VERSION 5.8 ;
BUSBITCHARS "[]" ;
DIVIDERCHAR "/" ;
UNITS
    DATABASE MICRONS 1000 ;
END UNITS

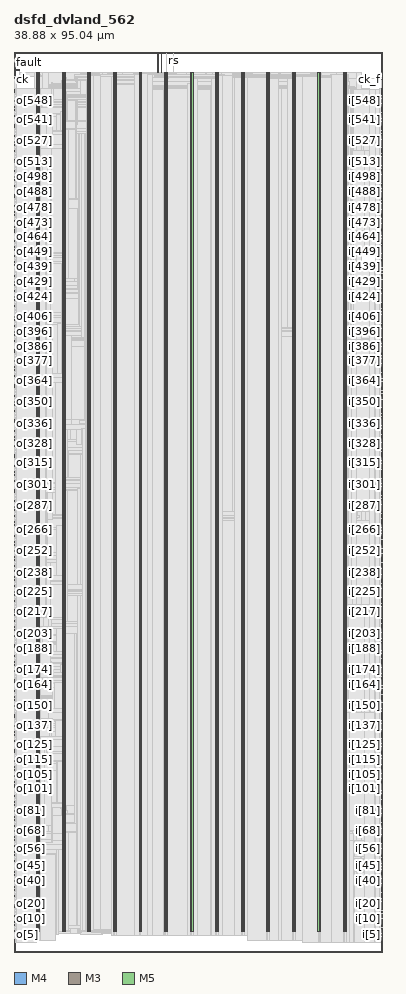
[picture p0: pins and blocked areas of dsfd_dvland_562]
MACRO dsfd_dvland_562
  FOREIGN dsfd_dvland_562 0 0 ;
  CLASS BLOCK ;
  SIZE 38.88 BY 95.04 ;
  PIN ck
    DIRECTION INPUT ;
    USE SIGNAL ;
    PORT
      LAYER M4 ;
        RECT  0 92.112 0.084 92.136 ;
    END
  END ck
  PIN ck_f
    DIRECTION INPUT ;
    USE SIGNAL ;
    PORT
      LAYER M4 ;
        RECT  38.796 92.112 38.88 92.136 ;
    END
  END ck_f
  PIN fault
    DIRECTION OUTPUT ;
    USE SIGNAL ;
    PORT
      LAYER M4 ;
        RECT  0 93.12 0.084 93.144 ;
    END
    PORT
      LAYER M4 ;
        RECT  0.06 93.12 0.569 93.144 ;
    END
  END fault
  PIN i[0]
    DIRECTION INPUT ;
    USE SIGNAL ;
    PORT
      LAYER M4 ;
        RECT  38.796 1.056 38.88 1.08 ;
    END
  END i[0]
  PIN i[100]
    DIRECTION INPUT ;
    USE SIGNAL ;
    PORT
      LAYER M4 ;
        RECT  38.796 17.136 38.88 17.16 ;
    END
  END i[100]
  PIN i[101]
    DIRECTION INPUT ;
    USE SIGNAL ;
    PORT
      LAYER M4 ;
        RECT  38.796 17.28 38.88 17.304 ;
    END
  END i[101]
  PIN i[102]
    DIRECTION INPUT ;
    USE SIGNAL ;
    PORT
      LAYER M4 ;
        RECT  38.796 17.424 38.88 17.448 ;
    END
  END i[102]
  PIN i[103]
    DIRECTION INPUT ;
    USE SIGNAL ;
    PORT
      LAYER M4 ;
        RECT  38.796 17.616 38.88 17.64 ;
    END
  END i[103]
  PIN i[104]
    DIRECTION INPUT ;
    USE SIGNAL ;
    PORT
      LAYER M4 ;
        RECT  38.796 17.76 38.88 17.784 ;
    END
  END i[104]
  PIN i[105]
    DIRECTION INPUT ;
    USE SIGNAL ;
    PORT
      LAYER M4 ;
        RECT  38.796 17.952 38.88 17.976 ;
    END
  END i[105]
  PIN i[106]
    DIRECTION INPUT ;
    USE SIGNAL ;
    PORT
      LAYER M4 ;
        RECT  38.796 18.096 38.88 18.12 ;
    END
  END i[106]
  PIN i[107]
    DIRECTION INPUT ;
    USE SIGNAL ;
    PORT
      LAYER M4 ;
        RECT  38.796 18.24 38.88 18.264 ;
    END
  END i[107]
  PIN i[108]
    DIRECTION INPUT ;
    USE SIGNAL ;
    PORT
      LAYER M4 ;
        RECT  38.796 18.432 38.88 18.456 ;
    END
  END i[108]
  PIN i[109]
    DIRECTION INPUT ;
    USE SIGNAL ;
    PORT
      LAYER M4 ;
        RECT  38.796 18.576 38.88 18.6 ;
    END
  END i[109]
  PIN i[10]
    DIRECTION INPUT ;
    USE SIGNAL ;
    PORT
      LAYER M4 ;
        RECT  38.796 2.688 38.88 2.712 ;
    END
  END i[10]
  PIN i[110]
    DIRECTION INPUT ;
    USE SIGNAL ;
    PORT
      LAYER M4 ;
        RECT  38.796 18.72 38.88 18.744 ;
    END
  END i[110]
  PIN i[111]
    DIRECTION INPUT ;
    USE SIGNAL ;
    PORT
      LAYER M4 ;
        RECT  38.796 18.912 38.88 18.936 ;
    END
  END i[111]
  PIN i[112]
    DIRECTION INPUT ;
    USE SIGNAL ;
    PORT
      LAYER M4 ;
        RECT  38.796 19.056 38.88 19.08 ;
    END
  END i[112]
  PIN i[113]
    DIRECTION INPUT ;
    USE SIGNAL ;
    PORT
      LAYER M4 ;
        RECT  38.796 19.2 38.88 19.224 ;
    END
  END i[113]
  PIN i[114]
    DIRECTION INPUT ;
    USE SIGNAL ;
    PORT
      LAYER M4 ;
        RECT  38.796 19.392 38.88 19.416 ;
    END
  END i[114]
  PIN i[115]
    DIRECTION INPUT ;
    USE SIGNAL ;
    PORT
      LAYER M4 ;
        RECT  38.796 19.536 38.88 19.56 ;
    END
  END i[115]
  PIN i[116]
    DIRECTION INPUT ;
    USE SIGNAL ;
    PORT
      LAYER M4 ;
        RECT  38.796 19.68 38.88 19.704 ;
    END
  END i[116]
  PIN i[117]
    DIRECTION INPUT ;
    USE SIGNAL ;
    PORT
      LAYER M4 ;
        RECT  38.796 19.872 38.88 19.896 ;
    END
  END i[117]
  PIN i[118]
    DIRECTION INPUT ;
    USE SIGNAL ;
    PORT
      LAYER M4 ;
        RECT  38.796 20.016 38.88 20.04 ;
    END
  END i[118]
  PIN i[119]
    DIRECTION INPUT ;
    USE SIGNAL ;
    PORT
      LAYER M4 ;
        RECT  38.796 20.16 38.88 20.184 ;
    END
  END i[119]
  PIN i[11]
    DIRECTION INPUT ;
    USE SIGNAL ;
    PORT
      LAYER M4 ;
        RECT  38.796 2.832 38.88 2.856 ;
    END
  END i[11]
  PIN i[120]
    DIRECTION INPUT ;
    USE SIGNAL ;
    PORT
      LAYER M4 ;
        RECT  38.796 20.352 38.88 20.376 ;
    END
  END i[120]
  PIN i[121]
    DIRECTION INPUT ;
    USE SIGNAL ;
    PORT
      LAYER M4 ;
        RECT  38.796 20.496 38.88 20.52 ;
    END
  END i[121]
  PIN i[122]
    DIRECTION INPUT ;
    USE SIGNAL ;
    PORT
      LAYER M4 ;
        RECT  38.796 20.64 38.88 20.664 ;
    END
  END i[122]
  PIN i[123]
    DIRECTION INPUT ;
    USE SIGNAL ;
    PORT
      LAYER M4 ;
        RECT  38.796 20.832 38.88 20.856 ;
    END
  END i[123]
  PIN i[124]
    DIRECTION INPUT ;
    USE SIGNAL ;
    PORT
      LAYER M4 ;
        RECT  38.796 20.976 38.88 21 ;
    END
  END i[124]
  PIN i[125]
    DIRECTION INPUT ;
    USE SIGNAL ;
    PORT
      LAYER M4 ;
        RECT  38.796 21.12 38.88 21.144 ;
    END
  END i[125]
  PIN i[126]
    DIRECTION INPUT ;
    USE SIGNAL ;
    PORT
      LAYER M4 ;
        RECT  38.796 21.312 38.88 21.336 ;
    END
  END i[126]
  PIN i[127]
    DIRECTION INPUT ;
    USE SIGNAL ;
    PORT
      LAYER M4 ;
        RECT  38.796 21.456 38.88 21.48 ;
    END
  END i[127]
  PIN i[128]
    DIRECTION INPUT ;
    USE SIGNAL ;
    PORT
      LAYER M4 ;
        RECT  38.796 21.6 38.88 21.624 ;
    END
  END i[128]
  PIN i[129]
    DIRECTION INPUT ;
    USE SIGNAL ;
    PORT
      LAYER M4 ;
        RECT  38.796 21.792 38.88 21.816 ;
    END
  END i[129]
  PIN i[12]
    DIRECTION INPUT ;
    USE SIGNAL ;
    PORT
      LAYER M4 ;
        RECT  38.796 2.976 38.88 3 ;
    END
  END i[12]
  PIN i[130]
    DIRECTION INPUT ;
    USE SIGNAL ;
    PORT
      LAYER M4 ;
        RECT  38.796 21.936 38.88 21.96 ;
    END
  END i[130]
  PIN i[131]
    DIRECTION INPUT ;
    USE SIGNAL ;
    PORT
      LAYER M4 ;
        RECT  38.796 22.08 38.88 22.104 ;
    END
  END i[131]
  PIN i[132]
    DIRECTION INPUT ;
    USE SIGNAL ;
    PORT
      LAYER M4 ;
        RECT  38.796 22.272 38.88 22.296 ;
    END
  END i[132]
  PIN i[133]
    DIRECTION INPUT ;
    USE SIGNAL ;
    PORT
      LAYER M4 ;
        RECT  38.796 22.416 38.88 22.44 ;
    END
  END i[133]
  PIN i[134]
    DIRECTION INPUT ;
    USE SIGNAL ;
    PORT
      LAYER M4 ;
        RECT  38.796 22.608 38.88 22.632 ;
    END
  END i[134]
  PIN i[135]
    DIRECTION INPUT ;
    USE SIGNAL ;
    PORT
      LAYER M4 ;
        RECT  38.796 22.752 38.88 22.776 ;
    END
  END i[135]
  PIN i[136]
    DIRECTION INPUT ;
    USE SIGNAL ;
    PORT
      LAYER M4 ;
        RECT  38.796 22.896 38.88 22.92 ;
    END
  END i[136]
  PIN i[137]
    DIRECTION INPUT ;
    USE SIGNAL ;
    PORT
      LAYER M4 ;
        RECT  38.796 23.088 38.88 23.112 ;
    END
  END i[137]
  PIN i[138]
    DIRECTION INPUT ;
    USE SIGNAL ;
    PORT
      LAYER M4 ;
        RECT  38.796 23.232 38.88 23.256 ;
    END
  END i[138]
  PIN i[139]
    DIRECTION INPUT ;
    USE SIGNAL ;
    PORT
      LAYER M4 ;
        RECT  38.796 23.376 38.88 23.4 ;
    END
  END i[139]
  PIN i[13]
    DIRECTION INPUT ;
    USE SIGNAL ;
    PORT
      LAYER M4 ;
        RECT  38.796 3.168 38.88 3.192 ;
    END
  END i[13]
  PIN i[140]
    DIRECTION INPUT ;
    USE SIGNAL ;
    PORT
      LAYER M4 ;
        RECT  38.796 23.568 38.88 23.592 ;
    END
  END i[140]
  PIN i[141]
    DIRECTION INPUT ;
    USE SIGNAL ;
    PORT
      LAYER M4 ;
        RECT  38.796 23.712 38.88 23.736 ;
    END
  END i[141]
  PIN i[142]
    DIRECTION INPUT ;
    USE SIGNAL ;
    PORT
      LAYER M4 ;
        RECT  38.796 23.856 38.88 23.88 ;
    END
  END i[142]
  PIN i[143]
    DIRECTION INPUT ;
    USE SIGNAL ;
    PORT
      LAYER M4 ;
        RECT  38.796 24.048 38.88 24.072 ;
    END
  END i[143]
  PIN i[144]
    DIRECTION INPUT ;
    USE SIGNAL ;
    PORT
      LAYER M4 ;
        RECT  38.796 24.192 38.88 24.216 ;
    END
  END i[144]
  PIN i[145]
    DIRECTION INPUT ;
    USE SIGNAL ;
    PORT
      LAYER M4 ;
        RECT  38.796 24.336 38.88 24.36 ;
    END
  END i[145]
  PIN i[146]
    DIRECTION INPUT ;
    USE SIGNAL ;
    PORT
      LAYER M4 ;
        RECT  38.796 24.528 38.88 24.552 ;
    END
  END i[146]
  PIN i[147]
    DIRECTION INPUT ;
    USE SIGNAL ;
    PORT
      LAYER M4 ;
        RECT  38.796 24.672 38.88 24.696 ;
    END
  END i[147]
  PIN i[148]
    DIRECTION INPUT ;
    USE SIGNAL ;
    PORT
      LAYER M4 ;
        RECT  38.796 24.816 38.88 24.84 ;
    END
  END i[148]
  PIN i[149]
    DIRECTION INPUT ;
    USE SIGNAL ;
    PORT
      LAYER M4 ;
        RECT  38.796 25.008 38.88 25.032 ;
    END
  END i[149]
  PIN i[14]
    DIRECTION INPUT ;
    USE SIGNAL ;
    PORT
      LAYER M4 ;
        RECT  38.796 3.312 38.88 3.336 ;
    END
  END i[14]
  PIN i[150]
    DIRECTION INPUT ;
    USE SIGNAL ;
    PORT
      LAYER M4 ;
        RECT  38.796 25.152 38.88 25.176 ;
    END
  END i[150]
  PIN i[151]
    DIRECTION INPUT ;
    USE SIGNAL ;
    PORT
      LAYER M4 ;
        RECT  38.796 25.296 38.88 25.32 ;
    END
  END i[151]
  PIN i[152]
    DIRECTION INPUT ;
    USE SIGNAL ;
    PORT
      LAYER M4 ;
        RECT  38.796 25.488 38.88 25.512 ;
    END
  END i[152]
  PIN i[153]
    DIRECTION INPUT ;
    USE SIGNAL ;
    PORT
      LAYER M4 ;
        RECT  38.796 25.632 38.88 25.656 ;
    END
  END i[153]
  PIN i[154]
    DIRECTION INPUT ;
    USE SIGNAL ;
    PORT
      LAYER M4 ;
        RECT  38.796 25.776 38.88 25.8 ;
    END
  END i[154]
  PIN i[155]
    DIRECTION INPUT ;
    USE SIGNAL ;
    PORT
      LAYER M4 ;
        RECT  38.796 25.968 38.88 25.992 ;
    END
  END i[155]
  PIN i[156]
    DIRECTION INPUT ;
    USE SIGNAL ;
    PORT
      LAYER M4 ;
        RECT  38.796 26.112 38.88 26.136 ;
    END
  END i[156]
  PIN i[157]
    DIRECTION INPUT ;
    USE SIGNAL ;
    PORT
      LAYER M4 ;
        RECT  38.796 26.256 38.88 26.28 ;
    END
  END i[157]
  PIN i[158]
    DIRECTION INPUT ;
    USE SIGNAL ;
    PORT
      LAYER M4 ;
        RECT  38.796 26.448 38.88 26.472 ;
    END
  END i[158]
  PIN i[159]
    DIRECTION INPUT ;
    USE SIGNAL ;
    PORT
      LAYER M4 ;
        RECT  38.796 26.592 38.88 26.616 ;
    END
  END i[159]
  PIN i[15]
    DIRECTION INPUT ;
    USE SIGNAL ;
    PORT
      LAYER M4 ;
        RECT  38.796 3.456 38.88 3.48 ;
    END
  END i[15]
  PIN i[160]
    DIRECTION INPUT ;
    USE SIGNAL ;
    PORT
      LAYER M4 ;
        RECT  38.796 26.736 38.88 26.76 ;
    END
  END i[160]
  PIN i[161]
    DIRECTION INPUT ;
    USE SIGNAL ;
    PORT
      LAYER M4 ;
        RECT  38.796 26.928 38.88 26.952 ;
    END
  END i[161]
  PIN i[162]
    DIRECTION INPUT ;
    USE SIGNAL ;
    PORT
      LAYER M4 ;
        RECT  38.796 27.072 38.88 27.096 ;
    END
  END i[162]
  PIN i[163]
    DIRECTION INPUT ;
    USE SIGNAL ;
    PORT
      LAYER M4 ;
        RECT  38.796 27.264 38.88 27.288 ;
    END
  END i[163]
  PIN i[164]
    DIRECTION INPUT ;
    USE SIGNAL ;
    PORT
      LAYER M4 ;
        RECT  38.796 27.408 38.88 27.432 ;
    END
  END i[164]
  PIN i[165]
    DIRECTION INPUT ;
    USE SIGNAL ;
    PORT
      LAYER M4 ;
        RECT  38.796 27.552 38.88 27.576 ;
    END
  END i[165]
  PIN i[166]
    DIRECTION INPUT ;
    USE SIGNAL ;
    PORT
      LAYER M4 ;
        RECT  38.796 27.744 38.88 27.768 ;
    END
  END i[166]
  PIN i[167]
    DIRECTION INPUT ;
    USE SIGNAL ;
    PORT
      LAYER M4 ;
        RECT  38.796 27.888 38.88 27.912 ;
    END
  END i[167]
  PIN i[168]
    DIRECTION INPUT ;
    USE SIGNAL ;
    PORT
      LAYER M4 ;
        RECT  38.796 28.032 38.88 28.056 ;
    END
  END i[168]
  PIN i[169]
    DIRECTION INPUT ;
    USE SIGNAL ;
    PORT
      LAYER M4 ;
        RECT  38.796 28.224 38.88 28.248 ;
    END
  END i[169]
  PIN i[16]
    DIRECTION INPUT ;
    USE SIGNAL ;
    PORT
      LAYER M4 ;
        RECT  38.796 3.648 38.88 3.672 ;
    END
  END i[16]
  PIN i[170]
    DIRECTION INPUT ;
    USE SIGNAL ;
    PORT
      LAYER M4 ;
        RECT  38.796 28.368 38.88 28.392 ;
    END
  END i[170]
  PIN i[171]
    DIRECTION INPUT ;
    USE SIGNAL ;
    PORT
      LAYER M4 ;
        RECT  38.796 28.512 38.88 28.536 ;
    END
  END i[171]
  PIN i[172]
    DIRECTION INPUT ;
    USE SIGNAL ;
    PORT
      LAYER M4 ;
        RECT  38.796 28.704 38.88 28.728 ;
    END
  END i[172]
  PIN i[173]
    DIRECTION INPUT ;
    USE SIGNAL ;
    PORT
      LAYER M4 ;
        RECT  38.796 28.848 38.88 28.872 ;
    END
  END i[173]
  PIN i[174]
    DIRECTION INPUT ;
    USE SIGNAL ;
    PORT
      LAYER M4 ;
        RECT  38.796 28.992 38.88 29.016 ;
    END
  END i[174]
  PIN i[175]
    DIRECTION INPUT ;
    USE SIGNAL ;
    PORT
      LAYER M4 ;
        RECT  38.796 29.184 38.88 29.208 ;
    END
  END i[175]
  PIN i[176]
    DIRECTION INPUT ;
    USE SIGNAL ;
    PORT
      LAYER M4 ;
        RECT  38.796 29.328 38.88 29.352 ;
    END
  END i[176]
  PIN i[177]
    DIRECTION INPUT ;
    USE SIGNAL ;
    PORT
      LAYER M4 ;
        RECT  38.796 29.472 38.88 29.496 ;
    END
  END i[177]
  PIN i[178]
    DIRECTION INPUT ;
    USE SIGNAL ;
    PORT
      LAYER M4 ;
        RECT  38.796 29.664 38.88 29.688 ;
    END
  END i[178]
  PIN i[179]
    DIRECTION INPUT ;
    USE SIGNAL ;
    PORT
      LAYER M4 ;
        RECT  38.796 29.808 38.88 29.832 ;
    END
  END i[179]
  PIN i[17]
    DIRECTION INPUT ;
    USE SIGNAL ;
    PORT
      LAYER M4 ;
        RECT  38.796 3.792 38.88 3.816 ;
    END
  END i[17]
  PIN i[180]
    DIRECTION INPUT ;
    USE SIGNAL ;
    PORT
      LAYER M4 ;
        RECT  38.796 29.952 38.88 29.976 ;
    END
  END i[180]
  PIN i[181]
    DIRECTION INPUT ;
    USE SIGNAL ;
    PORT
      LAYER M4 ;
        RECT  38.796 30.144 38.88 30.168 ;
    END
  END i[181]
  PIN i[182]
    DIRECTION INPUT ;
    USE SIGNAL ;
    PORT
      LAYER M4 ;
        RECT  38.796 30.288 38.88 30.312 ;
    END
  END i[182]
  PIN i[183]
    DIRECTION INPUT ;
    USE SIGNAL ;
    PORT
      LAYER M4 ;
        RECT  38.796 30.432 38.88 30.456 ;
    END
  END i[183]
  PIN i[184]
    DIRECTION INPUT ;
    USE SIGNAL ;
    PORT
      LAYER M4 ;
        RECT  38.796 30.624 38.88 30.648 ;
    END
  END i[184]
  PIN i[185]
    DIRECTION INPUT ;
    USE SIGNAL ;
    PORT
      LAYER M4 ;
        RECT  38.796 30.768 38.88 30.792 ;
    END
  END i[185]
  PIN i[186]
    DIRECTION INPUT ;
    USE SIGNAL ;
    PORT
      LAYER M4 ;
        RECT  38.796 30.912 38.88 30.936 ;
    END
  END i[186]
  PIN i[187]
    DIRECTION INPUT ;
    USE SIGNAL ;
    PORT
      LAYER M4 ;
        RECT  38.796 31.104 38.88 31.128 ;
    END
  END i[187]
  PIN i[188]
    DIRECTION INPUT ;
    USE SIGNAL ;
    PORT
      LAYER M4 ;
        RECT  38.796 31.248 38.88 31.272 ;
    END
  END i[188]
  PIN i[189]
    DIRECTION INPUT ;
    USE SIGNAL ;
    PORT
      LAYER M4 ;
        RECT  38.796 31.44 38.88 31.464 ;
    END
  END i[189]
  PIN i[18]
    DIRECTION INPUT ;
    USE SIGNAL ;
    PORT
      LAYER M4 ;
        RECT  38.796 3.936 38.88 3.96 ;
    END
  END i[18]
  PIN i[190]
    DIRECTION INPUT ;
    USE SIGNAL ;
    PORT
      LAYER M4 ;
        RECT  38.796 31.584 38.88 31.608 ;
    END
  END i[190]
  PIN i[191]
    DIRECTION INPUT ;
    USE SIGNAL ;
    PORT
      LAYER M4 ;
        RECT  38.796 31.728 38.88 31.752 ;
    END
  END i[191]
  PIN i[192]
    DIRECTION INPUT ;
    USE SIGNAL ;
    PORT
      LAYER M4 ;
        RECT  38.796 31.92 38.88 31.944 ;
    END
  END i[192]
  PIN i[193]
    DIRECTION INPUT ;
    USE SIGNAL ;
    PORT
      LAYER M4 ;
        RECT  38.796 32.064 38.88 32.088 ;
    END
  END i[193]
  PIN i[194]
    DIRECTION INPUT ;
    USE SIGNAL ;
    PORT
      LAYER M4 ;
        RECT  38.796 32.208 38.88 32.232 ;
    END
  END i[194]
  PIN i[195]
    DIRECTION INPUT ;
    USE SIGNAL ;
    PORT
      LAYER M4 ;
        RECT  38.796 32.4 38.88 32.424 ;
    END
  END i[195]
  PIN i[196]
    DIRECTION INPUT ;
    USE SIGNAL ;
    PORT
      LAYER M4 ;
        RECT  38.796 32.544 38.88 32.568 ;
    END
  END i[196]
  PIN i[197]
    DIRECTION INPUT ;
    USE SIGNAL ;
    PORT
      LAYER M4 ;
        RECT  38.796 32.688 38.88 32.712 ;
    END
  END i[197]
  PIN i[198]
    DIRECTION INPUT ;
    USE SIGNAL ;
    PORT
      LAYER M4 ;
        RECT  38.796 32.88 38.88 32.904 ;
    END
  END i[198]
  PIN i[199]
    DIRECTION INPUT ;
    USE SIGNAL ;
    PORT
      LAYER M4 ;
        RECT  38.796 33.024 38.88 33.048 ;
    END
  END i[199]
  PIN i[19]
    DIRECTION INPUT ;
    USE SIGNAL ;
    PORT
      LAYER M4 ;
        RECT  38.796 4.128 38.88 4.152 ;
    END
  END i[19]
  PIN i[1]
    DIRECTION INPUT ;
    USE SIGNAL ;
    PORT
      LAYER M4 ;
        RECT  38.796 1.248 38.88 1.272 ;
    END
  END i[1]
  PIN i[200]
    DIRECTION INPUT ;
    USE SIGNAL ;
    PORT
      LAYER M4 ;
        RECT  38.796 33.168 38.88 33.192 ;
    END
  END i[200]
  PIN i[201]
    DIRECTION INPUT ;
    USE SIGNAL ;
    PORT
      LAYER M4 ;
        RECT  38.796 33.36 38.88 33.384 ;
    END
  END i[201]
  PIN i[202]
    DIRECTION INPUT ;
    USE SIGNAL ;
    PORT
      LAYER M4 ;
        RECT  38.796 33.504 38.88 33.528 ;
    END
  END i[202]
  PIN i[203]
    DIRECTION INPUT ;
    USE SIGNAL ;
    PORT
      LAYER M4 ;
        RECT  38.796 33.648 38.88 33.672 ;
    END
  END i[203]
  PIN i[204]
    DIRECTION INPUT ;
    USE SIGNAL ;
    PORT
      LAYER M4 ;
        RECT  38.796 33.84 38.88 33.864 ;
    END
  END i[204]
  PIN i[205]
    DIRECTION INPUT ;
    USE SIGNAL ;
    PORT
      LAYER M4 ;
        RECT  38.796 33.984 38.88 34.008 ;
    END
  END i[205]
  PIN i[206]
    DIRECTION INPUT ;
    USE SIGNAL ;
    PORT
      LAYER M4 ;
        RECT  38.796 34.128 38.88 34.152 ;
    END
  END i[206]
  PIN i[207]
    DIRECTION INPUT ;
    USE SIGNAL ;
    PORT
      LAYER M4 ;
        RECT  38.796 34.32 38.88 34.344 ;
    END
  END i[207]
  PIN i[208]
    DIRECTION INPUT ;
    USE SIGNAL ;
    PORT
      LAYER M4 ;
        RECT  38.796 34.464 38.88 34.488 ;
    END
  END i[208]
  PIN i[209]
    DIRECTION INPUT ;
    USE SIGNAL ;
    PORT
      LAYER M4 ;
        RECT  38.796 34.608 38.88 34.632 ;
    END
  END i[209]
  PIN i[20]
    DIRECTION INPUT ;
    USE SIGNAL ;
    PORT
      LAYER M4 ;
        RECT  38.796 4.272 38.88 4.296 ;
    END
  END i[20]
  PIN i[210]
    DIRECTION INPUT ;
    USE SIGNAL ;
    PORT
      LAYER M4 ;
        RECT  38.796 34.8 38.88 34.824 ;
    END
  END i[210]
  PIN i[211]
    DIRECTION INPUT ;
    USE SIGNAL ;
    PORT
      LAYER M4 ;
        RECT  38.796 34.944 38.88 34.968 ;
    END
  END i[211]
  PIN i[212]
    DIRECTION INPUT ;
    USE SIGNAL ;
    PORT
      LAYER M4 ;
        RECT  38.796 35.088 38.88 35.112 ;
    END
  END i[212]
  PIN i[213]
    DIRECTION INPUT ;
    USE SIGNAL ;
    PORT
      LAYER M4 ;
        RECT  38.796 35.28 38.88 35.304 ;
    END
  END i[213]
  PIN i[214]
    DIRECTION INPUT ;
    USE SIGNAL ;
    PORT
      LAYER M4 ;
        RECT  38.796 35.424 38.88 35.448 ;
    END
  END i[214]
  PIN i[215]
    DIRECTION INPUT ;
    USE SIGNAL ;
    PORT
      LAYER M4 ;
        RECT  38.796 35.568 38.88 35.592 ;
    END
  END i[215]
  PIN i[216]
    DIRECTION INPUT ;
    USE SIGNAL ;
    PORT
      LAYER M4 ;
        RECT  38.796 35.76 38.88 35.784 ;
    END
  END i[216]
  PIN i[217]
    DIRECTION INPUT ;
    USE SIGNAL ;
    PORT
      LAYER M4 ;
        RECT  38.796 35.904 38.88 35.928 ;
    END
  END i[217]
  PIN i[218]
    DIRECTION INPUT ;
    USE SIGNAL ;
    PORT
      LAYER M4 ;
        RECT  38.796 36.096 38.88 36.12 ;
    END
  END i[218]
  PIN i[219]
    DIRECTION INPUT ;
    USE SIGNAL ;
    PORT
      LAYER M4 ;
        RECT  38.796 36.24 38.88 36.264 ;
    END
  END i[219]
  PIN i[21]
    DIRECTION INPUT ;
    USE SIGNAL ;
    PORT
      LAYER M4 ;
        RECT  38.796 4.464 38.88 4.488 ;
    END
  END i[21]
  PIN i[220]
    DIRECTION INPUT ;
    USE SIGNAL ;
    PORT
      LAYER M4 ;
        RECT  38.796 36.384 38.88 36.408 ;
    END
  END i[220]
  PIN i[221]
    DIRECTION INPUT ;
    USE SIGNAL ;
    PORT
      LAYER M4 ;
        RECT  38.796 36.576 38.88 36.6 ;
    END
  END i[221]
  PIN i[222]
    DIRECTION INPUT ;
    USE SIGNAL ;
    PORT
      LAYER M4 ;
        RECT  38.796 36.72 38.88 36.744 ;
    END
  END i[222]
  PIN i[223]
    DIRECTION INPUT ;
    USE SIGNAL ;
    PORT
      LAYER M4 ;
        RECT  38.796 36.864 38.88 36.888 ;
    END
  END i[223]
  PIN i[224]
    DIRECTION INPUT ;
    USE SIGNAL ;
    PORT
      LAYER M4 ;
        RECT  38.796 37.056 38.88 37.08 ;
    END
  END i[224]
  PIN i[225]
    DIRECTION INPUT ;
    USE SIGNAL ;
    PORT
      LAYER M4 ;
        RECT  38.796 37.2 38.88 37.224 ;
    END
  END i[225]
  PIN i[226]
    DIRECTION INPUT ;
    USE SIGNAL ;
    PORT
      LAYER M4 ;
        RECT  38.796 37.344 38.88 37.368 ;
    END
  END i[226]
  PIN i[227]
    DIRECTION INPUT ;
    USE SIGNAL ;
    PORT
      LAYER M4 ;
        RECT  38.796 37.536 38.88 37.56 ;
    END
  END i[227]
  PIN i[228]
    DIRECTION INPUT ;
    USE SIGNAL ;
    PORT
      LAYER M4 ;
        RECT  38.796 37.68 38.88 37.704 ;
    END
  END i[228]
  PIN i[229]
    DIRECTION INPUT ;
    USE SIGNAL ;
    PORT
      LAYER M4 ;
        RECT  38.796 37.824 38.88 37.848 ;
    END
  END i[229]
  PIN i[22]
    DIRECTION INPUT ;
    USE SIGNAL ;
    PORT
      LAYER M4 ;
        RECT  38.796 4.608 38.88 4.632 ;
    END
  END i[22]
  PIN i[230]
    DIRECTION INPUT ;
    USE SIGNAL ;
    PORT
      LAYER M4 ;
        RECT  38.796 38.016 38.88 38.04 ;
    END
  END i[230]
  PIN i[231]
    DIRECTION INPUT ;
    USE SIGNAL ;
    PORT
      LAYER M4 ;
        RECT  38.796 38.16 38.88 38.184 ;
    END
  END i[231]
  PIN i[232]
    DIRECTION INPUT ;
    USE SIGNAL ;
    PORT
      LAYER M4 ;
        RECT  38.796 38.304 38.88 38.328 ;
    END
  END i[232]
  PIN i[233]
    DIRECTION INPUT ;
    USE SIGNAL ;
    PORT
      LAYER M4 ;
        RECT  38.796 38.496 38.88 38.52 ;
    END
  END i[233]
  PIN i[234]
    DIRECTION INPUT ;
    USE SIGNAL ;
    PORT
      LAYER M4 ;
        RECT  38.796 38.64 38.88 38.664 ;
    END
  END i[234]
  PIN i[235]
    DIRECTION INPUT ;
    USE SIGNAL ;
    PORT
      LAYER M4 ;
        RECT  38.796 38.784 38.88 38.808 ;
    END
  END i[235]
  PIN i[236]
    DIRECTION INPUT ;
    USE SIGNAL ;
    PORT
      LAYER M4 ;
        RECT  38.796 38.976 38.88 39 ;
    END
  END i[236]
  PIN i[237]
    DIRECTION INPUT ;
    USE SIGNAL ;
    PORT
      LAYER M4 ;
        RECT  38.796 39.12 38.88 39.144 ;
    END
  END i[237]
  PIN i[238]
    DIRECTION INPUT ;
    USE SIGNAL ;
    PORT
      LAYER M4 ;
        RECT  38.796 39.264 38.88 39.288 ;
    END
  END i[238]
  PIN i[239]
    DIRECTION INPUT ;
    USE SIGNAL ;
    PORT
      LAYER M4 ;
        RECT  38.796 39.456 38.88 39.48 ;
    END
  END i[239]
  PIN i[23]
    DIRECTION INPUT ;
    USE SIGNAL ;
    PORT
      LAYER M4 ;
        RECT  38.796 4.752 38.88 4.776 ;
    END
  END i[23]
  PIN i[240]
    DIRECTION INPUT ;
    USE SIGNAL ;
    PORT
      LAYER M4 ;
        RECT  38.796 39.6 38.88 39.624 ;
    END
  END i[240]
  PIN i[241]
    DIRECTION INPUT ;
    USE SIGNAL ;
    PORT
      LAYER M4 ;
        RECT  38.796 39.744 38.88 39.768 ;
    END
  END i[241]
  PIN i[242]
    DIRECTION INPUT ;
    USE SIGNAL ;
    PORT
      LAYER M4 ;
        RECT  38.796 39.936 38.88 39.96 ;
    END
  END i[242]
  PIN i[243]
    DIRECTION INPUT ;
    USE SIGNAL ;
    PORT
      LAYER M4 ;
        RECT  38.796 40.08 38.88 40.104 ;
    END
  END i[243]
  PIN i[244]
    DIRECTION INPUT ;
    USE SIGNAL ;
    PORT
      LAYER M4 ;
        RECT  38.796 40.224 38.88 40.248 ;
    END
  END i[244]
  PIN i[245]
    DIRECTION INPUT ;
    USE SIGNAL ;
    PORT
      LAYER M4 ;
        RECT  38.796 40.416 38.88 40.44 ;
    END
  END i[245]
  PIN i[246]
    DIRECTION INPUT ;
    USE SIGNAL ;
    PORT
      LAYER M4 ;
        RECT  38.796 40.56 38.88 40.584 ;
    END
  END i[246]
  PIN i[247]
    DIRECTION INPUT ;
    USE SIGNAL ;
    PORT
      LAYER M4 ;
        RECT  38.796 40.752 38.88 40.776 ;
    END
  END i[247]
  PIN i[248]
    DIRECTION INPUT ;
    USE SIGNAL ;
    PORT
      LAYER M4 ;
        RECT  38.796 40.896 38.88 40.92 ;
    END
  END i[248]
  PIN i[249]
    DIRECTION INPUT ;
    USE SIGNAL ;
    PORT
      LAYER M4 ;
        RECT  38.796 41.04 38.88 41.064 ;
    END
  END i[249]
  PIN i[24]
    DIRECTION INPUT ;
    USE SIGNAL ;
    PORT
      LAYER M4 ;
        RECT  38.796 4.944 38.88 4.968 ;
    END
  END i[24]
  PIN i[250]
    DIRECTION INPUT ;
    USE SIGNAL ;
    PORT
      LAYER M4 ;
        RECT  38.796 41.232 38.88 41.256 ;
    END
  END i[250]
  PIN i[251]
    DIRECTION INPUT ;
    USE SIGNAL ;
    PORT
      LAYER M4 ;
        RECT  38.796 41.376 38.88 41.4 ;
    END
  END i[251]
  PIN i[252]
    DIRECTION INPUT ;
    USE SIGNAL ;
    PORT
      LAYER M4 ;
        RECT  38.796 41.52 38.88 41.544 ;
    END
  END i[252]
  PIN i[253]
    DIRECTION INPUT ;
    USE SIGNAL ;
    PORT
      LAYER M4 ;
        RECT  38.796 41.712 38.88 41.736 ;
    END
  END i[253]
  PIN i[254]
    DIRECTION INPUT ;
    USE SIGNAL ;
    PORT
      LAYER M4 ;
        RECT  38.796 41.856 38.88 41.88 ;
    END
  END i[254]
  PIN i[255]
    DIRECTION INPUT ;
    USE SIGNAL ;
    PORT
      LAYER M4 ;
        RECT  38.796 42 38.88 42.024 ;
    END
  END i[255]
  PIN i[256]
    DIRECTION INPUT ;
    USE SIGNAL ;
    PORT
      LAYER M4 ;
        RECT  38.796 42.192 38.88 42.216 ;
    END
  END i[256]
  PIN i[257]
    DIRECTION INPUT ;
    USE SIGNAL ;
    PORT
      LAYER M4 ;
        RECT  38.796 42.336 38.88 42.36 ;
    END
  END i[257]
  PIN i[258]
    DIRECTION INPUT ;
    USE SIGNAL ;
    PORT
      LAYER M4 ;
        RECT  38.796 42.48 38.88 42.504 ;
    END
  END i[258]
  PIN i[259]
    DIRECTION INPUT ;
    USE SIGNAL ;
    PORT
      LAYER M4 ;
        RECT  38.796 42.672 38.88 42.696 ;
    END
  END i[259]
  PIN i[25]
    DIRECTION INPUT ;
    USE SIGNAL ;
    PORT
      LAYER M4 ;
        RECT  38.796 5.088 38.88 5.112 ;
    END
  END i[25]
  PIN i[260]
    DIRECTION INPUT ;
    USE SIGNAL ;
    PORT
      LAYER M4 ;
        RECT  38.796 42.816 38.88 42.84 ;
    END
  END i[260]
  PIN i[261]
    DIRECTION INPUT ;
    USE SIGNAL ;
    PORT
      LAYER M4 ;
        RECT  38.796 42.96 38.88 42.984 ;
    END
  END i[261]
  PIN i[262]
    DIRECTION INPUT ;
    USE SIGNAL ;
    PORT
      LAYER M4 ;
        RECT  38.796 43.152 38.88 43.176 ;
    END
  END i[262]
  PIN i[263]
    DIRECTION INPUT ;
    USE SIGNAL ;
    PORT
      LAYER M4 ;
        RECT  38.796 43.296 38.88 43.32 ;
    END
  END i[263]
  PIN i[264]
    DIRECTION INPUT ;
    USE SIGNAL ;
    PORT
      LAYER M4 ;
        RECT  38.796 43.44 38.88 43.464 ;
    END
  END i[264]
  PIN i[265]
    DIRECTION INPUT ;
    USE SIGNAL ;
    PORT
      LAYER M4 ;
        RECT  38.796 43.632 38.88 43.656 ;
    END
  END i[265]
  PIN i[266]
    DIRECTION INPUT ;
    USE SIGNAL ;
    PORT
      LAYER M4 ;
        RECT  38.796 43.776 38.88 43.8 ;
    END
  END i[266]
  PIN i[267]
    DIRECTION INPUT ;
    USE SIGNAL ;
    PORT
      LAYER M4 ;
        RECT  38.796 43.92 38.88 43.944 ;
    END
  END i[267]
  PIN i[268]
    DIRECTION INPUT ;
    USE SIGNAL ;
    PORT
      LAYER M4 ;
        RECT  38.796 44.112 38.88 44.136 ;
    END
  END i[268]
  PIN i[269]
    DIRECTION INPUT ;
    USE SIGNAL ;
    PORT
      LAYER M4 ;
        RECT  38.796 44.256 38.88 44.28 ;
    END
  END i[269]
  PIN i[26]
    DIRECTION INPUT ;
    USE SIGNAL ;
    PORT
      LAYER M4 ;
        RECT  38.796 5.232 38.88 5.256 ;
    END
  END i[26]
  PIN i[270]
    DIRECTION INPUT ;
    USE SIGNAL ;
    PORT
      LAYER M4 ;
        RECT  38.796 44.4 38.88 44.424 ;
    END
  END i[270]
  PIN i[271]
    DIRECTION INPUT ;
    USE SIGNAL ;
    PORT
      LAYER M4 ;
        RECT  38.796 44.592 38.88 44.616 ;
    END
  END i[271]
  PIN i[272]
    DIRECTION INPUT ;
    USE SIGNAL ;
    PORT
      LAYER M4 ;
        RECT  38.796 44.736 38.88 44.76 ;
    END
  END i[272]
  PIN i[273]
    DIRECTION INPUT ;
    USE SIGNAL ;
    PORT
      LAYER M4 ;
        RECT  38.796 44.928 38.88 44.952 ;
    END
  END i[273]
  PIN i[274]
    DIRECTION INPUT ;
    USE SIGNAL ;
    PORT
      LAYER M4 ;
        RECT  38.796 45.072 38.88 45.096 ;
    END
  END i[274]
  PIN i[275]
    DIRECTION INPUT ;
    USE SIGNAL ;
    PORT
      LAYER M4 ;
        RECT  38.796 45.216 38.88 45.24 ;
    END
  END i[275]
  PIN i[276]
    DIRECTION INPUT ;
    USE SIGNAL ;
    PORT
      LAYER M4 ;
        RECT  38.796 45.408 38.88 45.432 ;
    END
  END i[276]
  PIN i[277]
    DIRECTION INPUT ;
    USE SIGNAL ;
    PORT
      LAYER M4 ;
        RECT  38.796 45.552 38.88 45.576 ;
    END
  END i[277]
  PIN i[278]
    DIRECTION INPUT ;
    USE SIGNAL ;
    PORT
      LAYER M4 ;
        RECT  38.796 45.696 38.88 45.72 ;
    END
  END i[278]
  PIN i[279]
    DIRECTION INPUT ;
    USE SIGNAL ;
    PORT
      LAYER M4 ;
        RECT  38.796 45.888 38.88 45.912 ;
    END
  END i[279]
  PIN i[27]
    DIRECTION INPUT ;
    USE SIGNAL ;
    PORT
      LAYER M4 ;
        RECT  38.796 5.424 38.88 5.448 ;
    END
  END i[27]
  PIN i[280]
    DIRECTION INPUT ;
    USE SIGNAL ;
    PORT
      LAYER M4 ;
        RECT  38.796 46.032 38.88 46.056 ;
    END
  END i[280]
  PIN i[281]
    DIRECTION INPUT ;
    USE SIGNAL ;
    PORT
      LAYER M4 ;
        RECT  38.796 46.176 38.88 46.2 ;
    END
  END i[281]
  PIN i[282]
    DIRECTION INPUT ;
    USE SIGNAL ;
    PORT
      LAYER M4 ;
        RECT  38.796 46.368 38.88 46.392 ;
    END
  END i[282]
  PIN i[283]
    DIRECTION INPUT ;
    USE SIGNAL ;
    PORT
      LAYER M4 ;
        RECT  38.796 46.512 38.88 46.536 ;
    END
  END i[283]
  PIN i[284]
    DIRECTION INPUT ;
    USE SIGNAL ;
    PORT
      LAYER M4 ;
        RECT  38.796 46.656 38.88 46.68 ;
    END
  END i[284]
  PIN i[285]
    DIRECTION INPUT ;
    USE SIGNAL ;
    PORT
      LAYER M4 ;
        RECT  38.796 46.848 38.88 46.872 ;
    END
  END i[285]
  PIN i[286]
    DIRECTION INPUT ;
    USE SIGNAL ;
    PORT
      LAYER M4 ;
        RECT  38.796 46.992 38.88 47.016 ;
    END
  END i[286]
  PIN i[287]
    DIRECTION INPUT ;
    USE SIGNAL ;
    PORT
      LAYER M4 ;
        RECT  38.796 47.136 38.88 47.16 ;
    END
  END i[287]
  PIN i[288]
    DIRECTION INPUT ;
    USE SIGNAL ;
    PORT
      LAYER M4 ;
        RECT  38.796 47.328 38.88 47.352 ;
    END
  END i[288]
  PIN i[289]
    DIRECTION INPUT ;
    USE SIGNAL ;
    PORT
      LAYER M4 ;
        RECT  38.796 47.472 38.88 47.496 ;
    END
  END i[289]
  PIN i[28]
    DIRECTION INPUT ;
    USE SIGNAL ;
    PORT
      LAYER M4 ;
        RECT  38.796 5.568 38.88 5.592 ;
    END
  END i[28]
  PIN i[290]
    DIRECTION INPUT ;
    USE SIGNAL ;
    PORT
      LAYER M4 ;
        RECT  38.796 47.616 38.88 47.64 ;
    END
  END i[290]
  PIN i[291]
    DIRECTION INPUT ;
    USE SIGNAL ;
    PORT
      LAYER M4 ;
        RECT  38.796 47.808 38.88 47.832 ;
    END
  END i[291]
  PIN i[292]
    DIRECTION INPUT ;
    USE SIGNAL ;
    PORT
      LAYER M4 ;
        RECT  38.796 47.952 38.88 47.976 ;
    END
  END i[292]
  PIN i[293]
    DIRECTION INPUT ;
    USE SIGNAL ;
    PORT
      LAYER M4 ;
        RECT  38.796 48.096 38.88 48.12 ;
    END
  END i[293]
  PIN i[294]
    DIRECTION INPUT ;
    USE SIGNAL ;
    PORT
      LAYER M4 ;
        RECT  38.796 48.288 38.88 48.312 ;
    END
  END i[294]
  PIN i[295]
    DIRECTION INPUT ;
    USE SIGNAL ;
    PORT
      LAYER M4 ;
        RECT  38.796 48.432 38.88 48.456 ;
    END
  END i[295]
  PIN i[296]
    DIRECTION INPUT ;
    USE SIGNAL ;
    PORT
      LAYER M4 ;
        RECT  38.796 48.576 38.88 48.6 ;
    END
  END i[296]
  PIN i[297]
    DIRECTION INPUT ;
    USE SIGNAL ;
    PORT
      LAYER M4 ;
        RECT  38.796 48.768 38.88 48.792 ;
    END
  END i[297]
  PIN i[298]
    DIRECTION INPUT ;
    USE SIGNAL ;
    PORT
      LAYER M4 ;
        RECT  38.796 48.912 38.88 48.936 ;
    END
  END i[298]
  PIN i[299]
    DIRECTION INPUT ;
    USE SIGNAL ;
    PORT
      LAYER M4 ;
        RECT  38.796 49.056 38.88 49.08 ;
    END
  END i[299]
  PIN i[29]
    DIRECTION INPUT ;
    USE SIGNAL ;
    PORT
      LAYER M4 ;
        RECT  38.796 5.712 38.88 5.736 ;
    END
  END i[29]
  PIN i[2]
    DIRECTION INPUT ;
    USE SIGNAL ;
    PORT
      LAYER M4 ;
        RECT  38.796 1.392 38.88 1.416 ;
    END
  END i[2]
  PIN i[300]
    DIRECTION INPUT ;
    USE SIGNAL ;
    PORT
      LAYER M4 ;
        RECT  38.796 49.248 38.88 49.272 ;
    END
  END i[300]
  PIN i[301]
    DIRECTION INPUT ;
    USE SIGNAL ;
    PORT
      LAYER M4 ;
        RECT  38.796 49.392 38.88 49.416 ;
    END
  END i[301]
  PIN i[302]
    DIRECTION INPUT ;
    USE SIGNAL ;
    PORT
      LAYER M4 ;
        RECT  38.796 49.584 38.88 49.608 ;
    END
  END i[302]
  PIN i[303]
    DIRECTION INPUT ;
    USE SIGNAL ;
    PORT
      LAYER M4 ;
        RECT  38.796 49.728 38.88 49.752 ;
    END
  END i[303]
  PIN i[304]
    DIRECTION INPUT ;
    USE SIGNAL ;
    PORT
      LAYER M4 ;
        RECT  38.796 49.872 38.88 49.896 ;
    END
  END i[304]
  PIN i[305]
    DIRECTION INPUT ;
    USE SIGNAL ;
    PORT
      LAYER M4 ;
        RECT  38.796 50.064 38.88 50.088 ;
    END
  END i[305]
  PIN i[306]
    DIRECTION INPUT ;
    USE SIGNAL ;
    PORT
      LAYER M4 ;
        RECT  38.796 50.208 38.88 50.232 ;
    END
  END i[306]
  PIN i[307]
    DIRECTION INPUT ;
    USE SIGNAL ;
    PORT
      LAYER M4 ;
        RECT  38.796 50.352 38.88 50.376 ;
    END
  END i[307]
  PIN i[308]
    DIRECTION INPUT ;
    USE SIGNAL ;
    PORT
      LAYER M4 ;
        RECT  38.796 50.544 38.88 50.568 ;
    END
  END i[308]
  PIN i[309]
    DIRECTION INPUT ;
    USE SIGNAL ;
    PORT
      LAYER M4 ;
        RECT  38.796 50.688 38.88 50.712 ;
    END
  END i[309]
  PIN i[30]
    DIRECTION INPUT ;
    USE SIGNAL ;
    PORT
      LAYER M4 ;
        RECT  38.796 5.904 38.88 5.928 ;
    END
  END i[30]
  PIN i[310]
    DIRECTION INPUT ;
    USE SIGNAL ;
    PORT
      LAYER M4 ;
        RECT  38.796 50.832 38.88 50.856 ;
    END
  END i[310]
  PIN i[311]
    DIRECTION INPUT ;
    USE SIGNAL ;
    PORT
      LAYER M4 ;
        RECT  38.796 51.024 38.88 51.048 ;
    END
  END i[311]
  PIN i[312]
    DIRECTION INPUT ;
    USE SIGNAL ;
    PORT
      LAYER M4 ;
        RECT  38.796 51.168 38.88 51.192 ;
    END
  END i[312]
  PIN i[313]
    DIRECTION INPUT ;
    USE SIGNAL ;
    PORT
      LAYER M4 ;
        RECT  38.796 51.312 38.88 51.336 ;
    END
  END i[313]
  PIN i[314]
    DIRECTION INPUT ;
    USE SIGNAL ;
    PORT
      LAYER M4 ;
        RECT  38.796 51.504 38.88 51.528 ;
    END
  END i[314]
  PIN i[315]
    DIRECTION INPUT ;
    USE SIGNAL ;
    PORT
      LAYER M4 ;
        RECT  38.796 51.648 38.88 51.672 ;
    END
  END i[315]
  PIN i[316]
    DIRECTION INPUT ;
    USE SIGNAL ;
    PORT
      LAYER M4 ;
        RECT  38.796 51.792 38.88 51.816 ;
    END
  END i[316]
  PIN i[317]
    DIRECTION INPUT ;
    USE SIGNAL ;
    PORT
      LAYER M4 ;
        RECT  38.796 51.984 38.88 52.008 ;
    END
  END i[317]
  PIN i[318]
    DIRECTION INPUT ;
    USE SIGNAL ;
    PORT
      LAYER M4 ;
        RECT  38.796 52.128 38.88 52.152 ;
    END
  END i[318]
  PIN i[319]
    DIRECTION INPUT ;
    USE SIGNAL ;
    PORT
      LAYER M4 ;
        RECT  38.796 52.272 38.88 52.296 ;
    END
  END i[319]
  PIN i[31]
    DIRECTION INPUT ;
    USE SIGNAL ;
    PORT
      LAYER M4 ;
        RECT  38.796 6.048 38.88 6.072 ;
    END
  END i[31]
  PIN i[320]
    DIRECTION INPUT ;
    USE SIGNAL ;
    PORT
      LAYER M4 ;
        RECT  38.796 52.464 38.88 52.488 ;
    END
  END i[320]
  PIN i[321]
    DIRECTION INPUT ;
    USE SIGNAL ;
    PORT
      LAYER M4 ;
        RECT  38.796 52.608 38.88 52.632 ;
    END
  END i[321]
  PIN i[322]
    DIRECTION INPUT ;
    USE SIGNAL ;
    PORT
      LAYER M4 ;
        RECT  38.796 52.752 38.88 52.776 ;
    END
  END i[322]
  PIN i[323]
    DIRECTION INPUT ;
    USE SIGNAL ;
    PORT
      LAYER M4 ;
        RECT  38.796 52.944 38.88 52.968 ;
    END
  END i[323]
  PIN i[324]
    DIRECTION INPUT ;
    USE SIGNAL ;
    PORT
      LAYER M4 ;
        RECT  38.796 53.088 38.88 53.112 ;
    END
  END i[324]
  PIN i[325]
    DIRECTION INPUT ;
    USE SIGNAL ;
    PORT
      LAYER M4 ;
        RECT  38.796 53.232 38.88 53.256 ;
    END
  END i[325]
  PIN i[326]
    DIRECTION INPUT ;
    USE SIGNAL ;
    PORT
      LAYER M4 ;
        RECT  38.796 53.424 38.88 53.448 ;
    END
  END i[326]
  PIN i[327]
    DIRECTION INPUT ;
    USE SIGNAL ;
    PORT
      LAYER M4 ;
        RECT  38.796 53.568 38.88 53.592 ;
    END
  END i[327]
  PIN i[328]
    DIRECTION INPUT ;
    USE SIGNAL ;
    PORT
      LAYER M4 ;
        RECT  38.796 53.712 38.88 53.736 ;
    END
  END i[328]
  PIN i[329]
    DIRECTION INPUT ;
    USE SIGNAL ;
    PORT
      LAYER M4 ;
        RECT  38.796 53.904 38.88 53.928 ;
    END
  END i[329]
  PIN i[32]
    DIRECTION INPUT ;
    USE SIGNAL ;
    PORT
      LAYER M4 ;
        RECT  38.796 6.192 38.88 6.216 ;
    END
  END i[32]
  PIN i[330]
    DIRECTION INPUT ;
    USE SIGNAL ;
    PORT
      LAYER M4 ;
        RECT  38.796 54.048 38.88 54.072 ;
    END
  END i[330]
  PIN i[331]
    DIRECTION INPUT ;
    USE SIGNAL ;
    PORT
      LAYER M4 ;
        RECT  38.796 54.24 38.88 54.264 ;
    END
  END i[331]
  PIN i[332]
    DIRECTION INPUT ;
    USE SIGNAL ;
    PORT
      LAYER M4 ;
        RECT  38.796 54.384 38.88 54.408 ;
    END
  END i[332]
  PIN i[333]
    DIRECTION INPUT ;
    USE SIGNAL ;
    PORT
      LAYER M4 ;
        RECT  38.796 54.528 38.88 54.552 ;
    END
  END i[333]
  PIN i[334]
    DIRECTION INPUT ;
    USE SIGNAL ;
    PORT
      LAYER M4 ;
        RECT  38.796 54.72 38.88 54.744 ;
    END
  END i[334]
  PIN i[335]
    DIRECTION INPUT ;
    USE SIGNAL ;
    PORT
      LAYER M4 ;
        RECT  38.796 54.864 38.88 54.888 ;
    END
  END i[335]
  PIN i[336]
    DIRECTION INPUT ;
    USE SIGNAL ;
    PORT
      LAYER M4 ;
        RECT  38.796 55.008 38.88 55.032 ;
    END
  END i[336]
  PIN i[337]
    DIRECTION INPUT ;
    USE SIGNAL ;
    PORT
      LAYER M4 ;
        RECT  38.796 55.2 38.88 55.224 ;
    END
  END i[337]
  PIN i[338]
    DIRECTION INPUT ;
    USE SIGNAL ;
    PORT
      LAYER M4 ;
        RECT  38.796 55.344 38.88 55.368 ;
    END
  END i[338]
  PIN i[339]
    DIRECTION INPUT ;
    USE SIGNAL ;
    PORT
      LAYER M4 ;
        RECT  38.796 55.488 38.88 55.512 ;
    END
  END i[339]
  PIN i[33]
    DIRECTION INPUT ;
    USE SIGNAL ;
    PORT
      LAYER M4 ;
        RECT  38.796 6.384 38.88 6.408 ;
    END
  END i[33]
  PIN i[340]
    DIRECTION INPUT ;
    USE SIGNAL ;
    PORT
      LAYER M4 ;
        RECT  38.796 55.68 38.88 55.704 ;
    END
  END i[340]
  PIN i[341]
    DIRECTION INPUT ;
    USE SIGNAL ;
    PORT
      LAYER M4 ;
        RECT  38.796 55.824 38.88 55.848 ;
    END
  END i[341]
  PIN i[342]
    DIRECTION INPUT ;
    USE SIGNAL ;
    PORT
      LAYER M4 ;
        RECT  38.796 55.968 38.88 55.992 ;
    END
  END i[342]
  PIN i[343]
    DIRECTION INPUT ;
    USE SIGNAL ;
    PORT
      LAYER M4 ;
        RECT  38.796 56.16 38.88 56.184 ;
    END
  END i[343]
  PIN i[344]
    DIRECTION INPUT ;
    USE SIGNAL ;
    PORT
      LAYER M4 ;
        RECT  38.796 56.304 38.88 56.328 ;
    END
  END i[344]
  PIN i[345]
    DIRECTION INPUT ;
    USE SIGNAL ;
    PORT
      LAYER M4 ;
        RECT  38.796 56.448 38.88 56.472 ;
    END
  END i[345]
  PIN i[346]
    DIRECTION INPUT ;
    USE SIGNAL ;
    PORT
      LAYER M4 ;
        RECT  38.796 56.64 38.88 56.664 ;
    END
  END i[346]
  PIN i[347]
    DIRECTION INPUT ;
    USE SIGNAL ;
    PORT
      LAYER M4 ;
        RECT  38.796 56.784 38.88 56.808 ;
    END
  END i[347]
  PIN i[348]
    DIRECTION INPUT ;
    USE SIGNAL ;
    PORT
      LAYER M4 ;
        RECT  38.796 56.928 38.88 56.952 ;
    END
  END i[348]
  PIN i[349]
    DIRECTION INPUT ;
    USE SIGNAL ;
    PORT
      LAYER M4 ;
        RECT  38.796 57.12 38.88 57.144 ;
    END
  END i[349]
  PIN i[34]
    DIRECTION INPUT ;
    USE SIGNAL ;
    PORT
      LAYER M4 ;
        RECT  38.796 6.528 38.88 6.552 ;
    END
  END i[34]
  PIN i[350]
    DIRECTION INPUT ;
    USE SIGNAL ;
    PORT
      LAYER M4 ;
        RECT  38.796 57.264 38.88 57.288 ;
    END
  END i[350]
  PIN i[351]
    DIRECTION INPUT ;
    USE SIGNAL ;
    PORT
      LAYER M4 ;
        RECT  38.796 57.408 38.88 57.432 ;
    END
  END i[351]
  PIN i[352]
    DIRECTION INPUT ;
    USE SIGNAL ;
    PORT
      LAYER M4 ;
        RECT  38.796 57.6 38.88 57.624 ;
    END
  END i[352]
  PIN i[353]
    DIRECTION INPUT ;
    USE SIGNAL ;
    PORT
      LAYER M4 ;
        RECT  38.796 57.744 38.88 57.768 ;
    END
  END i[353]
  PIN i[354]
    DIRECTION INPUT ;
    USE SIGNAL ;
    PORT
      LAYER M4 ;
        RECT  38.796 57.888 38.88 57.912 ;
    END
  END i[354]
  PIN i[355]
    DIRECTION INPUT ;
    USE SIGNAL ;
    PORT
      LAYER M4 ;
        RECT  38.796 58.08 38.88 58.104 ;
    END
  END i[355]
  PIN i[356]
    DIRECTION INPUT ;
    USE SIGNAL ;
    PORT
      LAYER M4 ;
        RECT  38.796 58.224 38.88 58.248 ;
    END
  END i[356]
  PIN i[357]
    DIRECTION INPUT ;
    USE SIGNAL ;
    PORT
      LAYER M4 ;
        RECT  38.796 58.416 38.88 58.44 ;
    END
  END i[357]
  PIN i[358]
    DIRECTION INPUT ;
    USE SIGNAL ;
    PORT
      LAYER M4 ;
        RECT  38.796 58.56 38.88 58.584 ;
    END
  END i[358]
  PIN i[359]
    DIRECTION INPUT ;
    USE SIGNAL ;
    PORT
      LAYER M4 ;
        RECT  38.796 58.704 38.88 58.728 ;
    END
  END i[359]
  PIN i[35]
    DIRECTION INPUT ;
    USE SIGNAL ;
    PORT
      LAYER M4 ;
        RECT  38.796 6.672 38.88 6.696 ;
    END
  END i[35]
  PIN i[360]
    DIRECTION INPUT ;
    USE SIGNAL ;
    PORT
      LAYER M4 ;
        RECT  38.796 58.896 38.88 58.92 ;
    END
  END i[360]
  PIN i[361]
    DIRECTION INPUT ;
    USE SIGNAL ;
    PORT
      LAYER M4 ;
        RECT  38.796 59.04 38.88 59.064 ;
    END
  END i[361]
  PIN i[362]
    DIRECTION INPUT ;
    USE SIGNAL ;
    PORT
      LAYER M4 ;
        RECT  38.796 59.184 38.88 59.208 ;
    END
  END i[362]
  PIN i[363]
    DIRECTION INPUT ;
    USE SIGNAL ;
    PORT
      LAYER M4 ;
        RECT  38.796 59.376 38.88 59.4 ;
    END
  END i[363]
  PIN i[364]
    DIRECTION INPUT ;
    USE SIGNAL ;
    PORT
      LAYER M4 ;
        RECT  38.796 59.52 38.88 59.544 ;
    END
  END i[364]
  PIN i[365]
    DIRECTION INPUT ;
    USE SIGNAL ;
    PORT
      LAYER M4 ;
        RECT  38.796 59.664 38.88 59.688 ;
    END
  END i[365]
  PIN i[366]
    DIRECTION INPUT ;
    USE SIGNAL ;
    PORT
      LAYER M4 ;
        RECT  38.796 59.856 38.88 59.88 ;
    END
  END i[366]
  PIN i[367]
    DIRECTION INPUT ;
    USE SIGNAL ;
    PORT
      LAYER M4 ;
        RECT  38.796 60 38.88 60.024 ;
    END
  END i[367]
  PIN i[368]
    DIRECTION INPUT ;
    USE SIGNAL ;
    PORT
      LAYER M4 ;
        RECT  38.796 60.144 38.88 60.168 ;
    END
  END i[368]
  PIN i[369]
    DIRECTION INPUT ;
    USE SIGNAL ;
    PORT
      LAYER M4 ;
        RECT  38.796 60.336 38.88 60.36 ;
    END
  END i[369]
  PIN i[36]
    DIRECTION INPUT ;
    USE SIGNAL ;
    PORT
      LAYER M4 ;
        RECT  38.796 6.864 38.88 6.888 ;
    END
  END i[36]
  PIN i[370]
    DIRECTION INPUT ;
    USE SIGNAL ;
    PORT
      LAYER M4 ;
        RECT  38.796 60.48 38.88 60.504 ;
    END
  END i[370]
  PIN i[371]
    DIRECTION INPUT ;
    USE SIGNAL ;
    PORT
      LAYER M4 ;
        RECT  38.796 60.624 38.88 60.648 ;
    END
  END i[371]
  PIN i[372]
    DIRECTION INPUT ;
    USE SIGNAL ;
    PORT
      LAYER M4 ;
        RECT  38.796 60.816 38.88 60.84 ;
    END
  END i[372]
  PIN i[373]
    DIRECTION INPUT ;
    USE SIGNAL ;
    PORT
      LAYER M4 ;
        RECT  38.796 60.96 38.88 60.984 ;
    END
  END i[373]
  PIN i[374]
    DIRECTION INPUT ;
    USE SIGNAL ;
    PORT
      LAYER M4 ;
        RECT  38.796 61.104 38.88 61.128 ;
    END
  END i[374]
  PIN i[375]
    DIRECTION INPUT ;
    USE SIGNAL ;
    PORT
      LAYER M4 ;
        RECT  38.796 61.296 38.88 61.32 ;
    END
  END i[375]
  PIN i[376]
    DIRECTION INPUT ;
    USE SIGNAL ;
    PORT
      LAYER M4 ;
        RECT  38.796 61.44 38.88 61.464 ;
    END
  END i[376]
  PIN i[377]
    DIRECTION INPUT ;
    USE SIGNAL ;
    PORT
      LAYER M4 ;
        RECT  38.796 61.584 38.88 61.608 ;
    END
  END i[377]
  PIN i[378]
    DIRECTION INPUT ;
    USE SIGNAL ;
    PORT
      LAYER M4 ;
        RECT  38.796 61.776 38.88 61.8 ;
    END
  END i[378]
  PIN i[379]
    DIRECTION INPUT ;
    USE SIGNAL ;
    PORT
      LAYER M4 ;
        RECT  38.796 61.92 38.88 61.944 ;
    END
  END i[379]
  PIN i[37]
    DIRECTION INPUT ;
    USE SIGNAL ;
    PORT
      LAYER M4 ;
        RECT  38.796 7.008 38.88 7.032 ;
    END
  END i[37]
  PIN i[380]
    DIRECTION INPUT ;
    USE SIGNAL ;
    PORT
      LAYER M4 ;
        RECT  38.796 62.064 38.88 62.088 ;
    END
  END i[380]
  PIN i[381]
    DIRECTION INPUT ;
    USE SIGNAL ;
    PORT
      LAYER M4 ;
        RECT  38.796 62.256 38.88 62.28 ;
    END
  END i[381]
  PIN i[382]
    DIRECTION INPUT ;
    USE SIGNAL ;
    PORT
      LAYER M4 ;
        RECT  38.796 62.4 38.88 62.424 ;
    END
  END i[382]
  PIN i[383]
    DIRECTION INPUT ;
    USE SIGNAL ;
    PORT
      LAYER M4 ;
        RECT  38.796 62.544 38.88 62.568 ;
    END
  END i[383]
  PIN i[384]
    DIRECTION INPUT ;
    USE SIGNAL ;
    PORT
      LAYER M4 ;
        RECT  38.796 62.736 38.88 62.76 ;
    END
  END i[384]
  PIN i[385]
    DIRECTION INPUT ;
    USE SIGNAL ;
    PORT
      LAYER M4 ;
        RECT  38.796 62.88 38.88 62.904 ;
    END
  END i[385]
  PIN i[386]
    DIRECTION INPUT ;
    USE SIGNAL ;
    PORT
      LAYER M4 ;
        RECT  38.796 63.072 38.88 63.096 ;
    END
  END i[386]
  PIN i[387]
    DIRECTION INPUT ;
    USE SIGNAL ;
    PORT
      LAYER M4 ;
        RECT  38.796 63.216 38.88 63.24 ;
    END
  END i[387]
  PIN i[388]
    DIRECTION INPUT ;
    USE SIGNAL ;
    PORT
      LAYER M4 ;
        RECT  38.796 63.36 38.88 63.384 ;
    END
  END i[388]
  PIN i[389]
    DIRECTION INPUT ;
    USE SIGNAL ;
    PORT
      LAYER M4 ;
        RECT  38.796 63.552 38.88 63.576 ;
    END
  END i[389]
  PIN i[38]
    DIRECTION INPUT ;
    USE SIGNAL ;
    PORT
      LAYER M4 ;
        RECT  38.796 7.152 38.88 7.176 ;
    END
  END i[38]
  PIN i[390]
    DIRECTION INPUT ;
    USE SIGNAL ;
    PORT
      LAYER M4 ;
        RECT  38.796 63.696 38.88 63.72 ;
    END
  END i[390]
  PIN i[391]
    DIRECTION INPUT ;
    USE SIGNAL ;
    PORT
      LAYER M4 ;
        RECT  38.796 63.84 38.88 63.864 ;
    END
  END i[391]
  PIN i[392]
    DIRECTION INPUT ;
    USE SIGNAL ;
    PORT
      LAYER M4 ;
        RECT  38.796 64.032 38.88 64.056 ;
    END
  END i[392]
  PIN i[393]
    DIRECTION INPUT ;
    USE SIGNAL ;
    PORT
      LAYER M4 ;
        RECT  38.796 64.176 38.88 64.2 ;
    END
  END i[393]
  PIN i[394]
    DIRECTION INPUT ;
    USE SIGNAL ;
    PORT
      LAYER M4 ;
        RECT  38.796 64.32 38.88 64.344 ;
    END
  END i[394]
  PIN i[395]
    DIRECTION INPUT ;
    USE SIGNAL ;
    PORT
      LAYER M4 ;
        RECT  38.796 64.512 38.88 64.536 ;
    END
  END i[395]
  PIN i[396]
    DIRECTION INPUT ;
    USE SIGNAL ;
    PORT
      LAYER M4 ;
        RECT  38.796 64.656 38.88 64.68 ;
    END
  END i[396]
  PIN i[397]
    DIRECTION INPUT ;
    USE SIGNAL ;
    PORT
      LAYER M4 ;
        RECT  38.796 64.8 38.88 64.824 ;
    END
  END i[397]
  PIN i[398]
    DIRECTION INPUT ;
    USE SIGNAL ;
    PORT
      LAYER M4 ;
        RECT  38.796 64.992 38.88 65.016 ;
    END
  END i[398]
  PIN i[399]
    DIRECTION INPUT ;
    USE SIGNAL ;
    PORT
      LAYER M4 ;
        RECT  38.796 65.136 38.88 65.16 ;
    END
  END i[399]
  PIN i[39]
    DIRECTION INPUT ;
    USE SIGNAL ;
    PORT
      LAYER M4 ;
        RECT  38.796 7.344 38.88 7.368 ;
    END
  END i[39]
  PIN i[3]
    DIRECTION INPUT ;
    USE SIGNAL ;
    PORT
      LAYER M4 ;
        RECT  38.796 1.536 38.88 1.56 ;
    END
  END i[3]
  PIN i[400]
    DIRECTION INPUT ;
    USE SIGNAL ;
    PORT
      LAYER M4 ;
        RECT  38.796 65.28 38.88 65.304 ;
    END
  END i[400]
  PIN i[401]
    DIRECTION INPUT ;
    USE SIGNAL ;
    PORT
      LAYER M4 ;
        RECT  38.796 65.472 38.88 65.496 ;
    END
  END i[401]
  PIN i[402]
    DIRECTION INPUT ;
    USE SIGNAL ;
    PORT
      LAYER M4 ;
        RECT  38.796 65.616 38.88 65.64 ;
    END
  END i[402]
  PIN i[403]
    DIRECTION INPUT ;
    USE SIGNAL ;
    PORT
      LAYER M4 ;
        RECT  38.796 65.76 38.88 65.784 ;
    END
  END i[403]
  PIN i[404]
    DIRECTION INPUT ;
    USE SIGNAL ;
    PORT
      LAYER M4 ;
        RECT  38.796 65.952 38.88 65.976 ;
    END
  END i[404]
  PIN i[405]
    DIRECTION INPUT ;
    USE SIGNAL ;
    PORT
      LAYER M4 ;
        RECT  38.796 66.096 38.88 66.12 ;
    END
  END i[405]
  PIN i[406]
    DIRECTION INPUT ;
    USE SIGNAL ;
    PORT
      LAYER M4 ;
        RECT  38.796 66.24 38.88 66.264 ;
    END
  END i[406]
  PIN i[407]
    DIRECTION INPUT ;
    USE SIGNAL ;
    PORT
      LAYER M4 ;
        RECT  38.796 66.432 38.88 66.456 ;
    END
  END i[407]
  PIN i[408]
    DIRECTION INPUT ;
    USE SIGNAL ;
    PORT
      LAYER M4 ;
        RECT  38.796 66.576 38.88 66.6 ;
    END
  END i[408]
  PIN i[409]
    DIRECTION INPUT ;
    USE SIGNAL ;
    PORT
      LAYER M4 ;
        RECT  38.796 66.72 38.88 66.744 ;
    END
  END i[409]
  PIN i[40]
    DIRECTION INPUT ;
    USE SIGNAL ;
    PORT
      LAYER M4 ;
        RECT  38.796 7.488 38.88 7.512 ;
    END
  END i[40]
  PIN i[410]
    DIRECTION INPUT ;
    USE SIGNAL ;
    PORT
      LAYER M4 ;
        RECT  38.796 66.912 38.88 66.936 ;
    END
  END i[410]
  PIN i[411]
    DIRECTION INPUT ;
    USE SIGNAL ;
    PORT
      LAYER M4 ;
        RECT  38.796 67.056 38.88 67.08 ;
    END
  END i[411]
  PIN i[412]
    DIRECTION INPUT ;
    USE SIGNAL ;
    PORT
      LAYER M4 ;
        RECT  38.796 67.2 38.88 67.224 ;
    END
  END i[412]
  PIN i[413]
    DIRECTION INPUT ;
    USE SIGNAL ;
    PORT
      LAYER M4 ;
        RECT  38.796 67.392 38.88 67.416 ;
    END
  END i[413]
  PIN i[414]
    DIRECTION INPUT ;
    USE SIGNAL ;
    PORT
      LAYER M4 ;
        RECT  38.796 67.536 38.88 67.56 ;
    END
  END i[414]
  PIN i[415]
    DIRECTION INPUT ;
    USE SIGNAL ;
    PORT
      LAYER M4 ;
        RECT  38.796 67.728 38.88 67.752 ;
    END
  END i[415]
  PIN i[416]
    DIRECTION INPUT ;
    USE SIGNAL ;
    PORT
      LAYER M4 ;
        RECT  38.796 67.872 38.88 67.896 ;
    END
  END i[416]
  PIN i[417]
    DIRECTION INPUT ;
    USE SIGNAL ;
    PORT
      LAYER M4 ;
        RECT  38.796 68.016 38.88 68.04 ;
    END
  END i[417]
  PIN i[418]
    DIRECTION INPUT ;
    USE SIGNAL ;
    PORT
      LAYER M4 ;
        RECT  38.796 68.208 38.88 68.232 ;
    END
  END i[418]
  PIN i[419]
    DIRECTION INPUT ;
    USE SIGNAL ;
    PORT
      LAYER M4 ;
        RECT  38.796 68.352 38.88 68.376 ;
    END
  END i[419]
  PIN i[41]
    DIRECTION INPUT ;
    USE SIGNAL ;
    PORT
      LAYER M4 ;
        RECT  38.796 7.632 38.88 7.656 ;
    END
  END i[41]
  PIN i[420]
    DIRECTION INPUT ;
    USE SIGNAL ;
    PORT
      LAYER M4 ;
        RECT  38.796 68.496 38.88 68.52 ;
    END
  END i[420]
  PIN i[421]
    DIRECTION INPUT ;
    USE SIGNAL ;
    PORT
      LAYER M4 ;
        RECT  38.796 68.688 38.88 68.712 ;
    END
  END i[421]
  PIN i[422]
    DIRECTION INPUT ;
    USE SIGNAL ;
    PORT
      LAYER M4 ;
        RECT  38.796 68.832 38.88 68.856 ;
    END
  END i[422]
  PIN i[423]
    DIRECTION INPUT ;
    USE SIGNAL ;
    PORT
      LAYER M4 ;
        RECT  38.796 68.976 38.88 69 ;
    END
  END i[423]
  PIN i[424]
    DIRECTION INPUT ;
    USE SIGNAL ;
    PORT
      LAYER M4 ;
        RECT  38.796 69.168 38.88 69.192 ;
    END
  END i[424]
  PIN i[425]
    DIRECTION INPUT ;
    USE SIGNAL ;
    PORT
      LAYER M4 ;
        RECT  38.796 69.312 38.88 69.336 ;
    END
  END i[425]
  PIN i[426]
    DIRECTION INPUT ;
    USE SIGNAL ;
    PORT
      LAYER M4 ;
        RECT  38.796 69.456 38.88 69.48 ;
    END
  END i[426]
  PIN i[427]
    DIRECTION INPUT ;
    USE SIGNAL ;
    PORT
      LAYER M4 ;
        RECT  38.796 69.648 38.88 69.672 ;
    END
  END i[427]
  PIN i[428]
    DIRECTION INPUT ;
    USE SIGNAL ;
    PORT
      LAYER M4 ;
        RECT  38.796 69.792 38.88 69.816 ;
    END
  END i[428]
  PIN i[429]
    DIRECTION INPUT ;
    USE SIGNAL ;
    PORT
      LAYER M4 ;
        RECT  38.796 69.936 38.88 69.96 ;
    END
  END i[429]
  PIN i[42]
    DIRECTION INPUT ;
    USE SIGNAL ;
    PORT
      LAYER M4 ;
        RECT  38.796 7.824 38.88 7.848 ;
    END
  END i[42]
  PIN i[430]
    DIRECTION INPUT ;
    USE SIGNAL ;
    PORT
      LAYER M4 ;
        RECT  38.796 70.128 38.88 70.152 ;
    END
  END i[430]
  PIN i[431]
    DIRECTION INPUT ;
    USE SIGNAL ;
    PORT
      LAYER M4 ;
        RECT  38.796 70.272 38.88 70.296 ;
    END
  END i[431]
  PIN i[432]
    DIRECTION INPUT ;
    USE SIGNAL ;
    PORT
      LAYER M4 ;
        RECT  38.796 70.416 38.88 70.44 ;
    END
  END i[432]
  PIN i[433]
    DIRECTION INPUT ;
    USE SIGNAL ;
    PORT
      LAYER M4 ;
        RECT  38.796 70.608 38.88 70.632 ;
    END
  END i[433]
  PIN i[434]
    DIRECTION INPUT ;
    USE SIGNAL ;
    PORT
      LAYER M4 ;
        RECT  38.796 70.752 38.88 70.776 ;
    END
  END i[434]
  PIN i[435]
    DIRECTION INPUT ;
    USE SIGNAL ;
    PORT
      LAYER M4 ;
        RECT  38.796 70.896 38.88 70.92 ;
    END
  END i[435]
  PIN i[436]
    DIRECTION INPUT ;
    USE SIGNAL ;
    PORT
      LAYER M4 ;
        RECT  38.796 71.088 38.88 71.112 ;
    END
  END i[436]
  PIN i[437]
    DIRECTION INPUT ;
    USE SIGNAL ;
    PORT
      LAYER M4 ;
        RECT  38.796 71.232 38.88 71.256 ;
    END
  END i[437]
  PIN i[438]
    DIRECTION INPUT ;
    USE SIGNAL ;
    PORT
      LAYER M4 ;
        RECT  38.796 71.376 38.88 71.4 ;
    END
  END i[438]
  PIN i[439]
    DIRECTION INPUT ;
    USE SIGNAL ;
    PORT
      LAYER M4 ;
        RECT  38.796 71.568 38.88 71.592 ;
    END
  END i[439]
  PIN i[43]
    DIRECTION INPUT ;
    USE SIGNAL ;
    PORT
      LAYER M4 ;
        RECT  38.796 7.968 38.88 7.992 ;
    END
  END i[43]
  PIN i[440]
    DIRECTION INPUT ;
    USE SIGNAL ;
    PORT
      LAYER M4 ;
        RECT  38.796 71.712 38.88 71.736 ;
    END
  END i[440]
  PIN i[441]
    DIRECTION INPUT ;
    USE SIGNAL ;
    PORT
      LAYER M4 ;
        RECT  38.796 71.856 38.88 71.88 ;
    END
  END i[441]
  PIN i[442]
    DIRECTION INPUT ;
    USE SIGNAL ;
    PORT
      LAYER M4 ;
        RECT  38.796 72.048 38.88 72.072 ;
    END
  END i[442]
  PIN i[443]
    DIRECTION INPUT ;
    USE SIGNAL ;
    PORT
      LAYER M4 ;
        RECT  38.796 72.192 38.88 72.216 ;
    END
  END i[443]
  PIN i[444]
    DIRECTION INPUT ;
    USE SIGNAL ;
    PORT
      LAYER M4 ;
        RECT  38.796 72.384 38.88 72.408 ;
    END
  END i[444]
  PIN i[445]
    DIRECTION INPUT ;
    USE SIGNAL ;
    PORT
      LAYER M4 ;
        RECT  38.796 72.528 38.88 72.552 ;
    END
  END i[445]
  PIN i[446]
    DIRECTION INPUT ;
    USE SIGNAL ;
    PORT
      LAYER M4 ;
        RECT  38.796 72.672 38.88 72.696 ;
    END
  END i[446]
  PIN i[447]
    DIRECTION INPUT ;
    USE SIGNAL ;
    PORT
      LAYER M4 ;
        RECT  38.796 72.864 38.88 72.888 ;
    END
  END i[447]
  PIN i[448]
    DIRECTION INPUT ;
    USE SIGNAL ;
    PORT
      LAYER M4 ;
        RECT  38.796 73.008 38.88 73.032 ;
    END
  END i[448]
  PIN i[449]
    DIRECTION INPUT ;
    USE SIGNAL ;
    PORT
      LAYER M4 ;
        RECT  38.796 73.152 38.88 73.176 ;
    END
  END i[449]
  PIN i[44]
    DIRECTION INPUT ;
    USE SIGNAL ;
    PORT
      LAYER M4 ;
        RECT  38.796 8.112 38.88 8.136 ;
    END
  END i[44]
  PIN i[450]
    DIRECTION INPUT ;
    USE SIGNAL ;
    PORT
      LAYER M4 ;
        RECT  38.796 73.344 38.88 73.368 ;
    END
  END i[450]
  PIN i[451]
    DIRECTION INPUT ;
    USE SIGNAL ;
    PORT
      LAYER M4 ;
        RECT  38.796 73.488 38.88 73.512 ;
    END
  END i[451]
  PIN i[452]
    DIRECTION INPUT ;
    USE SIGNAL ;
    PORT
      LAYER M4 ;
        RECT  38.796 73.632 38.88 73.656 ;
    END
  END i[452]
  PIN i[453]
    DIRECTION INPUT ;
    USE SIGNAL ;
    PORT
      LAYER M4 ;
        RECT  38.796 73.824 38.88 73.848 ;
    END
  END i[453]
  PIN i[454]
    DIRECTION INPUT ;
    USE SIGNAL ;
    PORT
      LAYER M4 ;
        RECT  38.796 73.968 38.88 73.992 ;
    END
  END i[454]
  PIN i[455]
    DIRECTION INPUT ;
    USE SIGNAL ;
    PORT
      LAYER M4 ;
        RECT  38.796 74.112 38.88 74.136 ;
    END
  END i[455]
  PIN i[456]
    DIRECTION INPUT ;
    USE SIGNAL ;
    PORT
      LAYER M4 ;
        RECT  38.796 74.304 38.88 74.328 ;
    END
  END i[456]
  PIN i[457]
    DIRECTION INPUT ;
    USE SIGNAL ;
    PORT
      LAYER M4 ;
        RECT  38.796 74.448 38.88 74.472 ;
    END
  END i[457]
  PIN i[458]
    DIRECTION INPUT ;
    USE SIGNAL ;
    PORT
      LAYER M4 ;
        RECT  38.796 74.592 38.88 74.616 ;
    END
  END i[458]
  PIN i[459]
    DIRECTION INPUT ;
    USE SIGNAL ;
    PORT
      LAYER M4 ;
        RECT  38.796 74.784 38.88 74.808 ;
    END
  END i[459]
  PIN i[45]
    DIRECTION INPUT ;
    USE SIGNAL ;
    PORT
      LAYER M4 ;
        RECT  38.796 8.304 38.88 8.328 ;
    END
  END i[45]
  PIN i[460]
    DIRECTION INPUT ;
    USE SIGNAL ;
    PORT
      LAYER M4 ;
        RECT  38.796 74.928 38.88 74.952 ;
    END
  END i[460]
  PIN i[461]
    DIRECTION INPUT ;
    USE SIGNAL ;
    PORT
      LAYER M4 ;
        RECT  38.796 75.072 38.88 75.096 ;
    END
  END i[461]
  PIN i[462]
    DIRECTION INPUT ;
    USE SIGNAL ;
    PORT
      LAYER M4 ;
        RECT  38.796 75.264 38.88 75.288 ;
    END
  END i[462]
  PIN i[463]
    DIRECTION INPUT ;
    USE SIGNAL ;
    PORT
      LAYER M4 ;
        RECT  38.796 75.408 38.88 75.432 ;
    END
  END i[463]
  PIN i[464]
    DIRECTION INPUT ;
    USE SIGNAL ;
    PORT
      LAYER M4 ;
        RECT  38.796 75.552 38.88 75.576 ;
    END
  END i[464]
  PIN i[465]
    DIRECTION INPUT ;
    USE SIGNAL ;
    PORT
      LAYER M4 ;
        RECT  38.796 75.744 38.88 75.768 ;
    END
  END i[465]
  PIN i[466]
    DIRECTION INPUT ;
    USE SIGNAL ;
    PORT
      LAYER M4 ;
        RECT  38.796 75.888 38.88 75.912 ;
    END
  END i[466]
  PIN i[467]
    DIRECTION INPUT ;
    USE SIGNAL ;
    PORT
      LAYER M4 ;
        RECT  38.796 76.032 38.88 76.056 ;
    END
  END i[467]
  PIN i[468]
    DIRECTION INPUT ;
    USE SIGNAL ;
    PORT
      LAYER M4 ;
        RECT  38.796 76.224 38.88 76.248 ;
    END
  END i[468]
  PIN i[469]
    DIRECTION INPUT ;
    USE SIGNAL ;
    PORT
      LAYER M4 ;
        RECT  38.796 76.368 38.88 76.392 ;
    END
  END i[469]
  PIN i[46]
    DIRECTION INPUT ;
    USE SIGNAL ;
    PORT
      LAYER M4 ;
        RECT  38.796 8.448 38.88 8.472 ;
    END
  END i[46]
  PIN i[470]
    DIRECTION INPUT ;
    USE SIGNAL ;
    PORT
      LAYER M4 ;
        RECT  38.796 76.56 38.88 76.584 ;
    END
  END i[470]
  PIN i[471]
    DIRECTION INPUT ;
    USE SIGNAL ;
    PORT
      LAYER M4 ;
        RECT  38.796 76.704 38.88 76.728 ;
    END
  END i[471]
  PIN i[472]
    DIRECTION INPUT ;
    USE SIGNAL ;
    PORT
      LAYER M4 ;
        RECT  38.796 76.848 38.88 76.872 ;
    END
  END i[472]
  PIN i[473]
    DIRECTION INPUT ;
    USE SIGNAL ;
    PORT
      LAYER M4 ;
        RECT  38.796 77.04 38.88 77.064 ;
    END
  END i[473]
  PIN i[474]
    DIRECTION INPUT ;
    USE SIGNAL ;
    PORT
      LAYER M4 ;
        RECT  38.796 77.184 38.88 77.208 ;
    END
  END i[474]
  PIN i[475]
    DIRECTION INPUT ;
    USE SIGNAL ;
    PORT
      LAYER M4 ;
        RECT  38.796 77.328 38.88 77.352 ;
    END
  END i[475]
  PIN i[476]
    DIRECTION INPUT ;
    USE SIGNAL ;
    PORT
      LAYER M4 ;
        RECT  38.796 77.52 38.88 77.544 ;
    END
  END i[476]
  PIN i[477]
    DIRECTION INPUT ;
    USE SIGNAL ;
    PORT
      LAYER M4 ;
        RECT  38.796 77.664 38.88 77.688 ;
    END
  END i[477]
  PIN i[478]
    DIRECTION INPUT ;
    USE SIGNAL ;
    PORT
      LAYER M4 ;
        RECT  38.796 77.808 38.88 77.832 ;
    END
  END i[478]
  PIN i[479]
    DIRECTION INPUT ;
    USE SIGNAL ;
    PORT
      LAYER M4 ;
        RECT  38.796 78 38.88 78.024 ;
    END
  END i[479]
  PIN i[47]
    DIRECTION INPUT ;
    USE SIGNAL ;
    PORT
      LAYER M4 ;
        RECT  38.796 8.592 38.88 8.616 ;
    END
  END i[47]
  PIN i[480]
    DIRECTION INPUT ;
    USE SIGNAL ;
    PORT
      LAYER M4 ;
        RECT  38.796 78.144 38.88 78.168 ;
    END
  END i[480]
  PIN i[481]
    DIRECTION INPUT ;
    USE SIGNAL ;
    PORT
      LAYER M4 ;
        RECT  38.796 78.288 38.88 78.312 ;
    END
  END i[481]
  PIN i[482]
    DIRECTION INPUT ;
    USE SIGNAL ;
    PORT
      LAYER M4 ;
        RECT  38.796 78.48 38.88 78.504 ;
    END
  END i[482]
  PIN i[483]
    DIRECTION INPUT ;
    USE SIGNAL ;
    PORT
      LAYER M4 ;
        RECT  38.796 78.624 38.88 78.648 ;
    END
  END i[483]
  PIN i[484]
    DIRECTION INPUT ;
    USE SIGNAL ;
    PORT
      LAYER M4 ;
        RECT  38.796 78.768 38.88 78.792 ;
    END
  END i[484]
  PIN i[485]
    DIRECTION INPUT ;
    USE SIGNAL ;
    PORT
      LAYER M4 ;
        RECT  38.796 78.96 38.88 78.984 ;
    END
  END i[485]
  PIN i[486]
    DIRECTION INPUT ;
    USE SIGNAL ;
    PORT
      LAYER M4 ;
        RECT  38.796 79.104 38.88 79.128 ;
    END
  END i[486]
  PIN i[487]
    DIRECTION INPUT ;
    USE SIGNAL ;
    PORT
      LAYER M4 ;
        RECT  38.796 79.248 38.88 79.272 ;
    END
  END i[487]
  PIN i[488]
    DIRECTION INPUT ;
    USE SIGNAL ;
    PORT
      LAYER M4 ;
        RECT  38.796 79.44 38.88 79.464 ;
    END
  END i[488]
  PIN i[489]
    DIRECTION INPUT ;
    USE SIGNAL ;
    PORT
      LAYER M4 ;
        RECT  38.796 79.584 38.88 79.608 ;
    END
  END i[489]
  PIN i[48]
    DIRECTION INPUT ;
    USE SIGNAL ;
    PORT
      LAYER M4 ;
        RECT  38.796 8.784 38.88 8.808 ;
    END
  END i[48]
  PIN i[490]
    DIRECTION INPUT ;
    USE SIGNAL ;
    PORT
      LAYER M4 ;
        RECT  38.796 79.728 38.88 79.752 ;
    END
  END i[490]
  PIN i[491]
    DIRECTION INPUT ;
    USE SIGNAL ;
    PORT
      LAYER M4 ;
        RECT  38.796 79.92 38.88 79.944 ;
    END
  END i[491]
  PIN i[492]
    DIRECTION INPUT ;
    USE SIGNAL ;
    PORT
      LAYER M4 ;
        RECT  38.796 80.064 38.88 80.088 ;
    END
  END i[492]
  PIN i[493]
    DIRECTION INPUT ;
    USE SIGNAL ;
    PORT
      LAYER M4 ;
        RECT  38.796 80.208 38.88 80.232 ;
    END
  END i[493]
  PIN i[494]
    DIRECTION INPUT ;
    USE SIGNAL ;
    PORT
      LAYER M4 ;
        RECT  38.796 80.4 38.88 80.424 ;
    END
  END i[494]
  PIN i[495]
    DIRECTION INPUT ;
    USE SIGNAL ;
    PORT
      LAYER M4 ;
        RECT  38.796 80.544 38.88 80.568 ;
    END
  END i[495]
  PIN i[496]
    DIRECTION INPUT ;
    USE SIGNAL ;
    PORT
      LAYER M4 ;
        RECT  38.796 80.688 38.88 80.712 ;
    END
  END i[496]
  PIN i[497]
    DIRECTION INPUT ;
    USE SIGNAL ;
    PORT
      LAYER M4 ;
        RECT  38.796 80.88 38.88 80.904 ;
    END
  END i[497]
  PIN i[498]
    DIRECTION INPUT ;
    USE SIGNAL ;
    PORT
      LAYER M4 ;
        RECT  38.796 81.024 38.88 81.048 ;
    END
  END i[498]
  PIN i[499]
    DIRECTION INPUT ;
    USE SIGNAL ;
    PORT
      LAYER M4 ;
        RECT  38.796 81.216 38.88 81.24 ;
    END
  END i[499]
  PIN i[49]
    DIRECTION INPUT ;
    USE SIGNAL ;
    PORT
      LAYER M4 ;
        RECT  38.796 8.928 38.88 8.952 ;
    END
  END i[49]
  PIN i[4]
    DIRECTION INPUT ;
    USE SIGNAL ;
    PORT
      LAYER M4 ;
        RECT  38.796 1.728 38.88 1.752 ;
    END
  END i[4]
  PIN i[500]
    DIRECTION INPUT ;
    USE SIGNAL ;
    PORT
      LAYER M4 ;
        RECT  38.796 81.36 38.88 81.384 ;
    END
  END i[500]
  PIN i[501]
    DIRECTION INPUT ;
    USE SIGNAL ;
    PORT
      LAYER M4 ;
        RECT  38.796 81.504 38.88 81.528 ;
    END
  END i[501]
  PIN i[502]
    DIRECTION INPUT ;
    USE SIGNAL ;
    PORT
      LAYER M4 ;
        RECT  38.796 81.696 38.88 81.72 ;
    END
  END i[502]
  PIN i[503]
    DIRECTION INPUT ;
    USE SIGNAL ;
    PORT
      LAYER M4 ;
        RECT  38.796 81.84 38.88 81.864 ;
    END
  END i[503]
  PIN i[504]
    DIRECTION INPUT ;
    USE SIGNAL ;
    PORT
      LAYER M4 ;
        RECT  38.796 81.984 38.88 82.008 ;
    END
  END i[504]
  PIN i[505]
    DIRECTION INPUT ;
    USE SIGNAL ;
    PORT
      LAYER M4 ;
        RECT  38.796 82.176 38.88 82.2 ;
    END
  END i[505]
  PIN i[506]
    DIRECTION INPUT ;
    USE SIGNAL ;
    PORT
      LAYER M4 ;
        RECT  38.796 82.32 38.88 82.344 ;
    END
  END i[506]
  PIN i[507]
    DIRECTION INPUT ;
    USE SIGNAL ;
    PORT
      LAYER M4 ;
        RECT  38.796 82.464 38.88 82.488 ;
    END
  END i[507]
  PIN i[508]
    DIRECTION INPUT ;
    USE SIGNAL ;
    PORT
      LAYER M4 ;
        RECT  38.796 82.656 38.88 82.68 ;
    END
  END i[508]
  PIN i[509]
    DIRECTION INPUT ;
    USE SIGNAL ;
    PORT
      LAYER M4 ;
        RECT  38.796 82.8 38.88 82.824 ;
    END
  END i[509]
  PIN i[50]
    DIRECTION INPUT ;
    USE SIGNAL ;
    PORT
      LAYER M4 ;
        RECT  38.796 9.12 38.88 9.144 ;
    END
  END i[50]
  PIN i[510]
    DIRECTION INPUT ;
    USE SIGNAL ;
    PORT
      LAYER M4 ;
        RECT  38.796 82.944 38.88 82.968 ;
    END
  END i[510]
  PIN i[511]
    DIRECTION INPUT ;
    USE SIGNAL ;
    PORT
      LAYER M4 ;
        RECT  38.796 83.136 38.88 83.16 ;
    END
  END i[511]
  PIN i[512]
    DIRECTION INPUT ;
    USE SIGNAL ;
    PORT
      LAYER M4 ;
        RECT  38.796 83.28 38.88 83.304 ;
    END
  END i[512]
  PIN i[513]
    DIRECTION INPUT ;
    USE SIGNAL ;
    PORT
      LAYER M4 ;
        RECT  38.796 83.424 38.88 83.448 ;
    END
  END i[513]
  PIN i[514]
    DIRECTION INPUT ;
    USE SIGNAL ;
    PORT
      LAYER M4 ;
        RECT  38.796 83.616 38.88 83.64 ;
    END
  END i[514]
  PIN i[515]
    DIRECTION INPUT ;
    USE SIGNAL ;
    PORT
      LAYER M4 ;
        RECT  38.796 83.76 38.88 83.784 ;
    END
  END i[515]
  PIN i[516]
    DIRECTION INPUT ;
    USE SIGNAL ;
    PORT
      LAYER M4 ;
        RECT  38.796 83.904 38.88 83.928 ;
    END
  END i[516]
  PIN i[517]
    DIRECTION INPUT ;
    USE SIGNAL ;
    PORT
      LAYER M4 ;
        RECT  38.796 84.096 38.88 84.12 ;
    END
  END i[517]
  PIN i[518]
    DIRECTION INPUT ;
    USE SIGNAL ;
    PORT
      LAYER M4 ;
        RECT  38.796 84.24 38.88 84.264 ;
    END
  END i[518]
  PIN i[519]
    DIRECTION INPUT ;
    USE SIGNAL ;
    PORT
      LAYER M4 ;
        RECT  38.796 84.384 38.88 84.408 ;
    END
  END i[519]
  PIN i[51]
    DIRECTION INPUT ;
    USE SIGNAL ;
    PORT
      LAYER M4 ;
        RECT  38.796 9.264 38.88 9.288 ;
    END
  END i[51]
  PIN i[520]
    DIRECTION INPUT ;
    USE SIGNAL ;
    PORT
      LAYER M4 ;
        RECT  38.796 84.576 38.88 84.6 ;
    END
  END i[520]
  PIN i[521]
    DIRECTION INPUT ;
    USE SIGNAL ;
    PORT
      LAYER M4 ;
        RECT  38.796 84.72 38.88 84.744 ;
    END
  END i[521]
  PIN i[522]
    DIRECTION INPUT ;
    USE SIGNAL ;
    PORT
      LAYER M4 ;
        RECT  38.796 84.864 38.88 84.888 ;
    END
  END i[522]
  PIN i[523]
    DIRECTION INPUT ;
    USE SIGNAL ;
    PORT
      LAYER M4 ;
        RECT  38.796 85.056 38.88 85.08 ;
    END
  END i[523]
  PIN i[524]
    DIRECTION INPUT ;
    USE SIGNAL ;
    PORT
      LAYER M4 ;
        RECT  38.796 85.2 38.88 85.224 ;
    END
  END i[524]
  PIN i[525]
    DIRECTION INPUT ;
    USE SIGNAL ;
    PORT
      LAYER M4 ;
        RECT  38.796 85.344 38.88 85.368 ;
    END
  END i[525]
  PIN i[526]
    DIRECTION INPUT ;
    USE SIGNAL ;
    PORT
      LAYER M4 ;
        RECT  38.796 85.536 38.88 85.56 ;
    END
  END i[526]
  PIN i[527]
    DIRECTION INPUT ;
    USE SIGNAL ;
    PORT
      LAYER M4 ;
        RECT  38.796 85.68 38.88 85.704 ;
    END
  END i[527]
  PIN i[528]
    DIRECTION INPUT ;
    USE SIGNAL ;
    PORT
      LAYER M4 ;
        RECT  38.796 85.872 38.88 85.896 ;
    END
  END i[528]
  PIN i[529]
    DIRECTION INPUT ;
    USE SIGNAL ;
    PORT
      LAYER M4 ;
        RECT  38.796 86.016 38.88 86.04 ;
    END
  END i[529]
  PIN i[52]
    DIRECTION INPUT ;
    USE SIGNAL ;
    PORT
      LAYER M4 ;
        RECT  38.796 9.408 38.88 9.432 ;
    END
  END i[52]
  PIN i[530]
    DIRECTION INPUT ;
    USE SIGNAL ;
    PORT
      LAYER M4 ;
        RECT  38.796 86.16 38.88 86.184 ;
    END
  END i[530]
  PIN i[531]
    DIRECTION INPUT ;
    USE SIGNAL ;
    PORT
      LAYER M4 ;
        RECT  38.796 86.352 38.88 86.376 ;
    END
  END i[531]
  PIN i[532]
    DIRECTION INPUT ;
    USE SIGNAL ;
    PORT
      LAYER M4 ;
        RECT  38.796 86.496 38.88 86.52 ;
    END
  END i[532]
  PIN i[533]
    DIRECTION INPUT ;
    USE SIGNAL ;
    PORT
      LAYER M4 ;
        RECT  38.796 86.64 38.88 86.664 ;
    END
  END i[533]
  PIN i[534]
    DIRECTION INPUT ;
    USE SIGNAL ;
    PORT
      LAYER M4 ;
        RECT  38.796 86.832 38.88 86.856 ;
    END
  END i[534]
  PIN i[535]
    DIRECTION INPUT ;
    USE SIGNAL ;
    PORT
      LAYER M4 ;
        RECT  38.796 86.976 38.88 87 ;
    END
  END i[535]
  PIN i[536]
    DIRECTION INPUT ;
    USE SIGNAL ;
    PORT
      LAYER M4 ;
        RECT  38.796 87.12 38.88 87.144 ;
    END
  END i[536]
  PIN i[537]
    DIRECTION INPUT ;
    USE SIGNAL ;
    PORT
      LAYER M4 ;
        RECT  38.796 87.312 38.88 87.336 ;
    END
  END i[537]
  PIN i[538]
    DIRECTION INPUT ;
    USE SIGNAL ;
    PORT
      LAYER M4 ;
        RECT  38.796 87.456 38.88 87.48 ;
    END
  END i[538]
  PIN i[539]
    DIRECTION INPUT ;
    USE SIGNAL ;
    PORT
      LAYER M4 ;
        RECT  38.796 87.6 38.88 87.624 ;
    END
  END i[539]
  PIN i[53]
    DIRECTION INPUT ;
    USE SIGNAL ;
    PORT
      LAYER M4 ;
        RECT  38.796 9.6 38.88 9.624 ;
    END
  END i[53]
  PIN i[540]
    DIRECTION INPUT ;
    USE SIGNAL ;
    PORT
      LAYER M4 ;
        RECT  38.796 87.792 38.88 87.816 ;
    END
  END i[540]
  PIN i[541]
    DIRECTION INPUT ;
    USE SIGNAL ;
    PORT
      LAYER M4 ;
        RECT  38.796 87.936 38.88 87.96 ;
    END
  END i[541]
  PIN i[542]
    DIRECTION INPUT ;
    USE SIGNAL ;
    PORT
      LAYER M4 ;
        RECT  38.796 88.08 38.88 88.104 ;
    END
  END i[542]
  PIN i[543]
    DIRECTION INPUT ;
    USE SIGNAL ;
    PORT
      LAYER M4 ;
        RECT  38.796 88.272 38.88 88.296 ;
    END
  END i[543]
  PIN i[544]
    DIRECTION INPUT ;
    USE SIGNAL ;
    PORT
      LAYER M4 ;
        RECT  38.796 88.416 38.88 88.44 ;
    END
  END i[544]
  PIN i[545]
    DIRECTION INPUT ;
    USE SIGNAL ;
    PORT
      LAYER M4 ;
        RECT  38.796 88.56 38.88 88.584 ;
    END
  END i[545]
  PIN i[546]
    DIRECTION INPUT ;
    USE SIGNAL ;
    PORT
      LAYER M4 ;
        RECT  38.796 88.752 38.88 88.776 ;
    END
  END i[546]
  PIN i[547]
    DIRECTION INPUT ;
    USE SIGNAL ;
    PORT
      LAYER M4 ;
        RECT  38.796 88.896 38.88 88.92 ;
    END
  END i[547]
  PIN i[548]
    DIRECTION INPUT ;
    USE SIGNAL ;
    PORT
      LAYER M4 ;
        RECT  38.796 89.04 38.88 89.064 ;
    END
  END i[548]
  PIN i[549]
    DIRECTION INPUT ;
    USE SIGNAL ;
    PORT
      LAYER M4 ;
        RECT  38.796 89.232 38.88 89.256 ;
    END
  END i[549]
  PIN i[54]
    DIRECTION INPUT ;
    USE SIGNAL ;
    PORT
      LAYER M4 ;
        RECT  38.796 9.744 38.88 9.768 ;
    END
  END i[54]
  PIN i[550]
    DIRECTION INPUT ;
    USE SIGNAL ;
    PORT
      LAYER M4 ;
        RECT  38.796 89.376 38.88 89.4 ;
    END
  END i[550]
  PIN i[551]
    DIRECTION INPUT ;
    USE SIGNAL ;
    PORT
      LAYER M4 ;
        RECT  38.796 89.52 38.88 89.544 ;
    END
  END i[551]
  PIN i[552]
    DIRECTION INPUT ;
    USE SIGNAL ;
    PORT
      LAYER M4 ;
        RECT  38.796 89.712 38.88 89.736 ;
    END
  END i[552]
  PIN i[553]
    DIRECTION INPUT ;
    USE SIGNAL ;
    PORT
      LAYER M4 ;
        RECT  38.796 89.856 38.88 89.88 ;
    END
  END i[553]
  PIN i[554]
    DIRECTION INPUT ;
    USE SIGNAL ;
    PORT
      LAYER M4 ;
        RECT  38.796 90.048 38.88 90.072 ;
    END
  END i[554]
  PIN i[555]
    DIRECTION INPUT ;
    USE SIGNAL ;
    PORT
      LAYER M4 ;
        RECT  38.796 90.192 38.88 90.216 ;
    END
  END i[555]
  PIN i[556]
    DIRECTION INPUT ;
    USE SIGNAL ;
    PORT
      LAYER M4 ;
        RECT  38.796 90.336 38.88 90.36 ;
    END
  END i[556]
  PIN i[557]
    DIRECTION INPUT ;
    USE SIGNAL ;
    PORT
      LAYER M4 ;
        RECT  38.796 90.528 38.88 90.552 ;
    END
  END i[557]
  PIN i[558]
    DIRECTION INPUT ;
    USE SIGNAL ;
    PORT
      LAYER M4 ;
        RECT  38.796 90.672 38.88 90.696 ;
    END
  END i[558]
  PIN i[559]
    DIRECTION INPUT ;
    USE SIGNAL ;
    PORT
      LAYER M4 ;
        RECT  38.796 90.816 38.88 90.84 ;
    END
  END i[559]
  PIN i[55]
    DIRECTION INPUT ;
    USE SIGNAL ;
    PORT
      LAYER M4 ;
        RECT  38.796 9.888 38.88 9.912 ;
    END
  END i[55]
  PIN i[560]
    DIRECTION INPUT ;
    USE SIGNAL ;
    PORT
      LAYER M4 ;
        RECT  38.796 91.008 38.88 91.032 ;
    END
  END i[560]
  PIN i[561]
    DIRECTION INPUT ;
    USE SIGNAL ;
    PORT
      LAYER M4 ;
        RECT  38.796 91.152 38.88 91.176 ;
    END
  END i[561]
  PIN i[56]
    DIRECTION INPUT ;
    USE SIGNAL ;
    PORT
      LAYER M4 ;
        RECT  38.796 10.08 38.88 10.104 ;
    END
  END i[56]
  PIN i[57]
    DIRECTION INPUT ;
    USE SIGNAL ;
    PORT
      LAYER M4 ;
        RECT  38.796 10.224 38.88 10.248 ;
    END
  END i[57]
  PIN i[58]
    DIRECTION INPUT ;
    USE SIGNAL ;
    PORT
      LAYER M4 ;
        RECT  38.796 10.368 38.88 10.392 ;
    END
  END i[58]
  PIN i[59]
    DIRECTION INPUT ;
    USE SIGNAL ;
    PORT
      LAYER M4 ;
        RECT  38.796 10.56 38.88 10.584 ;
    END
  END i[59]
  PIN i[5]
    DIRECTION INPUT ;
    USE SIGNAL ;
    PORT
      LAYER M4 ;
        RECT  38.796 1.872 38.88 1.896 ;
    END
  END i[5]
  PIN i[60]
    DIRECTION INPUT ;
    USE SIGNAL ;
    PORT
      LAYER M4 ;
        RECT  38.796 10.704 38.88 10.728 ;
    END
  END i[60]
  PIN i[61]
    DIRECTION INPUT ;
    USE SIGNAL ;
    PORT
      LAYER M4 ;
        RECT  38.796 10.848 38.88 10.872 ;
    END
  END i[61]
  PIN i[62]
    DIRECTION INPUT ;
    USE SIGNAL ;
    PORT
      LAYER M4 ;
        RECT  38.796 11.04 38.88 11.064 ;
    END
  END i[62]
  PIN i[63]
    DIRECTION INPUT ;
    USE SIGNAL ;
    PORT
      LAYER M4 ;
        RECT  38.796 11.184 38.88 11.208 ;
    END
  END i[63]
  PIN i[64]
    DIRECTION INPUT ;
    USE SIGNAL ;
    PORT
      LAYER M4 ;
        RECT  38.796 11.328 38.88 11.352 ;
    END
  END i[64]
  PIN i[65]
    DIRECTION INPUT ;
    USE SIGNAL ;
    PORT
      LAYER M4 ;
        RECT  38.796 11.52 38.88 11.544 ;
    END
  END i[65]
  PIN i[66]
    DIRECTION INPUT ;
    USE SIGNAL ;
    PORT
      LAYER M4 ;
        RECT  38.796 11.664 38.88 11.688 ;
    END
  END i[66]
  PIN i[67]
    DIRECTION INPUT ;
    USE SIGNAL ;
    PORT
      LAYER M4 ;
        RECT  38.796 11.808 38.88 11.832 ;
    END
  END i[67]
  PIN i[68]
    DIRECTION INPUT ;
    USE SIGNAL ;
    PORT
      LAYER M4 ;
        RECT  38.796 12 38.88 12.024 ;
    END
  END i[68]
  PIN i[69]
    DIRECTION INPUT ;
    USE SIGNAL ;
    PORT
      LAYER M4 ;
        RECT  38.796 12.144 38.88 12.168 ;
    END
  END i[69]
  PIN i[6]
    DIRECTION INPUT ;
    USE SIGNAL ;
    PORT
      LAYER M4 ;
        RECT  38.796 2.016 38.88 2.04 ;
    END
  END i[6]
  PIN i[70]
    DIRECTION INPUT ;
    USE SIGNAL ;
    PORT
      LAYER M4 ;
        RECT  38.796 12.288 38.88 12.312 ;
    END
  END i[70]
  PIN i[71]
    DIRECTION INPUT ;
    USE SIGNAL ;
    PORT
      LAYER M4 ;
        RECT  38.796 12.48 38.88 12.504 ;
    END
  END i[71]
  PIN i[72]
    DIRECTION INPUT ;
    USE SIGNAL ;
    PORT
      LAYER M4 ;
        RECT  38.796 12.624 38.88 12.648 ;
    END
  END i[72]
  PIN i[73]
    DIRECTION INPUT ;
    USE SIGNAL ;
    PORT
      LAYER M4 ;
        RECT  38.796 12.768 38.88 12.792 ;
    END
  END i[73]
  PIN i[74]
    DIRECTION INPUT ;
    USE SIGNAL ;
    PORT
      LAYER M4 ;
        RECT  38.796 12.96 38.88 12.984 ;
    END
  END i[74]
  PIN i[75]
    DIRECTION INPUT ;
    USE SIGNAL ;
    PORT
      LAYER M4 ;
        RECT  38.796 13.104 38.88 13.128 ;
    END
  END i[75]
  PIN i[76]
    DIRECTION INPUT ;
    USE SIGNAL ;
    PORT
      LAYER M4 ;
        RECT  38.796 13.296 38.88 13.32 ;
    END
  END i[76]
  PIN i[77]
    DIRECTION INPUT ;
    USE SIGNAL ;
    PORT
      LAYER M4 ;
        RECT  38.796 13.44 38.88 13.464 ;
    END
  END i[77]
  PIN i[78]
    DIRECTION INPUT ;
    USE SIGNAL ;
    PORT
      LAYER M4 ;
        RECT  38.796 13.584 38.88 13.608 ;
    END
  END i[78]
  PIN i[79]
    DIRECTION INPUT ;
    USE SIGNAL ;
    PORT
      LAYER M4 ;
        RECT  38.796 13.776 38.88 13.8 ;
    END
  END i[79]
  PIN i[7]
    DIRECTION INPUT ;
    USE SIGNAL ;
    PORT
      LAYER M4 ;
        RECT  38.796 2.208 38.88 2.232 ;
    END
  END i[7]
  PIN i[80]
    DIRECTION INPUT ;
    USE SIGNAL ;
    PORT
      LAYER M4 ;
        RECT  38.796 13.92 38.88 13.944 ;
    END
  END i[80]
  PIN i[81]
    DIRECTION INPUT ;
    USE SIGNAL ;
    PORT
      LAYER M4 ;
        RECT  38.796 14.064 38.88 14.088 ;
    END
  END i[81]
  PIN i[82]
    DIRECTION INPUT ;
    USE SIGNAL ;
    PORT
      LAYER M4 ;
        RECT  38.796 14.256 38.88 14.28 ;
    END
  END i[82]
  PIN i[83]
    DIRECTION INPUT ;
    USE SIGNAL ;
    PORT
      LAYER M4 ;
        RECT  38.796 14.4 38.88 14.424 ;
    END
  END i[83]
  PIN i[84]
    DIRECTION INPUT ;
    USE SIGNAL ;
    PORT
      LAYER M4 ;
        RECT  38.796 14.544 38.88 14.568 ;
    END
  END i[84]
  PIN i[85]
    DIRECTION INPUT ;
    USE SIGNAL ;
    PORT
      LAYER M4 ;
        RECT  38.796 14.736 38.88 14.76 ;
    END
  END i[85]
  PIN i[86]
    DIRECTION INPUT ;
    USE SIGNAL ;
    PORT
      LAYER M4 ;
        RECT  38.796 14.88 38.88 14.904 ;
    END
  END i[86]
  PIN i[87]
    DIRECTION INPUT ;
    USE SIGNAL ;
    PORT
      LAYER M4 ;
        RECT  38.796 15.024 38.88 15.048 ;
    END
  END i[87]
  PIN i[88]
    DIRECTION INPUT ;
    USE SIGNAL ;
    PORT
      LAYER M4 ;
        RECT  38.796 15.216 38.88 15.24 ;
    END
  END i[88]
  PIN i[89]
    DIRECTION INPUT ;
    USE SIGNAL ;
    PORT
      LAYER M4 ;
        RECT  38.796 15.36 38.88 15.384 ;
    END
  END i[89]
  PIN i[8]
    DIRECTION INPUT ;
    USE SIGNAL ;
    PORT
      LAYER M4 ;
        RECT  38.796 2.352 38.88 2.376 ;
    END
  END i[8]
  PIN i[90]
    DIRECTION INPUT ;
    USE SIGNAL ;
    PORT
      LAYER M4 ;
        RECT  38.796 15.504 38.88 15.528 ;
    END
  END i[90]
  PIN i[91]
    DIRECTION INPUT ;
    USE SIGNAL ;
    PORT
      LAYER M4 ;
        RECT  38.796 15.696 38.88 15.72 ;
    END
  END i[91]
  PIN i[92]
    DIRECTION INPUT ;
    USE SIGNAL ;
    PORT
      LAYER M4 ;
        RECT  38.796 15.84 38.88 15.864 ;
    END
  END i[92]
  PIN i[93]
    DIRECTION INPUT ;
    USE SIGNAL ;
    PORT
      LAYER M4 ;
        RECT  38.796 15.984 38.88 16.008 ;
    END
  END i[93]
  PIN i[94]
    DIRECTION INPUT ;
    USE SIGNAL ;
    PORT
      LAYER M4 ;
        RECT  38.796 16.176 38.88 16.2 ;
    END
  END i[94]
  PIN i[95]
    DIRECTION INPUT ;
    USE SIGNAL ;
    PORT
      LAYER M4 ;
        RECT  38.796 16.32 38.88 16.344 ;
    END
  END i[95]
  PIN i[96]
    DIRECTION INPUT ;
    USE SIGNAL ;
    PORT
      LAYER M4 ;
        RECT  38.796 16.464 38.88 16.488 ;
    END
  END i[96]
  PIN i[97]
    DIRECTION INPUT ;
    USE SIGNAL ;
    PORT
      LAYER M4 ;
        RECT  38.796 16.656 38.88 16.68 ;
    END
  END i[97]
  PIN i[98]
    DIRECTION INPUT ;
    USE SIGNAL ;
    PORT
      LAYER M4 ;
        RECT  38.796 16.8 38.88 16.824 ;
    END
  END i[98]
  PIN i[99]
    DIRECTION INPUT ;
    USE SIGNAL ;
    PORT
      LAYER M4 ;
        RECT  38.796 16.944 38.88 16.968 ;
    END
  END i[99]
  PIN i[9]
    DIRECTION INPUT ;
    USE SIGNAL ;
    PORT
      LAYER M4 ;
        RECT  38.796 2.496 38.88 2.52 ;
    END
  END i[9]
  PIN k[0]
    DIRECTION INPUT ;
    USE SIGNAL ;
    PORT
      LAYER M3 ;
        RECT  15.192 95.002 15.21 95.04 ;
    END
    PORT
      LAYER M3 ;
        RECT  15.192 92.897 15.21 95.021 ;
    END
  END k[0]
  PIN k[1]
    DIRECTION INPUT ;
    USE SIGNAL ;
    PORT
      LAYER M5 ;
        RECT  15.6 94.956 15.624 95.04 ;
    END
    PORT
      LAYER M5 ;
        RECT  15.6 92.903 15.624 94.992 ;
    END
  END k[1]
  PIN k[2]
    DIRECTION INPUT ;
    USE SIGNAL ;
    PORT
      LAYER M3 ;
        RECT  15.984 95.002 16.002 95.04 ;
    END
    PORT
      LAYER M3 ;
        RECT  15.984 94.981 16.074 95.009 ;
    END
    PORT
      LAYER M3 ;
        RECT  15.984 95.009 16.002 95.021 ;
    END
  END k[2]
  PIN o[0]
    DIRECTION OUTPUT ;
    USE SIGNAL ;
    PORT
      LAYER M4 ;
        RECT  0 1.056 0.084 1.08 ;
    END
  END o[0]
  PIN o[100]
    DIRECTION OUTPUT ;
    USE SIGNAL ;
    PORT
      LAYER M4 ;
        RECT  0 17.136 0.084 17.16 ;
    END
  END o[100]
  PIN o[101]
    DIRECTION OUTPUT ;
    USE SIGNAL ;
    PORT
      LAYER M4 ;
        RECT  0 17.28 0.084 17.304 ;
    END
  END o[101]
  PIN o[102]
    DIRECTION OUTPUT ;
    USE SIGNAL ;
    PORT
      LAYER M4 ;
        RECT  0 17.424 0.084 17.448 ;
    END
  END o[102]
  PIN o[103]
    DIRECTION OUTPUT ;
    USE SIGNAL ;
    PORT
      LAYER M4 ;
        RECT  0 17.616 0.084 17.64 ;
    END
  END o[103]
  PIN o[104]
    DIRECTION OUTPUT ;
    USE SIGNAL ;
    PORT
      LAYER M4 ;
        RECT  0 17.76 0.084 17.784 ;
    END
  END o[104]
  PIN o[105]
    DIRECTION OUTPUT ;
    USE SIGNAL ;
    PORT
      LAYER M4 ;
        RECT  0 17.952 0.084 17.976 ;
    END
  END o[105]
  PIN o[106]
    DIRECTION OUTPUT ;
    USE SIGNAL ;
    PORT
      LAYER M4 ;
        RECT  0 18.096 0.084 18.12 ;
    END
  END o[106]
  PIN o[107]
    DIRECTION OUTPUT ;
    USE SIGNAL ;
    PORT
      LAYER M4 ;
        RECT  0 18.24 0.084 18.264 ;
    END
  END o[107]
  PIN o[108]
    DIRECTION OUTPUT ;
    USE SIGNAL ;
    PORT
      LAYER M4 ;
        RECT  0 18.432 0.084 18.456 ;
    END
  END o[108]
  PIN o[109]
    DIRECTION OUTPUT ;
    USE SIGNAL ;
    PORT
      LAYER M4 ;
        RECT  0 18.576 0.084 18.6 ;
    END
  END o[109]
  PIN o[10]
    DIRECTION OUTPUT ;
    USE SIGNAL ;
    PORT
      LAYER M4 ;
        RECT  0 2.688 0.084 2.712 ;
    END
  END o[10]
  PIN o[110]
    DIRECTION OUTPUT ;
    USE SIGNAL ;
    PORT
      LAYER M4 ;
        RECT  0 18.72 0.084 18.744 ;
    END
  END o[110]
  PIN o[111]
    DIRECTION OUTPUT ;
    USE SIGNAL ;
    PORT
      LAYER M4 ;
        RECT  0 18.912 0.084 18.936 ;
    END
  END o[111]
  PIN o[112]
    DIRECTION OUTPUT ;
    USE SIGNAL ;
    PORT
      LAYER M4 ;
        RECT  0 19.056 0.084 19.08 ;
    END
  END o[112]
  PIN o[113]
    DIRECTION OUTPUT ;
    USE SIGNAL ;
    PORT
      LAYER M4 ;
        RECT  0 19.2 0.084 19.224 ;
    END
  END o[113]
  PIN o[114]
    DIRECTION OUTPUT ;
    USE SIGNAL ;
    PORT
      LAYER M4 ;
        RECT  0 19.392 0.084 19.416 ;
    END
  END o[114]
  PIN o[115]
    DIRECTION OUTPUT ;
    USE SIGNAL ;
    PORT
      LAYER M4 ;
        RECT  0 19.536 0.084 19.56 ;
    END
  END o[115]
  PIN o[116]
    DIRECTION OUTPUT ;
    USE SIGNAL ;
    PORT
      LAYER M4 ;
        RECT  0 19.68 0.084 19.704 ;
    END
  END o[116]
  PIN o[117]
    DIRECTION OUTPUT ;
    USE SIGNAL ;
    PORT
      LAYER M4 ;
        RECT  0 19.872 0.084 19.896 ;
    END
  END o[117]
  PIN o[118]
    DIRECTION OUTPUT ;
    USE SIGNAL ;
    PORT
      LAYER M4 ;
        RECT  0 20.016 0.084 20.04 ;
    END
  END o[118]
  PIN o[119]
    DIRECTION OUTPUT ;
    USE SIGNAL ;
    PORT
      LAYER M4 ;
        RECT  0 20.16 0.084 20.184 ;
    END
  END o[119]
  PIN o[11]
    DIRECTION OUTPUT ;
    USE SIGNAL ;
    PORT
      LAYER M4 ;
        RECT  0 2.832 0.084 2.856 ;
    END
  END o[11]
  PIN o[120]
    DIRECTION OUTPUT ;
    USE SIGNAL ;
    PORT
      LAYER M4 ;
        RECT  0 20.352 0.084 20.376 ;
    END
  END o[120]
  PIN o[121]
    DIRECTION OUTPUT ;
    USE SIGNAL ;
    PORT
      LAYER M4 ;
        RECT  0 20.496 0.084 20.52 ;
    END
  END o[121]
  PIN o[122]
    DIRECTION OUTPUT ;
    USE SIGNAL ;
    PORT
      LAYER M4 ;
        RECT  0 20.64 0.084 20.664 ;
    END
  END o[122]
  PIN o[123]
    DIRECTION OUTPUT ;
    USE SIGNAL ;
    PORT
      LAYER M4 ;
        RECT  0 20.832 0.084 20.856 ;
    END
  END o[123]
  PIN o[124]
    DIRECTION OUTPUT ;
    USE SIGNAL ;
    PORT
      LAYER M4 ;
        RECT  0 20.976 0.084 21 ;
    END
  END o[124]
  PIN o[125]
    DIRECTION OUTPUT ;
    USE SIGNAL ;
    PORT
      LAYER M4 ;
        RECT  0 21.12 0.084 21.144 ;
    END
  END o[125]
  PIN o[126]
    DIRECTION OUTPUT ;
    USE SIGNAL ;
    PORT
      LAYER M4 ;
        RECT  0 21.312 0.084 21.336 ;
    END
  END o[126]
  PIN o[127]
    DIRECTION OUTPUT ;
    USE SIGNAL ;
    PORT
      LAYER M4 ;
        RECT  0 21.456 0.084 21.48 ;
    END
  END o[127]
  PIN o[128]
    DIRECTION OUTPUT ;
    USE SIGNAL ;
    PORT
      LAYER M4 ;
        RECT  0 21.6 0.084 21.624 ;
    END
  END o[128]
  PIN o[129]
    DIRECTION OUTPUT ;
    USE SIGNAL ;
    PORT
      LAYER M4 ;
        RECT  0 21.792 0.084 21.816 ;
    END
  END o[129]
  PIN o[12]
    DIRECTION OUTPUT ;
    USE SIGNAL ;
    PORT
      LAYER M4 ;
        RECT  0 2.976 0.084 3 ;
    END
  END o[12]
  PIN o[130]
    DIRECTION OUTPUT ;
    USE SIGNAL ;
    PORT
      LAYER M4 ;
        RECT  0 21.936 0.084 21.96 ;
    END
  END o[130]
  PIN o[131]
    DIRECTION OUTPUT ;
    USE SIGNAL ;
    PORT
      LAYER M4 ;
        RECT  0 22.08 0.084 22.104 ;
    END
  END o[131]
  PIN o[132]
    DIRECTION OUTPUT ;
    USE SIGNAL ;
    PORT
      LAYER M4 ;
        RECT  0 22.272 0.084 22.296 ;
    END
  END o[132]
  PIN o[133]
    DIRECTION OUTPUT ;
    USE SIGNAL ;
    PORT
      LAYER M4 ;
        RECT  0 22.416 0.084 22.44 ;
    END
  END o[133]
  PIN o[134]
    DIRECTION OUTPUT ;
    USE SIGNAL ;
    PORT
      LAYER M4 ;
        RECT  0 22.608 0.084 22.632 ;
    END
  END o[134]
  PIN o[135]
    DIRECTION OUTPUT ;
    USE SIGNAL ;
    PORT
      LAYER M4 ;
        RECT  0 22.752 0.084 22.776 ;
    END
  END o[135]
  PIN o[136]
    DIRECTION OUTPUT ;
    USE SIGNAL ;
    PORT
      LAYER M4 ;
        RECT  0 22.896 0.084 22.92 ;
    END
  END o[136]
  PIN o[137]
    DIRECTION OUTPUT ;
    USE SIGNAL ;
    PORT
      LAYER M4 ;
        RECT  0 23.088 0.084 23.112 ;
    END
  END o[137]
  PIN o[138]
    DIRECTION OUTPUT ;
    USE SIGNAL ;
    PORT
      LAYER M4 ;
        RECT  0 23.232 0.084 23.256 ;
    END
  END o[138]
  PIN o[139]
    DIRECTION OUTPUT ;
    USE SIGNAL ;
    PORT
      LAYER M4 ;
        RECT  0 23.376 0.084 23.4 ;
    END
  END o[139]
  PIN o[13]
    DIRECTION OUTPUT ;
    USE SIGNAL ;
    PORT
      LAYER M4 ;
        RECT  0 3.168 0.084 3.192 ;
    END
  END o[13]
  PIN o[140]
    DIRECTION OUTPUT ;
    USE SIGNAL ;
    PORT
      LAYER M4 ;
        RECT  0 23.568 0.084 23.592 ;
    END
  END o[140]
  PIN o[141]
    DIRECTION OUTPUT ;
    USE SIGNAL ;
    PORT
      LAYER M4 ;
        RECT  0 23.712 0.084 23.736 ;
    END
  END o[141]
  PIN o[142]
    DIRECTION OUTPUT ;
    USE SIGNAL ;
    PORT
      LAYER M4 ;
        RECT  0 23.856 0.084 23.88 ;
    END
  END o[142]
  PIN o[143]
    DIRECTION OUTPUT ;
    USE SIGNAL ;
    PORT
      LAYER M4 ;
        RECT  0 24.048 0.084 24.072 ;
    END
  END o[143]
  PIN o[144]
    DIRECTION OUTPUT ;
    USE SIGNAL ;
    PORT
      LAYER M4 ;
        RECT  0 24.192 0.084 24.216 ;
    END
  END o[144]
  PIN o[145]
    DIRECTION OUTPUT ;
    USE SIGNAL ;
    PORT
      LAYER M4 ;
        RECT  0 24.336 0.084 24.36 ;
    END
  END o[145]
  PIN o[146]
    DIRECTION OUTPUT ;
    USE SIGNAL ;
    PORT
      LAYER M4 ;
        RECT  0 24.528 0.084 24.552 ;
    END
  END o[146]
  PIN o[147]
    DIRECTION OUTPUT ;
    USE SIGNAL ;
    PORT
      LAYER M4 ;
        RECT  0 24.672 0.084 24.696 ;
    END
  END o[147]
  PIN o[148]
    DIRECTION OUTPUT ;
    USE SIGNAL ;
    PORT
      LAYER M4 ;
        RECT  0 24.816 0.084 24.84 ;
    END
  END o[148]
  PIN o[149]
    DIRECTION OUTPUT ;
    USE SIGNAL ;
    PORT
      LAYER M4 ;
        RECT  0 25.008 0.084 25.032 ;
    END
  END o[149]
  PIN o[14]
    DIRECTION OUTPUT ;
    USE SIGNAL ;
    PORT
      LAYER M4 ;
        RECT  0 3.312 0.084 3.336 ;
    END
  END o[14]
  PIN o[150]
    DIRECTION OUTPUT ;
    USE SIGNAL ;
    PORT
      LAYER M4 ;
        RECT  0 25.152 0.084 25.176 ;
    END
  END o[150]
  PIN o[151]
    DIRECTION OUTPUT ;
    USE SIGNAL ;
    PORT
      LAYER M4 ;
        RECT  0 25.296 0.084 25.32 ;
    END
  END o[151]
  PIN o[152]
    DIRECTION OUTPUT ;
    USE SIGNAL ;
    PORT
      LAYER M4 ;
        RECT  0 25.488 0.084 25.512 ;
    END
  END o[152]
  PIN o[153]
    DIRECTION OUTPUT ;
    USE SIGNAL ;
    PORT
      LAYER M4 ;
        RECT  0 25.632 0.084 25.656 ;
    END
  END o[153]
  PIN o[154]
    DIRECTION OUTPUT ;
    USE SIGNAL ;
    PORT
      LAYER M4 ;
        RECT  0 25.776 0.084 25.8 ;
    END
  END o[154]
  PIN o[155]
    DIRECTION OUTPUT ;
    USE SIGNAL ;
    PORT
      LAYER M4 ;
        RECT  0 25.968 0.084 25.992 ;
    END
  END o[155]
  PIN o[156]
    DIRECTION OUTPUT ;
    USE SIGNAL ;
    PORT
      LAYER M4 ;
        RECT  0 26.112 0.084 26.136 ;
    END
  END o[156]
  PIN o[157]
    DIRECTION OUTPUT ;
    USE SIGNAL ;
    PORT
      LAYER M4 ;
        RECT  0 26.256 0.084 26.28 ;
    END
  END o[157]
  PIN o[158]
    DIRECTION OUTPUT ;
    USE SIGNAL ;
    PORT
      LAYER M4 ;
        RECT  0 26.448 0.084 26.472 ;
    END
  END o[158]
  PIN o[159]
    DIRECTION OUTPUT ;
    USE SIGNAL ;
    PORT
      LAYER M4 ;
        RECT  0 26.592 0.084 26.616 ;
    END
  END o[159]
  PIN o[15]
    DIRECTION OUTPUT ;
    USE SIGNAL ;
    PORT
      LAYER M4 ;
        RECT  0 3.456 0.084 3.48 ;
    END
  END o[15]
  PIN o[160]
    DIRECTION OUTPUT ;
    USE SIGNAL ;
    PORT
      LAYER M4 ;
        RECT  0 26.736 0.084 26.76 ;
    END
  END o[160]
  PIN o[161]
    DIRECTION OUTPUT ;
    USE SIGNAL ;
    PORT
      LAYER M4 ;
        RECT  0 26.928 0.084 26.952 ;
    END
  END o[161]
  PIN o[162]
    DIRECTION OUTPUT ;
    USE SIGNAL ;
    PORT
      LAYER M4 ;
        RECT  0 27.072 0.084 27.096 ;
    END
  END o[162]
  PIN o[163]
    DIRECTION OUTPUT ;
    USE SIGNAL ;
    PORT
      LAYER M4 ;
        RECT  0 27.264 0.084 27.288 ;
    END
  END o[163]
  PIN o[164]
    DIRECTION OUTPUT ;
    USE SIGNAL ;
    PORT
      LAYER M4 ;
        RECT  0 27.408 0.084 27.432 ;
    END
  END o[164]
  PIN o[165]
    DIRECTION OUTPUT ;
    USE SIGNAL ;
    PORT
      LAYER M4 ;
        RECT  0 27.552 0.084 27.576 ;
    END
  END o[165]
  PIN o[166]
    DIRECTION OUTPUT ;
    USE SIGNAL ;
    PORT
      LAYER M4 ;
        RECT  0 27.744 0.084 27.768 ;
    END
  END o[166]
  PIN o[167]
    DIRECTION OUTPUT ;
    USE SIGNAL ;
    PORT
      LAYER M4 ;
        RECT  0 27.888 0.084 27.912 ;
    END
  END o[167]
  PIN o[168]
    DIRECTION OUTPUT ;
    USE SIGNAL ;
    PORT
      LAYER M4 ;
        RECT  0 28.032 0.084 28.056 ;
    END
  END o[168]
  PIN o[169]
    DIRECTION OUTPUT ;
    USE SIGNAL ;
    PORT
      LAYER M4 ;
        RECT  0 28.224 0.084 28.248 ;
    END
  END o[169]
  PIN o[16]
    DIRECTION OUTPUT ;
    USE SIGNAL ;
    PORT
      LAYER M4 ;
        RECT  0 3.648 0.084 3.672 ;
    END
  END o[16]
  PIN o[170]
    DIRECTION OUTPUT ;
    USE SIGNAL ;
    PORT
      LAYER M4 ;
        RECT  0 28.368 0.084 28.392 ;
    END
  END o[170]
  PIN o[171]
    DIRECTION OUTPUT ;
    USE SIGNAL ;
    PORT
      LAYER M4 ;
        RECT  0 28.512 0.084 28.536 ;
    END
  END o[171]
  PIN o[172]
    DIRECTION OUTPUT ;
    USE SIGNAL ;
    PORT
      LAYER M4 ;
        RECT  0 28.704 0.084 28.728 ;
    END
  END o[172]
  PIN o[173]
    DIRECTION OUTPUT ;
    USE SIGNAL ;
    PORT
      LAYER M4 ;
        RECT  0 28.848 0.084 28.872 ;
    END
  END o[173]
  PIN o[174]
    DIRECTION OUTPUT ;
    USE SIGNAL ;
    PORT
      LAYER M4 ;
        RECT  0 28.992 0.084 29.016 ;
    END
  END o[174]
  PIN o[175]
    DIRECTION OUTPUT ;
    USE SIGNAL ;
    PORT
      LAYER M4 ;
        RECT  0 29.184 0.084 29.208 ;
    END
  END o[175]
  PIN o[176]
    DIRECTION OUTPUT ;
    USE SIGNAL ;
    PORT
      LAYER M4 ;
        RECT  0 29.328 0.084 29.352 ;
    END
  END o[176]
  PIN o[177]
    DIRECTION OUTPUT ;
    USE SIGNAL ;
    PORT
      LAYER M4 ;
        RECT  0 29.472 0.084 29.496 ;
    END
  END o[177]
  PIN o[178]
    DIRECTION OUTPUT ;
    USE SIGNAL ;
    PORT
      LAYER M4 ;
        RECT  0 29.664 0.084 29.688 ;
    END
  END o[178]
  PIN o[179]
    DIRECTION OUTPUT ;
    USE SIGNAL ;
    PORT
      LAYER M4 ;
        RECT  0 29.808 0.084 29.832 ;
    END
  END o[179]
  PIN o[17]
    DIRECTION OUTPUT ;
    USE SIGNAL ;
    PORT
      LAYER M4 ;
        RECT  0 3.792 0.084 3.816 ;
    END
  END o[17]
  PIN o[180]
    DIRECTION OUTPUT ;
    USE SIGNAL ;
    PORT
      LAYER M4 ;
        RECT  0 29.952 0.084 29.976 ;
    END
  END o[180]
  PIN o[181]
    DIRECTION OUTPUT ;
    USE SIGNAL ;
    PORT
      LAYER M4 ;
        RECT  0 30.144 0.084 30.168 ;
    END
  END o[181]
  PIN o[182]
    DIRECTION OUTPUT ;
    USE SIGNAL ;
    PORT
      LAYER M4 ;
        RECT  0 30.288 0.084 30.312 ;
    END
  END o[182]
  PIN o[183]
    DIRECTION OUTPUT ;
    USE SIGNAL ;
    PORT
      LAYER M4 ;
        RECT  0 30.432 0.084 30.456 ;
    END
  END o[183]
  PIN o[184]
    DIRECTION OUTPUT ;
    USE SIGNAL ;
    PORT
      LAYER M4 ;
        RECT  0 30.624 0.084 30.648 ;
    END
  END o[184]
  PIN o[185]
    DIRECTION OUTPUT ;
    USE SIGNAL ;
    PORT
      LAYER M4 ;
        RECT  0 30.768 0.084 30.792 ;
    END
  END o[185]
  PIN o[186]
    DIRECTION OUTPUT ;
    USE SIGNAL ;
    PORT
      LAYER M4 ;
        RECT  0 30.912 0.084 30.936 ;
    END
  END o[186]
  PIN o[187]
    DIRECTION OUTPUT ;
    USE SIGNAL ;
    PORT
      LAYER M4 ;
        RECT  0 31.104 0.084 31.128 ;
    END
  END o[187]
  PIN o[188]
    DIRECTION OUTPUT ;
    USE SIGNAL ;
    PORT
      LAYER M4 ;
        RECT  0 31.248 0.084 31.272 ;
    END
  END o[188]
  PIN o[189]
    DIRECTION OUTPUT ;
    USE SIGNAL ;
    PORT
      LAYER M4 ;
        RECT  0 31.44 0.084 31.464 ;
    END
  END o[189]
  PIN o[18]
    DIRECTION OUTPUT ;
    USE SIGNAL ;
    PORT
      LAYER M4 ;
        RECT  0 3.936 0.084 3.96 ;
    END
  END o[18]
  PIN o[190]
    DIRECTION OUTPUT ;
    USE SIGNAL ;
    PORT
      LAYER M4 ;
        RECT  0 31.584 0.084 31.608 ;
    END
  END o[190]
  PIN o[191]
    DIRECTION OUTPUT ;
    USE SIGNAL ;
    PORT
      LAYER M4 ;
        RECT  0 31.728 0.084 31.752 ;
    END
  END o[191]
  PIN o[192]
    DIRECTION OUTPUT ;
    USE SIGNAL ;
    PORT
      LAYER M4 ;
        RECT  0 31.92 0.084 31.944 ;
    END
  END o[192]
  PIN o[193]
    DIRECTION OUTPUT ;
    USE SIGNAL ;
    PORT
      LAYER M4 ;
        RECT  0 32.064 0.084 32.088 ;
    END
  END o[193]
  PIN o[194]
    DIRECTION OUTPUT ;
    USE SIGNAL ;
    PORT
      LAYER M4 ;
        RECT  0 32.208 0.084 32.232 ;
    END
  END o[194]
  PIN o[195]
    DIRECTION OUTPUT ;
    USE SIGNAL ;
    PORT
      LAYER M4 ;
        RECT  0 32.4 0.084 32.424 ;
    END
  END o[195]
  PIN o[196]
    DIRECTION OUTPUT ;
    USE SIGNAL ;
    PORT
      LAYER M4 ;
        RECT  0 32.544 0.084 32.568 ;
    END
  END o[196]
  PIN o[197]
    DIRECTION OUTPUT ;
    USE SIGNAL ;
    PORT
      LAYER M4 ;
        RECT  0 32.688 0.084 32.712 ;
    END
  END o[197]
  PIN o[198]
    DIRECTION OUTPUT ;
    USE SIGNAL ;
    PORT
      LAYER M4 ;
        RECT  0 32.88 0.084 32.904 ;
    END
  END o[198]
  PIN o[199]
    DIRECTION OUTPUT ;
    USE SIGNAL ;
    PORT
      LAYER M4 ;
        RECT  0 33.024 0.084 33.048 ;
    END
  END o[199]
  PIN o[19]
    DIRECTION OUTPUT ;
    USE SIGNAL ;
    PORT
      LAYER M4 ;
        RECT  0 4.128 0.084 4.152 ;
    END
  END o[19]
  PIN o[1]
    DIRECTION OUTPUT ;
    USE SIGNAL ;
    PORT
      LAYER M4 ;
        RECT  0 1.248 0.084 1.272 ;
    END
  END o[1]
  PIN o[200]
    DIRECTION OUTPUT ;
    USE SIGNAL ;
    PORT
      LAYER M4 ;
        RECT  0 33.168 0.084 33.192 ;
    END
  END o[200]
  PIN o[201]
    DIRECTION OUTPUT ;
    USE SIGNAL ;
    PORT
      LAYER M4 ;
        RECT  0 33.36 0.084 33.384 ;
    END
  END o[201]
  PIN o[202]
    DIRECTION OUTPUT ;
    USE SIGNAL ;
    PORT
      LAYER M4 ;
        RECT  0 33.504 0.084 33.528 ;
    END
  END o[202]
  PIN o[203]
    DIRECTION OUTPUT ;
    USE SIGNAL ;
    PORT
      LAYER M4 ;
        RECT  0 33.648 0.084 33.672 ;
    END
  END o[203]
  PIN o[204]
    DIRECTION OUTPUT ;
    USE SIGNAL ;
    PORT
      LAYER M4 ;
        RECT  0 33.84 0.084 33.864 ;
    END
  END o[204]
  PIN o[205]
    DIRECTION OUTPUT ;
    USE SIGNAL ;
    PORT
      LAYER M4 ;
        RECT  0 33.984 0.084 34.008 ;
    END
  END o[205]
  PIN o[206]
    DIRECTION OUTPUT ;
    USE SIGNAL ;
    PORT
      LAYER M4 ;
        RECT  0 34.128 0.084 34.152 ;
    END
  END o[206]
  PIN o[207]
    DIRECTION OUTPUT ;
    USE SIGNAL ;
    PORT
      LAYER M4 ;
        RECT  0 34.32 0.084 34.344 ;
    END
  END o[207]
  PIN o[208]
    DIRECTION OUTPUT ;
    USE SIGNAL ;
    PORT
      LAYER M4 ;
        RECT  0 34.464 0.084 34.488 ;
    END
  END o[208]
  PIN o[209]
    DIRECTION OUTPUT ;
    USE SIGNAL ;
    PORT
      LAYER M4 ;
        RECT  0 34.608 0.084 34.632 ;
    END
  END o[209]
  PIN o[20]
    DIRECTION OUTPUT ;
    USE SIGNAL ;
    PORT
      LAYER M4 ;
        RECT  0 4.272 0.084 4.296 ;
    END
  END o[20]
  PIN o[210]
    DIRECTION OUTPUT ;
    USE SIGNAL ;
    PORT
      LAYER M4 ;
        RECT  0 34.8 0.084 34.824 ;
    END
  END o[210]
  PIN o[211]
    DIRECTION OUTPUT ;
    USE SIGNAL ;
    PORT
      LAYER M4 ;
        RECT  0 34.944 0.084 34.968 ;
    END
  END o[211]
  PIN o[212]
    DIRECTION OUTPUT ;
    USE SIGNAL ;
    PORT
      LAYER M4 ;
        RECT  0 35.088 0.084 35.112 ;
    END
  END o[212]
  PIN o[213]
    DIRECTION OUTPUT ;
    USE SIGNAL ;
    PORT
      LAYER M4 ;
        RECT  0 35.28 0.084 35.304 ;
    END
  END o[213]
  PIN o[214]
    DIRECTION OUTPUT ;
    USE SIGNAL ;
    PORT
      LAYER M4 ;
        RECT  0 35.424 0.084 35.448 ;
    END
  END o[214]
  PIN o[215]
    DIRECTION OUTPUT ;
    USE SIGNAL ;
    PORT
      LAYER M4 ;
        RECT  0 35.568 0.084 35.592 ;
    END
  END o[215]
  PIN o[216]
    DIRECTION OUTPUT ;
    USE SIGNAL ;
    PORT
      LAYER M4 ;
        RECT  0 35.76 0.084 35.784 ;
    END
  END o[216]
  PIN o[217]
    DIRECTION OUTPUT ;
    USE SIGNAL ;
    PORT
      LAYER M4 ;
        RECT  0 35.904 0.084 35.928 ;
    END
  END o[217]
  PIN o[218]
    DIRECTION OUTPUT ;
    USE SIGNAL ;
    PORT
      LAYER M4 ;
        RECT  0 36.096 0.084 36.12 ;
    END
  END o[218]
  PIN o[219]
    DIRECTION OUTPUT ;
    USE SIGNAL ;
    PORT
      LAYER M4 ;
        RECT  0 36.24 0.084 36.264 ;
    END
  END o[219]
  PIN o[21]
    DIRECTION OUTPUT ;
    USE SIGNAL ;
    PORT
      LAYER M4 ;
        RECT  0 4.464 0.084 4.488 ;
    END
  END o[21]
  PIN o[220]
    DIRECTION OUTPUT ;
    USE SIGNAL ;
    PORT
      LAYER M4 ;
        RECT  0 36.384 0.084 36.408 ;
    END
  END o[220]
  PIN o[221]
    DIRECTION OUTPUT ;
    USE SIGNAL ;
    PORT
      LAYER M4 ;
        RECT  0 36.576 0.084 36.6 ;
    END
  END o[221]
  PIN o[222]
    DIRECTION OUTPUT ;
    USE SIGNAL ;
    PORT
      LAYER M4 ;
        RECT  0 36.72 0.084 36.744 ;
    END
  END o[222]
  PIN o[223]
    DIRECTION OUTPUT ;
    USE SIGNAL ;
    PORT
      LAYER M4 ;
        RECT  0 36.864 0.084 36.888 ;
    END
  END o[223]
  PIN o[224]
    DIRECTION OUTPUT ;
    USE SIGNAL ;
    PORT
      LAYER M4 ;
        RECT  0 37.056 0.084 37.08 ;
    END
  END o[224]
  PIN o[225]
    DIRECTION OUTPUT ;
    USE SIGNAL ;
    PORT
      LAYER M4 ;
        RECT  0 37.2 0.084 37.224 ;
    END
  END o[225]
  PIN o[226]
    DIRECTION OUTPUT ;
    USE SIGNAL ;
    PORT
      LAYER M4 ;
        RECT  0 37.344 0.084 37.368 ;
    END
  END o[226]
  PIN o[227]
    DIRECTION OUTPUT ;
    USE SIGNAL ;
    PORT
      LAYER M4 ;
        RECT  0 37.536 0.084 37.56 ;
    END
  END o[227]
  PIN o[228]
    DIRECTION OUTPUT ;
    USE SIGNAL ;
    PORT
      LAYER M4 ;
        RECT  0 37.68 0.084 37.704 ;
    END
  END o[228]
  PIN o[229]
    DIRECTION OUTPUT ;
    USE SIGNAL ;
    PORT
      LAYER M4 ;
        RECT  0 37.824 0.084 37.848 ;
    END
  END o[229]
  PIN o[22]
    DIRECTION OUTPUT ;
    USE SIGNAL ;
    PORT
      LAYER M4 ;
        RECT  0 4.608 0.084 4.632 ;
    END
  END o[22]
  PIN o[230]
    DIRECTION OUTPUT ;
    USE SIGNAL ;
    PORT
      LAYER M4 ;
        RECT  0 38.016 0.084 38.04 ;
    END
  END o[230]
  PIN o[231]
    DIRECTION OUTPUT ;
    USE SIGNAL ;
    PORT
      LAYER M4 ;
        RECT  0 38.16 0.084 38.184 ;
    END
  END o[231]
  PIN o[232]
    DIRECTION OUTPUT ;
    USE SIGNAL ;
    PORT
      LAYER M4 ;
        RECT  0 38.304 0.084 38.328 ;
    END
  END o[232]
  PIN o[233]
    DIRECTION OUTPUT ;
    USE SIGNAL ;
    PORT
      LAYER M4 ;
        RECT  0 38.496 0.084 38.52 ;
    END
  END o[233]
  PIN o[234]
    DIRECTION OUTPUT ;
    USE SIGNAL ;
    PORT
      LAYER M4 ;
        RECT  0 38.64 0.084 38.664 ;
    END
  END o[234]
  PIN o[235]
    DIRECTION OUTPUT ;
    USE SIGNAL ;
    PORT
      LAYER M4 ;
        RECT  0 38.784 0.084 38.808 ;
    END
  END o[235]
  PIN o[236]
    DIRECTION OUTPUT ;
    USE SIGNAL ;
    PORT
      LAYER M4 ;
        RECT  0 38.976 0.084 39 ;
    END
  END o[236]
  PIN o[237]
    DIRECTION OUTPUT ;
    USE SIGNAL ;
    PORT
      LAYER M4 ;
        RECT  0 39.12 0.084 39.144 ;
    END
  END o[237]
  PIN o[238]
    DIRECTION OUTPUT ;
    USE SIGNAL ;
    PORT
      LAYER M4 ;
        RECT  0 39.264 0.084 39.288 ;
    END
  END o[238]
  PIN o[239]
    DIRECTION OUTPUT ;
    USE SIGNAL ;
    PORT
      LAYER M4 ;
        RECT  0 39.456 0.084 39.48 ;
    END
  END o[239]
  PIN o[23]
    DIRECTION OUTPUT ;
    USE SIGNAL ;
    PORT
      LAYER M4 ;
        RECT  0 4.752 0.084 4.776 ;
    END
  END o[23]
  PIN o[240]
    DIRECTION OUTPUT ;
    USE SIGNAL ;
    PORT
      LAYER M4 ;
        RECT  0 39.6 0.084 39.624 ;
    END
  END o[240]
  PIN o[241]
    DIRECTION OUTPUT ;
    USE SIGNAL ;
    PORT
      LAYER M4 ;
        RECT  0 39.744 0.084 39.768 ;
    END
  END o[241]
  PIN o[242]
    DIRECTION OUTPUT ;
    USE SIGNAL ;
    PORT
      LAYER M4 ;
        RECT  0 39.936 0.084 39.96 ;
    END
  END o[242]
  PIN o[243]
    DIRECTION OUTPUT ;
    USE SIGNAL ;
    PORT
      LAYER M4 ;
        RECT  0 40.08 0.084 40.104 ;
    END
  END o[243]
  PIN o[244]
    DIRECTION OUTPUT ;
    USE SIGNAL ;
    PORT
      LAYER M4 ;
        RECT  0 40.224 0.084 40.248 ;
    END
  END o[244]
  PIN o[245]
    DIRECTION OUTPUT ;
    USE SIGNAL ;
    PORT
      LAYER M4 ;
        RECT  0 40.416 0.084 40.44 ;
    END
  END o[245]
  PIN o[246]
    DIRECTION OUTPUT ;
    USE SIGNAL ;
    PORT
      LAYER M4 ;
        RECT  0 40.56 0.084 40.584 ;
    END
  END o[246]
  PIN o[247]
    DIRECTION OUTPUT ;
    USE SIGNAL ;
    PORT
      LAYER M4 ;
        RECT  0 40.752 0.084 40.776 ;
    END
  END o[247]
  PIN o[248]
    DIRECTION OUTPUT ;
    USE SIGNAL ;
    PORT
      LAYER M4 ;
        RECT  0 40.896 0.084 40.92 ;
    END
  END o[248]
  PIN o[249]
    DIRECTION OUTPUT ;
    USE SIGNAL ;
    PORT
      LAYER M4 ;
        RECT  0 41.04 0.084 41.064 ;
    END
  END o[249]
  PIN o[24]
    DIRECTION OUTPUT ;
    USE SIGNAL ;
    PORT
      LAYER M4 ;
        RECT  0 4.944 0.084 4.968 ;
    END
  END o[24]
  PIN o[250]
    DIRECTION OUTPUT ;
    USE SIGNAL ;
    PORT
      LAYER M4 ;
        RECT  0 41.232 0.084 41.256 ;
    END
  END o[250]
  PIN o[251]
    DIRECTION OUTPUT ;
    USE SIGNAL ;
    PORT
      LAYER M4 ;
        RECT  0 41.376 0.084 41.4 ;
    END
  END o[251]
  PIN o[252]
    DIRECTION OUTPUT ;
    USE SIGNAL ;
    PORT
      LAYER M4 ;
        RECT  0 41.52 0.084 41.544 ;
    END
  END o[252]
  PIN o[253]
    DIRECTION OUTPUT ;
    USE SIGNAL ;
    PORT
      LAYER M4 ;
        RECT  0 41.712 0.084 41.736 ;
    END
  END o[253]
  PIN o[254]
    DIRECTION OUTPUT ;
    USE SIGNAL ;
    PORT
      LAYER M4 ;
        RECT  0 41.856 0.084 41.88 ;
    END
  END o[254]
  PIN o[255]
    DIRECTION OUTPUT ;
    USE SIGNAL ;
    PORT
      LAYER M4 ;
        RECT  0 42 0.084 42.024 ;
    END
  END o[255]
  PIN o[256]
    DIRECTION OUTPUT ;
    USE SIGNAL ;
    PORT
      LAYER M4 ;
        RECT  0 42.192 0.084 42.216 ;
    END
  END o[256]
  PIN o[257]
    DIRECTION OUTPUT ;
    USE SIGNAL ;
    PORT
      LAYER M4 ;
        RECT  0 42.336 0.084 42.36 ;
    END
  END o[257]
  PIN o[258]
    DIRECTION OUTPUT ;
    USE SIGNAL ;
    PORT
      LAYER M4 ;
        RECT  0 42.48 0.084 42.504 ;
    END
  END o[258]
  PIN o[259]
    DIRECTION OUTPUT ;
    USE SIGNAL ;
    PORT
      LAYER M4 ;
        RECT  0 42.672 0.084 42.696 ;
    END
  END o[259]
  PIN o[25]
    DIRECTION OUTPUT ;
    USE SIGNAL ;
    PORT
      LAYER M4 ;
        RECT  0 5.088 0.084 5.112 ;
    END
  END o[25]
  PIN o[260]
    DIRECTION OUTPUT ;
    USE SIGNAL ;
    PORT
      LAYER M4 ;
        RECT  0 42.816 0.084 42.84 ;
    END
  END o[260]
  PIN o[261]
    DIRECTION OUTPUT ;
    USE SIGNAL ;
    PORT
      LAYER M4 ;
        RECT  0 42.96 0.084 42.984 ;
    END
  END o[261]
  PIN o[262]
    DIRECTION OUTPUT ;
    USE SIGNAL ;
    PORT
      LAYER M4 ;
        RECT  0 43.152 0.084 43.176 ;
    END
  END o[262]
  PIN o[263]
    DIRECTION OUTPUT ;
    USE SIGNAL ;
    PORT
      LAYER M4 ;
        RECT  0 43.296 0.084 43.32 ;
    END
  END o[263]
  PIN o[264]
    DIRECTION OUTPUT ;
    USE SIGNAL ;
    PORT
      LAYER M4 ;
        RECT  0 43.44 0.084 43.464 ;
    END
  END o[264]
  PIN o[265]
    DIRECTION OUTPUT ;
    USE SIGNAL ;
    PORT
      LAYER M4 ;
        RECT  0 43.632 0.084 43.656 ;
    END
  END o[265]
  PIN o[266]
    DIRECTION OUTPUT ;
    USE SIGNAL ;
    PORT
      LAYER M4 ;
        RECT  0 43.776 0.084 43.8 ;
    END
  END o[266]
  PIN o[267]
    DIRECTION OUTPUT ;
    USE SIGNAL ;
    PORT
      LAYER M4 ;
        RECT  0 43.92 0.084 43.944 ;
    END
  END o[267]
  PIN o[268]
    DIRECTION OUTPUT ;
    USE SIGNAL ;
    PORT
      LAYER M4 ;
        RECT  0 44.112 0.084 44.136 ;
    END
  END o[268]
  PIN o[269]
    DIRECTION OUTPUT ;
    USE SIGNAL ;
    PORT
      LAYER M4 ;
        RECT  0 44.256 0.084 44.28 ;
    END
  END o[269]
  PIN o[26]
    DIRECTION OUTPUT ;
    USE SIGNAL ;
    PORT
      LAYER M4 ;
        RECT  0 5.232 0.084 5.256 ;
    END
  END o[26]
  PIN o[270]
    DIRECTION OUTPUT ;
    USE SIGNAL ;
    PORT
      LAYER M4 ;
        RECT  0 44.4 0.084 44.424 ;
    END
  END o[270]
  PIN o[271]
    DIRECTION OUTPUT ;
    USE SIGNAL ;
    PORT
      LAYER M4 ;
        RECT  0 44.592 0.084 44.616 ;
    END
  END o[271]
  PIN o[272]
    DIRECTION OUTPUT ;
    USE SIGNAL ;
    PORT
      LAYER M4 ;
        RECT  0 44.736 0.084 44.76 ;
    END
  END o[272]
  PIN o[273]
    DIRECTION OUTPUT ;
    USE SIGNAL ;
    PORT
      LAYER M4 ;
        RECT  0 44.928 0.084 44.952 ;
    END
  END o[273]
  PIN o[274]
    DIRECTION OUTPUT ;
    USE SIGNAL ;
    PORT
      LAYER M4 ;
        RECT  0 45.072 0.084 45.096 ;
    END
  END o[274]
  PIN o[275]
    DIRECTION OUTPUT ;
    USE SIGNAL ;
    PORT
      LAYER M4 ;
        RECT  0 45.216 0.084 45.24 ;
    END
  END o[275]
  PIN o[276]
    DIRECTION OUTPUT ;
    USE SIGNAL ;
    PORT
      LAYER M4 ;
        RECT  0 45.408 0.084 45.432 ;
    END
  END o[276]
  PIN o[277]
    DIRECTION OUTPUT ;
    USE SIGNAL ;
    PORT
      LAYER M4 ;
        RECT  0 45.552 0.084 45.576 ;
    END
  END o[277]
  PIN o[278]
    DIRECTION OUTPUT ;
    USE SIGNAL ;
    PORT
      LAYER M4 ;
        RECT  0 45.696 0.084 45.72 ;
    END
  END o[278]
  PIN o[279]
    DIRECTION OUTPUT ;
    USE SIGNAL ;
    PORT
      LAYER M4 ;
        RECT  0 45.888 0.084 45.912 ;
    END
  END o[279]
  PIN o[27]
    DIRECTION OUTPUT ;
    USE SIGNAL ;
    PORT
      LAYER M4 ;
        RECT  0 5.424 0.084 5.448 ;
    END
  END o[27]
  PIN o[280]
    DIRECTION OUTPUT ;
    USE SIGNAL ;
    PORT
      LAYER M4 ;
        RECT  0 46.032 0.084 46.056 ;
    END
  END o[280]
  PIN o[281]
    DIRECTION OUTPUT ;
    USE SIGNAL ;
    PORT
      LAYER M4 ;
        RECT  0 46.176 0.084 46.2 ;
    END
  END o[281]
  PIN o[282]
    DIRECTION OUTPUT ;
    USE SIGNAL ;
    PORT
      LAYER M4 ;
        RECT  0 46.368 0.084 46.392 ;
    END
  END o[282]
  PIN o[283]
    DIRECTION OUTPUT ;
    USE SIGNAL ;
    PORT
      LAYER M4 ;
        RECT  0 46.512 0.084 46.536 ;
    END
  END o[283]
  PIN o[284]
    DIRECTION OUTPUT ;
    USE SIGNAL ;
    PORT
      LAYER M4 ;
        RECT  0 46.656 0.084 46.68 ;
    END
  END o[284]
  PIN o[285]
    DIRECTION OUTPUT ;
    USE SIGNAL ;
    PORT
      LAYER M4 ;
        RECT  0 46.848 0.084 46.872 ;
    END
  END o[285]
  PIN o[286]
    DIRECTION OUTPUT ;
    USE SIGNAL ;
    PORT
      LAYER M4 ;
        RECT  0 46.992 0.084 47.016 ;
    END
  END o[286]
  PIN o[287]
    DIRECTION OUTPUT ;
    USE SIGNAL ;
    PORT
      LAYER M4 ;
        RECT  0 47.136 0.084 47.16 ;
    END
  END o[287]
  PIN o[288]
    DIRECTION OUTPUT ;
    USE SIGNAL ;
    PORT
      LAYER M4 ;
        RECT  0 47.328 0.084 47.352 ;
    END
  END o[288]
  PIN o[289]
    DIRECTION OUTPUT ;
    USE SIGNAL ;
    PORT
      LAYER M4 ;
        RECT  0 47.472 0.084 47.496 ;
    END
  END o[289]
  PIN o[28]
    DIRECTION OUTPUT ;
    USE SIGNAL ;
    PORT
      LAYER M4 ;
        RECT  0 5.568 0.084 5.592 ;
    END
  END o[28]
  PIN o[290]
    DIRECTION OUTPUT ;
    USE SIGNAL ;
    PORT
      LAYER M4 ;
        RECT  0 47.616 0.084 47.64 ;
    END
  END o[290]
  PIN o[291]
    DIRECTION OUTPUT ;
    USE SIGNAL ;
    PORT
      LAYER M4 ;
        RECT  0 47.808 0.084 47.832 ;
    END
  END o[291]
  PIN o[292]
    DIRECTION OUTPUT ;
    USE SIGNAL ;
    PORT
      LAYER M4 ;
        RECT  0 47.952 0.084 47.976 ;
    END
  END o[292]
  PIN o[293]
    DIRECTION OUTPUT ;
    USE SIGNAL ;
    PORT
      LAYER M4 ;
        RECT  0 48.096 0.084 48.12 ;
    END
  END o[293]
  PIN o[294]
    DIRECTION OUTPUT ;
    USE SIGNAL ;
    PORT
      LAYER M4 ;
        RECT  0 48.288 0.084 48.312 ;
    END
  END o[294]
  PIN o[295]
    DIRECTION OUTPUT ;
    USE SIGNAL ;
    PORT
      LAYER M4 ;
        RECT  0 48.432 0.084 48.456 ;
    END
  END o[295]
  PIN o[296]
    DIRECTION OUTPUT ;
    USE SIGNAL ;
    PORT
      LAYER M4 ;
        RECT  0 48.576 0.084 48.6 ;
    END
  END o[296]
  PIN o[297]
    DIRECTION OUTPUT ;
    USE SIGNAL ;
    PORT
      LAYER M4 ;
        RECT  0 48.768 0.084 48.792 ;
    END
  END o[297]
  PIN o[298]
    DIRECTION OUTPUT ;
    USE SIGNAL ;
    PORT
      LAYER M4 ;
        RECT  0 48.912 0.084 48.936 ;
    END
  END o[298]
  PIN o[299]
    DIRECTION OUTPUT ;
    USE SIGNAL ;
    PORT
      LAYER M4 ;
        RECT  0 49.056 0.084 49.08 ;
    END
  END o[299]
  PIN o[29]
    DIRECTION OUTPUT ;
    USE SIGNAL ;
    PORT
      LAYER M4 ;
        RECT  0 5.712 0.084 5.736 ;
    END
  END o[29]
  PIN o[2]
    DIRECTION OUTPUT ;
    USE SIGNAL ;
    PORT
      LAYER M4 ;
        RECT  0 1.392 0.084 1.416 ;
    END
  END o[2]
  PIN o[300]
    DIRECTION OUTPUT ;
    USE SIGNAL ;
    PORT
      LAYER M4 ;
        RECT  0 49.248 0.084 49.272 ;
    END
  END o[300]
  PIN o[301]
    DIRECTION OUTPUT ;
    USE SIGNAL ;
    PORT
      LAYER M4 ;
        RECT  0 49.392 0.084 49.416 ;
    END
  END o[301]
  PIN o[302]
    DIRECTION OUTPUT ;
    USE SIGNAL ;
    PORT
      LAYER M4 ;
        RECT  0 49.584 0.084 49.608 ;
    END
  END o[302]
  PIN o[303]
    DIRECTION OUTPUT ;
    USE SIGNAL ;
    PORT
      LAYER M4 ;
        RECT  0 49.728 0.084 49.752 ;
    END
  END o[303]
  PIN o[304]
    DIRECTION OUTPUT ;
    USE SIGNAL ;
    PORT
      LAYER M4 ;
        RECT  0 49.872 0.084 49.896 ;
    END
  END o[304]
  PIN o[305]
    DIRECTION OUTPUT ;
    USE SIGNAL ;
    PORT
      LAYER M4 ;
        RECT  0 50.064 0.084 50.088 ;
    END
  END o[305]
  PIN o[306]
    DIRECTION OUTPUT ;
    USE SIGNAL ;
    PORT
      LAYER M4 ;
        RECT  0 50.208 0.084 50.232 ;
    END
  END o[306]
  PIN o[307]
    DIRECTION OUTPUT ;
    USE SIGNAL ;
    PORT
      LAYER M4 ;
        RECT  0 50.352 0.084 50.376 ;
    END
  END o[307]
  PIN o[308]
    DIRECTION OUTPUT ;
    USE SIGNAL ;
    PORT
      LAYER M4 ;
        RECT  0 50.544 0.084 50.568 ;
    END
  END o[308]
  PIN o[309]
    DIRECTION OUTPUT ;
    USE SIGNAL ;
    PORT
      LAYER M4 ;
        RECT  0 50.688 0.084 50.712 ;
    END
  END o[309]
  PIN o[30]
    DIRECTION OUTPUT ;
    USE SIGNAL ;
    PORT
      LAYER M4 ;
        RECT  0 5.904 0.084 5.928 ;
    END
  END o[30]
  PIN o[310]
    DIRECTION OUTPUT ;
    USE SIGNAL ;
    PORT
      LAYER M4 ;
        RECT  0 50.832 0.084 50.856 ;
    END
  END o[310]
  PIN o[311]
    DIRECTION OUTPUT ;
    USE SIGNAL ;
    PORT
      LAYER M4 ;
        RECT  0 51.024 0.084 51.048 ;
    END
  END o[311]
  PIN o[312]
    DIRECTION OUTPUT ;
    USE SIGNAL ;
    PORT
      LAYER M4 ;
        RECT  0 51.168 0.084 51.192 ;
    END
  END o[312]
  PIN o[313]
    DIRECTION OUTPUT ;
    USE SIGNAL ;
    PORT
      LAYER M4 ;
        RECT  0 51.312 0.084 51.336 ;
    END
  END o[313]
  PIN o[314]
    DIRECTION OUTPUT ;
    USE SIGNAL ;
    PORT
      LAYER M4 ;
        RECT  0 51.504 0.084 51.528 ;
    END
  END o[314]
  PIN o[315]
    DIRECTION OUTPUT ;
    USE SIGNAL ;
    PORT
      LAYER M4 ;
        RECT  0 51.648 0.084 51.672 ;
    END
  END o[315]
  PIN o[316]
    DIRECTION OUTPUT ;
    USE SIGNAL ;
    PORT
      LAYER M4 ;
        RECT  0 51.792 0.084 51.816 ;
    END
  END o[316]
  PIN o[317]
    DIRECTION OUTPUT ;
    USE SIGNAL ;
    PORT
      LAYER M4 ;
        RECT  0 51.984 0.084 52.008 ;
    END
  END o[317]
  PIN o[318]
    DIRECTION OUTPUT ;
    USE SIGNAL ;
    PORT
      LAYER M4 ;
        RECT  0 52.128 0.084 52.152 ;
    END
  END o[318]
  PIN o[319]
    DIRECTION OUTPUT ;
    USE SIGNAL ;
    PORT
      LAYER M4 ;
        RECT  0 52.272 0.084 52.296 ;
    END
  END o[319]
  PIN o[31]
    DIRECTION OUTPUT ;
    USE SIGNAL ;
    PORT
      LAYER M4 ;
        RECT  0 6.048 0.084 6.072 ;
    END
  END o[31]
  PIN o[320]
    DIRECTION OUTPUT ;
    USE SIGNAL ;
    PORT
      LAYER M4 ;
        RECT  0 52.464 0.084 52.488 ;
    END
  END o[320]
  PIN o[321]
    DIRECTION OUTPUT ;
    USE SIGNAL ;
    PORT
      LAYER M4 ;
        RECT  0 52.608 0.084 52.632 ;
    END
  END o[321]
  PIN o[322]
    DIRECTION OUTPUT ;
    USE SIGNAL ;
    PORT
      LAYER M4 ;
        RECT  0 52.752 0.084 52.776 ;
    END
  END o[322]
  PIN o[323]
    DIRECTION OUTPUT ;
    USE SIGNAL ;
    PORT
      LAYER M4 ;
        RECT  0 52.944 0.084 52.968 ;
    END
  END o[323]
  PIN o[324]
    DIRECTION OUTPUT ;
    USE SIGNAL ;
    PORT
      LAYER M4 ;
        RECT  0 53.088 0.084 53.112 ;
    END
  END o[324]
  PIN o[325]
    DIRECTION OUTPUT ;
    USE SIGNAL ;
    PORT
      LAYER M4 ;
        RECT  0 53.232 0.084 53.256 ;
    END
  END o[325]
  PIN o[326]
    DIRECTION OUTPUT ;
    USE SIGNAL ;
    PORT
      LAYER M4 ;
        RECT  0 53.424 0.084 53.448 ;
    END
  END o[326]
  PIN o[327]
    DIRECTION OUTPUT ;
    USE SIGNAL ;
    PORT
      LAYER M4 ;
        RECT  0 53.568 0.084 53.592 ;
    END
  END o[327]
  PIN o[328]
    DIRECTION OUTPUT ;
    USE SIGNAL ;
    PORT
      LAYER M4 ;
        RECT  0 53.712 0.084 53.736 ;
    END
  END o[328]
  PIN o[329]
    DIRECTION OUTPUT ;
    USE SIGNAL ;
    PORT
      LAYER M4 ;
        RECT  0 53.904 0.084 53.928 ;
    END
  END o[329]
  PIN o[32]
    DIRECTION OUTPUT ;
    USE SIGNAL ;
    PORT
      LAYER M4 ;
        RECT  0 6.192 0.084 6.216 ;
    END
  END o[32]
  PIN o[330]
    DIRECTION OUTPUT ;
    USE SIGNAL ;
    PORT
      LAYER M4 ;
        RECT  0 54.048 0.084 54.072 ;
    END
  END o[330]
  PIN o[331]
    DIRECTION OUTPUT ;
    USE SIGNAL ;
    PORT
      LAYER M4 ;
        RECT  0 54.24 0.084 54.264 ;
    END
  END o[331]
  PIN o[332]
    DIRECTION OUTPUT ;
    USE SIGNAL ;
    PORT
      LAYER M4 ;
        RECT  0 54.384 0.084 54.408 ;
    END
  END o[332]
  PIN o[333]
    DIRECTION OUTPUT ;
    USE SIGNAL ;
    PORT
      LAYER M4 ;
        RECT  0 54.528 0.084 54.552 ;
    END
  END o[333]
  PIN o[334]
    DIRECTION OUTPUT ;
    USE SIGNAL ;
    PORT
      LAYER M4 ;
        RECT  0 54.72 0.084 54.744 ;
    END
  END o[334]
  PIN o[335]
    DIRECTION OUTPUT ;
    USE SIGNAL ;
    PORT
      LAYER M4 ;
        RECT  0 54.864 0.084 54.888 ;
    END
  END o[335]
  PIN o[336]
    DIRECTION OUTPUT ;
    USE SIGNAL ;
    PORT
      LAYER M4 ;
        RECT  0 55.008 0.084 55.032 ;
    END
  END o[336]
  PIN o[337]
    DIRECTION OUTPUT ;
    USE SIGNAL ;
    PORT
      LAYER M4 ;
        RECT  0 55.2 0.084 55.224 ;
    END
  END o[337]
  PIN o[338]
    DIRECTION OUTPUT ;
    USE SIGNAL ;
    PORT
      LAYER M4 ;
        RECT  0 55.344 0.084 55.368 ;
    END
  END o[338]
  PIN o[339]
    DIRECTION OUTPUT ;
    USE SIGNAL ;
    PORT
      LAYER M4 ;
        RECT  0 55.488 0.084 55.512 ;
    END
  END o[339]
  PIN o[33]
    DIRECTION OUTPUT ;
    USE SIGNAL ;
    PORT
      LAYER M4 ;
        RECT  0 6.384 0.084 6.408 ;
    END
  END o[33]
  PIN o[340]
    DIRECTION OUTPUT ;
    USE SIGNAL ;
    PORT
      LAYER M4 ;
        RECT  0 55.68 0.084 55.704 ;
    END
  END o[340]
  PIN o[341]
    DIRECTION OUTPUT ;
    USE SIGNAL ;
    PORT
      LAYER M4 ;
        RECT  0 55.824 0.084 55.848 ;
    END
  END o[341]
  PIN o[342]
    DIRECTION OUTPUT ;
    USE SIGNAL ;
    PORT
      LAYER M4 ;
        RECT  0 55.968 0.084 55.992 ;
    END
  END o[342]
  PIN o[343]
    DIRECTION OUTPUT ;
    USE SIGNAL ;
    PORT
      LAYER M4 ;
        RECT  0 56.16 0.084 56.184 ;
    END
  END o[343]
  PIN o[344]
    DIRECTION OUTPUT ;
    USE SIGNAL ;
    PORT
      LAYER M4 ;
        RECT  0 56.304 0.084 56.328 ;
    END
  END o[344]
  PIN o[345]
    DIRECTION OUTPUT ;
    USE SIGNAL ;
    PORT
      LAYER M4 ;
        RECT  0 56.448 0.084 56.472 ;
    END
  END o[345]
  PIN o[346]
    DIRECTION OUTPUT ;
    USE SIGNAL ;
    PORT
      LAYER M4 ;
        RECT  0 56.64 0.084 56.664 ;
    END
  END o[346]
  PIN o[347]
    DIRECTION OUTPUT ;
    USE SIGNAL ;
    PORT
      LAYER M4 ;
        RECT  0 56.784 0.084 56.808 ;
    END
  END o[347]
  PIN o[348]
    DIRECTION OUTPUT ;
    USE SIGNAL ;
    PORT
      LAYER M4 ;
        RECT  0 56.928 0.084 56.952 ;
    END
  END o[348]
  PIN o[349]
    DIRECTION OUTPUT ;
    USE SIGNAL ;
    PORT
      LAYER M4 ;
        RECT  0 57.12 0.084 57.144 ;
    END
  END o[349]
  PIN o[34]
    DIRECTION OUTPUT ;
    USE SIGNAL ;
    PORT
      LAYER M4 ;
        RECT  0 6.528 0.084 6.552 ;
    END
  END o[34]
  PIN o[350]
    DIRECTION OUTPUT ;
    USE SIGNAL ;
    PORT
      LAYER M4 ;
        RECT  0 57.264 0.084 57.288 ;
    END
  END o[350]
  PIN o[351]
    DIRECTION OUTPUT ;
    USE SIGNAL ;
    PORT
      LAYER M4 ;
        RECT  0 57.408 0.084 57.432 ;
    END
  END o[351]
  PIN o[352]
    DIRECTION OUTPUT ;
    USE SIGNAL ;
    PORT
      LAYER M4 ;
        RECT  0 57.6 0.084 57.624 ;
    END
  END o[352]
  PIN o[353]
    DIRECTION OUTPUT ;
    USE SIGNAL ;
    PORT
      LAYER M4 ;
        RECT  0 57.744 0.084 57.768 ;
    END
  END o[353]
  PIN o[354]
    DIRECTION OUTPUT ;
    USE SIGNAL ;
    PORT
      LAYER M4 ;
        RECT  0 57.888 0.084 57.912 ;
    END
  END o[354]
  PIN o[355]
    DIRECTION OUTPUT ;
    USE SIGNAL ;
    PORT
      LAYER M4 ;
        RECT  0 58.08 0.084 58.104 ;
    END
  END o[355]
  PIN o[356]
    DIRECTION OUTPUT ;
    USE SIGNAL ;
    PORT
      LAYER M4 ;
        RECT  0 58.224 0.084 58.248 ;
    END
  END o[356]
  PIN o[357]
    DIRECTION OUTPUT ;
    USE SIGNAL ;
    PORT
      LAYER M4 ;
        RECT  0 58.416 0.084 58.44 ;
    END
  END o[357]
  PIN o[358]
    DIRECTION OUTPUT ;
    USE SIGNAL ;
    PORT
      LAYER M4 ;
        RECT  0 58.56 0.084 58.584 ;
    END
  END o[358]
  PIN o[359]
    DIRECTION OUTPUT ;
    USE SIGNAL ;
    PORT
      LAYER M4 ;
        RECT  0 58.704 0.084 58.728 ;
    END
  END o[359]
  PIN o[35]
    DIRECTION OUTPUT ;
    USE SIGNAL ;
    PORT
      LAYER M4 ;
        RECT  0 6.672 0.084 6.696 ;
    END
  END o[35]
  PIN o[360]
    DIRECTION OUTPUT ;
    USE SIGNAL ;
    PORT
      LAYER M4 ;
        RECT  0 58.896 0.084 58.92 ;
    END
  END o[360]
  PIN o[361]
    DIRECTION OUTPUT ;
    USE SIGNAL ;
    PORT
      LAYER M4 ;
        RECT  0 59.04 0.084 59.064 ;
    END
  END o[361]
  PIN o[362]
    DIRECTION OUTPUT ;
    USE SIGNAL ;
    PORT
      LAYER M4 ;
        RECT  0 59.184 0.084 59.208 ;
    END
  END o[362]
  PIN o[363]
    DIRECTION OUTPUT ;
    USE SIGNAL ;
    PORT
      LAYER M4 ;
        RECT  0 59.376 0.084 59.4 ;
    END
  END o[363]
  PIN o[364]
    DIRECTION OUTPUT ;
    USE SIGNAL ;
    PORT
      LAYER M4 ;
        RECT  0 59.52 0.084 59.544 ;
    END
  END o[364]
  PIN o[365]
    DIRECTION OUTPUT ;
    USE SIGNAL ;
    PORT
      LAYER M4 ;
        RECT  0 59.664 0.084 59.688 ;
    END
  END o[365]
  PIN o[366]
    DIRECTION OUTPUT ;
    USE SIGNAL ;
    PORT
      LAYER M4 ;
        RECT  0 59.856 0.084 59.88 ;
    END
  END o[366]
  PIN o[367]
    DIRECTION OUTPUT ;
    USE SIGNAL ;
    PORT
      LAYER M4 ;
        RECT  0 60 0.084 60.024 ;
    END
  END o[367]
  PIN o[368]
    DIRECTION OUTPUT ;
    USE SIGNAL ;
    PORT
      LAYER M4 ;
        RECT  0 60.144 0.084 60.168 ;
    END
  END o[368]
  PIN o[369]
    DIRECTION OUTPUT ;
    USE SIGNAL ;
    PORT
      LAYER M4 ;
        RECT  0 60.336 0.084 60.36 ;
    END
  END o[369]
  PIN o[36]
    DIRECTION OUTPUT ;
    USE SIGNAL ;
    PORT
      LAYER M4 ;
        RECT  0 6.864 0.084 6.888 ;
    END
  END o[36]
  PIN o[370]
    DIRECTION OUTPUT ;
    USE SIGNAL ;
    PORT
      LAYER M4 ;
        RECT  0 60.48 0.084 60.504 ;
    END
  END o[370]
  PIN o[371]
    DIRECTION OUTPUT ;
    USE SIGNAL ;
    PORT
      LAYER M4 ;
        RECT  0 60.624 0.084 60.648 ;
    END
  END o[371]
  PIN o[372]
    DIRECTION OUTPUT ;
    USE SIGNAL ;
    PORT
      LAYER M4 ;
        RECT  0 60.816 0.084 60.84 ;
    END
  END o[372]
  PIN o[373]
    DIRECTION OUTPUT ;
    USE SIGNAL ;
    PORT
      LAYER M4 ;
        RECT  0 60.96 0.084 60.984 ;
    END
  END o[373]
  PIN o[374]
    DIRECTION OUTPUT ;
    USE SIGNAL ;
    PORT
      LAYER M4 ;
        RECT  0 61.104 0.084 61.128 ;
    END
  END o[374]
  PIN o[375]
    DIRECTION OUTPUT ;
    USE SIGNAL ;
    PORT
      LAYER M4 ;
        RECT  0 61.296 0.084 61.32 ;
    END
  END o[375]
  PIN o[376]
    DIRECTION OUTPUT ;
    USE SIGNAL ;
    PORT
      LAYER M4 ;
        RECT  0 61.44 0.084 61.464 ;
    END
  END o[376]
  PIN o[377]
    DIRECTION OUTPUT ;
    USE SIGNAL ;
    PORT
      LAYER M4 ;
        RECT  0 61.584 0.084 61.608 ;
    END
  END o[377]
  PIN o[378]
    DIRECTION OUTPUT ;
    USE SIGNAL ;
    PORT
      LAYER M4 ;
        RECT  0 61.776 0.084 61.8 ;
    END
  END o[378]
  PIN o[379]
    DIRECTION OUTPUT ;
    USE SIGNAL ;
    PORT
      LAYER M4 ;
        RECT  0 61.92 0.084 61.944 ;
    END
  END o[379]
  PIN o[37]
    DIRECTION OUTPUT ;
    USE SIGNAL ;
    PORT
      LAYER M4 ;
        RECT  0 7.008 0.084 7.032 ;
    END
  END o[37]
  PIN o[380]
    DIRECTION OUTPUT ;
    USE SIGNAL ;
    PORT
      LAYER M4 ;
        RECT  0 62.064 0.084 62.088 ;
    END
  END o[380]
  PIN o[381]
    DIRECTION OUTPUT ;
    USE SIGNAL ;
    PORT
      LAYER M4 ;
        RECT  0 62.256 0.084 62.28 ;
    END
  END o[381]
  PIN o[382]
    DIRECTION OUTPUT ;
    USE SIGNAL ;
    PORT
      LAYER M4 ;
        RECT  0 62.4 0.084 62.424 ;
    END
  END o[382]
  PIN o[383]
    DIRECTION OUTPUT ;
    USE SIGNAL ;
    PORT
      LAYER M4 ;
        RECT  0 62.544 0.084 62.568 ;
    END
  END o[383]
  PIN o[384]
    DIRECTION OUTPUT ;
    USE SIGNAL ;
    PORT
      LAYER M4 ;
        RECT  0 62.736 0.084 62.76 ;
    END
  END o[384]
  PIN o[385]
    DIRECTION OUTPUT ;
    USE SIGNAL ;
    PORT
      LAYER M4 ;
        RECT  0 62.88 0.084 62.904 ;
    END
  END o[385]
  PIN o[386]
    DIRECTION OUTPUT ;
    USE SIGNAL ;
    PORT
      LAYER M4 ;
        RECT  0 63.072 0.084 63.096 ;
    END
  END o[386]
  PIN o[387]
    DIRECTION OUTPUT ;
    USE SIGNAL ;
    PORT
      LAYER M4 ;
        RECT  0 63.216 0.084 63.24 ;
    END
  END o[387]
  PIN o[388]
    DIRECTION OUTPUT ;
    USE SIGNAL ;
    PORT
      LAYER M4 ;
        RECT  0 63.36 0.084 63.384 ;
    END
  END o[388]
  PIN o[389]
    DIRECTION OUTPUT ;
    USE SIGNAL ;
    PORT
      LAYER M4 ;
        RECT  0 63.552 0.084 63.576 ;
    END
  END o[389]
  PIN o[38]
    DIRECTION OUTPUT ;
    USE SIGNAL ;
    PORT
      LAYER M4 ;
        RECT  0 7.152 0.084 7.176 ;
    END
  END o[38]
  PIN o[390]
    DIRECTION OUTPUT ;
    USE SIGNAL ;
    PORT
      LAYER M4 ;
        RECT  0 63.696 0.084 63.72 ;
    END
  END o[390]
  PIN o[391]
    DIRECTION OUTPUT ;
    USE SIGNAL ;
    PORT
      LAYER M4 ;
        RECT  0 63.84 0.084 63.864 ;
    END
  END o[391]
  PIN o[392]
    DIRECTION OUTPUT ;
    USE SIGNAL ;
    PORT
      LAYER M4 ;
        RECT  0 64.032 0.084 64.056 ;
    END
  END o[392]
  PIN o[393]
    DIRECTION OUTPUT ;
    USE SIGNAL ;
    PORT
      LAYER M4 ;
        RECT  0 64.176 0.084 64.2 ;
    END
  END o[393]
  PIN o[394]
    DIRECTION OUTPUT ;
    USE SIGNAL ;
    PORT
      LAYER M4 ;
        RECT  0 64.32 0.084 64.344 ;
    END
  END o[394]
  PIN o[395]
    DIRECTION OUTPUT ;
    USE SIGNAL ;
    PORT
      LAYER M4 ;
        RECT  0 64.512 0.084 64.536 ;
    END
  END o[395]
  PIN o[396]
    DIRECTION OUTPUT ;
    USE SIGNAL ;
    PORT
      LAYER M4 ;
        RECT  0 64.656 0.084 64.68 ;
    END
  END o[396]
  PIN o[397]
    DIRECTION OUTPUT ;
    USE SIGNAL ;
    PORT
      LAYER M4 ;
        RECT  0 64.8 0.084 64.824 ;
    END
  END o[397]
  PIN o[398]
    DIRECTION OUTPUT ;
    USE SIGNAL ;
    PORT
      LAYER M4 ;
        RECT  0 64.992 0.084 65.016 ;
    END
  END o[398]
  PIN o[399]
    DIRECTION OUTPUT ;
    USE SIGNAL ;
    PORT
      LAYER M4 ;
        RECT  0 65.136 0.084 65.16 ;
    END
  END o[399]
  PIN o[39]
    DIRECTION OUTPUT ;
    USE SIGNAL ;
    PORT
      LAYER M4 ;
        RECT  0 7.344 0.084 7.368 ;
    END
  END o[39]
  PIN o[3]
    DIRECTION OUTPUT ;
    USE SIGNAL ;
    PORT
      LAYER M4 ;
        RECT  0 1.536 0.084 1.56 ;
    END
  END o[3]
  PIN o[400]
    DIRECTION OUTPUT ;
    USE SIGNAL ;
    PORT
      LAYER M4 ;
        RECT  0 65.28 0.084 65.304 ;
    END
  END o[400]
  PIN o[401]
    DIRECTION OUTPUT ;
    USE SIGNAL ;
    PORT
      LAYER M4 ;
        RECT  0 65.472 0.084 65.496 ;
    END
  END o[401]
  PIN o[402]
    DIRECTION OUTPUT ;
    USE SIGNAL ;
    PORT
      LAYER M4 ;
        RECT  0 65.616 0.084 65.64 ;
    END
  END o[402]
  PIN o[403]
    DIRECTION OUTPUT ;
    USE SIGNAL ;
    PORT
      LAYER M4 ;
        RECT  0 65.76 0.084 65.784 ;
    END
  END o[403]
  PIN o[404]
    DIRECTION OUTPUT ;
    USE SIGNAL ;
    PORT
      LAYER M4 ;
        RECT  0 65.952 0.084 65.976 ;
    END
  END o[404]
  PIN o[405]
    DIRECTION OUTPUT ;
    USE SIGNAL ;
    PORT
      LAYER M4 ;
        RECT  0 66.096 0.084 66.12 ;
    END
  END o[405]
  PIN o[406]
    DIRECTION OUTPUT ;
    USE SIGNAL ;
    PORT
      LAYER M4 ;
        RECT  0 66.24 0.084 66.264 ;
    END
  END o[406]
  PIN o[407]
    DIRECTION OUTPUT ;
    USE SIGNAL ;
    PORT
      LAYER M4 ;
        RECT  0 66.432 0.084 66.456 ;
    END
  END o[407]
  PIN o[408]
    DIRECTION OUTPUT ;
    USE SIGNAL ;
    PORT
      LAYER M4 ;
        RECT  0 66.576 0.084 66.6 ;
    END
  END o[408]
  PIN o[409]
    DIRECTION OUTPUT ;
    USE SIGNAL ;
    PORT
      LAYER M4 ;
        RECT  0 66.72 0.084 66.744 ;
    END
  END o[409]
  PIN o[40]
    DIRECTION OUTPUT ;
    USE SIGNAL ;
    PORT
      LAYER M4 ;
        RECT  0 7.488 0.084 7.512 ;
    END
  END o[40]
  PIN o[410]
    DIRECTION OUTPUT ;
    USE SIGNAL ;
    PORT
      LAYER M4 ;
        RECT  0 66.912 0.084 66.936 ;
    END
  END o[410]
  PIN o[411]
    DIRECTION OUTPUT ;
    USE SIGNAL ;
    PORT
      LAYER M4 ;
        RECT  0 67.056 0.084 67.08 ;
    END
  END o[411]
  PIN o[412]
    DIRECTION OUTPUT ;
    USE SIGNAL ;
    PORT
      LAYER M4 ;
        RECT  0 67.2 0.084 67.224 ;
    END
  END o[412]
  PIN o[413]
    DIRECTION OUTPUT ;
    USE SIGNAL ;
    PORT
      LAYER M4 ;
        RECT  0 67.392 0.084 67.416 ;
    END
  END o[413]
  PIN o[414]
    DIRECTION OUTPUT ;
    USE SIGNAL ;
    PORT
      LAYER M4 ;
        RECT  0 67.536 0.084 67.56 ;
    END
  END o[414]
  PIN o[415]
    DIRECTION OUTPUT ;
    USE SIGNAL ;
    PORT
      LAYER M4 ;
        RECT  0 67.728 0.084 67.752 ;
    END
  END o[415]
  PIN o[416]
    DIRECTION OUTPUT ;
    USE SIGNAL ;
    PORT
      LAYER M4 ;
        RECT  0 67.872 0.084 67.896 ;
    END
  END o[416]
  PIN o[417]
    DIRECTION OUTPUT ;
    USE SIGNAL ;
    PORT
      LAYER M4 ;
        RECT  0 68.016 0.084 68.04 ;
    END
  END o[417]
  PIN o[418]
    DIRECTION OUTPUT ;
    USE SIGNAL ;
    PORT
      LAYER M4 ;
        RECT  0 68.208 0.084 68.232 ;
    END
  END o[418]
  PIN o[419]
    DIRECTION OUTPUT ;
    USE SIGNAL ;
    PORT
      LAYER M4 ;
        RECT  0 68.352 0.084 68.376 ;
    END
  END o[419]
  PIN o[41]
    DIRECTION OUTPUT ;
    USE SIGNAL ;
    PORT
      LAYER M4 ;
        RECT  0 7.632 0.084 7.656 ;
    END
  END o[41]
  PIN o[420]
    DIRECTION OUTPUT ;
    USE SIGNAL ;
    PORT
      LAYER M4 ;
        RECT  0 68.496 0.084 68.52 ;
    END
  END o[420]
  PIN o[421]
    DIRECTION OUTPUT ;
    USE SIGNAL ;
    PORT
      LAYER M4 ;
        RECT  0 68.688 0.084 68.712 ;
    END
  END o[421]
  PIN o[422]
    DIRECTION OUTPUT ;
    USE SIGNAL ;
    PORT
      LAYER M4 ;
        RECT  0 68.832 0.084 68.856 ;
    END
  END o[422]
  PIN o[423]
    DIRECTION OUTPUT ;
    USE SIGNAL ;
    PORT
      LAYER M4 ;
        RECT  0 68.976 0.084 69 ;
    END
  END o[423]
  PIN o[424]
    DIRECTION OUTPUT ;
    USE SIGNAL ;
    PORT
      LAYER M4 ;
        RECT  0 69.168 0.084 69.192 ;
    END
  END o[424]
  PIN o[425]
    DIRECTION OUTPUT ;
    USE SIGNAL ;
    PORT
      LAYER M4 ;
        RECT  0 69.312 0.084 69.336 ;
    END
  END o[425]
  PIN o[426]
    DIRECTION OUTPUT ;
    USE SIGNAL ;
    PORT
      LAYER M4 ;
        RECT  0 69.456 0.084 69.48 ;
    END
  END o[426]
  PIN o[427]
    DIRECTION OUTPUT ;
    USE SIGNAL ;
    PORT
      LAYER M4 ;
        RECT  0 69.648 0.084 69.672 ;
    END
  END o[427]
  PIN o[428]
    DIRECTION OUTPUT ;
    USE SIGNAL ;
    PORT
      LAYER M4 ;
        RECT  0 69.792 0.084 69.816 ;
    END
  END o[428]
  PIN o[429]
    DIRECTION OUTPUT ;
    USE SIGNAL ;
    PORT
      LAYER M4 ;
        RECT  0 69.936 0.084 69.96 ;
    END
  END o[429]
  PIN o[42]
    DIRECTION OUTPUT ;
    USE SIGNAL ;
    PORT
      LAYER M4 ;
        RECT  0 7.824 0.084 7.848 ;
    END
  END o[42]
  PIN o[430]
    DIRECTION OUTPUT ;
    USE SIGNAL ;
    PORT
      LAYER M4 ;
        RECT  0 70.128 0.084 70.152 ;
    END
  END o[430]
  PIN o[431]
    DIRECTION OUTPUT ;
    USE SIGNAL ;
    PORT
      LAYER M4 ;
        RECT  0 70.272 0.084 70.296 ;
    END
  END o[431]
  PIN o[432]
    DIRECTION OUTPUT ;
    USE SIGNAL ;
    PORT
      LAYER M4 ;
        RECT  0 70.416 0.084 70.44 ;
    END
  END o[432]
  PIN o[433]
    DIRECTION OUTPUT ;
    USE SIGNAL ;
    PORT
      LAYER M4 ;
        RECT  0 70.608 0.084 70.632 ;
    END
  END o[433]
  PIN o[434]
    DIRECTION OUTPUT ;
    USE SIGNAL ;
    PORT
      LAYER M4 ;
        RECT  0 70.752 0.084 70.776 ;
    END
  END o[434]
  PIN o[435]
    DIRECTION OUTPUT ;
    USE SIGNAL ;
    PORT
      LAYER M4 ;
        RECT  0 70.896 0.084 70.92 ;
    END
  END o[435]
  PIN o[436]
    DIRECTION OUTPUT ;
    USE SIGNAL ;
    PORT
      LAYER M4 ;
        RECT  0 71.088 0.084 71.112 ;
    END
  END o[436]
  PIN o[437]
    DIRECTION OUTPUT ;
    USE SIGNAL ;
    PORT
      LAYER M4 ;
        RECT  0 71.232 0.084 71.256 ;
    END
  END o[437]
  PIN o[438]
    DIRECTION OUTPUT ;
    USE SIGNAL ;
    PORT
      LAYER M4 ;
        RECT  0 71.376 0.084 71.4 ;
    END
  END o[438]
  PIN o[439]
    DIRECTION OUTPUT ;
    USE SIGNAL ;
    PORT
      LAYER M4 ;
        RECT  0 71.568 0.084 71.592 ;
    END
  END o[439]
  PIN o[43]
    DIRECTION OUTPUT ;
    USE SIGNAL ;
    PORT
      LAYER M4 ;
        RECT  0 7.968 0.084 7.992 ;
    END
  END o[43]
  PIN o[440]
    DIRECTION OUTPUT ;
    USE SIGNAL ;
    PORT
      LAYER M4 ;
        RECT  0 71.712 0.084 71.736 ;
    END
  END o[440]
  PIN o[441]
    DIRECTION OUTPUT ;
    USE SIGNAL ;
    PORT
      LAYER M4 ;
        RECT  0 71.856 0.084 71.88 ;
    END
  END o[441]
  PIN o[442]
    DIRECTION OUTPUT ;
    USE SIGNAL ;
    PORT
      LAYER M4 ;
        RECT  0 72.048 0.084 72.072 ;
    END
  END o[442]
  PIN o[443]
    DIRECTION OUTPUT ;
    USE SIGNAL ;
    PORT
      LAYER M4 ;
        RECT  0 72.192 0.084 72.216 ;
    END
  END o[443]
  PIN o[444]
    DIRECTION OUTPUT ;
    USE SIGNAL ;
    PORT
      LAYER M4 ;
        RECT  0 72.384 0.084 72.408 ;
    END
  END o[444]
  PIN o[445]
    DIRECTION OUTPUT ;
    USE SIGNAL ;
    PORT
      LAYER M4 ;
        RECT  0 72.528 0.084 72.552 ;
    END
  END o[445]
  PIN o[446]
    DIRECTION OUTPUT ;
    USE SIGNAL ;
    PORT
      LAYER M4 ;
        RECT  0 72.672 0.084 72.696 ;
    END
  END o[446]
  PIN o[447]
    DIRECTION OUTPUT ;
    USE SIGNAL ;
    PORT
      LAYER M4 ;
        RECT  0 72.864 0.084 72.888 ;
    END
  END o[447]
  PIN o[448]
    DIRECTION OUTPUT ;
    USE SIGNAL ;
    PORT
      LAYER M4 ;
        RECT  0 73.008 0.084 73.032 ;
    END
  END o[448]
  PIN o[449]
    DIRECTION OUTPUT ;
    USE SIGNAL ;
    PORT
      LAYER M4 ;
        RECT  0 73.152 0.084 73.176 ;
    END
  END o[449]
  PIN o[44]
    DIRECTION OUTPUT ;
    USE SIGNAL ;
    PORT
      LAYER M4 ;
        RECT  0 8.112 0.084 8.136 ;
    END
  END o[44]
  PIN o[450]
    DIRECTION OUTPUT ;
    USE SIGNAL ;
    PORT
      LAYER M4 ;
        RECT  0 73.344 0.084 73.368 ;
    END
  END o[450]
  PIN o[451]
    DIRECTION OUTPUT ;
    USE SIGNAL ;
    PORT
      LAYER M4 ;
        RECT  0 73.488 0.084 73.512 ;
    END
  END o[451]
  PIN o[452]
    DIRECTION OUTPUT ;
    USE SIGNAL ;
    PORT
      LAYER M4 ;
        RECT  0 73.632 0.084 73.656 ;
    END
  END o[452]
  PIN o[453]
    DIRECTION OUTPUT ;
    USE SIGNAL ;
    PORT
      LAYER M4 ;
        RECT  0 73.824 0.084 73.848 ;
    END
  END o[453]
  PIN o[454]
    DIRECTION OUTPUT ;
    USE SIGNAL ;
    PORT
      LAYER M4 ;
        RECT  0 73.968 0.084 73.992 ;
    END
  END o[454]
  PIN o[455]
    DIRECTION OUTPUT ;
    USE SIGNAL ;
    PORT
      LAYER M4 ;
        RECT  0 74.112 0.084 74.136 ;
    END
  END o[455]
  PIN o[456]
    DIRECTION OUTPUT ;
    USE SIGNAL ;
    PORT
      LAYER M4 ;
        RECT  0 74.304 0.084 74.328 ;
    END
  END o[456]
  PIN o[457]
    DIRECTION OUTPUT ;
    USE SIGNAL ;
    PORT
      LAYER M4 ;
        RECT  0 74.448 0.084 74.472 ;
    END
  END o[457]
  PIN o[458]
    DIRECTION OUTPUT ;
    USE SIGNAL ;
    PORT
      LAYER M4 ;
        RECT  0 74.592 0.084 74.616 ;
    END
  END o[458]
  PIN o[459]
    DIRECTION OUTPUT ;
    USE SIGNAL ;
    PORT
      LAYER M4 ;
        RECT  0 74.784 0.084 74.808 ;
    END
  END o[459]
  PIN o[45]
    DIRECTION OUTPUT ;
    USE SIGNAL ;
    PORT
      LAYER M4 ;
        RECT  0 8.304 0.084 8.328 ;
    END
  END o[45]
  PIN o[460]
    DIRECTION OUTPUT ;
    USE SIGNAL ;
    PORT
      LAYER M4 ;
        RECT  0 74.928 0.084 74.952 ;
    END
  END o[460]
  PIN o[461]
    DIRECTION OUTPUT ;
    USE SIGNAL ;
    PORT
      LAYER M4 ;
        RECT  0 75.072 0.084 75.096 ;
    END
  END o[461]
  PIN o[462]
    DIRECTION OUTPUT ;
    USE SIGNAL ;
    PORT
      LAYER M4 ;
        RECT  0 75.264 0.084 75.288 ;
    END
  END o[462]
  PIN o[463]
    DIRECTION OUTPUT ;
    USE SIGNAL ;
    PORT
      LAYER M4 ;
        RECT  0 75.408 0.084 75.432 ;
    END
  END o[463]
  PIN o[464]
    DIRECTION OUTPUT ;
    USE SIGNAL ;
    PORT
      LAYER M4 ;
        RECT  0 75.552 0.084 75.576 ;
    END
  END o[464]
  PIN o[465]
    DIRECTION OUTPUT ;
    USE SIGNAL ;
    PORT
      LAYER M4 ;
        RECT  0 75.744 0.084 75.768 ;
    END
  END o[465]
  PIN o[466]
    DIRECTION OUTPUT ;
    USE SIGNAL ;
    PORT
      LAYER M4 ;
        RECT  0 75.888 0.084 75.912 ;
    END
  END o[466]
  PIN o[467]
    DIRECTION OUTPUT ;
    USE SIGNAL ;
    PORT
      LAYER M4 ;
        RECT  0 76.032 0.084 76.056 ;
    END
  END o[467]
  PIN o[468]
    DIRECTION OUTPUT ;
    USE SIGNAL ;
    PORT
      LAYER M4 ;
        RECT  0 76.224 0.084 76.248 ;
    END
  END o[468]
  PIN o[469]
    DIRECTION OUTPUT ;
    USE SIGNAL ;
    PORT
      LAYER M4 ;
        RECT  0 76.368 0.084 76.392 ;
    END
  END o[469]
  PIN o[46]
    DIRECTION OUTPUT ;
    USE SIGNAL ;
    PORT
      LAYER M4 ;
        RECT  0 8.448 0.084 8.472 ;
    END
  END o[46]
  PIN o[470]
    DIRECTION OUTPUT ;
    USE SIGNAL ;
    PORT
      LAYER M4 ;
        RECT  0 76.56 0.084 76.584 ;
    END
  END o[470]
  PIN o[471]
    DIRECTION OUTPUT ;
    USE SIGNAL ;
    PORT
      LAYER M4 ;
        RECT  0 76.704 0.084 76.728 ;
    END
  END o[471]
  PIN o[472]
    DIRECTION OUTPUT ;
    USE SIGNAL ;
    PORT
      LAYER M4 ;
        RECT  0 76.848 0.084 76.872 ;
    END
  END o[472]
  PIN o[473]
    DIRECTION OUTPUT ;
    USE SIGNAL ;
    PORT
      LAYER M4 ;
        RECT  0 77.04 0.084 77.064 ;
    END
  END o[473]
  PIN o[474]
    DIRECTION OUTPUT ;
    USE SIGNAL ;
    PORT
      LAYER M4 ;
        RECT  0 77.184 0.084 77.208 ;
    END
  END o[474]
  PIN o[475]
    DIRECTION OUTPUT ;
    USE SIGNAL ;
    PORT
      LAYER M4 ;
        RECT  0 77.328 0.084 77.352 ;
    END
  END o[475]
  PIN o[476]
    DIRECTION OUTPUT ;
    USE SIGNAL ;
    PORT
      LAYER M4 ;
        RECT  0 77.52 0.084 77.544 ;
    END
  END o[476]
  PIN o[477]
    DIRECTION OUTPUT ;
    USE SIGNAL ;
    PORT
      LAYER M4 ;
        RECT  0 77.664 0.084 77.688 ;
    END
  END o[477]
  PIN o[478]
    DIRECTION OUTPUT ;
    USE SIGNAL ;
    PORT
      LAYER M4 ;
        RECT  0 77.808 0.084 77.832 ;
    END
  END o[478]
  PIN o[479]
    DIRECTION OUTPUT ;
    USE SIGNAL ;
    PORT
      LAYER M4 ;
        RECT  0 78 0.084 78.024 ;
    END
  END o[479]
  PIN o[47]
    DIRECTION OUTPUT ;
    USE SIGNAL ;
    PORT
      LAYER M4 ;
        RECT  0 8.592 0.084 8.616 ;
    END
  END o[47]
  PIN o[480]
    DIRECTION OUTPUT ;
    USE SIGNAL ;
    PORT
      LAYER M4 ;
        RECT  0 78.144 0.084 78.168 ;
    END
  END o[480]
  PIN o[481]
    DIRECTION OUTPUT ;
    USE SIGNAL ;
    PORT
      LAYER M4 ;
        RECT  0 78.288 0.084 78.312 ;
    END
  END o[481]
  PIN o[482]
    DIRECTION OUTPUT ;
    USE SIGNAL ;
    PORT
      LAYER M4 ;
        RECT  0 78.48 0.084 78.504 ;
    END
  END o[482]
  PIN o[483]
    DIRECTION OUTPUT ;
    USE SIGNAL ;
    PORT
      LAYER M4 ;
        RECT  0 78.624 0.084 78.648 ;
    END
  END o[483]
  PIN o[484]
    DIRECTION OUTPUT ;
    USE SIGNAL ;
    PORT
      LAYER M4 ;
        RECT  0 78.768 0.084 78.792 ;
    END
  END o[484]
  PIN o[485]
    DIRECTION OUTPUT ;
    USE SIGNAL ;
    PORT
      LAYER M4 ;
        RECT  0 78.96 0.084 78.984 ;
    END
  END o[485]
  PIN o[486]
    DIRECTION OUTPUT ;
    USE SIGNAL ;
    PORT
      LAYER M4 ;
        RECT  0 79.104 0.084 79.128 ;
    END
  END o[486]
  PIN o[487]
    DIRECTION OUTPUT ;
    USE SIGNAL ;
    PORT
      LAYER M4 ;
        RECT  0 79.248 0.084 79.272 ;
    END
  END o[487]
  PIN o[488]
    DIRECTION OUTPUT ;
    USE SIGNAL ;
    PORT
      LAYER M4 ;
        RECT  0 79.44 0.084 79.464 ;
    END
  END o[488]
  PIN o[489]
    DIRECTION OUTPUT ;
    USE SIGNAL ;
    PORT
      LAYER M4 ;
        RECT  0 79.584 0.084 79.608 ;
    END
  END o[489]
  PIN o[48]
    DIRECTION OUTPUT ;
    USE SIGNAL ;
    PORT
      LAYER M4 ;
        RECT  0 8.784 0.084 8.808 ;
    END
  END o[48]
  PIN o[490]
    DIRECTION OUTPUT ;
    USE SIGNAL ;
    PORT
      LAYER M4 ;
        RECT  0 79.728 0.084 79.752 ;
    END
  END o[490]
  PIN o[491]
    DIRECTION OUTPUT ;
    USE SIGNAL ;
    PORT
      LAYER M4 ;
        RECT  0 79.92 0.084 79.944 ;
    END
  END o[491]
  PIN o[492]
    DIRECTION OUTPUT ;
    USE SIGNAL ;
    PORT
      LAYER M4 ;
        RECT  0 80.064 0.084 80.088 ;
    END
  END o[492]
  PIN o[493]
    DIRECTION OUTPUT ;
    USE SIGNAL ;
    PORT
      LAYER M4 ;
        RECT  0 80.208 0.084 80.232 ;
    END
  END o[493]
  PIN o[494]
    DIRECTION OUTPUT ;
    USE SIGNAL ;
    PORT
      LAYER M4 ;
        RECT  0 80.4 0.084 80.424 ;
    END
  END o[494]
  PIN o[495]
    DIRECTION OUTPUT ;
    USE SIGNAL ;
    PORT
      LAYER M4 ;
        RECT  0 80.544 0.084 80.568 ;
    END
  END o[495]
  PIN o[496]
    DIRECTION OUTPUT ;
    USE SIGNAL ;
    PORT
      LAYER M4 ;
        RECT  0 80.688 0.084 80.712 ;
    END
  END o[496]
  PIN o[497]
    DIRECTION OUTPUT ;
    USE SIGNAL ;
    PORT
      LAYER M4 ;
        RECT  0 80.88 0.084 80.904 ;
    END
  END o[497]
  PIN o[498]
    DIRECTION OUTPUT ;
    USE SIGNAL ;
    PORT
      LAYER M4 ;
        RECT  0 81.024 0.084 81.048 ;
    END
  END o[498]
  PIN o[499]
    DIRECTION OUTPUT ;
    USE SIGNAL ;
    PORT
      LAYER M4 ;
        RECT  0 81.216 0.084 81.24 ;
    END
  END o[499]
  PIN o[49]
    DIRECTION OUTPUT ;
    USE SIGNAL ;
    PORT
      LAYER M4 ;
        RECT  0 8.928 0.084 8.952 ;
    END
  END o[49]
  PIN o[4]
    DIRECTION OUTPUT ;
    USE SIGNAL ;
    PORT
      LAYER M4 ;
        RECT  0 1.728 0.084 1.752 ;
    END
  END o[4]
  PIN o[500]
    DIRECTION OUTPUT ;
    USE SIGNAL ;
    PORT
      LAYER M4 ;
        RECT  0 81.36 0.084 81.384 ;
    END
  END o[500]
  PIN o[501]
    DIRECTION OUTPUT ;
    USE SIGNAL ;
    PORT
      LAYER M4 ;
        RECT  0 81.504 0.084 81.528 ;
    END
  END o[501]
  PIN o[502]
    DIRECTION OUTPUT ;
    USE SIGNAL ;
    PORT
      LAYER M4 ;
        RECT  0 81.696 0.084 81.72 ;
    END
  END o[502]
  PIN o[503]
    DIRECTION OUTPUT ;
    USE SIGNAL ;
    PORT
      LAYER M4 ;
        RECT  0 81.84 0.084 81.864 ;
    END
  END o[503]
  PIN o[504]
    DIRECTION OUTPUT ;
    USE SIGNAL ;
    PORT
      LAYER M4 ;
        RECT  0 81.984 0.084 82.008 ;
    END
  END o[504]
  PIN o[505]
    DIRECTION OUTPUT ;
    USE SIGNAL ;
    PORT
      LAYER M4 ;
        RECT  0 82.176 0.084 82.2 ;
    END
  END o[505]
  PIN o[506]
    DIRECTION OUTPUT ;
    USE SIGNAL ;
    PORT
      LAYER M4 ;
        RECT  0 82.32 0.084 82.344 ;
    END
  END o[506]
  PIN o[507]
    DIRECTION OUTPUT ;
    USE SIGNAL ;
    PORT
      LAYER M4 ;
        RECT  0 82.464 0.084 82.488 ;
    END
  END o[507]
  PIN o[508]
    DIRECTION OUTPUT ;
    USE SIGNAL ;
    PORT
      LAYER M4 ;
        RECT  0 82.656 0.084 82.68 ;
    END
  END o[508]
  PIN o[509]
    DIRECTION OUTPUT ;
    USE SIGNAL ;
    PORT
      LAYER M4 ;
        RECT  0 82.8 0.084 82.824 ;
    END
  END o[509]
  PIN o[50]
    DIRECTION OUTPUT ;
    USE SIGNAL ;
    PORT
      LAYER M4 ;
        RECT  0 9.12 0.084 9.144 ;
    END
  END o[50]
  PIN o[510]
    DIRECTION OUTPUT ;
    USE SIGNAL ;
    PORT
      LAYER M4 ;
        RECT  0 82.944 0.084 82.968 ;
    END
  END o[510]
  PIN o[511]
    DIRECTION OUTPUT ;
    USE SIGNAL ;
    PORT
      LAYER M4 ;
        RECT  0 83.136 0.084 83.16 ;
    END
  END o[511]
  PIN o[512]
    DIRECTION OUTPUT ;
    USE SIGNAL ;
    PORT
      LAYER M4 ;
        RECT  0 83.28 0.084 83.304 ;
    END
  END o[512]
  PIN o[513]
    DIRECTION OUTPUT ;
    USE SIGNAL ;
    PORT
      LAYER M4 ;
        RECT  0 83.424 0.084 83.448 ;
    END
  END o[513]
  PIN o[514]
    DIRECTION OUTPUT ;
    USE SIGNAL ;
    PORT
      LAYER M4 ;
        RECT  0 83.616 0.084 83.64 ;
    END
  END o[514]
  PIN o[515]
    DIRECTION OUTPUT ;
    USE SIGNAL ;
    PORT
      LAYER M4 ;
        RECT  0 83.76 0.084 83.784 ;
    END
  END o[515]
  PIN o[516]
    DIRECTION OUTPUT ;
    USE SIGNAL ;
    PORT
      LAYER M4 ;
        RECT  0 83.904 0.084 83.928 ;
    END
  END o[516]
  PIN o[517]
    DIRECTION OUTPUT ;
    USE SIGNAL ;
    PORT
      LAYER M4 ;
        RECT  0 84.096 0.084 84.12 ;
    END
  END o[517]
  PIN o[518]
    DIRECTION OUTPUT ;
    USE SIGNAL ;
    PORT
      LAYER M4 ;
        RECT  0 84.24 0.084 84.264 ;
    END
  END o[518]
  PIN o[519]
    DIRECTION OUTPUT ;
    USE SIGNAL ;
    PORT
      LAYER M4 ;
        RECT  0 84.384 0.084 84.408 ;
    END
  END o[519]
  PIN o[51]
    DIRECTION OUTPUT ;
    USE SIGNAL ;
    PORT
      LAYER M4 ;
        RECT  0 9.264 0.084 9.288 ;
    END
  END o[51]
  PIN o[520]
    DIRECTION OUTPUT ;
    USE SIGNAL ;
    PORT
      LAYER M4 ;
        RECT  0 84.576 0.084 84.6 ;
    END
  END o[520]
  PIN o[521]
    DIRECTION OUTPUT ;
    USE SIGNAL ;
    PORT
      LAYER M4 ;
        RECT  0 84.72 0.084 84.744 ;
    END
  END o[521]
  PIN o[522]
    DIRECTION OUTPUT ;
    USE SIGNAL ;
    PORT
      LAYER M4 ;
        RECT  0 84.864 0.084 84.888 ;
    END
  END o[522]
  PIN o[523]
    DIRECTION OUTPUT ;
    USE SIGNAL ;
    PORT
      LAYER M4 ;
        RECT  0 85.056 0.084 85.08 ;
    END
  END o[523]
  PIN o[524]
    DIRECTION OUTPUT ;
    USE SIGNAL ;
    PORT
      LAYER M4 ;
        RECT  0 85.2 0.084 85.224 ;
    END
  END o[524]
  PIN o[525]
    DIRECTION OUTPUT ;
    USE SIGNAL ;
    PORT
      LAYER M4 ;
        RECT  0 85.344 0.084 85.368 ;
    END
  END o[525]
  PIN o[526]
    DIRECTION OUTPUT ;
    USE SIGNAL ;
    PORT
      LAYER M4 ;
        RECT  0 85.536 0.084 85.56 ;
    END
  END o[526]
  PIN o[527]
    DIRECTION OUTPUT ;
    USE SIGNAL ;
    PORT
      LAYER M4 ;
        RECT  0 85.68 0.084 85.704 ;
    END
  END o[527]
  PIN o[528]
    DIRECTION OUTPUT ;
    USE SIGNAL ;
    PORT
      LAYER M4 ;
        RECT  0 85.872 0.084 85.896 ;
    END
  END o[528]
  PIN o[529]
    DIRECTION OUTPUT ;
    USE SIGNAL ;
    PORT
      LAYER M4 ;
        RECT  0 86.016 0.084 86.04 ;
    END
  END o[529]
  PIN o[52]
    DIRECTION OUTPUT ;
    USE SIGNAL ;
    PORT
      LAYER M4 ;
        RECT  0 9.408 0.084 9.432 ;
    END
  END o[52]
  PIN o[530]
    DIRECTION OUTPUT ;
    USE SIGNAL ;
    PORT
      LAYER M4 ;
        RECT  0 86.16 0.084 86.184 ;
    END
  END o[530]
  PIN o[531]
    DIRECTION OUTPUT ;
    USE SIGNAL ;
    PORT
      LAYER M4 ;
        RECT  0 86.352 0.084 86.376 ;
    END
  END o[531]
  PIN o[532]
    DIRECTION OUTPUT ;
    USE SIGNAL ;
    PORT
      LAYER M4 ;
        RECT  0 86.496 0.084 86.52 ;
    END
  END o[532]
  PIN o[533]
    DIRECTION OUTPUT ;
    USE SIGNAL ;
    PORT
      LAYER M4 ;
        RECT  0 86.64 0.084 86.664 ;
    END
  END o[533]
  PIN o[534]
    DIRECTION OUTPUT ;
    USE SIGNAL ;
    PORT
      LAYER M4 ;
        RECT  0 86.832 0.084 86.856 ;
    END
  END o[534]
  PIN o[535]
    DIRECTION OUTPUT ;
    USE SIGNAL ;
    PORT
      LAYER M4 ;
        RECT  0 86.976 0.084 87 ;
    END
  END o[535]
  PIN o[536]
    DIRECTION OUTPUT ;
    USE SIGNAL ;
    PORT
      LAYER M4 ;
        RECT  0 87.12 0.084 87.144 ;
    END
  END o[536]
  PIN o[537]
    DIRECTION OUTPUT ;
    USE SIGNAL ;
    PORT
      LAYER M4 ;
        RECT  0 87.312 0.084 87.336 ;
    END
  END o[537]
  PIN o[538]
    DIRECTION OUTPUT ;
    USE SIGNAL ;
    PORT
      LAYER M4 ;
        RECT  0 87.456 0.084 87.48 ;
    END
  END o[538]
  PIN o[539]
    DIRECTION OUTPUT ;
    USE SIGNAL ;
    PORT
      LAYER M4 ;
        RECT  0 87.6 0.084 87.624 ;
    END
  END o[539]
  PIN o[53]
    DIRECTION OUTPUT ;
    USE SIGNAL ;
    PORT
      LAYER M4 ;
        RECT  0 9.6 0.084 9.624 ;
    END
  END o[53]
  PIN o[540]
    DIRECTION OUTPUT ;
    USE SIGNAL ;
    PORT
      LAYER M4 ;
        RECT  0 87.792 0.084 87.816 ;
    END
  END o[540]
  PIN o[541]
    DIRECTION OUTPUT ;
    USE SIGNAL ;
    PORT
      LAYER M4 ;
        RECT  0 87.936 0.084 87.96 ;
    END
  END o[541]
  PIN o[542]
    DIRECTION OUTPUT ;
    USE SIGNAL ;
    PORT
      LAYER M4 ;
        RECT  0 88.08 0.084 88.104 ;
    END
  END o[542]
  PIN o[543]
    DIRECTION OUTPUT ;
    USE SIGNAL ;
    PORT
      LAYER M4 ;
        RECT  0 88.272 0.084 88.296 ;
    END
  END o[543]
  PIN o[544]
    DIRECTION OUTPUT ;
    USE SIGNAL ;
    PORT
      LAYER M4 ;
        RECT  0 88.416 0.084 88.44 ;
    END
  END o[544]
  PIN o[545]
    DIRECTION OUTPUT ;
    USE SIGNAL ;
    PORT
      LAYER M4 ;
        RECT  0 88.56 0.084 88.584 ;
    END
  END o[545]
  PIN o[546]
    DIRECTION OUTPUT ;
    USE SIGNAL ;
    PORT
      LAYER M4 ;
        RECT  0 88.752 0.084 88.776 ;
    END
  END o[546]
  PIN o[547]
    DIRECTION OUTPUT ;
    USE SIGNAL ;
    PORT
      LAYER M4 ;
        RECT  0 88.896 0.084 88.92 ;
    END
  END o[547]
  PIN o[548]
    DIRECTION OUTPUT ;
    USE SIGNAL ;
    PORT
      LAYER M4 ;
        RECT  0 89.04 0.084 89.064 ;
    END
  END o[548]
  PIN o[549]
    DIRECTION OUTPUT ;
    USE SIGNAL ;
    PORT
      LAYER M4 ;
        RECT  0 89.232 0.084 89.256 ;
    END
  END o[549]
  PIN o[54]
    DIRECTION OUTPUT ;
    USE SIGNAL ;
    PORT
      LAYER M4 ;
        RECT  0 9.744 0.084 9.768 ;
    END
  END o[54]
  PIN o[550]
    DIRECTION OUTPUT ;
    USE SIGNAL ;
    PORT
      LAYER M4 ;
        RECT  0 89.376 0.084 89.4 ;
    END
  END o[550]
  PIN o[551]
    DIRECTION OUTPUT ;
    USE SIGNAL ;
    PORT
      LAYER M4 ;
        RECT  0 89.52 0.084 89.544 ;
    END
  END o[551]
  PIN o[552]
    DIRECTION OUTPUT ;
    USE SIGNAL ;
    PORT
      LAYER M4 ;
        RECT  0 89.712 0.084 89.736 ;
    END
  END o[552]
  PIN o[553]
    DIRECTION OUTPUT ;
    USE SIGNAL ;
    PORT
      LAYER M4 ;
        RECT  0 89.856 0.084 89.88 ;
    END
  END o[553]
  PIN o[554]
    DIRECTION OUTPUT ;
    USE SIGNAL ;
    PORT
      LAYER M4 ;
        RECT  0 90.048 0.084 90.072 ;
    END
  END o[554]
  PIN o[555]
    DIRECTION OUTPUT ;
    USE SIGNAL ;
    PORT
      LAYER M4 ;
        RECT  0 90.192 0.084 90.216 ;
    END
  END o[555]
  PIN o[556]
    DIRECTION OUTPUT ;
    USE SIGNAL ;
    PORT
      LAYER M4 ;
        RECT  0 90.336 0.084 90.36 ;
    END
  END o[556]
  PIN o[557]
    DIRECTION OUTPUT ;
    USE SIGNAL ;
    PORT
      LAYER M4 ;
        RECT  0 90.528 0.084 90.552 ;
    END
  END o[557]
  PIN o[558]
    DIRECTION OUTPUT ;
    USE SIGNAL ;
    PORT
      LAYER M4 ;
        RECT  0 90.672 0.084 90.696 ;
    END
  END o[558]
  PIN o[559]
    DIRECTION OUTPUT ;
    USE SIGNAL ;
    PORT
      LAYER M4 ;
        RECT  0 90.816 0.084 90.84 ;
    END
  END o[559]
  PIN o[55]
    DIRECTION OUTPUT ;
    USE SIGNAL ;
    PORT
      LAYER M4 ;
        RECT  0 9.888 0.084 9.912 ;
    END
  END o[55]
  PIN o[560]
    DIRECTION OUTPUT ;
    USE SIGNAL ;
    PORT
      LAYER M4 ;
        RECT  0 91.008 0.084 91.032 ;
    END
  END o[560]
  PIN o[561]
    DIRECTION OUTPUT ;
    USE SIGNAL ;
    PORT
      LAYER M4 ;
        RECT  0 91.152 0.084 91.176 ;
    END
  END o[561]
  PIN o[56]
    DIRECTION OUTPUT ;
    USE SIGNAL ;
    PORT
      LAYER M4 ;
        RECT  0 10.08 0.084 10.104 ;
    END
  END o[56]
  PIN o[57]
    DIRECTION OUTPUT ;
    USE SIGNAL ;
    PORT
      LAYER M4 ;
        RECT  0 10.224 0.084 10.248 ;
    END
  END o[57]
  PIN o[58]
    DIRECTION OUTPUT ;
    USE SIGNAL ;
    PORT
      LAYER M4 ;
        RECT  0 10.368 0.084 10.392 ;
    END
  END o[58]
  PIN o[59]
    DIRECTION OUTPUT ;
    USE SIGNAL ;
    PORT
      LAYER M4 ;
        RECT  0 10.56 0.084 10.584 ;
    END
  END o[59]
  PIN o[5]
    DIRECTION OUTPUT ;
    USE SIGNAL ;
    PORT
      LAYER M4 ;
        RECT  0 1.872 0.084 1.896 ;
    END
  END o[5]
  PIN o[60]
    DIRECTION OUTPUT ;
    USE SIGNAL ;
    PORT
      LAYER M4 ;
        RECT  0 10.704 0.084 10.728 ;
    END
  END o[60]
  PIN o[61]
    DIRECTION OUTPUT ;
    USE SIGNAL ;
    PORT
      LAYER M4 ;
        RECT  0 10.848 0.084 10.872 ;
    END
  END o[61]
  PIN o[62]
    DIRECTION OUTPUT ;
    USE SIGNAL ;
    PORT
      LAYER M4 ;
        RECT  0 11.04 0.084 11.064 ;
    END
  END o[62]
  PIN o[63]
    DIRECTION OUTPUT ;
    USE SIGNAL ;
    PORT
      LAYER M4 ;
        RECT  0 11.184 0.084 11.208 ;
    END
  END o[63]
  PIN o[64]
    DIRECTION OUTPUT ;
    USE SIGNAL ;
    PORT
      LAYER M4 ;
        RECT  0 11.328 0.084 11.352 ;
    END
  END o[64]
  PIN o[65]
    DIRECTION OUTPUT ;
    USE SIGNAL ;
    PORT
      LAYER M4 ;
        RECT  0 11.52 0.084 11.544 ;
    END
  END o[65]
  PIN o[66]
    DIRECTION OUTPUT ;
    USE SIGNAL ;
    PORT
      LAYER M4 ;
        RECT  0 11.664 0.084 11.688 ;
    END
  END o[66]
  PIN o[67]
    DIRECTION OUTPUT ;
    USE SIGNAL ;
    PORT
      LAYER M4 ;
        RECT  0 11.808 0.084 11.832 ;
    END
  END o[67]
  PIN o[68]
    DIRECTION OUTPUT ;
    USE SIGNAL ;
    PORT
      LAYER M4 ;
        RECT  0 12 0.084 12.024 ;
    END
  END o[68]
  PIN o[69]
    DIRECTION OUTPUT ;
    USE SIGNAL ;
    PORT
      LAYER M4 ;
        RECT  0 12.144 0.084 12.168 ;
    END
  END o[69]
  PIN o[6]
    DIRECTION OUTPUT ;
    USE SIGNAL ;
    PORT
      LAYER M4 ;
        RECT  0 2.016 0.084 2.04 ;
    END
  END o[6]
  PIN o[70]
    DIRECTION OUTPUT ;
    USE SIGNAL ;
    PORT
      LAYER M4 ;
        RECT  0 12.288 0.084 12.312 ;
    END
  END o[70]
  PIN o[71]
    DIRECTION OUTPUT ;
    USE SIGNAL ;
    PORT
      LAYER M4 ;
        RECT  0 12.48 0.084 12.504 ;
    END
  END o[71]
  PIN o[72]
    DIRECTION OUTPUT ;
    USE SIGNAL ;
    PORT
      LAYER M4 ;
        RECT  0 12.624 0.084 12.648 ;
    END
  END o[72]
  PIN o[73]
    DIRECTION OUTPUT ;
    USE SIGNAL ;
    PORT
      LAYER M4 ;
        RECT  0 12.768 0.084 12.792 ;
    END
  END o[73]
  PIN o[74]
    DIRECTION OUTPUT ;
    USE SIGNAL ;
    PORT
      LAYER M4 ;
        RECT  0 12.96 0.084 12.984 ;
    END
  END o[74]
  PIN o[75]
    DIRECTION OUTPUT ;
    USE SIGNAL ;
    PORT
      LAYER M4 ;
        RECT  0 13.104 0.084 13.128 ;
    END
  END o[75]
  PIN o[76]
    DIRECTION OUTPUT ;
    USE SIGNAL ;
    PORT
      LAYER M4 ;
        RECT  0 13.296 0.084 13.32 ;
    END
  END o[76]
  PIN o[77]
    DIRECTION OUTPUT ;
    USE SIGNAL ;
    PORT
      LAYER M4 ;
        RECT  0 13.44 0.084 13.464 ;
    END
  END o[77]
  PIN o[78]
    DIRECTION OUTPUT ;
    USE SIGNAL ;
    PORT
      LAYER M4 ;
        RECT  0 13.584 0.084 13.608 ;
    END
  END o[78]
  PIN o[79]
    DIRECTION OUTPUT ;
    USE SIGNAL ;
    PORT
      LAYER M4 ;
        RECT  0 13.776 0.084 13.8 ;
    END
  END o[79]
  PIN o[7]
    DIRECTION OUTPUT ;
    USE SIGNAL ;
    PORT
      LAYER M4 ;
        RECT  0 2.208 0.084 2.232 ;
    END
  END o[7]
  PIN o[80]
    DIRECTION OUTPUT ;
    USE SIGNAL ;
    PORT
      LAYER M4 ;
        RECT  0 13.92 0.084 13.944 ;
    END
  END o[80]
  PIN o[81]
    DIRECTION OUTPUT ;
    USE SIGNAL ;
    PORT
      LAYER M4 ;
        RECT  0 14.064 0.084 14.088 ;
    END
  END o[81]
  PIN o[82]
    DIRECTION OUTPUT ;
    USE SIGNAL ;
    PORT
      LAYER M4 ;
        RECT  0 14.256 0.084 14.28 ;
    END
  END o[82]
  PIN o[83]
    DIRECTION OUTPUT ;
    USE SIGNAL ;
    PORT
      LAYER M4 ;
        RECT  0 14.4 0.084 14.424 ;
    END
  END o[83]
  PIN o[84]
    DIRECTION OUTPUT ;
    USE SIGNAL ;
    PORT
      LAYER M4 ;
        RECT  0 14.544 0.084 14.568 ;
    END
  END o[84]
  PIN o[85]
    DIRECTION OUTPUT ;
    USE SIGNAL ;
    PORT
      LAYER M4 ;
        RECT  0 14.736 0.084 14.76 ;
    END
  END o[85]
  PIN o[86]
    DIRECTION OUTPUT ;
    USE SIGNAL ;
    PORT
      LAYER M4 ;
        RECT  0 14.88 0.084 14.904 ;
    END
  END o[86]
  PIN o[87]
    DIRECTION OUTPUT ;
    USE SIGNAL ;
    PORT
      LAYER M4 ;
        RECT  0 15.024 0.084 15.048 ;
    END
  END o[87]
  PIN o[88]
    DIRECTION OUTPUT ;
    USE SIGNAL ;
    PORT
      LAYER M4 ;
        RECT  0 15.216 0.084 15.24 ;
    END
  END o[88]
  PIN o[89]
    DIRECTION OUTPUT ;
    USE SIGNAL ;
    PORT
      LAYER M4 ;
        RECT  0 15.36 0.084 15.384 ;
    END
  END o[89]
  PIN o[8]
    DIRECTION OUTPUT ;
    USE SIGNAL ;
    PORT
      LAYER M4 ;
        RECT  0 2.352 0.084 2.376 ;
    END
  END o[8]
  PIN o[90]
    DIRECTION OUTPUT ;
    USE SIGNAL ;
    PORT
      LAYER M4 ;
        RECT  0 15.504 0.084 15.528 ;
    END
  END o[90]
  PIN o[91]
    DIRECTION OUTPUT ;
    USE SIGNAL ;
    PORT
      LAYER M4 ;
        RECT  0 15.696 0.084 15.72 ;
    END
  END o[91]
  PIN o[92]
    DIRECTION OUTPUT ;
    USE SIGNAL ;
    PORT
      LAYER M4 ;
        RECT  0 15.84 0.084 15.864 ;
    END
  END o[92]
  PIN o[93]
    DIRECTION OUTPUT ;
    USE SIGNAL ;
    PORT
      LAYER M4 ;
        RECT  0 15.984 0.084 16.008 ;
    END
  END o[93]
  PIN o[94]
    DIRECTION OUTPUT ;
    USE SIGNAL ;
    PORT
      LAYER M4 ;
        RECT  0 16.176 0.084 16.2 ;
    END
  END o[94]
  PIN o[95]
    DIRECTION OUTPUT ;
    USE SIGNAL ;
    PORT
      LAYER M4 ;
        RECT  0 16.32 0.084 16.344 ;
    END
  END o[95]
  PIN o[96]
    DIRECTION OUTPUT ;
    USE SIGNAL ;
    PORT
      LAYER M4 ;
        RECT  0 16.464 0.084 16.488 ;
    END
  END o[96]
  PIN o[97]
    DIRECTION OUTPUT ;
    USE SIGNAL ;
    PORT
      LAYER M4 ;
        RECT  0 16.656 0.084 16.68 ;
    END
  END o[97]
  PIN o[98]
    DIRECTION OUTPUT ;
    USE SIGNAL ;
    PORT
      LAYER M4 ;
        RECT  0 16.8 0.084 16.824 ;
    END
  END o[98]
  PIN o[99]
    DIRECTION OUTPUT ;
    USE SIGNAL ;
    PORT
      LAYER M4 ;
        RECT  0 16.944 0.084 16.968 ;
    END
  END o[99]
  PIN o[9]
    DIRECTION OUTPUT ;
    USE SIGNAL ;
    PORT
      LAYER M4 ;
        RECT  0 2.496 0.084 2.52 ;
    END
  END o[9]
  PIN rs
    DIRECTION INPUT ;
    USE SIGNAL ;
    PORT
      LAYER M3 ;
        RECT  16.884 95.002 16.902 95.04 ;
    END
    PORT
      LAYER M3 ;
        RECT  16.812 94.981 16.902 95.009 ;
    END
    PORT
      LAYER M3 ;
        RECT  16.884 95.009 16.902 95.021 ;
    END
  END rs
  PIN VDD
    DIRECTION INOUT ;
    USE POWER ;
    PORT
      LAYER M5 ;
        RECT  34.992 2.151 35.112 92.889 ;
        RECT  32.292 2.151 32.412 92.889 ;
        RECT  29.592 2.151 29.712 92.889 ;
        RECT  26.892 2.151 27.012 92.889 ;
        RECT  24.192 2.151 24.312 92.889 ;
        RECT  21.492 2.151 21.612 92.889 ;
        RECT  18.792 2.151 18.912 92.889 ;
        RECT  16.092 2.151 16.212 92.889 ;
        RECT  13.392 2.151 13.512 92.889 ;
        RECT  10.692 2.151 10.812 92.889 ;
        RECT  7.992 2.151 8.112 92.889 ;
        RECT  5.292 2.151 5.412 92.889 ;
        RECT  2.592 2.151 2.712 92.889 ;
    END
  END VDD
  PIN VSS
    DIRECTION INOUT ;
    USE GROUND ;
    PORT
      LAYER M5 ;
        RECT  34.8 2.137 34.92 92.903 ;
        RECT  32.1 2.137 32.22 92.903 ;
        RECT  29.4 2.137 29.52 92.903 ;
        RECT  26.7 2.137 26.82 92.903 ;
        RECT  24 2.137 24.12 92.903 ;
        RECT  21.3 2.137 21.42 92.903 ;
        RECT  18.6 2.137 18.72 92.903 ;
        RECT  15.9 2.137 16.02 92.903 ;
        RECT  13.2 2.137 13.32 92.903 ;
        RECT  10.5 2.137 10.62 92.903 ;
        RECT  7.8 2.137 7.92 92.903 ;
        RECT  5.1 2.137 5.22 92.903 ;
        RECT  2.4 2.137 2.52 92.903 ;
    END
  END VSS
  # OT_OBS_CLOSED layer=M5 d_um=1.536 added=562
  OBS
    LAYER RVTN ;
     RECT  2.16 2.16 36.72 2.295 ;
     RECT  2.16 2.565 36.72 2.835 ;
     RECT  2.16 3.105 36.72 3.375 ;
     RECT  2.16 3.645 36.72 3.915 ;
     RECT  2.16 4.185 36.72 4.455 ;
     RECT  2.16 4.725 36.72 4.995 ;
     RECT  2.16 5.265 36.72 5.535 ;
     RECT  2.16 5.805 36.72 6.075 ;
     RECT  2.16 6.345 36.72 6.615 ;
     RECT  2.16 6.885 36.72 7.155 ;
     RECT  2.16 7.425 36.72 7.695 ;
     RECT  2.16 7.965 36.72 8.235 ;
     RECT  2.16 8.505 36.72 8.775 ;
     RECT  2.16 9.045 36.72 9.315 ;
     RECT  2.16 9.585 36.72 9.855 ;
     RECT  2.16 10.125 36.72 10.395 ;
     RECT  2.16 10.665 36.72 10.935 ;
     RECT  2.16 11.205 36.72 11.475 ;
     RECT  2.16 11.745 36.72 12.015 ;
     RECT  2.16 12.285 36.72 12.555 ;
     RECT  2.16 12.825 36.72 13.095 ;
     RECT  2.16 13.365 36.72 13.635 ;
     RECT  2.16 13.905 36.72 14.175 ;
     RECT  2.16 14.445 36.72 14.715 ;
     RECT  2.16 14.985 36.72 15.255 ;
     RECT  2.16 15.525 36.72 15.795 ;
     RECT  2.16 16.065 36.72 16.335 ;
     RECT  2.16 16.605 36.72 16.875 ;
     RECT  2.16 17.145 36.72 17.415 ;
     RECT  2.16 17.685 36.72 17.955 ;
     RECT  2.16 18.225 36.72 18.495 ;
     RECT  2.16 18.765 36.72 19.035 ;
     RECT  2.16 19.305 36.72 19.575 ;
     RECT  2.16 19.845 36.72 20.115 ;
     RECT  2.16 20.385 36.72 20.655 ;
     RECT  2.16 20.925 36.72 21.195 ;
     RECT  2.16 21.465 36.72 21.735 ;
     RECT  2.16 22.005 36.72 22.275 ;
     RECT  2.16 22.545 36.72 22.815 ;
     RECT  2.16 23.085 36.72 23.355 ;
     RECT  2.16 23.625 36.72 23.895 ;
     RECT  2.16 24.165 36.72 24.435 ;
     RECT  2.16 24.705 36.72 24.975 ;
     RECT  2.16 25.245 36.72 25.515 ;
     RECT  2.16 25.785 36.72 26.055 ;
     RECT  2.16 26.325 36.72 26.595 ;
     RECT  2.16 26.865 36.72 27.135 ;
     RECT  2.16 27.405 36.72 27.675 ;
     RECT  2.16 27.945 36.72 28.215 ;
     RECT  2.16 28.485 36.72 28.755 ;
     RECT  2.16 29.025 36.72 29.295 ;
     RECT  2.16 29.565 36.72 29.835 ;
     RECT  2.16 30.105 36.72 30.375 ;
     RECT  2.16 30.645 36.72 30.915 ;
     RECT  2.16 31.185 36.72 31.455 ;
     RECT  2.16 31.725 36.72 31.995 ;
     RECT  2.16 32.265 36.72 32.535 ;
     RECT  2.16 32.805 36.72 33.075 ;
     RECT  2.16 33.345 36.72 33.615 ;
     RECT  2.16 33.885 36.72 34.155 ;
     RECT  2.16 34.425 36.72 34.695 ;
     RECT  2.16 34.965 36.72 35.235 ;
     RECT  2.16 35.505 36.72 35.775 ;
     RECT  2.16 36.045 36.72 36.315 ;
     RECT  2.16 36.585 36.72 36.855 ;
     RECT  2.16 37.125 36.72 37.395 ;
     RECT  2.16 37.665 36.72 37.935 ;
     RECT  2.16 38.205 36.72 38.475 ;
     RECT  2.16 38.745 36.72 39.015 ;
     RECT  2.16 39.285 36.72 39.555 ;
     RECT  2.16 39.825 36.72 40.095 ;
     RECT  2.16 40.365 36.72 40.635 ;
     RECT  2.16 40.905 36.72 41.175 ;
     RECT  2.16 41.445 36.72 41.715 ;
     RECT  2.16 41.985 36.72 42.255 ;
     RECT  2.16 42.525 36.72 42.795 ;
     RECT  2.16 43.065 36.72 43.335 ;
     RECT  2.16 43.605 36.72 43.875 ;
     RECT  2.16 44.145 36.72 44.415 ;
     RECT  2.16 44.685 36.72 44.955 ;
     RECT  2.16 45.225 36.72 45.495 ;
     RECT  2.16 45.765 36.72 46.035 ;
     RECT  2.16 46.305 36.72 46.575 ;
     RECT  2.16 46.845 36.72 47.115 ;
     RECT  2.16 47.385 36.72 47.655 ;
     RECT  2.16 47.925 36.72 48.195 ;
     RECT  2.16 48.465 36.72 48.735 ;
     RECT  2.16 49.005 36.72 49.275 ;
     RECT  2.16 49.545 36.72 49.815 ;
     RECT  2.16 50.085 36.72 50.355 ;
     RECT  2.16 50.625 36.72 50.895 ;
     RECT  2.16 51.165 36.72 51.435 ;
     RECT  2.16 51.705 36.72 51.975 ;
     RECT  2.16 52.245 36.72 52.515 ;
     RECT  2.16 52.785 36.72 53.055 ;
     RECT  2.16 53.325 36.72 53.595 ;
     RECT  2.16 53.865 36.72 54.135 ;
     RECT  2.16 54.405 36.72 54.675 ;
     RECT  2.16 54.945 36.72 55.215 ;
     RECT  2.16 55.485 36.72 55.755 ;
     RECT  2.16 56.025 36.72 56.295 ;
     RECT  2.16 56.565 36.72 56.835 ;
     RECT  2.16 57.105 36.72 57.375 ;
     RECT  2.16 57.645 36.72 57.915 ;
     RECT  2.16 58.185 36.72 58.455 ;
     RECT  2.16 58.725 36.72 58.995 ;
     RECT  2.16 59.265 36.72 59.535 ;
     RECT  2.16 59.805 36.72 60.075 ;
     RECT  2.16 60.345 36.72 60.615 ;
     RECT  2.16 60.885 36.72 61.155 ;
     RECT  2.16 61.425 36.72 61.695 ;
     RECT  2.16 61.965 36.72 62.235 ;
     RECT  2.16 62.505 36.72 62.775 ;
     RECT  2.16 63.045 36.72 63.315 ;
     RECT  2.16 63.585 36.72 63.855 ;
     RECT  2.16 64.125 36.72 64.395 ;
     RECT  2.16 64.665 36.72 64.935 ;
     RECT  2.16 65.205 36.72 65.475 ;
     RECT  2.16 65.745 36.72 66.015 ;
     RECT  2.16 66.285 36.72 66.555 ;
     RECT  2.16 66.825 36.72 67.095 ;
     RECT  2.16 67.365 36.72 67.635 ;
     RECT  2.16 67.905 36.72 68.175 ;
     RECT  2.16 68.445 36.72 68.715 ;
     RECT  2.16 68.985 36.72 69.255 ;
     RECT  2.16 69.525 36.72 69.795 ;
     RECT  2.16 70.065 36.72 70.335 ;
     RECT  2.16 70.605 36.72 70.875 ;
     RECT  2.16 71.145 36.72 71.415 ;
     RECT  2.16 71.685 36.72 71.955 ;
     RECT  2.16 72.225 36.72 72.495 ;
     RECT  2.16 72.765 36.72 73.035 ;
     RECT  2.16 73.305 36.72 73.575 ;
     RECT  2.16 73.845 36.72 74.115 ;
     RECT  2.16 74.385 36.72 74.655 ;
     RECT  2.16 74.925 36.72 75.195 ;
     RECT  2.16 75.465 36.72 75.735 ;
     RECT  2.16 76.005 36.72 76.275 ;
     RECT  2.16 76.545 36.72 76.815 ;
     RECT  2.16 77.085 36.72 77.355 ;
     RECT  2.16 77.625 36.72 77.895 ;
     RECT  2.16 78.165 36.72 78.435 ;
     RECT  2.16 78.705 36.72 78.975 ;
     RECT  2.16 79.245 36.72 79.515 ;
     RECT  2.16 79.785 36.72 80.055 ;
     RECT  2.16 80.325 36.72 80.595 ;
     RECT  2.16 80.865 36.72 81.135 ;
     RECT  2.16 81.405 36.72 81.675 ;
     RECT  2.16 81.945 36.72 82.215 ;
     RECT  2.16 82.485 36.72 82.755 ;
     RECT  2.16 83.025 36.72 83.295 ;
     RECT  2.16 83.565 36.72 83.835 ;
     RECT  2.16 84.105 36.72 84.375 ;
     RECT  2.16 84.645 36.72 84.915 ;
     RECT  2.16 85.185 36.72 85.455 ;
     RECT  2.16 85.725 36.72 85.995 ;
     RECT  2.16 86.265 36.72 86.535 ;
     RECT  2.16 86.805 36.72 87.075 ;
     RECT  2.16 87.345 36.72 87.615 ;
     RECT  2.16 87.885 36.72 88.155 ;
     RECT  2.16 88.425 36.72 88.695 ;
     RECT  2.16 88.965 36.72 89.235 ;
     RECT  2.16 89.505 36.72 89.775 ;
     RECT  2.16 90.045 36.72 90.315 ;
     RECT  2.16 90.585 36.72 90.855 ;
     RECT  2.16 91.125 36.72 91.395 ;
     RECT  2.16 91.665 36.72 91.935 ;
     RECT  2.16 92.205 36.72 92.475 ;
     RECT  2.16 92.745 36.72 92.88 ;
    LAYER RVTP ;
     RECT  2.16 2.295 36.72 2.565 ;
     RECT  2.16 2.835 36.72 3.105 ;
     RECT  2.16 3.375 36.72 3.645 ;
     RECT  2.16 3.915 36.72 4.185 ;
     RECT  2.16 4.455 36.72 4.725 ;
     RECT  2.16 4.995 36.72 5.265 ;
     RECT  2.16 5.535 36.72 5.805 ;
     RECT  2.16 6.075 36.72 6.345 ;
     RECT  2.16 6.615 36.72 6.885 ;
     RECT  2.16 7.155 36.72 7.425 ;
     RECT  2.16 7.695 36.72 7.965 ;
     RECT  2.16 8.235 36.72 8.505 ;
     RECT  2.16 8.775 36.72 9.045 ;
     RECT  2.16 9.315 36.72 9.585 ;
     RECT  2.16 9.855 36.72 10.125 ;
     RECT  2.16 10.395 36.72 10.665 ;
     RECT  2.16 10.935 36.72 11.205 ;
     RECT  2.16 11.475 36.72 11.745 ;
     RECT  2.16 12.015 36.72 12.285 ;
     RECT  2.16 12.555 36.72 12.825 ;
     RECT  2.16 13.095 36.72 13.365 ;
     RECT  2.16 13.635 36.72 13.905 ;
     RECT  2.16 14.175 36.72 14.445 ;
     RECT  2.16 14.715 36.72 14.985 ;
     RECT  2.16 15.255 36.72 15.525 ;
     RECT  2.16 15.795 36.72 16.065 ;
     RECT  2.16 16.335 36.72 16.605 ;
     RECT  2.16 16.875 36.72 17.145 ;
     RECT  2.16 17.415 36.72 17.685 ;
     RECT  2.16 17.955 36.72 18.225 ;
     RECT  2.16 18.495 36.72 18.765 ;
     RECT  2.16 19.035 36.72 19.305 ;
     RECT  2.16 19.575 36.72 19.845 ;
     RECT  2.16 20.115 36.72 20.385 ;
     RECT  2.16 20.655 36.72 20.925 ;
     RECT  2.16 21.195 36.72 21.465 ;
     RECT  2.16 21.735 36.72 22.005 ;
     RECT  2.16 22.275 36.72 22.545 ;
     RECT  2.16 22.815 36.72 23.085 ;
     RECT  2.16 23.355 36.72 23.625 ;
     RECT  2.16 23.895 36.72 24.165 ;
     RECT  2.16 24.435 36.72 24.705 ;
     RECT  2.16 24.975 36.72 25.245 ;
     RECT  2.16 25.515 36.72 25.785 ;
     RECT  2.16 26.055 36.72 26.325 ;
     RECT  2.16 26.595 36.72 26.865 ;
     RECT  2.16 27.135 36.72 27.405 ;
     RECT  2.16 27.675 36.72 27.945 ;
     RECT  2.16 28.215 36.72 28.485 ;
     RECT  2.16 28.755 36.72 29.025 ;
     RECT  2.16 29.295 36.72 29.565 ;
     RECT  2.16 29.835 36.72 30.105 ;
     RECT  2.16 30.375 36.72 30.645 ;
     RECT  2.16 30.915 36.72 31.185 ;
     RECT  2.16 31.455 36.72 31.725 ;
     RECT  2.16 31.995 36.72 32.265 ;
     RECT  2.16 32.535 36.72 32.805 ;
     RECT  2.16 33.075 36.72 33.345 ;
     RECT  2.16 33.615 36.72 33.885 ;
     RECT  2.16 34.155 36.72 34.425 ;
     RECT  2.16 34.695 36.72 34.965 ;
     RECT  2.16 35.235 36.72 35.505 ;
     RECT  2.16 35.775 36.72 36.045 ;
     RECT  2.16 36.315 36.72 36.585 ;
     RECT  2.16 36.855 36.72 37.125 ;
     RECT  2.16 37.395 36.72 37.665 ;
     RECT  2.16 37.935 36.72 38.205 ;
     RECT  2.16 38.475 36.72 38.745 ;
     RECT  2.16 39.015 36.72 39.285 ;
     RECT  2.16 39.555 36.72 39.825 ;
     RECT  2.16 40.095 36.72 40.365 ;
     RECT  2.16 40.635 36.72 40.905 ;
     RECT  2.16 41.175 36.72 41.445 ;
     RECT  2.16 41.715 36.72 41.985 ;
     RECT  2.16 42.255 36.72 42.525 ;
     RECT  2.16 42.795 36.72 43.065 ;
     RECT  2.16 43.335 36.72 43.605 ;
     RECT  2.16 43.875 36.72 44.145 ;
     RECT  2.16 44.415 36.72 44.685 ;
     RECT  2.16 44.955 36.72 45.225 ;
     RECT  2.16 45.495 36.72 45.765 ;
     RECT  2.16 46.035 36.72 46.305 ;
     RECT  2.16 46.575 36.72 46.845 ;
     RECT  2.16 47.115 36.72 47.385 ;
     RECT  2.16 47.655 36.72 47.925 ;
     RECT  2.16 48.195 36.72 48.465 ;
     RECT  2.16 48.735 36.72 49.005 ;
     RECT  2.16 49.275 36.72 49.545 ;
     RECT  2.16 49.815 36.72 50.085 ;
     RECT  2.16 50.355 36.72 50.625 ;
     RECT  2.16 50.895 36.72 51.165 ;
     RECT  2.16 51.435 36.72 51.705 ;
     RECT  2.16 51.975 36.72 52.245 ;
     RECT  2.16 52.515 36.72 52.785 ;
     RECT  2.16 53.055 36.72 53.325 ;
     RECT  2.16 53.595 36.72 53.865 ;
     RECT  2.16 54.135 36.72 54.405 ;
     RECT  2.16 54.675 36.72 54.945 ;
     RECT  2.16 55.215 36.72 55.485 ;
     RECT  2.16 55.755 36.72 56.025 ;
     RECT  2.16 56.295 36.72 56.565 ;
     RECT  2.16 56.835 36.72 57.105 ;
     RECT  2.16 57.375 36.72 57.645 ;
     RECT  2.16 57.915 36.72 58.185 ;
     RECT  2.16 58.455 36.72 58.725 ;
     RECT  2.16 58.995 36.72 59.265 ;
     RECT  2.16 59.535 36.72 59.805 ;
     RECT  2.16 60.075 36.72 60.345 ;
     RECT  2.16 60.615 36.72 60.885 ;
     RECT  2.16 61.155 36.72 61.425 ;
     RECT  2.16 61.695 36.72 61.965 ;
     RECT  2.16 62.235 36.72 62.505 ;
     RECT  2.16 62.775 36.72 63.045 ;
     RECT  2.16 63.315 36.72 63.585 ;
     RECT  2.16 63.855 36.72 64.125 ;
     RECT  2.16 64.395 36.72 64.665 ;
     RECT  2.16 64.935 36.72 65.205 ;
     RECT  2.16 65.475 36.72 65.745 ;
     RECT  2.16 66.015 36.72 66.285 ;
     RECT  2.16 66.555 36.72 66.825 ;
     RECT  2.16 67.095 36.72 67.365 ;
     RECT  2.16 67.635 36.72 67.905 ;
     RECT  2.16 68.175 36.72 68.445 ;
     RECT  2.16 68.715 36.72 68.985 ;
     RECT  2.16 69.255 36.72 69.525 ;
     RECT  2.16 69.795 36.72 70.065 ;
     RECT  2.16 70.335 36.72 70.605 ;
     RECT  2.16 70.875 36.72 71.145 ;
     RECT  2.16 71.415 36.72 71.685 ;
     RECT  2.16 71.955 36.72 72.225 ;
     RECT  2.16 72.495 36.72 72.765 ;
     RECT  2.16 73.035 36.72 73.305 ;
     RECT  2.16 73.575 36.72 73.845 ;
     RECT  2.16 74.115 36.72 74.385 ;
     RECT  2.16 74.655 36.72 74.925 ;
     RECT  2.16 75.195 36.72 75.465 ;
     RECT  2.16 75.735 36.72 76.005 ;
     RECT  2.16 76.275 36.72 76.545 ;
     RECT  2.16 76.815 36.72 77.085 ;
     RECT  2.16 77.355 36.72 77.625 ;
     RECT  2.16 77.895 36.72 78.165 ;
     RECT  2.16 78.435 36.72 78.705 ;
     RECT  2.16 78.975 36.72 79.245 ;
     RECT  2.16 79.515 36.72 79.785 ;
     RECT  2.16 80.055 36.72 80.325 ;
     RECT  2.16 80.595 36.72 80.865 ;
     RECT  2.16 81.135 36.72 81.405 ;
     RECT  2.16 81.675 36.72 81.945 ;
     RECT  2.16 82.215 36.72 82.485 ;
     RECT  2.16 82.755 36.72 83.025 ;
     RECT  2.16 83.295 36.72 83.565 ;
     RECT  2.16 83.835 36.72 84.105 ;
     RECT  2.16 84.375 36.72 84.645 ;
     RECT  2.16 84.915 36.72 85.185 ;
     RECT  2.16 85.455 36.72 85.725 ;
     RECT  2.16 85.995 36.72 86.265 ;
     RECT  2.16 86.535 36.72 86.805 ;
     RECT  2.16 87.075 36.72 87.345 ;
     RECT  2.16 87.615 36.72 87.885 ;
     RECT  2.16 88.155 36.72 88.425 ;
     RECT  2.16 88.695 36.72 88.965 ;
     RECT  2.16 89.235 36.72 89.505 ;
     RECT  2.16 89.775 36.72 90.045 ;
     RECT  2.16 90.315 36.72 90.585 ;
     RECT  2.16 90.855 36.72 91.125 ;
     RECT  2.16 91.395 36.72 91.665 ;
     RECT  2.16 91.935 36.72 92.205 ;
     RECT  2.16 92.475 36.72 92.745 ;
    LAYER M1 ;
     RECT  2.16 2.151 36.72 92.889 ;
    LAYER M2 ;
     RECT  0.103 88.866 0.139 88.884 ;
     RECT  0.103 32.166 0.499 32.184 ;
     RECT  0.103 16.776 0.535 16.794 ;
     RECT  0.103 23.256 0.535 23.274 ;
     RECT  0.103 58.086 0.535 58.644 ;
     RECT  0.103 92.448 0.535 92.466 ;
     RECT  0.535 83.196 1.975 83.754 ;
     RECT  1.723 2.106 2.16 2.124 ;
     RECT  0.535 4.428 2.16 4.446 ;
     RECT  0.535 6.786 2.16 6.804 ;
     RECT  0.535 11.916 2.16 11.934 ;
     RECT  0.103 14.076 2.16 14.094 ;
     RECT  0.535 16.416 2.16 16.794 ;
     RECT  0.535 17.586 2.16 18.054 ;
     RECT  0.535 22.086 2.16 23.814 ;
     RECT  0.103 28.386 2.16 28.944 ;
     RECT  0.103 30.726 2.16 30.744 ;
     RECT  0.499 31.734 2.16 32.184 ;
     RECT  0.535 36.018 2.16 36.036 ;
     RECT  0.535 37.566 2.16 37.584 ;
     RECT  0.535 42.606 2.16 42.624 ;
     RECT  0.535 43.812 2.16 43.83 ;
     RECT  0.535 47.286 2.16 47.844 ;
     RECT  0.103 52.416 2.16 52.434 ;
     RECT  0.103 53.496 2.16 53.514 ;
     RECT  0.535 57.924 2.16 58.644 ;
     RECT  0.535 62.55 2.16 62.568 ;
     RECT  0.103 63.756 2.16 64.314 ;
     RECT  0.535 67.716 2.16 67.734 ;
     RECT  0.535 72.936 2.16 72.954 ;
     RECT  0.535 74.016 2.16 74.034 ;
     RECT  0.535 78.066 2.16 78.624 ;
     RECT  0.535 79.686 2.16 79.704 ;
     RECT  1.975 82.458 2.16 83.754 ;
     RECT  0.535 84.888 2.16 84.906 ;
     RECT  0.139 88.326 2.16 88.884 ;
     RECT  1.975 90.126 2.16 90.144 ;
     RECT  0.535 92.448 2.16 92.844 ;
     RECT  2.16 2.106 3.055 92.889 ;
     RECT  3.055 1.962 3.595 92.889 ;
     RECT  3.595 1.926 7.051 92.889 ;
     RECT  7.051 1.881 9.383 92.889 ;
     RECT  15.979 94.986 16.079 95.004 ;
     RECT  9.383 1.926 16.159 92.889 ;
     RECT  16.807 94.986 16.907 95.004 ;
     RECT  16.159 1.836 17.095 92.889 ;
     RECT  17.095 1.764 20.939 92.889 ;
     RECT  20.939 1.836 35.159 92.889 ;
     RECT  35.159 1.881 36.203 92.889 ;
     RECT  36.203 2.034 36.72 92.889 ;
     RECT  36.72 81.414 36.923 91.188 ;
     RECT  36.72 4.122 36.995 28.854 ;
     RECT  36.72 2.034 37.031 3.366 ;
     RECT  36.995 4.122 37.031 20.718 ;
     RECT  36.72 75.204 37.031 80.658 ;
     RECT  36.72 43.074 37.067 48.456 ;
     RECT  36.72 49.32 37.427 60.948 ;
     RECT  37.427 49.32 37.463 60.444 ;
     RECT  36.72 29.88 37.499 30.096 ;
     RECT  37.031 75.204 37.499 76.338 ;
     RECT  37.031 77.094 37.499 78.264 ;
     RECT  36.923 90.018 37.499 91.188 ;
     RECT  36.995 21.51 37.535 28.854 ;
     RECT  37.463 49.32 37.535 56.286 ;
     RECT  37.031 79.056 37.535 80.658 ;
     RECT  36.923 81.414 37.535 89.19 ;
     RECT  37.031 4.122 37.571 11.808 ;
     RECT  37.031 12.798 37.571 20.718 ;
     RECT  36.72 33.048 37.571 33.678 ;
     RECT  37.535 52.686 37.571 56.286 ;
     RECT  37.463 57.186 37.571 60.444 ;
     RECT  37.535 86.508 37.571 89.19 ;
     RECT  37.571 4.122 37.607 5.526 ;
     RECT  37.571 6.39 37.607 8.838 ;
     RECT  37.571 9.666 37.607 11.808 ;
     RECT  37.571 12.798 37.607 14.778 ;
     RECT  37.571 15.768 37.607 20.718 ;
     RECT  37.535 21.978 37.607 28.854 ;
     RECT  36.72 34.434 37.607 42.282 ;
     RECT  37.067 43.11 37.607 48.456 ;
     RECT  37.535 49.554 37.607 51.894 ;
     RECT  36.72 67.914 37.607 70.902 ;
     RECT  36.72 73.89 37.607 74.376 ;
     RECT  37.535 81.414 37.607 85.716 ;
     RECT  37.499 90.018 37.607 90.846 ;
     RECT  36.72 30.888 37.643 31.914 ;
     RECT  37.607 43.11 37.643 46.944 ;
     RECT  37.499 75.204 37.643 76.068 ;
     RECT  37.607 82.494 37.643 85.482 ;
     RECT  37.607 14.76 37.679 14.778 ;
     RECT  37.643 43.11 38.183 46.764 ;
     RECT  37.607 47.7 38.183 48.294 ;
     RECT  37.031 2.034 38.219 3.168 ;
     RECT  37.607 6.39 38.219 6.678 ;
     RECT  37.607 7.776 38.219 8.838 ;
     RECT  37.607 11.106 38.219 11.808 ;
     RECT  37.607 12.87 38.219 13.122 ;
     RECT  37.607 15.768 38.219 19.026 ;
     RECT  37.607 20.088 38.219 20.718 ;
     RECT  37.607 22.212 38.219 26.118 ;
     RECT  37.607 27.486 38.219 28.854 ;
     RECT  37.499 29.916 38.219 30.096 ;
     RECT  37.643 30.888 38.219 31.014 ;
     RECT  37.643 31.896 38.219 31.914 ;
     RECT  37.571 33.156 38.219 33.678 ;
     RECT  37.607 34.434 38.219 37.224 ;
     RECT  37.607 38.25 38.219 42.282 ;
     RECT  38.183 46.08 38.219 46.764 ;
     RECT  38.183 48.276 38.219 48.294 ;
     RECT  37.607 49.554 38.219 50.004 ;
     RECT  37.607 50.94 38.219 51.894 ;
     RECT  37.571 52.686 38.219 55.782 ;
     RECT  37.571 57.186 38.219 57.294 ;
     RECT  37.571 58.194 38.219 60.444 ;
     RECT  36.72 61.776 38.219 63.954 ;
     RECT  36.72 64.836 38.219 66.654 ;
     RECT  37.607 67.914 38.219 68.202 ;
     RECT  37.607 68.958 38.219 70.902 ;
     RECT  36.72 71.694 38.219 72.684 ;
     RECT  37.607 73.89 38.219 73.944 ;
     RECT  37.535 79.056 38.219 80.622 ;
     RECT  37.607 81.414 38.219 81.432 ;
     RECT  37.643 84.618 38.219 85.104 ;
     RECT  38.219 6.66 38.255 6.678 ;
     RECT  38.219 7.938 38.255 8.334 ;
     RECT  38.219 17.856 38.255 19.026 ;
     RECT  38.219 22.212 38.255 24.498 ;
     RECT  38.219 27.486 38.255 28.782 ;
     RECT  38.219 33.156 38.255 33.444 ;
     RECT  38.219 38.556 38.255 38.7 ;
     RECT  38.183 43.11 38.255 45.324 ;
     RECT  38.219 49.626 38.255 50.004 ;
     RECT  38.219 50.94 38.255 50.958 ;
     RECT  38.219 53.406 38.255 55.548 ;
     RECT  38.219 57.276 38.255 57.294 ;
     RECT  38.219 64.836 38.255 66.546 ;
     RECT  38.219 68.958 38.255 70.524 ;
     RECT  38.219 79.254 38.255 80.154 ;
     RECT  38.219 84.618 38.255 85.014 ;
     RECT  38.219 25.524 38.291 26.046 ;
     RECT  38.255 38.556 38.291 38.574 ;
     RECT  37.643 75.474 38.291 76.068 ;
     RECT  38.219 58.194 38.327 59.256 ;
     RECT  38.291 75.591 38.327 76.068 ;
     RECT  38.291 25.596 38.363 26.01 ;
     RECT  37.607 4.428 38.579 5.256 ;
     RECT  37.499 78.138 38.579 78.264 ;
     RECT  38.219 12.87 38.651 13.086 ;
     RECT  38.219 61.866 38.651 62.964 ;
     RECT  37.607 90.018 38.687 90.576 ;
     RECT  38.219 2.034 38.723 3.096 ;
     RECT  38.579 4.428 38.723 4.716 ;
     RECT  38.255 7.938 38.723 7.956 ;
     RECT  38.219 15.768 38.723 17.1 ;
     RECT  38.219 20.088 38.723 20.646 ;
     RECT  38.255 23.328 38.723 24.156 ;
     RECT  38.363 25.758 38.723 26.01 ;
     RECT  38.219 30.888 38.723 30.906 ;
     RECT  38.255 45.036 38.723 45.324 ;
     RECT  38.219 46.08 38.723 46.674 ;
     RECT  38.255 49.788 38.723 50.004 ;
     RECT  38.255 53.406 38.723 54.864 ;
     RECT  37.643 82.494 38.723 83.79 ;
     RECT  37.571 86.508 38.723 86.526 ;
     RECT  38.687 90.018 38.723 90.036 ;
     RECT  38.723 2.034 38.759 2.25 ;
     RECT  38.723 3.078 38.759 3.096 ;
     RECT  38.219 11.106 38.759 11.466 ;
     RECT  38.723 15.768 38.759 16.596 ;
     RECT  38.255 18.432 38.759 19.026 ;
     RECT  38.723 23.328 38.759 23.886 ;
     RECT  38.219 36.018 38.759 36.306 ;
     RECT  38.219 37.17 38.759 37.224 ;
     RECT  38.219 40.644 38.759 42.282 ;
     RECT  38.255 43.11 38.759 43.128 ;
     RECT  38.723 53.406 38.759 54.126 ;
     RECT  38.651 62.208 38.759 62.964 ;
     RECT  38.327 76.05 38.759 76.068 ;
     RECT  38.723 82.494 38.759 82.71 ;
     RECT  38.723 83.502 38.759 83.79 ;
     RECT  37.571 87.552 38.759 89.19 ;
     RECT  38.759 2.106 38.795 2.25 ;
     RECT  37.607 9.666 38.795 9.684 ;
     RECT  38.759 11.448 38.795 11.466 ;
     RECT  38.651 12.87 38.795 12.888 ;
     RECT  38.759 15.768 38.795 16.362 ;
     RECT  38.759 18.432 38.795 18.45 ;
     RECT  38.723 20.628 38.795 20.646 ;
     RECT  38.759 23.598 38.795 23.886 ;
     RECT  38.255 27.486 38.795 28.206 ;
     RECT  38.255 33.426 38.795 33.444 ;
     RECT  38.219 35.01 38.795 35.028 ;
     RECT  38.759 36.018 38.795 36.036 ;
     RECT  38.759 37.206 38.795 37.224 ;
     RECT  38.219 39.726 38.795 39.744 ;
     RECT  38.759 40.644 38.795 42.012 ;
     RECT  38.723 45.036 38.795 45.054 ;
     RECT  38.723 46.08 38.795 46.098 ;
     RECT  38.723 49.986 38.795 50.004 ;
     RECT  38.759 54.108 38.795 54.126 ;
     RECT  38.327 59.238 38.795 59.256 ;
     RECT  38.759 62.208 38.795 62.226 ;
     RECT  38.255 65.25 38.795 66.546 ;
     RECT  38.219 68.184 38.795 68.202 ;
     RECT  38.255 68.958 38.795 68.976 ;
     RECT  38.255 70.308 38.795 70.524 ;
     RECT  38.219 71.856 38.795 72.684 ;
     RECT  38.219 73.926 38.795 73.944 ;
     RECT  37.499 77.094 38.795 77.112 ;
     RECT  38.579 78.246 38.795 78.264 ;
     RECT  38.255 79.29 38.795 80.154 ;
     RECT  38.759 82.494 38.795 82.512 ;
     RECT  38.759 83.502 38.795 83.52 ;
     RECT  38.255 84.618 38.795 84.744 ;
     RECT  38.759 87.552 38.795 87.57 ;
     RECT  38.759 88.326 38.795 88.992 ;
     RECT  38.795 2.232 38.867 2.25 ;
     RECT  38.723 4.428 38.867 4.446 ;
     RECT  38.723 25.992 38.867 26.01 ;
     RECT  38.795 28.188 38.867 28.206 ;
     RECT  38.795 40.644 38.867 40.662 ;
     RECT  38.255 43.92 38.867 43.938 ;
     RECT  38.327 58.23 38.867 58.248 ;
     RECT  38.767 61.092 38.867 61.11 ;
     RECT  38.795 70.506 38.867 70.524 ;
     RECT  38.795 72.504 38.867 72.522 ;
    LAYER M3 ;
     RECT  2.304 1.051 2.322 1.387 ;
     RECT  1.728 1.387 2.322 1.531 ;
     RECT  1.728 1.531 2.358 1.723 ;
     RECT  17.1 1.759 17.118 1.831 ;
     RECT  4.32 1.243 4.338 1.867 ;
     RECT  38.772 1.387 38.79 1.867 ;
     RECT  16.164 1.831 16.182 1.876 ;
     RECT  17.1 1.831 18.414 1.876 ;
     RECT  24.66 1.243 24.678 1.876 ;
     RECT  4.32 1.867 4.662 1.921 ;
     RECT  16.164 1.876 18.414 1.921 ;
     RECT  20.916 1.759 20.934 1.921 ;
     RECT  1.728 1.723 2.754 1.957 ;
     RECT  3.6 1.921 5.346 1.957 ;
     RECT  9.36 1.876 9.378 1.957 ;
     RECT  36.18 1.876 36.198 1.957 ;
     RECT  1.728 1.957 5.346 1.993 ;
     RECT  16.164 1.921 18.99 1.993 ;
     RECT  20.592 1.921 21.114 1.993 ;
     RECT  37.548 1.531 37.566 2.011 ;
     RECT  7.056 1.876 7.074 2.029 ;
     RECT  9.288 1.957 9.378 2.029 ;
     RECT  10.296 1.723 10.314 2.029 ;
     RECT  14.292 1.921 14.922 2.029 ;
     RECT  15.66 1.993 18.99 2.029 ;
     RECT  20.016 1.993 21.114 2.029 ;
     RECT  35.136 1.831 35.154 2.029 ;
     RECT  6.804 2.029 7.074 2.065 ;
     RECT  15.66 2.029 21.654 2.065 ;
     RECT  22.5 1.921 22.518 2.065 ;
     RECT  30.492 1.051 30.51 2.065 ;
     RECT  6.696 2.065 7.074 2.101 ;
     RECT  8.208 2.029 8.226 2.101 ;
     RECT  9.108 2.029 10.314 2.101 ;
     RECT  14.112 2.029 14.922 2.101 ;
     RECT  15.66 2.065 22.518 2.101 ;
     RECT  24.66 1.876 24.786 2.101 ;
     RECT  35.028 2.029 35.154 2.101 ;
     RECT  35.892 1.957 36.198 2.101 ;
     RECT  1.728 1.993 5.922 2.129 ;
     RECT  6.696 2.101 7.146 2.143 ;
     RECT  8.136 2.101 10.926 2.143 ;
     RECT  23.364 1.957 23.382 2.143 ;
     RECT  24.408 2.101 25.038 2.143 ;
     RECT  26.532 2.101 26.55 2.143 ;
     RECT  27.468 2.101 27.486 2.143 ;
     RECT  28.908 2.029 28.926 2.143 ;
     RECT  34.2 1.876 34.218 2.143 ;
     RECT  35.028 2.101 36.198 2.143 ;
     RECT  6.696 2.143 10.926 2.191 ;
     RECT  11.916 2.065 11.934 2.191 ;
     RECT  13.176 2.101 22.518 2.191 ;
     RECT  23.364 2.143 25.038 2.191 ;
     RECT  26.532 2.143 27.486 2.191 ;
     RECT  30.492 2.065 30.618 2.191 ;
     RECT  32.115 2.143 32.205 2.191 ;
     RECT  33.084 1.957 33.102 2.191 ;
     RECT  34.2 2.143 36.198 2.191 ;
     RECT  32.115 2.191 36.198 2.219 ;
     RECT  6.696 2.191 11.934 2.227 ;
     RECT  38.736 1.867 38.79 2.227 ;
     RECT  2.268 2.129 5.922 2.237 ;
     RECT  30.492 2.191 30.798 2.263 ;
     RECT  32.115 2.219 36.09 2.263 ;
     RECT  28.908 2.143 29.505 2.299 ;
     RECT  30.492 2.263 36.09 2.299 ;
     RECT  6.696 2.227 12.258 2.371 ;
     RECT  13.032 2.191 27.882 2.371 ;
     RECT  2.304 2.237 5.922 2.461 ;
     RECT  6.696 2.371 27.882 2.461 ;
     RECT  37.548 2.011 37.602 2.491 ;
     RECT  2.304 2.461 28.062 2.533 ;
     RECT  28.908 2.299 36.09 2.533 ;
     RECT  36.972 2.491 37.602 2.561 ;
     RECT  38.736 2.227 38.862 2.641 ;
     RECT  0.144 2.683 0.162 2.813 ;
     RECT  2.304 2.533 36.09 2.861 ;
     RECT  37.584 2.561 37.602 2.861 ;
     RECT  2.304 2.861 35.982 3.029 ;
     RECT  38.7 2.641 38.862 3.145 ;
     RECT  38.196 3.145 38.862 3.197 ;
     RECT  2.415 3.029 35.982 3.299 ;
     RECT  0.324 3.163 0.342 3.341 ;
     RECT  37.008 3.307 37.026 3.371 ;
     RECT  38.736 3.197 38.862 3.485 ;
     RECT  2.415 3.299 35.946 3.787 ;
     RECT  2.304 3.787 35.946 3.839 ;
     RECT  2.304 3.839 35.478 3.875 ;
     RECT  37.44 3.787 37.602 4.117 ;
     RECT  37.008 4.117 37.602 4.123 ;
     RECT  36.936 4.123 37.602 4.181 ;
     RECT  37.008 4.181 37.602 4.253 ;
     RECT  38.844 3.485 38.862 4.451 ;
     RECT  37.44 4.253 37.602 4.523 ;
     RECT  0.54 4.423 0.558 4.637 ;
     RECT  2.304 3.875 35.442 4.693 ;
     RECT  36.216 4.261 36.234 4.693 ;
     RECT  37.476 4.523 37.602 4.747 ;
     RECT  38.7 4.603 38.718 4.747 ;
     RECT  37.476 4.747 38.718 4.793 ;
     RECT  2.304 4.693 36.234 4.919 ;
     RECT  2.304 4.919 6.966 4.955 ;
     RECT  7.704 4.919 36.234 5.021 ;
     RECT  37.548 4.793 38.718 5.069 ;
     RECT  2.304 4.955 6.894 5.083 ;
     RECT  1.98 5.083 6.894 5.213 ;
     RECT  37.548 5.069 38.574 5.261 ;
     RECT  0.144 5.419 0.162 5.549 ;
     RECT  2.268 5.213 6.894 5.701 ;
     RECT  7.704 5.021 35.55 5.701 ;
     RECT  2.268 5.701 35.55 5.755 ;
     RECT  2.268 5.755 35.658 5.803 ;
     RECT  2.268 5.803 35.91 5.999 ;
     RECT  37.548 5.261 38.214 6.043 ;
     RECT  2.304 5.999 35.91 6.091 ;
     RECT  37.548 6.043 38.25 6.283 ;
     RECT  37.548 6.283 38.718 6.379 ;
     RECT  37.008 6.379 38.718 6.449 ;
     RECT  2.304 6.091 36.198 6.547 ;
     RECT  37.548 6.449 38.718 6.683 ;
     RECT  0.54 6.781 0.558 6.893 ;
     RECT  2.304 6.547 36.522 7.483 ;
     RECT  37.548 6.683 37.602 7.483 ;
     RECT  2.304 7.483 37.602 7.709 ;
     RECT  0.108 7.627 0.126 7.757 ;
     RECT  36.324 7.709 37.602 7.771 ;
     RECT  38.7 6.683 38.718 7.771 ;
     RECT  0.144 8.011 0.162 8.141 ;
     RECT  36.324 7.771 38.718 8.429 ;
     RECT  2.304 7.709 35.478 8.537 ;
     RECT  37.008 8.429 38.718 8.537 ;
     RECT  3.6 8.537 35.478 8.539 ;
     RECT  37.548 8.537 38.718 8.843 ;
     RECT  2.304 8.537 2.862 9.115 ;
     RECT  2.232 9.115 2.862 9.239 ;
     RECT  2.304 9.239 2.862 9.319 ;
     RECT  3.6 8.539 36.198 9.319 ;
     RECT  2.304 9.319 36.198 9.391 ;
     RECT  38.628 8.843 38.718 9.595 ;
     RECT  2.304 9.391 36.486 9.625 ;
     RECT  38.628 9.595 38.79 9.689 ;
     RECT  2.304 9.625 36.594 9.739 ;
     RECT  37.548 8.843 37.602 9.739 ;
     RECT  2.304 9.739 37.602 9.923 ;
     RECT  2.304 9.923 36.594 10.219 ;
     RECT  38.628 9.689 38.718 10.253 ;
     RECT  1.98 10.219 36.594 10.349 ;
     RECT  38.7 10.253 38.718 10.555 ;
     RECT  2.304 10.349 36.594 10.859 ;
     RECT  37.584 9.923 37.602 11.173 ;
     RECT  38.7 10.555 38.79 11.173 ;
     RECT  0.144 11.227 0.162 11.357 ;
     RECT  2.304 10.859 36.522 11.399 ;
     RECT  37.584 11.173 38.79 11.543 ;
     RECT  2.304 11.399 35.946 11.789 ;
     RECT  0.54 11.911 0.558 12.029 ;
     RECT  38.196 11.543 38.79 12.173 ;
     RECT  37.008 11.659 37.026 12.475 ;
     RECT  2.304 11.789 35.802 12.479 ;
     RECT  2.304 12.479 35.766 12.749 ;
     RECT  38.628 12.173 38.79 12.893 ;
     RECT  37.008 12.475 37.602 13.055 ;
     RECT  37.368 13.055 37.602 13.09 ;
     RECT  38.628 12.893 38.646 13.09 ;
     RECT  37.368 13.09 38.646 13.091 ;
     RECT  0.144 13.339 0.162 13.387 ;
     RECT  37.368 13.091 38.214 13.469 ;
     RECT  2.304 12.749 3.69 13.531 ;
     RECT  4.572 12.749 35.766 13.531 ;
     RECT  0.144 13.387 0.234 13.613 ;
     RECT  2.304 13.531 35.766 13.703 ;
     RECT  6.372 13.703 35.766 13.711 ;
     RECT  6.372 13.711 36.126 13.915 ;
     RECT  6.372 13.915 36.198 14.099 ;
     RECT  38.772 13.915 38.79 14.189 ;
     RECT  0.108 14.071 0.126 14.285 ;
     RECT  2.304 13.703 5.634 14.369 ;
     RECT  4.968 14.369 5.634 14.443 ;
     RECT  6.372 14.099 35.694 14.443 ;
     RECT  4.968 14.443 35.694 14.639 ;
     RECT  37.548 13.469 37.602 14.755 ;
     RECT  4.968 14.639 5.634 14.909 ;
     RECT  37.548 14.755 37.674 14.909 ;
     RECT  6.372 14.639 35.694 14.957 ;
     RECT  38.7 14.683 38.718 15.019 ;
     RECT  4.968 14.909 5.526 15.151 ;
     RECT  4.896 15.151 5.526 15.187 ;
     RECT  2.304 14.369 4.086 15.223 ;
     RECT  4.86 15.187 5.526 15.223 ;
     RECT  0.144 15.259 0.162 15.389 ;
     RECT  37.548 14.909 37.566 15.485 ;
     RECT  36.324 15.331 36.342 15.493 ;
     RECT  36.324 15.493 37.062 15.557 ;
     RECT  2.304 15.223 5.526 15.691 ;
     RECT  6.372 14.957 35.55 15.691 ;
     RECT  2.304 15.691 35.55 15.773 ;
     RECT  2.304 15.773 35.442 16.205 ;
     RECT  37.044 15.557 37.062 16.205 ;
     RECT  38.7 15.019 38.79 16.363 ;
     RECT  38.628 16.363 38.79 16.493 ;
     RECT  2.412 16.205 35.442 16.681 ;
     RECT  0.54 16.411 0.558 16.771 ;
     RECT  0.108 16.771 0.558 16.829 ;
     RECT  2.412 16.681 37.026 17.077 ;
     RECT  2.412 17.077 37.062 17.117 ;
     RECT  0.108 16.829 0.126 17.165 ;
     RECT  2.412 17.117 36.594 17.275 ;
     RECT  2.304 17.275 36.594 17.339 ;
     RECT  37.548 17.419 37.566 17.681 ;
     RECT  38.7 16.493 38.79 17.725 ;
     RECT  2.415 17.339 36.594 18.091 ;
     RECT  2.412 18.091 36.594 18.149 ;
     RECT  2.412 18.149 35.874 18.173 ;
     RECT  2.412 18.173 35.802 18.185 ;
     RECT  0.54 17.581 0.558 18.269 ;
     RECT  2.412 18.185 35.442 18.391 ;
     RECT  38.196 17.725 38.79 18.455 ;
     RECT  38.196 18.455 38.754 18.523 ;
     RECT  37.008 18.427 37.026 18.563 ;
     RECT  38.124 18.523 38.754 18.797 ;
     RECT  2.304 18.391 35.442 19.111 ;
     RECT  38.7 18.797 38.754 19.531 ;
     RECT  37.548 18.907 37.602 19.571 ;
     RECT  37.548 19.571 37.566 19.841 ;
     RECT  2.304 19.111 35.982 19.921 ;
     RECT  0.144 20.011 0.162 20.155 ;
     RECT  2.304 19.921 36.09 20.155 ;
     RECT  2.304 20.155 36.522 20.183 ;
     RECT  2.304 20.183 35.406 20.219 ;
     RECT  0.144 20.155 0.234 20.333 ;
     RECT  38.7 19.531 38.79 20.344 ;
     RECT  38.628 20.344 38.79 20.347 ;
     RECT  36.504 20.183 36.522 20.453 ;
     RECT  38.448 20.347 38.79 20.461 ;
     RECT  0.144 20.333 0.162 20.525 ;
     RECT  38.232 20.461 38.79 20.635 ;
     RECT  38.196 20.635 38.79 20.651 ;
     RECT  36.972 20.827 36.99 20.921 ;
     RECT  2.304 20.219 35.37 21.001 ;
     RECT  37.008 20.971 37.026 21.149 ;
     RECT  38.196 20.651 38.718 21.149 ;
     RECT  2.304 21.001 35.766 21.271 ;
     RECT  38.7 21.149 38.718 21.691 ;
     RECT  2.304 21.271 35.946 21.731 ;
     RECT  38.7 21.691 38.79 21.821 ;
     RECT  37.512 21.307 37.602 21.931 ;
     RECT  37.368 21.931 37.602 22.001 ;
     RECT  37.368 22.001 37.386 22.073 ;
     RECT  38.7 21.821 38.718 22.075 ;
     RECT  2.304 21.731 35.766 22.469 ;
     RECT  0.54 22.081 0.558 22.507 ;
     RECT  38.196 22.075 38.718 22.747 ;
     RECT  2.304 22.469 35.097 22.775 ;
     RECT  36.504 22.081 36.522 22.883 ;
     RECT  0.108 22.507 0.558 23.405 ;
     RECT  2.412 22.775 35.097 23.701 ;
     RECT  38.196 22.747 38.79 23.891 ;
     RECT  2.304 23.701 35.154 23.971 ;
     RECT  2.304 23.971 35.766 24.089 ;
     RECT  0.54 23.405 0.558 24.221 ;
     RECT  2.304 24.089 35.694 24.503 ;
     RECT  0.144 24.523 0.162 24.653 ;
     RECT  38.196 23.891 38.718 24.667 ;
     RECT  36.972 24.523 36.99 24.701 ;
     RECT  38.124 24.667 38.718 24.907 ;
     RECT  38.016 24.907 38.718 25.037 ;
     RECT  2.304 24.503 2.697 25.079 ;
     RECT  2.415 25.079 2.697 25.249 ;
     RECT  3.42 24.503 35.694 25.249 ;
     RECT  38.088 25.037 38.718 25.517 ;
     RECT  2.415 25.249 35.694 25.889 ;
     RECT  38.196 25.517 38.718 25.963 ;
     RECT  38.196 25.963 38.79 25.987 ;
     RECT  0.144 25.531 0.162 26.093 ;
     RECT  38.196 25.987 38.862 26.141 ;
     RECT  2.415 25.889 35.622 26.221 ;
     RECT  38.34 26.141 38.862 26.285 ;
     RECT  37.008 26.365 37.026 26.587 ;
     RECT  2.304 26.221 35.622 26.761 ;
     RECT  38.7 26.285 38.862 26.765 ;
     RECT  2.304 26.761 35.874 26.905 ;
     RECT  2.304 26.905 36.054 26.941 ;
     RECT  2.304 26.941 36.126 27.197 ;
     RECT  37.008 26.587 37.602 27.239 ;
     RECT  38.772 26.765 38.862 27.547 ;
     RECT  37.044 27.239 37.602 27.773 ;
     RECT  37.548 27.773 37.602 27.941 ;
     RECT  38.7 27.547 38.862 28.021 ;
     RECT  38.196 28.021 38.862 28.211 ;
     RECT  2.304 27.197 36.018 28.319 ;
     RECT  2.412 28.319 36.018 28.409 ;
     RECT  2.412 28.409 3.078 28.445 ;
     RECT  2.412 28.445 3.006 28.589 ;
     RECT  3.996 28.409 36.018 28.651 ;
     RECT  2.412 28.589 2.898 28.679 ;
     RECT  38.196 28.211 38.718 28.877 ;
     RECT  2.412 28.679 2.79 28.949 ;
     RECT  3.996 28.651 36.126 28.949 ;
     RECT  4.032 28.949 36.126 29.101 ;
     RECT  2.412 28.949 2.754 29.179 ;
     RECT  4.032 29.101 36.522 29.213 ;
     RECT  2.304 29.179 2.754 29.219 ;
     RECT  4.032 29.213 36.09 29.219 ;
     RECT  0.108 28.381 0.126 29.357 ;
     RECT  38.232 28.877 38.718 29.659 ;
     RECT  2.415 29.219 2.754 29.731 ;
     RECT  0.144 29.659 0.162 29.789 ;
     RECT  38.196 29.659 38.718 29.803 ;
     RECT  2.415 29.731 2.826 30.139 ;
     RECT  2.304 30.139 2.826 30.145 ;
     RECT  37.476 29.803 38.718 30.173 ;
     RECT  4.104 29.219 36.09 30.181 ;
     RECT  2.304 30.145 3.15 30.317 ;
     RECT  2.415 30.317 3.15 30.451 ;
     RECT  3.924 30.181 36.09 30.451 ;
     RECT  38.556 30.173 38.718 30.523 ;
     RECT  37.476 30.173 37.602 30.557 ;
     RECT  2.415 30.451 36.09 30.619 ;
     RECT  0.108 30.721 0.126 30.797 ;
     RECT  38.556 30.523 38.79 30.797 ;
     RECT  2.415 30.619 36.306 30.955 ;
     RECT  37.584 30.557 37.602 30.991 ;
     RECT  38.556 30.797 38.718 30.991 ;
     RECT  2.415 30.955 36.378 31.081 ;
     RECT  2.304 31.081 36.378 31.451 ;
     RECT  0.504 31.729 0.522 31.801 ;
     RECT  0.504 31.801 0.558 31.949 ;
     RECT  0.504 31.949 0.522 32.093 ;
     RECT  37.584 30.991 38.718 32.237 ;
     RECT  38.7 32.237 38.718 32.285 ;
     RECT  2.304 31.451 35.982 32.341 ;
     RECT  2.304 32.341 36.522 32.467 ;
     RECT  0.108 32.161 0.126 32.573 ;
     RECT  2.304 32.467 36.594 32.603 ;
     RECT  3.816 32.603 36.594 32.729 ;
     RECT  3.816 32.729 36.522 32.765 ;
     RECT  37.548 32.395 37.566 33.019 ;
     RECT  37.548 33.019 38.214 33.071 ;
     RECT  38.196 33.071 38.214 33.151 ;
     RECT  38.196 33.151 38.25 33.355 ;
     RECT  2.304 32.603 2.97 33.421 ;
     RECT  3.816 32.765 36.342 33.421 ;
     RECT  38.196 33.355 38.79 33.449 ;
     RECT  2.304 33.421 36.342 33.643 ;
     RECT  38.196 33.449 38.214 34.315 ;
     RECT  2.304 33.643 36.522 34.349 ;
     RECT  3.996 34.349 36.522 34.655 ;
     RECT  3.996 34.655 36.234 34.727 ;
     RECT  3.996 34.727 35.946 35.131 ;
     RECT  2.304 34.349 3.15 35.401 ;
     RECT  3.888 35.131 35.946 35.401 ;
     RECT  2.304 35.401 35.946 35.545 ;
     RECT  2.304 35.545 36.054 35.597 ;
     RECT  2.376 35.597 36.054 35.699 ;
     RECT  2.415 35.699 36.054 35.851 ;
     RECT  0.108 35.995 0.126 36.013 ;
     RECT  38.196 34.315 38.79 36.041 ;
     RECT  2.415 35.851 36.594 36.113 ;
     RECT  0.108 36.013 0.558 36.125 ;
     RECT  2.415 36.113 36.522 36.149 ;
     RECT  38.196 36.041 38.754 36.311 ;
     RECT  36.504 36.149 36.522 36.347 ;
     RECT  2.415 36.149 35.694 36.571 ;
     RECT  0.54 36.125 0.558 36.749 ;
     RECT  38.196 36.311 38.718 37.051 ;
     RECT  38.196 37.051 38.79 37.157 ;
     RECT  2.304 36.571 35.694 37.471 ;
     RECT  0.108 37.435 0.126 37.561 ;
     RECT  0.108 37.561 0.558 37.565 ;
     RECT  2.304 37.471 36.198 37.589 ;
     RECT  0.54 37.565 0.558 37.709 ;
     RECT  2.304 37.589 35.946 37.859 ;
     RECT  2.304 37.859 35.91 38.101 ;
     RECT  2.232 38.101 35.91 38.189 ;
     RECT  2.304 38.189 35.91 38.201 ;
     RECT  37.584 37.531 37.602 38.201 ;
     RECT  38.592 37.157 38.79 38.245 ;
     RECT  3.78 38.201 35.91 38.309 ;
     RECT  38.196 38.245 38.79 38.525 ;
     RECT  2.304 38.201 3.042 39.091 ;
     RECT  3.78 38.309 35.802 39.091 ;
     RECT  2.304 39.091 36.234 39.181 ;
     RECT  0.144 39.115 0.162 39.245 ;
     RECT  37.404 39.451 37.422 39.623 ;
     RECT  38.196 38.525 38.718 39.721 ;
     RECT  2.304 39.181 36.306 39.865 ;
     RECT  2.304 39.865 36.594 40.289 ;
     RECT  38.196 39.721 38.79 40.639 ;
     RECT  38.196 40.639 38.862 40.711 ;
     RECT  37.548 40.711 38.862 40.781 ;
     RECT  2.376 40.289 36.594 40.901 ;
     RECT  2.376 40.901 36.522 41.035 ;
     RECT  2.304 41.035 36.522 41.405 ;
     RECT  0.144 41.419 0.162 41.549 ;
     RECT  37.584 40.781 38.862 41.741 ;
     RECT  37.584 41.741 37.602 41.783 ;
     RECT  2.304 41.405 36.342 41.819 ;
     RECT  38.628 41.741 38.862 42.365 ;
     RECT  2.304 41.819 35.73 42.667 ;
     RECT  36.504 42.601 36.522 42.667 ;
     RECT  0.54 42.601 0.558 42.845 ;
     RECT  2.304 42.667 36.522 43.003 ;
     RECT  1.98 43.003 36.522 43.069 ;
     RECT  1.98 43.069 37.062 43.181 ;
     RECT  2.304 43.181 37.062 43.325 ;
     RECT  2.304 43.325 36.522 43.331 ;
     RECT  38.664 42.365 38.862 43.339 ;
     RECT  38.232 43.339 38.862 43.411 ;
     RECT  0.108 43.435 0.126 43.565 ;
     RECT  37.368 43.435 37.386 43.565 ;
     RECT  2.304 43.331 36.378 43.799 ;
     RECT  38.196 43.411 38.862 43.943 ;
     RECT  0.54 43.807 0.558 43.949 ;
     RECT  38.196 43.943 38.79 43.952 ;
     RECT  2.304 43.799 36.27 44.375 ;
     RECT  38.196 43.952 38.25 44.587 ;
     RECT  2.304 44.375 35.946 44.789 ;
     RECT  37.584 44.587 38.25 44.957 ;
     RECT  38.592 45.031 38.79 45.101 ;
     RECT  2.304 44.789 35.91 45.805 ;
     RECT  2.304 45.805 36.27 45.841 ;
     RECT  37.584 44.957 37.602 45.883 ;
     RECT  37.548 45.883 37.602 45.931 ;
     RECT  38.592 45.101 38.718 45.931 ;
     RECT  37.548 45.931 38.718 46.027 ;
     RECT  37.548 46.027 38.79 46.031 ;
     RECT  37.62 46.031 38.79 46.103 ;
     RECT  2.304 45.841 36.45 46.139 ;
     RECT  0.108 46.267 0.126 46.397 ;
     RECT  0.144 46.411 0.198 46.541 ;
     RECT  37.62 46.103 38.718 46.688 ;
     RECT  37.62 46.688 38.214 46.877 ;
     RECT  37.62 46.877 37.638 46.987 ;
     RECT  0.144 46.541 0.162 47.021 ;
     RECT  37.584 46.987 37.638 47.119 ;
     RECT  37.548 47.119 37.638 47.165 ;
     RECT  37.584 47.165 37.638 47.695 ;
     RECT  38.7 47.659 38.718 47.695 ;
     RECT  2.304 46.139 36.27 47.965 ;
     RECT  0.54 47.281 0.558 47.981 ;
     RECT  2.304 47.965 36.378 48.283 ;
     RECT  37.584 47.695 38.718 48.461 ;
     RECT  1.98 48.283 36.378 48.509 ;
     RECT  2.304 48.509 36.378 48.811 ;
     RECT  2.304 48.811 36.522 49.045 ;
     RECT  37.512 49.051 37.53 49.343 ;
     RECT  2.304 49.045 36.594 49.469 ;
     RECT  38.52 48.461 38.718 49.549 ;
     RECT  2.304 49.469 36.558 49.739 ;
     RECT  38.196 49.549 38.718 49.867 ;
     RECT  2.304 49.739 36.522 49.919 ;
     RECT  38.196 49.867 38.79 50.009 ;
     RECT  38.196 50.009 38.718 50.093 ;
     RECT  0.144 50.203 0.162 50.333 ;
     RECT  37.584 50.203 37.602 50.347 ;
     RECT  2.415 49.919 36.522 50.459 ;
     RECT  38.628 50.093 38.718 50.573 ;
     RECT  37.548 50.347 37.602 50.621 ;
     RECT  2.415 50.459 35.478 50.683 ;
     RECT  37.008 50.827 37.026 50.891 ;
     RECT  38.628 50.573 38.646 50.935 ;
     RECT  2.304 50.683 35.478 51.307 ;
     RECT  38.196 50.935 38.646 51.307 ;
     RECT  38.196 51.307 38.718 51.403 ;
     RECT  2.268 51.307 35.478 51.431 ;
     RECT  2.304 51.431 35.478 51.601 ;
     RECT  38.196 51.403 38.79 51.643 ;
     RECT  37.476 51.643 38.79 51.773 ;
     RECT  0.144 51.691 0.162 51.821 ;
     RECT  37.512 51.773 38.79 51.821 ;
     RECT  2.304 51.601 35.514 51.931 ;
     RECT  2.304 51.931 35.622 52.205 ;
     RECT  36.576 52.051 36.594 52.241 ;
     RECT  2.34 52.205 35.622 52.285 ;
     RECT  2.34 52.285 35.694 52.321 ;
     RECT  2.34 52.321 35.766 52.411 ;
     RECT  0.108 52.411 0.126 52.493 ;
     RECT  37.512 51.821 38.718 52.583 ;
     RECT  2.34 52.411 35.838 52.591 ;
     RECT  2.34 52.591 36.342 52.939 ;
     RECT  0.144 52.555 0.162 53.227 ;
     RECT  37.584 52.583 38.718 53.227 ;
     RECT  2.304 52.939 36.342 53.249 ;
     RECT  0.108 53.227 0.162 53.275 ;
     RECT  37.584 53.227 38.79 53.321 ;
     RECT  0.108 53.275 0.198 53.453 ;
     RECT  0.108 53.453 0.126 53.597 ;
     RECT  38.052 53.321 38.79 53.741 ;
     RECT  2.304 53.249 36.234 53.869 ;
     RECT  2.268 53.869 36.234 54.077 ;
     RECT  38.736 53.741 38.79 54.131 ;
     RECT  38.736 54.131 38.754 54.269 ;
     RECT  2.304 54.077 36.234 54.445 ;
     RECT  38.196 54.481 38.718 54.557 ;
     RECT  0.108 54.523 0.126 54.653 ;
     RECT  2.304 54.445 36.522 54.715 ;
     RECT  2.304 54.715 37.026 54.859 ;
     RECT  2.304 54.859 37.638 54.941 ;
     RECT  36.504 54.941 37.638 55.247 ;
     RECT  37.008 55.247 37.638 55.373 ;
     RECT  0.144 55.339 0.162 55.469 ;
     RECT  38.592 54.557 38.718 55.525 ;
     RECT  2.304 54.941 35.766 55.679 ;
     RECT  37.008 55.373 37.026 55.751 ;
     RECT  6.912 55.679 35.766 55.831 ;
     RECT  38.196 55.525 38.718 55.997 ;
     RECT  6.912 55.831 35.946 56.101 ;
     RECT  37.548 56.155 37.566 56.291 ;
     RECT  2.304 55.679 6.03 56.443 ;
     RECT  6.912 56.101 36.522 56.443 ;
     RECT  2.304 56.443 36.522 56.525 ;
     RECT  38.7 55.997 38.718 56.621 ;
     RECT  0.108 56.539 0.126 56.669 ;
     RECT  37.44 56.635 37.458 56.779 ;
     RECT  37.404 56.779 37.458 56.875 ;
     RECT  37.368 56.875 37.458 56.984 ;
     RECT  2.304 56.525 36.45 57.065 ;
     RECT  2.304 57.065 36.054 57.101 ;
     RECT  38.196 57.181 38.25 57.403 ;
     RECT  37.548 57.403 38.25 57.641 ;
     RECT  38.232 57.641 38.25 57.739 ;
     RECT  2.304 57.101 35.946 57.883 ;
     RECT  38.232 57.739 38.718 58.075 ;
     RECT  0.54 57.919 0.558 58.081 ;
     RECT  38.232 58.075 38.79 58.225 ;
     RECT  0.108 58.081 0.558 58.253 ;
     RECT  38.232 58.225 38.862 58.531 ;
     RECT  2.304 57.883 36.558 58.649 ;
     RECT  0.108 58.253 0.126 58.733 ;
     RECT  2.304 58.649 36.378 58.733 ;
     RECT  37.584 58.531 38.862 59.179 ;
     RECT  2.304 58.733 35.982 59.801 ;
     RECT  37.548 59.179 38.862 59.801 ;
     RECT  7.056 59.801 35.982 59.881 ;
     RECT  7.056 59.881 36.018 60.151 ;
     RECT  38.196 59.801 38.862 60.509 ;
     RECT  2.304 59.801 6.21 60.655 ;
     RECT  7.056 60.151 36.126 60.655 ;
     RECT  2.304 60.655 36.126 60.683 ;
     RECT  37.404 60.619 37.422 60.953 ;
     RECT  38.628 60.509 38.862 60.989 ;
     RECT  38.7 60.989 38.862 61.115 ;
     RECT  0.144 61.291 0.162 61.421 ;
     RECT  2.304 60.683 36.018 61.465 ;
     RECT  2.304 61.465 36.486 61.619 ;
     RECT  38.7 61.115 38.79 61.771 ;
     RECT  38.196 61.771 38.79 61.915 ;
     RECT  38.088 61.915 38.79 62.093 ;
     RECT  2.304 61.619 5.814 62.401 ;
     RECT  6.552 61.619 35.91 62.401 ;
     RECT  2.304 62.401 36.054 62.545 ;
     RECT  0.54 62.545 0.558 62.765 ;
     RECT  38.196 62.093 38.79 63.005 ;
     RECT  2.304 62.545 36.342 63.121 ;
     RECT  38.196 63.005 38.754 63.211 ;
     RECT  2.304 63.121 36.522 63.355 ;
     RECT  37.512 63.211 38.754 63.653 ;
     RECT  2.304 63.355 36.594 63.725 ;
     RECT  38.196 63.653 38.754 64.205 ;
     RECT  0.108 63.751 0.126 64.541 ;
     RECT  2.412 63.725 36.594 64.589 ;
     RECT  2.412 64.589 35.91 64.651 ;
     RECT  2.34 64.651 35.91 64.795 ;
     RECT  38.196 64.205 38.646 65.021 ;
     RECT  38.628 65.021 38.646 65.245 ;
     RECT  2.304 64.795 35.91 65.479 ;
     RECT  2.304 65.479 36.054 65.669 ;
     RECT  2.415 65.669 36.054 65.885 ;
     RECT  37.584 65.131 37.602 65.947 ;
     RECT  38.628 65.245 38.79 65.947 ;
     RECT  3.816 65.885 36.054 66.011 ;
     RECT  3.888 66.011 36.054 66.091 ;
     RECT  2.415 65.885 2.862 66.427 ;
     RECT  3.888 66.091 36.234 66.523 ;
     RECT  37.584 65.947 38.79 66.623 ;
     RECT  2.304 66.427 2.862 66.829 ;
     RECT  38.196 66.623 38.79 66.941 ;
     RECT  2.304 66.829 3.006 66.991 ;
     RECT  3.888 66.523 36.27 66.991 ;
     RECT  2.304 66.991 36.27 67.051 ;
     RECT  2.304 67.051 36.522 67.163 ;
     RECT  2.304 67.163 36.054 67.531 ;
     RECT  2.268 67.531 36.054 67.568 ;
     RECT  38.7 66.941 38.79 67.723 ;
     RECT  0.54 67.711 0.558 67.901 ;
     RECT  2.304 67.568 36.054 67.945 ;
     RECT  38.196 67.723 38.79 68.203 ;
     RECT  38.088 68.203 38.79 68.333 ;
     RECT  37.584 68.347 37.602 68.405 ;
     RECT  2.304 67.945 36.198 68.485 ;
     RECT  2.304 68.485 36.378 68.521 ;
     RECT  2.304 68.521 36.45 68.881 ;
     RECT  38.556 68.333 38.79 69.005 ;
     RECT  38.556 69.005 38.682 69.061 ;
     RECT  2.304 68.881 36.522 69.565 ;
     RECT  38.196 69.061 38.682 69.643 ;
     RECT  2.304 69.565 36.774 69.674 ;
     RECT  2.304 69.674 36.378 69.989 ;
     RECT  0.324 70.123 0.342 70.267 ;
     RECT  37.584 69.643 38.682 70.267 ;
     RECT  0.108 70.267 0.342 70.301 ;
     RECT  2.304 69.989 36.27 70.403 ;
     RECT  37.584 70.267 38.79 70.403 ;
     RECT  38.196 70.403 38.79 70.501 ;
     RECT  0.108 70.301 0.126 70.541 ;
     RECT  2.304 70.403 36.234 70.835 ;
     RECT  7.272 70.835 36.234 71.185 ;
     RECT  0.144 71.131 0.162 71.261 ;
     RECT  7.272 71.185 36.522 71.261 ;
     RECT  37.368 71.563 37.386 71.753 ;
     RECT  2.304 70.835 6.39 71.899 ;
     RECT  1.98 71.899 6.39 71.995 ;
     RECT  1.98 71.995 6.606 72.031 ;
     RECT  7.416 71.261 36.522 72.031 ;
     RECT  1.98 72.031 36.522 72.077 ;
     RECT  38.196 70.501 38.862 72.187 ;
     RECT  2.232 72.077 36.522 72.257 ;
     RECT  2.232 72.257 36.126 72.419 ;
     RECT  37.584 72.187 38.862 72.491 ;
     RECT  38.196 72.491 38.862 72.527 ;
     RECT  2.232 72.419 36.09 72.893 ;
     RECT  0.54 72.931 0.558 73.037 ;
     RECT  2.268 72.893 36.09 73.381 ;
     RECT  2.268 73.381 36.126 73.535 ;
     RECT  2.304 73.535 36.126 73.741 ;
     RECT  2.304 73.741 36.198 73.849 ;
     RECT  38.196 72.527 38.79 73.913 ;
     RECT  38.592 73.913 38.79 73.949 ;
     RECT  0.144 73.963 0.162 74.011 ;
     RECT  0.144 74.011 0.558 74.093 ;
     RECT  0.54 74.093 0.558 74.141 ;
     RECT  37.584 74.107 37.602 74.381 ;
     RECT  2.304 73.849 36.594 74.579 ;
     RECT  2.304 74.579 36.522 74.615 ;
     RECT  38.592 73.949 38.718 74.779 ;
     RECT  38.196 74.779 38.718 75.199 ;
     RECT  37.62 75.199 38.718 75.245 ;
     RECT  37.62 75.245 38.322 75.293 ;
     RECT  2.304 74.615 36.342 75.403 ;
     RECT  2.304 75.403 36.99 75.731 ;
     RECT  38.196 75.293 38.322 75.767 ;
     RECT  38.268 75.767 38.322 75.773 ;
     RECT  2.304 75.731 36.342 75.839 ;
     RECT  38.304 75.773 38.322 75.917 ;
     RECT  5.115 75.839 36.342 75.929 ;
     RECT  0.144 75.547 0.162 76.013 ;
     RECT  5.115 75.929 35.874 76.199 ;
     RECT  37.476 76.027 37.494 76.343 ;
     RECT  38.7 76.045 38.754 76.541 ;
     RECT  2.304 75.839 4.374 76.585 ;
     RECT  5.115 76.199 35.73 76.585 ;
     RECT  37.008 76.549 37.026 76.589 ;
     RECT  36.972 76.699 36.99 76.811 ;
     RECT  38.736 76.541 38.754 77.035 ;
     RECT  38.736 77.035 38.79 77.117 ;
     RECT  2.304 76.585 35.73 77.125 ;
     RECT  2.304 77.125 36.018 77.179 ;
     RECT  38.736 77.117 38.754 77.213 ;
     RECT  1.98 77.179 36.018 77.309 ;
     RECT  37.476 77.323 37.494 77.423 ;
     RECT  38.7 77.515 38.718 77.563 ;
     RECT  2.304 77.309 36.018 77.665 ;
     RECT  38.628 77.563 38.718 77.899 ;
     RECT  38.592 77.899 38.718 77.995 ;
     RECT  38.556 77.995 38.718 78.139 ;
     RECT  2.304 77.665 36.162 78.169 ;
     RECT  38.196 78.139 38.718 78.241 ;
     RECT  2.304 78.169 36.342 78.359 ;
     RECT  2.304 78.359 36.162 78.395 ;
     RECT  38.196 78.241 38.79 78.509 ;
     RECT  37.008 78.619 37.026 78.665 ;
     RECT  0.54 78.061 0.558 78.797 ;
     RECT  38.196 78.509 38.682 79.285 ;
     RECT  2.304 78.395 36.09 79.439 ;
     RECT  0.54 79.681 0.558 79.949 ;
     RECT  2.34 79.439 36.054 79.952 ;
     RECT  2.34 79.952 36.018 80.087 ;
     RECT  2.34 80.087 35.982 80.203 ;
     RECT  36.972 79.915 36.99 80.321 ;
     RECT  38.196 79.285 38.79 80.539 ;
     RECT  37.512 80.539 38.79 80.663 ;
     RECT  2.304 80.203 35.982 80.941 ;
     RECT  2.304 80.941 36.162 81.095 ;
     RECT  0.108 81.019 0.126 81.149 ;
     RECT  2.304 81.095 35.946 81.149 ;
     RECT  3.42 81.149 35.946 81.509 ;
     RECT  37.584 80.663 38.79 81.725 ;
     RECT  37.584 81.725 37.602 81.941 ;
     RECT  2.304 81.149 2.697 82.111 ;
     RECT  3.672 81.509 35.946 82.255 ;
     RECT  3.564 82.255 35.946 82.291 ;
     RECT  2.304 82.111 2.826 82.315 ;
     RECT  3.564 82.291 36.342 82.445 ;
     RECT  38.736 81.725 38.79 82.459 ;
     RECT  1.98 82.315 2.826 82.481 ;
     RECT  38.592 82.459 38.79 82.795 ;
     RECT  2.304 82.481 2.826 82.987 ;
     RECT  3.564 82.445 36.126 82.987 ;
     RECT  2.304 82.987 36.126 83.299 ;
     RECT  2.304 83.299 36.234 83.399 ;
     RECT  38.556 82.795 38.79 83.453 ;
     RECT  2.304 83.399 35.946 83.489 ;
     RECT  36.972 82.687 36.99 83.597 ;
     RECT  38.736 83.453 38.79 83.795 ;
     RECT  0.54 83.191 0.558 83.933 ;
     RECT  37.368 83.899 37.386 84.029 ;
     RECT  2.415 83.489 35.946 84.235 ;
     RECT  2.304 84.235 35.946 84.271 ;
     RECT  2.304 84.271 36.234 84.413 ;
     RECT  38.772 83.795 38.79 84.749 ;
     RECT  37.584 84.181 37.638 84.991 ;
     RECT  38.7 84.859 38.718 84.991 ;
     RECT  37.584 84.991 38.718 85.051 ;
     RECT  0.54 84.883 0.558 85.085 ;
     RECT  2.304 84.413 35.874 85.261 ;
     RECT  37.548 85.051 38.718 85.373 ;
     RECT  37.548 85.373 37.638 85.565 ;
     RECT  37.548 85.565 37.602 85.721 ;
     RECT  38.664 85.373 38.718 85.771 ;
     RECT  38.664 85.771 38.79 86.045 ;
     RECT  37.512 86.155 37.53 86.333 ;
     RECT  2.304 85.261 36.414 86.347 ;
     RECT  38.7 86.045 38.718 86.531 ;
     RECT  2.304 86.347 36.522 86.603 ;
     RECT  2.304 86.603 36.378 87.005 ;
     RECT  37.548 86.827 38.214 87.071 ;
     RECT  38.196 87.071 38.214 87.307 ;
     RECT  0.144 87.451 0.162 87.581 ;
     RECT  2.412 87.005 36.378 87.691 ;
     RECT  2.412 87.691 36.522 87.781 ;
     RECT  2.304 87.781 36.522 87.821 ;
     RECT  2.415 87.821 36.522 87.881 ;
     RECT  2.415 87.881 36.45 88.079 ;
     RECT  38.196 87.307 38.79 88.223 ;
     RECT  0.108 88.171 0.126 88.321 ;
     RECT  0.108 88.321 0.162 88.445 ;
     RECT  2.415 88.079 36.198 88.555 ;
     RECT  37.584 88.747 37.602 88.799 ;
     RECT  0.108 88.445 0.126 89.069 ;
     RECT  38.628 88.223 38.79 89.131 ;
     RECT  2.304 88.555 36.198 89.231 ;
     RECT  38.196 89.131 38.79 89.261 ;
     RECT  3.672 89.231 36.198 89.311 ;
     RECT  2.304 89.231 2.862 89.339 ;
     RECT  3.672 89.311 36.234 89.515 ;
     RECT  3.672 89.515 36.81 89.707 ;
     RECT  3.672 89.707 36.918 89.771 ;
     RECT  3.672 89.771 36.738 89.789 ;
     RECT  2.304 89.339 2.754 89.851 ;
     RECT  3.672 89.789 36.198 90.013 ;
     RECT  38.196 89.261 38.718 90.041 ;
     RECT  38.196 90.041 38.682 90.043 ;
     RECT  38.16 90.043 38.682 90.187 ;
     RECT  1.98 89.851 2.754 90.221 ;
     RECT  3.564 90.013 36.198 90.239 ;
     RECT  2.304 90.221 2.754 90.283 ;
     RECT  2.304 90.283 2.826 90.391 ;
     RECT  3.564 90.239 36.126 90.391 ;
     RECT  2.304 90.391 36.126 90.419 ;
     RECT  2.304 90.419 35.946 90.509 ;
     RECT  37.584 90.187 38.682 90.667 ;
     RECT  37.476 90.667 38.682 90.845 ;
     RECT  2.415 90.509 35.946 90.851 ;
     RECT  37.476 90.845 37.602 90.851 ;
     RECT  38.628 90.845 38.682 91.003 ;
     RECT  3.492 90.851 35.946 91.133 ;
     RECT  38.628 91.003 38.718 91.133 ;
     RECT  3.744 91.133 35.946 91.165 ;
     RECT  38.628 91.133 38.646 91.181 ;
     RECT  37.476 90.851 37.494 91.193 ;
     RECT  3.744 91.165 36.018 91.319 ;
     RECT  3.744 91.319 35.946 91.355 ;
     RECT  3.744 91.355 35.442 91.499 ;
     RECT  3.744 91.499 13.77 91.589 ;
     RECT  3.996 91.589 13.77 91.625 ;
     RECT  3.996 91.625 13.734 91.661 ;
     RECT  4.932 91.661 13.734 91.733 ;
     RECT  3.996 91.661 4.014 91.859 ;
     RECT  14.58 91.499 35.442 91.967 ;
     RECT  5.004 91.733 13.734 92.039 ;
     RECT  5.115 92.039 13.734 92.165 ;
     RECT  38.772 92.107 38.79 92.237 ;
     RECT  6.408 92.165 13.734 92.347 ;
     RECT  6.408 92.347 13.77 92.371 ;
     RECT  14.58 91.967 35.298 92.371 ;
     RECT  5.115 92.165 5.526 92.399 ;
     RECT  6.408 92.371 35.298 92.435 ;
     RECT  2.415 90.851 2.697 92.443 ;
     RECT  0.108 90.667 0.126 92.471 ;
     RECT  5.115 92.399 5.454 92.471 ;
     RECT  23.004 92.435 35.298 92.507 ;
     RECT  23.004 92.507 32.49 92.573 ;
     RECT  2.415 92.443 2.862 92.579 ;
     RECT  5.115 92.471 5.397 92.627 ;
     RECT  6.408 92.435 22.194 92.669 ;
     RECT  23.04 92.573 32.49 92.669 ;
     RECT  33.408 92.507 35.298 92.669 ;
     RECT  2.415 92.579 2.754 92.705 ;
     RECT  6.408 92.669 9.054 92.705 ;
     RECT  12.6 92.669 20.286 92.705 ;
     RECT  21.315 92.669 22.194 92.705 ;
     RECT  26.1 92.669 28.134 92.705 ;
     RECT  34.02 92.669 34.905 92.705 ;
     RECT  12.6 92.705 17.19 92.717 ;
     RECT  13.215 92.717 17.19 92.741 ;
     RECT  23.04 92.669 25.218 92.741 ;
     RECT  13.215 92.741 14.058 92.765 ;
     RECT  9.9 92.669 11.466 92.777 ;
     RECT  27.9 92.705 28.134 92.777 ;
     RECT  6.984 92.705 9.054 92.813 ;
     RECT  23.04 92.741 24.105 92.813 ;
     RECT  26.715 92.705 27.054 92.813 ;
     RECT  28.116 92.777 28.134 92.813 ;
     RECT  31.356 92.669 32.49 92.813 ;
     RECT  34.02 92.705 34.038 92.813 ;
     RECT  6.984 92.813 8.586 92.849 ;
     RECT  13.215 92.765 13.59 92.849 ;
     RECT  18.216 92.705 18.705 92.849 ;
     RECT  20.268 92.705 20.286 92.849 ;
     RECT  21.315 92.705 21.87 92.849 ;
     RECT  23.58 92.813 24.105 92.849 ;
     RECT  24.84 92.741 25.218 92.849 ;
     RECT  29.34 92.669 29.505 92.849 ;
     RECT  31.356 92.813 32.205 92.849 ;
     RECT  10.515 92.777 11.466 92.861 ;
     RECT  2.415 92.705 2.505 92.897 ;
     RECT  5.115 92.627 5.205 92.897 ;
     RECT  7.815 92.849 7.905 92.897 ;
     RECT  10.515 92.861 10.605 92.897 ;
     RECT  13.215 92.849 13.305 92.897 ;
     RECT  15.192 92.741 16.074 92.897 ;
     RECT  18.615 92.849 18.705 92.897 ;
     RECT  21.315 92.849 21.405 92.897 ;
     RECT  24.015 92.849 24.105 92.897 ;
     RECT  26.715 92.813 26.805 92.897 ;
     RECT  29.415 92.849 29.505 92.897 ;
     RECT  32.115 92.849 32.205 92.897 ;
     RECT  34.815 92.705 34.905 92.897 ;
     RECT  0.54 92.821 0.558 93.149 ;
     RECT  16.056 92.897 16.074 94.981 ;
     RECT  16.812 92.741 16.83 94.981 ;
    LAYER M4 ;
     RECT  0.084 1.056 0.227 1.08 ;
     RECT  0.06 1.08 0.227 1.248 ;
     RECT  0.084 1.248 0.227 1.272 ;
     RECT  0.06 1.272 0.227 1.392 ;
     RECT  0.084 1.392 0.227 1.416 ;
     RECT  0.06 1.416 0.227 1.536 ;
     RECT  0.084 1.536 0.227 1.56 ;
     RECT  0.06 1.56 0.227 1.728 ;
     RECT  0.084 1.728 0.227 1.752 ;
     RECT  0.06 1.752 0.227 1.872 ;
     RECT  0.084 1.872 0.227 1.896 ;
     RECT  0.06 1.896 0.227 2.016 ;
     RECT  0.084 2.016 0.227 2.04 ;
     RECT  0.06 2.04 0.227 2.208 ;
     RECT  0.084 2.208 0.227 2.232 ;
     RECT  0.06 2.232 0.227 2.352 ;
     RECT  0.084 2.352 0.227 2.376 ;
     RECT  0.06 2.376 0.227 2.496 ;
     RECT  0.084 2.496 0.227 2.52 ;
     RECT  0.06 2.52 0.227 2.688 ;
     RECT  0.084 2.688 0.227 2.712 ;
     RECT  0.06 2.712 0.227 2.832 ;
     RECT  0.084 2.832 0.227 2.856 ;
     RECT  0.06 2.856 0.227 2.976 ;
     RECT  0.084 2.976 0.227 3 ;
     RECT  0.06 3 0.227 3.168 ;
     RECT  0.084 3.168 0.227 3.192 ;
     RECT  0.06 3.192 0.227 3.312 ;
     RECT  0.084 3.312 0.227 3.336 ;
     RECT  0.06 3.336 0.227 3.456 ;
     RECT  0.084 3.456 0.227 3.48 ;
     RECT  0.06 3.48 0.227 3.648 ;
     RECT  0.084 3.648 0.227 3.672 ;
     RECT  0.06 3.672 0.227 3.792 ;
     RECT  0.084 3.792 0.227 3.816 ;
     RECT  0.06 3.816 0.227 3.936 ;
     RECT  0.084 3.936 0.227 3.96 ;
     RECT  0.06 3.96 0.227 4.128 ;
     RECT  0.084 4.128 0.227 4.152 ;
     RECT  0.06 4.152 0.227 4.272 ;
     RECT  0.084 4.272 0.227 4.296 ;
     RECT  0.06 4.296 0.227 4.464 ;
     RECT  0.084 4.464 0.227 4.488 ;
     RECT  0.06 4.488 0.227 4.608 ;
     RECT  0.084 4.608 0.227 4.632 ;
     RECT  0.06 4.632 0.227 4.752 ;
     RECT  0.084 4.752 0.227 4.776 ;
     RECT  0.06 4.776 0.227 4.944 ;
     RECT  0.084 4.944 0.227 4.968 ;
     RECT  0.06 4.968 0.227 5.088 ;
     RECT  0.084 5.088 0.227 5.112 ;
     RECT  0.06 5.112 0.227 5.232 ;
     RECT  0.084 5.232 0.227 5.256 ;
     RECT  0.06 5.256 0.227 5.424 ;
     RECT  0.084 5.424 0.227 5.448 ;
     RECT  0.06 5.448 0.227 5.568 ;
     RECT  0.084 5.568 0.227 5.592 ;
     RECT  0.06 5.592 0.227 5.712 ;
     RECT  0.084 5.712 0.227 5.736 ;
     RECT  0.06 5.736 0.227 5.904 ;
     RECT  0.084 5.904 0.227 5.928 ;
     RECT  0.06 5.928 0.227 6.048 ;
     RECT  0.084 6.048 0.227 6.072 ;
     RECT  0.06 6.072 0.227 6.192 ;
     RECT  0.084 6.192 0.227 6.216 ;
     RECT  0.06 6.216 0.227 6.384 ;
     RECT  0.084 6.384 0.227 6.408 ;
     RECT  0.06 6.408 0.227 6.528 ;
     RECT  0.084 6.528 0.227 6.552 ;
     RECT  0.06 6.552 0.227 6.672 ;
     RECT  0.084 6.672 0.227 6.696 ;
     RECT  0.06 6.696 0.227 6.864 ;
     RECT  0.084 6.864 0.227 6.888 ;
     RECT  0.06 6.888 0.227 7.008 ;
     RECT  0.084 7.008 0.227 7.032 ;
     RECT  0.06 7.032 0.227 7.152 ;
     RECT  0.084 7.152 0.227 7.176 ;
     RECT  0.06 7.176 0.227 7.344 ;
     RECT  0.084 7.344 0.227 7.368 ;
     RECT  0.06 7.368 0.227 7.488 ;
     RECT  0.084 7.488 0.227 7.512 ;
     RECT  0.06 7.512 0.227 7.632 ;
     RECT  0.084 7.632 0.227 7.656 ;
     RECT  0.06 7.656 0.227 7.824 ;
     RECT  0.084 7.824 0.227 7.848 ;
     RECT  0.06 7.848 0.227 7.968 ;
     RECT  0.084 7.968 0.227 7.992 ;
     RECT  0.06 7.992 0.227 8.112 ;
     RECT  0.084 8.112 0.227 8.136 ;
     RECT  0.06 8.136 0.227 8.304 ;
     RECT  0.084 8.304 0.227 8.328 ;
     RECT  0.06 8.328 0.227 8.448 ;
     RECT  0.084 8.448 0.227 8.472 ;
     RECT  0.06 8.472 0.227 8.592 ;
     RECT  0.084 8.592 0.227 8.616 ;
     RECT  0.06 8.616 0.227 8.784 ;
     RECT  0.084 8.784 0.227 8.808 ;
     RECT  0.06 8.808 0.227 8.928 ;
     RECT  0.084 8.928 0.227 8.952 ;
     RECT  0.06 8.952 0.227 9.12 ;
     RECT  0.084 9.12 0.227 9.144 ;
     RECT  0.06 9.144 0.227 9.264 ;
     RECT  0.084 9.264 0.227 9.288 ;
     RECT  0.06 9.288 0.227 9.408 ;
     RECT  0.084 9.408 0.227 9.432 ;
     RECT  0.06 9.432 0.227 9.6 ;
     RECT  0.084 9.6 0.227 9.624 ;
     RECT  0.06 9.624 0.227 9.744 ;
     RECT  0.084 9.744 0.227 9.768 ;
     RECT  0.06 9.768 0.227 9.888 ;
     RECT  0.084 9.888 0.227 9.912 ;
     RECT  0.06 9.912 0.227 10.08 ;
     RECT  0.084 10.08 0.227 10.104 ;
     RECT  0.06 10.104 0.227 10.224 ;
     RECT  0.084 10.224 0.227 10.248 ;
     RECT  0.06 10.248 0.227 10.368 ;
     RECT  0.084 10.368 0.227 10.392 ;
     RECT  0.06 10.392 0.227 10.56 ;
     RECT  0.084 10.56 0.227 10.584 ;
     RECT  0.06 10.584 0.227 10.704 ;
     RECT  0.084 10.704 0.227 10.728 ;
     RECT  0.06 10.728 0.227 10.848 ;
     RECT  0.084 10.848 0.227 10.872 ;
     RECT  0.06 10.872 0.227 11.04 ;
     RECT  0.084 11.04 0.227 11.064 ;
     RECT  0.06 11.064 0.227 11.184 ;
     RECT  0.084 11.184 0.227 11.208 ;
     RECT  0.06 11.208 0.227 11.328 ;
     RECT  0.084 11.328 0.227 11.352 ;
     RECT  0.06 11.352 0.227 11.52 ;
     RECT  0.084 11.52 0.227 11.544 ;
     RECT  0.06 11.544 0.227 11.664 ;
     RECT  0.084 11.664 0.227 11.688 ;
     RECT  0.06 11.688 0.227 11.808 ;
     RECT  0.084 11.808 0.227 11.832 ;
     RECT  0.06 11.832 0.227 12 ;
     RECT  0.084 12 0.227 12.024 ;
     RECT  0.06 12.024 0.227 12.144 ;
     RECT  0.084 12.144 0.227 12.168 ;
     RECT  0.06 12.168 0.227 12.288 ;
     RECT  0.084 12.288 0.227 12.312 ;
     RECT  0.06 12.312 0.227 12.48 ;
     RECT  0.084 12.48 0.227 12.504 ;
     RECT  0.06 12.504 0.227 12.624 ;
     RECT  0.084 12.624 0.227 12.648 ;
     RECT  0.06 12.648 0.227 12.768 ;
     RECT  0.084 12.768 0.227 12.792 ;
     RECT  0.06 12.792 0.227 12.96 ;
     RECT  0.084 12.96 0.227 12.984 ;
     RECT  0.06 12.984 0.227 13.104 ;
     RECT  0.084 13.104 0.227 13.128 ;
     RECT  0.06 13.128 0.227 13.296 ;
     RECT  0.084 13.296 0.227 13.32 ;
     RECT  0.06 13.32 0.227 13.44 ;
     RECT  0.084 13.44 0.227 13.464 ;
     RECT  0.06 13.464 0.227 13.584 ;
     RECT  0.084 13.584 0.227 13.608 ;
     RECT  0.06 13.608 0.227 13.776 ;
     RECT  0.084 13.776 0.227 13.8 ;
     RECT  0.06 13.8 0.227 13.92 ;
     RECT  0.084 13.92 0.227 13.944 ;
     RECT  0.06 13.944 0.227 14.064 ;
     RECT  0.084 14.064 0.227 14.088 ;
     RECT  0.06 14.088 0.227 14.256 ;
     RECT  0.084 14.256 0.227 14.28 ;
     RECT  0.06 14.28 0.227 14.4 ;
     RECT  0.084 14.4 0.227 14.424 ;
     RECT  0.06 14.424 0.227 14.544 ;
     RECT  0.084 14.544 0.227 14.568 ;
     RECT  0.06 14.568 0.227 14.736 ;
     RECT  0.084 14.736 0.227 14.76 ;
     RECT  0.06 14.76 0.227 14.88 ;
     RECT  0.084 14.88 0.227 14.904 ;
     RECT  0.06 14.904 0.227 15.024 ;
     RECT  0.084 15.024 0.227 15.048 ;
     RECT  0.06 15.048 0.227 15.216 ;
     RECT  0.084 15.216 0.227 15.24 ;
     RECT  0.06 15.24 0.227 15.36 ;
     RECT  0.084 15.36 0.227 15.384 ;
     RECT  0.06 15.384 0.227 15.504 ;
     RECT  0.084 15.504 0.227 15.528 ;
     RECT  0.06 15.528 0.227 15.696 ;
     RECT  0.084 15.696 0.227 15.72 ;
     RECT  0.06 15.72 0.227 15.84 ;
     RECT  0.084 15.84 0.227 15.864 ;
     RECT  0.06 15.864 0.227 15.984 ;
     RECT  0.084 15.984 0.227 16.008 ;
     RECT  0.06 16.008 0.227 16.176 ;
     RECT  0.084 16.176 0.227 16.2 ;
     RECT  0.06 16.2 0.227 16.32 ;
     RECT  0.084 16.32 0.227 16.344 ;
     RECT  0.06 16.344 0.227 16.464 ;
     RECT  0.084 16.464 0.227 16.488 ;
     RECT  0.06 16.488 0.227 16.656 ;
     RECT  0.084 16.656 0.227 16.68 ;
     RECT  0.06 16.68 0.227 16.8 ;
     RECT  0.084 16.8 0.227 16.824 ;
     RECT  0.06 16.824 0.227 16.944 ;
     RECT  0.084 16.944 0.227 16.968 ;
     RECT  0.06 16.968 0.227 17.136 ;
     RECT  0.084 17.136 0.227 17.16 ;
     RECT  0.06 17.16 0.227 17.28 ;
     RECT  0.084 17.28 0.227 17.304 ;
     RECT  0.06 17.304 0.227 17.424 ;
     RECT  0.084 17.424 0.227 17.448 ;
     RECT  0.06 17.448 0.227 17.616 ;
     RECT  0.084 17.616 0.227 17.64 ;
     RECT  0.06 17.64 0.227 17.76 ;
     RECT  0.084 17.76 0.227 17.784 ;
     RECT  0.06 17.784 0.227 17.952 ;
     RECT  0.084 17.952 0.227 17.976 ;
     RECT  0.06 17.976 0.227 18.096 ;
     RECT  0.084 18.096 0.227 18.12 ;
     RECT  0.06 18.12 0.227 18.24 ;
     RECT  0.084 18.24 0.227 18.264 ;
     RECT  0.06 18.264 0.227 18.432 ;
     RECT  0.084 18.432 0.227 18.456 ;
     RECT  0.06 18.456 0.227 18.576 ;
     RECT  0.084 18.576 0.227 18.6 ;
     RECT  0.06 18.6 0.227 18.72 ;
     RECT  0.084 18.72 0.227 18.744 ;
     RECT  0.06 18.744 0.227 18.912 ;
     RECT  0.084 18.912 0.227 18.936 ;
     RECT  0.06 18.936 0.227 19.056 ;
     RECT  0.084 19.056 0.227 19.08 ;
     RECT  0.06 19.08 0.227 19.2 ;
     RECT  0.084 19.2 0.227 19.224 ;
     RECT  0.06 19.224 0.227 19.392 ;
     RECT  0.084 19.392 0.227 19.416 ;
     RECT  0.06 19.416 0.227 19.536 ;
     RECT  0.084 19.536 0.227 19.56 ;
     RECT  0.06 19.56 0.227 19.68 ;
     RECT  0.084 19.68 0.227 19.704 ;
     RECT  0.06 19.704 0.227 19.872 ;
     RECT  0.084 19.872 0.227 19.896 ;
     RECT  0.06 19.896 0.227 20.016 ;
     RECT  0.084 20.016 0.227 20.04 ;
     RECT  0.06 20.04 0.227 20.16 ;
     RECT  0.084 20.16 0.227 20.184 ;
     RECT  0.06 20.184 0.227 20.352 ;
     RECT  0.084 20.352 0.227 20.376 ;
     RECT  0.06 20.376 0.227 20.496 ;
     RECT  0.084 20.496 0.227 20.52 ;
     RECT  0.06 20.52 0.227 20.64 ;
     RECT  0.084 20.64 0.227 20.664 ;
     RECT  0.06 20.664 0.227 20.832 ;
     RECT  0.084 20.832 0.227 20.856 ;
     RECT  0.06 20.856 0.227 20.976 ;
     RECT  0.084 20.976 0.227 21 ;
     RECT  0.06 21 0.227 21.12 ;
     RECT  0.084 21.12 0.227 21.144 ;
     RECT  0.06 21.144 0.227 21.312 ;
     RECT  0.084 21.312 0.227 21.336 ;
     RECT  0.06 21.336 0.227 21.456 ;
     RECT  0.084 21.456 0.227 21.48 ;
     RECT  0.06 21.48 0.227 21.6 ;
     RECT  0.084 21.6 0.227 21.624 ;
     RECT  0.06 21.624 0.227 21.792 ;
     RECT  0.084 21.792 0.227 21.816 ;
     RECT  0.06 21.816 0.227 21.936 ;
     RECT  0.084 21.936 0.227 21.96 ;
     RECT  0.06 21.96 0.227 22.08 ;
     RECT  0.084 22.08 0.227 22.104 ;
     RECT  0.06 22.104 0.227 22.272 ;
     RECT  0.084 22.272 0.227 22.296 ;
     RECT  0.06 22.296 0.227 22.416 ;
     RECT  0.084 22.416 0.227 22.44 ;
     RECT  0.06 22.44 0.227 22.608 ;
     RECT  0.084 22.608 0.227 22.632 ;
     RECT  0.06 22.632 0.227 22.752 ;
     RECT  0.084 22.752 0.227 22.776 ;
     RECT  0.06 22.776 0.227 22.896 ;
     RECT  0.084 22.896 0.227 22.92 ;
     RECT  0.06 22.92 0.227 23.088 ;
     RECT  0.084 23.088 0.227 23.112 ;
     RECT  0.06 23.112 0.227 23.232 ;
     RECT  0.084 23.232 0.227 23.256 ;
     RECT  0.06 23.256 0.227 23.376 ;
     RECT  0.084 23.376 0.227 23.4 ;
     RECT  0.06 23.4 0.227 23.568 ;
     RECT  0.084 23.568 0.227 23.592 ;
     RECT  0.06 23.592 0.227 23.712 ;
     RECT  0.084 23.712 0.227 23.736 ;
     RECT  0.06 23.736 0.227 23.856 ;
     RECT  0.084 23.856 0.227 23.88 ;
     RECT  0.06 23.88 0.227 24.048 ;
     RECT  0.084 24.048 0.227 24.072 ;
     RECT  0.06 24.072 0.227 24.192 ;
     RECT  0.084 24.192 0.227 24.216 ;
     RECT  0.06 24.216 0.227 24.336 ;
     RECT  0.084 24.336 0.227 24.36 ;
     RECT  0.06 24.36 0.227 24.528 ;
     RECT  0.084 24.528 0.227 24.552 ;
     RECT  0.06 24.552 0.227 24.672 ;
     RECT  0.084 24.672 0.227 24.696 ;
     RECT  0.06 24.696 0.227 24.816 ;
     RECT  0.084 24.816 0.227 24.84 ;
     RECT  0.06 24.84 0.227 25.008 ;
     RECT  0.084 25.008 0.227 25.032 ;
     RECT  0.06 25.032 0.227 25.152 ;
     RECT  0.084 25.152 0.227 25.176 ;
     RECT  0.06 25.176 0.227 25.296 ;
     RECT  0.084 25.296 0.227 25.32 ;
     RECT  0.06 25.32 0.227 25.488 ;
     RECT  0.084 25.488 0.227 25.512 ;
     RECT  0.06 25.512 0.227 25.632 ;
     RECT  0.084 25.632 0.227 25.656 ;
     RECT  0.06 25.656 0.227 25.776 ;
     RECT  0.084 25.776 0.227 25.8 ;
     RECT  0.06 25.8 0.227 25.968 ;
     RECT  0.084 25.968 0.227 25.992 ;
     RECT  0.06 25.992 0.227 26.112 ;
     RECT  0.084 26.112 0.227 26.136 ;
     RECT  0.06 26.136 0.227 26.256 ;
     RECT  0.084 26.256 0.227 26.28 ;
     RECT  0.06 26.28 0.227 26.448 ;
     RECT  0.084 26.448 0.227 26.472 ;
     RECT  0.06 26.472 0.227 26.592 ;
     RECT  0.084 26.592 0.227 26.616 ;
     RECT  0.06 26.616 0.227 26.736 ;
     RECT  0.084 26.736 0.227 26.76 ;
     RECT  0.06 26.76 0.227 26.928 ;
     RECT  0.084 26.928 0.227 26.952 ;
     RECT  0.06 26.952 0.227 27.072 ;
     RECT  0.084 27.072 0.227 27.096 ;
     RECT  0.06 27.096 0.227 27.264 ;
     RECT  0.084 27.264 0.227 27.288 ;
     RECT  0.06 27.288 0.227 27.408 ;
     RECT  0.084 27.408 0.227 27.432 ;
     RECT  0.06 27.432 0.227 27.552 ;
     RECT  0.084 27.552 0.227 27.576 ;
     RECT  0.06 27.576 0.227 27.744 ;
     RECT  0.084 27.744 0.227 27.768 ;
     RECT  0.06 27.768 0.227 27.888 ;
     RECT  0.084 27.888 0.227 27.912 ;
     RECT  0.06 27.912 0.227 28.032 ;
     RECT  0.084 28.032 0.227 28.056 ;
     RECT  0.06 28.056 0.227 28.224 ;
     RECT  0.084 28.224 0.227 28.248 ;
     RECT  0.06 28.248 0.227 28.368 ;
     RECT  0.084 28.368 0.227 28.392 ;
     RECT  0.06 28.392 0.227 28.512 ;
     RECT  0.084 28.512 0.227 28.536 ;
     RECT  0.06 28.536 0.227 28.704 ;
     RECT  0.084 28.704 0.227 28.728 ;
     RECT  0.06 28.728 0.227 28.848 ;
     RECT  0.084 28.848 0.227 28.872 ;
     RECT  0.06 28.872 0.227 28.992 ;
     RECT  0.084 28.992 0.227 29.016 ;
     RECT  0.06 29.016 0.227 29.184 ;
     RECT  0.084 29.184 0.227 29.208 ;
     RECT  0.06 29.208 0.227 29.328 ;
     RECT  0.084 29.328 0.227 29.352 ;
     RECT  0.06 29.352 0.227 29.472 ;
     RECT  0.084 29.472 0.227 29.496 ;
     RECT  0.06 29.496 0.227 29.664 ;
     RECT  0.084 29.664 0.227 29.688 ;
     RECT  0.06 29.688 0.227 29.808 ;
     RECT  0.084 29.808 0.227 29.832 ;
     RECT  0.06 29.832 0.227 29.952 ;
     RECT  0.084 29.952 0.227 29.976 ;
     RECT  0.06 29.976 0.227 30.144 ;
     RECT  0.084 30.144 0.227 30.168 ;
     RECT  0.06 30.168 0.227 30.288 ;
     RECT  0.084 30.288 0.227 30.312 ;
     RECT  0.06 30.312 0.227 30.432 ;
     RECT  0.084 30.432 0.227 30.456 ;
     RECT  0.06 30.456 0.227 30.624 ;
     RECT  0.084 30.624 0.227 30.648 ;
     RECT  0.06 30.648 0.227 30.768 ;
     RECT  0.084 30.768 0.227 30.792 ;
     RECT  0.06 30.792 0.227 30.912 ;
     RECT  0.084 30.912 0.227 30.936 ;
     RECT  0.06 30.936 0.227 31.104 ;
     RECT  0.084 31.104 0.227 31.128 ;
     RECT  0.06 31.128 0.227 31.248 ;
     RECT  0.084 31.248 0.227 31.272 ;
     RECT  0.06 31.272 0.227 31.44 ;
     RECT  0.084 31.44 0.227 31.464 ;
     RECT  0.06 31.464 0.227 31.584 ;
     RECT  0.084 31.584 0.227 31.608 ;
     RECT  0.06 31.608 0.227 31.728 ;
     RECT  0.084 31.728 0.227 31.752 ;
     RECT  0.06 31.752 0.227 31.92 ;
     RECT  0.084 31.92 0.227 31.944 ;
     RECT  0.06 31.944 0.227 32.064 ;
     RECT  0.084 32.064 0.227 32.088 ;
     RECT  0.06 32.088 0.227 32.208 ;
     RECT  0.084 32.208 0.227 32.232 ;
     RECT  0.06 32.232 0.227 32.4 ;
     RECT  0.084 32.4 0.227 32.424 ;
     RECT  0.06 32.424 0.227 32.544 ;
     RECT  0.084 32.544 0.227 32.568 ;
     RECT  0.06 32.568 0.227 32.688 ;
     RECT  0.084 32.688 0.227 32.712 ;
     RECT  0.06 32.712 0.227 32.88 ;
     RECT  0.084 32.88 0.227 32.904 ;
     RECT  0.06 32.904 0.227 33.024 ;
     RECT  0.084 33.024 0.227 33.048 ;
     RECT  0.06 33.048 0.227 33.168 ;
     RECT  0.084 33.168 0.227 33.192 ;
     RECT  0.06 33.192 0.227 33.36 ;
     RECT  0.084 33.36 0.227 33.384 ;
     RECT  0.06 33.384 0.227 33.504 ;
     RECT  0.084 33.504 0.227 33.528 ;
     RECT  0.06 33.528 0.227 33.648 ;
     RECT  0.084 33.648 0.227 33.672 ;
     RECT  0.06 33.672 0.227 33.84 ;
     RECT  0.084 33.84 0.227 33.864 ;
     RECT  0.06 33.864 0.227 33.984 ;
     RECT  0.084 33.984 0.227 34.008 ;
     RECT  0.06 34.008 0.227 34.128 ;
     RECT  0.084 34.128 0.227 34.152 ;
     RECT  0.06 34.152 0.227 34.32 ;
     RECT  0.084 34.32 0.227 34.344 ;
     RECT  0.06 34.344 0.227 34.464 ;
     RECT  0.084 34.464 0.227 34.488 ;
     RECT  0.06 34.488 0.227 34.608 ;
     RECT  0.084 34.608 0.227 34.632 ;
     RECT  0.06 34.632 0.227 34.8 ;
     RECT  0.084 34.8 0.227 34.824 ;
     RECT  0.06 34.824 0.227 34.944 ;
     RECT  0.084 34.944 0.227 34.968 ;
     RECT  0.06 34.968 0.227 35.088 ;
     RECT  0.084 35.088 0.227 35.112 ;
     RECT  0.06 35.112 0.227 35.28 ;
     RECT  0.084 35.28 0.227 35.304 ;
     RECT  0.06 35.304 0.227 35.424 ;
     RECT  0.084 35.424 0.227 35.448 ;
     RECT  0.06 35.448 0.227 35.568 ;
     RECT  0.084 35.568 0.227 35.592 ;
     RECT  0.06 35.592 0.227 35.76 ;
     RECT  0.084 35.76 0.227 35.784 ;
     RECT  0.06 35.784 0.227 35.904 ;
     RECT  0.084 35.904 0.227 35.928 ;
     RECT  0.06 35.928 0.227 36.096 ;
     RECT  0.084 36.096 0.227 36.12 ;
     RECT  0.06 36.12 0.227 36.24 ;
     RECT  0.084 36.24 0.227 36.264 ;
     RECT  0.06 36.264 0.227 36.384 ;
     RECT  0.084 36.384 0.227 36.408 ;
     RECT  0.06 36.408 0.227 36.576 ;
     RECT  0.084 36.576 0.227 36.6 ;
     RECT  0.06 36.6 0.227 36.72 ;
     RECT  0.084 36.72 0.227 36.744 ;
     RECT  0.06 36.744 0.227 36.864 ;
     RECT  0.084 36.864 0.227 36.888 ;
     RECT  0.06 36.888 0.227 37.056 ;
     RECT  0.084 37.056 0.227 37.08 ;
     RECT  0.06 37.08 0.227 37.2 ;
     RECT  0.084 37.2 0.227 37.224 ;
     RECT  0.06 37.224 0.227 37.344 ;
     RECT  0.084 37.344 0.227 37.368 ;
     RECT  0.06 37.368 0.227 37.536 ;
     RECT  0.084 37.536 0.227 37.56 ;
     RECT  0.06 37.56 0.227 37.68 ;
     RECT  0.084 37.68 0.227 37.704 ;
     RECT  0.06 37.704 0.227 37.824 ;
     RECT  0.084 37.824 0.227 37.848 ;
     RECT  0.06 37.848 0.227 38.016 ;
     RECT  0.084 38.016 0.227 38.04 ;
     RECT  0.06 38.04 0.227 38.16 ;
     RECT  0.084 38.16 0.227 38.184 ;
     RECT  0.06 38.184 0.227 38.304 ;
     RECT  0.084 38.304 0.227 38.328 ;
     RECT  0.06 38.328 0.227 38.496 ;
     RECT  0.084 38.496 0.227 38.52 ;
     RECT  0.06 38.52 0.227 38.64 ;
     RECT  0.084 38.64 0.227 38.664 ;
     RECT  0.06 38.664 0.227 38.784 ;
     RECT  0.084 38.784 0.227 38.808 ;
     RECT  0.06 38.808 0.227 38.976 ;
     RECT  0.084 38.976 0.227 39 ;
     RECT  0.06 39 0.227 39.12 ;
     RECT  0.084 39.12 0.227 39.144 ;
     RECT  0.06 39.144 0.227 39.264 ;
     RECT  0.084 39.264 0.227 39.288 ;
     RECT  0.06 39.288 0.227 39.456 ;
     RECT  0.084 39.456 0.227 39.48 ;
     RECT  0.06 39.48 0.227 39.6 ;
     RECT  0.084 39.6 0.227 39.624 ;
     RECT  0.06 39.624 0.227 39.744 ;
     RECT  0.084 39.744 0.227 39.768 ;
     RECT  0.06 39.768 0.227 39.936 ;
     RECT  0.084 39.936 0.227 39.96 ;
     RECT  0.06 39.96 0.227 40.08 ;
     RECT  0.084 40.08 0.227 40.104 ;
     RECT  0.06 40.104 0.227 40.224 ;
     RECT  0.084 40.224 0.227 40.248 ;
     RECT  0.06 40.248 0.227 40.416 ;
     RECT  0.084 40.416 0.227 40.44 ;
     RECT  0.06 40.44 0.227 40.56 ;
     RECT  0.084 40.56 0.227 40.584 ;
     RECT  0.06 40.584 0.227 40.752 ;
     RECT  0.084 40.752 0.227 40.776 ;
     RECT  0.06 40.776 0.227 40.896 ;
     RECT  0.084 40.896 0.227 40.92 ;
     RECT  0.06 40.92 0.227 41.04 ;
     RECT  0.084 41.04 0.227 41.064 ;
     RECT  0.06 41.064 0.227 41.232 ;
     RECT  0.084 41.232 0.227 41.256 ;
     RECT  0.06 41.256 0.227 41.376 ;
     RECT  0.084 41.376 0.227 41.4 ;
     RECT  0.06 41.4 0.227 41.52 ;
     RECT  0.084 41.52 0.227 41.544 ;
     RECT  0.06 41.544 0.227 41.712 ;
     RECT  0.084 41.712 0.227 41.736 ;
     RECT  0.06 41.736 0.227 41.856 ;
     RECT  0.084 41.856 0.227 41.88 ;
     RECT  0.06 41.88 0.227 42 ;
     RECT  0.084 42 0.227 42.024 ;
     RECT  0.06 42.024 0.227 42.192 ;
     RECT  0.084 42.192 0.227 42.216 ;
     RECT  0.06 42.216 0.227 42.336 ;
     RECT  0.084 42.336 0.227 42.36 ;
     RECT  0.06 42.36 0.227 42.48 ;
     RECT  0.084 42.48 0.227 42.504 ;
     RECT  0.06 42.504 0.227 42.672 ;
     RECT  0.084 42.672 0.227 42.696 ;
     RECT  0.06 42.696 0.227 42.816 ;
     RECT  0.084 42.816 0.227 42.84 ;
     RECT  0.06 42.84 0.227 42.96 ;
     RECT  0.084 42.96 0.227 42.984 ;
     RECT  0.06 42.984 0.227 43.152 ;
     RECT  0.084 43.152 0.227 43.176 ;
     RECT  0.06 43.176 0.227 43.296 ;
     RECT  0.084 43.296 0.227 43.32 ;
     RECT  0.06 43.32 0.227 43.44 ;
     RECT  0.084 43.44 0.227 43.464 ;
     RECT  0.06 43.464 0.227 43.632 ;
     RECT  0.084 43.632 0.227 43.656 ;
     RECT  0.06 43.656 0.227 43.776 ;
     RECT  0.084 43.776 0.227 43.8 ;
     RECT  0.06 43.8 0.227 43.92 ;
     RECT  0.084 43.92 0.227 43.944 ;
     RECT  0.06 43.944 0.227 44.112 ;
     RECT  0.084 44.112 0.227 44.136 ;
     RECT  0.06 44.136 0.227 44.256 ;
     RECT  0.084 44.256 0.227 44.28 ;
     RECT  0.06 44.28 0.227 44.4 ;
     RECT  0.084 44.4 0.227 44.424 ;
     RECT  0.06 44.424 0.227 44.592 ;
     RECT  0.084 44.592 0.227 44.616 ;
     RECT  0.06 44.616 0.227 44.736 ;
     RECT  0.084 44.736 0.227 44.76 ;
     RECT  0.06 44.76 0.227 44.928 ;
     RECT  0.084 44.928 0.227 44.952 ;
     RECT  0.06 44.952 0.227 45.072 ;
     RECT  0.084 45.072 0.227 45.096 ;
     RECT  0.06 45.096 0.227 45.216 ;
     RECT  0.084 45.216 0.227 45.24 ;
     RECT  0.06 45.24 0.227 45.408 ;
     RECT  0.084 45.408 0.227 45.432 ;
     RECT  0.06 45.432 0.227 45.552 ;
     RECT  0.084 45.552 0.227 45.576 ;
     RECT  0.06 45.576 0.227 45.696 ;
     RECT  0.084 45.696 0.227 45.72 ;
     RECT  0.06 45.72 0.227 45.888 ;
     RECT  0.084 45.888 0.227 45.912 ;
     RECT  0.06 45.912 0.227 46.032 ;
     RECT  0.084 46.032 0.227 46.056 ;
     RECT  0.06 46.056 0.227 46.176 ;
     RECT  0.084 46.176 0.227 46.2 ;
     RECT  0.06 46.2 0.227 46.368 ;
     RECT  0.084 46.368 0.227 46.392 ;
     RECT  0.06 46.392 0.227 46.512 ;
     RECT  0.084 46.512 0.227 46.536 ;
     RECT  0.06 46.536 0.227 46.656 ;
     RECT  0.084 46.656 0.227 46.68 ;
     RECT  0.06 46.68 0.227 46.848 ;
     RECT  0.084 46.848 0.227 46.872 ;
     RECT  0.06 46.872 0.227 46.992 ;
     RECT  0.084 46.992 0.227 47.016 ;
     RECT  0.06 47.016 0.227 47.136 ;
     RECT  0.084 47.136 0.227 47.16 ;
     RECT  0.06 47.16 0.227 47.328 ;
     RECT  0.084 47.328 0.227 47.352 ;
     RECT  0.06 47.352 0.227 47.472 ;
     RECT  0.084 47.472 0.227 47.496 ;
     RECT  0.06 47.496 0.227 47.616 ;
     RECT  0.084 47.616 0.227 47.64 ;
     RECT  0.06 47.64 0.227 47.808 ;
     RECT  0.084 47.808 0.227 47.832 ;
     RECT  0.06 47.832 0.227 47.952 ;
     RECT  0.084 47.952 0.227 47.976 ;
     RECT  0.06 47.976 0.227 48.096 ;
     RECT  0.084 48.096 0.227 48.12 ;
     RECT  0.06 48.12 0.227 48.288 ;
     RECT  0.084 48.288 0.227 48.312 ;
     RECT  0.06 48.312 0.227 48.432 ;
     RECT  0.084 48.432 0.227 48.456 ;
     RECT  0.06 48.456 0.227 48.576 ;
     RECT  0.084 48.576 0.227 48.6 ;
     RECT  0.06 48.6 0.227 48.768 ;
     RECT  0.084 48.768 0.227 48.792 ;
     RECT  0.06 48.792 0.227 48.912 ;
     RECT  0.084 48.912 0.227 48.936 ;
     RECT  0.06 48.936 0.227 49.056 ;
     RECT  0.084 49.056 0.227 49.08 ;
     RECT  0.06 49.08 0.227 49.248 ;
     RECT  0.084 49.248 0.227 49.272 ;
     RECT  0.06 49.272 0.227 49.392 ;
     RECT  0.084 49.392 0.227 49.416 ;
     RECT  0.06 49.416 0.227 49.584 ;
     RECT  0.084 49.584 0.227 49.608 ;
     RECT  0.06 49.608 0.227 49.728 ;
     RECT  0.084 49.728 0.227 49.752 ;
     RECT  0.06 49.752 0.227 49.872 ;
     RECT  0.084 49.872 0.227 49.896 ;
     RECT  0.06 49.896 0.227 50.064 ;
     RECT  0.084 50.064 0.227 50.088 ;
     RECT  0.06 50.088 0.227 50.208 ;
     RECT  0.084 50.208 0.227 50.232 ;
     RECT  0.06 50.232 0.227 50.352 ;
     RECT  0.084 50.352 0.227 50.376 ;
     RECT  0.06 50.376 0.227 50.544 ;
     RECT  0.084 50.544 0.227 50.568 ;
     RECT  0.06 50.568 0.227 50.688 ;
     RECT  0.084 50.688 0.227 50.712 ;
     RECT  0.06 50.712 0.227 50.832 ;
     RECT  0.084 50.832 0.227 50.856 ;
     RECT  0.06 50.856 0.227 51.024 ;
     RECT  0.084 51.024 0.227 51.048 ;
     RECT  0.06 51.048 0.227 51.168 ;
     RECT  0.084 51.168 0.227 51.192 ;
     RECT  0.06 51.192 0.227 51.312 ;
     RECT  0.084 51.312 0.227 51.336 ;
     RECT  0.06 51.336 0.227 51.504 ;
     RECT  0.084 51.504 0.227 51.528 ;
     RECT  0.06 51.528 0.227 51.648 ;
     RECT  0.084 51.648 0.227 51.672 ;
     RECT  0.06 51.672 0.227 51.792 ;
     RECT  0.084 51.792 0.227 51.816 ;
     RECT  0.06 51.816 0.227 51.984 ;
     RECT  0.084 51.984 0.227 52.008 ;
     RECT  0.06 52.008 0.227 52.128 ;
     RECT  0.084 52.128 0.227 52.152 ;
     RECT  0.06 52.152 0.227 52.272 ;
     RECT  0.084 52.272 0.227 52.296 ;
     RECT  0.06 52.296 0.227 52.464 ;
     RECT  0.084 52.464 0.227 52.488 ;
     RECT  0.06 52.488 0.227 52.608 ;
     RECT  0.084 52.608 0.227 52.632 ;
     RECT  0.06 52.632 0.227 52.752 ;
     RECT  0.084 52.752 0.227 52.776 ;
     RECT  0.06 52.776 0.227 52.944 ;
     RECT  0.084 52.944 0.227 52.968 ;
     RECT  0.06 52.968 0.227 53.088 ;
     RECT  0.084 53.088 0.227 53.112 ;
     RECT  0.06 53.112 0.227 53.232 ;
     RECT  0.084 53.232 0.227 53.256 ;
     RECT  0.06 53.256 0.227 53.424 ;
     RECT  0.084 53.424 0.227 53.448 ;
     RECT  0.06 53.448 0.227 53.568 ;
     RECT  0.084 53.568 0.227 53.592 ;
     RECT  0.06 53.592 0.227 53.712 ;
     RECT  0.084 53.712 0.227 53.736 ;
     RECT  0.06 53.736 0.227 53.904 ;
     RECT  0.084 53.904 0.227 53.928 ;
     RECT  0.06 53.928 0.227 54.048 ;
     RECT  0.084 54.048 0.227 54.072 ;
     RECT  0.06 54.072 0.227 54.24 ;
     RECT  0.084 54.24 0.227 54.264 ;
     RECT  0.06 54.264 0.227 54.384 ;
     RECT  0.084 54.384 0.227 54.408 ;
     RECT  0.06 54.408 0.227 54.528 ;
     RECT  0.084 54.528 0.227 54.552 ;
     RECT  0.06 54.552 0.227 54.72 ;
     RECT  0.084 54.72 0.227 54.744 ;
     RECT  0.06 54.744 0.227 54.864 ;
     RECT  0.084 54.864 0.227 54.888 ;
     RECT  0.06 54.888 0.227 55.008 ;
     RECT  0.084 55.008 0.227 55.032 ;
     RECT  0.06 55.032 0.227 55.2 ;
     RECT  0.084 55.2 0.227 55.224 ;
     RECT  0.06 55.224 0.227 55.344 ;
     RECT  0.084 55.344 0.227 55.368 ;
     RECT  0.06 55.368 0.227 55.488 ;
     RECT  0.084 55.488 0.227 55.512 ;
     RECT  0.06 55.512 0.227 55.68 ;
     RECT  0.084 55.68 0.227 55.704 ;
     RECT  0.06 55.704 0.227 55.824 ;
     RECT  0.084 55.824 0.227 55.848 ;
     RECT  0.06 55.848 0.227 55.968 ;
     RECT  0.084 55.968 0.227 55.992 ;
     RECT  0.06 55.992 0.227 56.16 ;
     RECT  0.084 56.16 0.227 56.184 ;
     RECT  0.06 56.184 0.227 56.304 ;
     RECT  0.084 56.304 0.227 56.328 ;
     RECT  0.06 56.328 0.227 56.448 ;
     RECT  0.084 56.448 0.227 56.472 ;
     RECT  0.06 56.472 0.227 56.64 ;
     RECT  0.084 56.64 0.227 56.664 ;
     RECT  0.06 56.664 0.227 56.784 ;
     RECT  0.084 56.784 0.227 56.808 ;
     RECT  0.06 56.808 0.227 56.928 ;
     RECT  0.084 56.928 0.227 56.952 ;
     RECT  0.06 56.952 0.227 57.12 ;
     RECT  0.084 57.12 0.227 57.144 ;
     RECT  0.06 57.144 0.227 57.264 ;
     RECT  0.084 57.264 0.227 57.288 ;
     RECT  0.06 57.288 0.227 57.408 ;
     RECT  0.084 57.408 0.227 57.432 ;
     RECT  0.06 57.432 0.227 57.6 ;
     RECT  0.084 57.6 0.227 57.624 ;
     RECT  0.06 57.624 0.227 57.744 ;
     RECT  0.084 57.744 0.227 57.768 ;
     RECT  0.06 57.768 0.227 57.888 ;
     RECT  0.084 57.888 0.227 57.912 ;
     RECT  0.06 57.912 0.227 58.08 ;
     RECT  0.084 58.08 0.227 58.104 ;
     RECT  0.06 58.104 0.227 58.224 ;
     RECT  0.084 58.224 0.227 58.248 ;
     RECT  0.06 58.248 0.227 58.416 ;
     RECT  0.084 58.416 0.227 58.44 ;
     RECT  0.06 58.44 0.227 58.56 ;
     RECT  0.084 58.56 0.227 58.584 ;
     RECT  0.06 58.584 0.227 58.704 ;
     RECT  0.084 58.704 0.227 58.728 ;
     RECT  0.06 58.728 0.227 58.896 ;
     RECT  0.084 58.896 0.227 58.92 ;
     RECT  0.06 58.92 0.227 59.04 ;
     RECT  0.084 59.04 0.227 59.064 ;
     RECT  0.06 59.064 0.227 59.184 ;
     RECT  0.084 59.184 0.227 59.208 ;
     RECT  0.06 59.208 0.227 59.376 ;
     RECT  0.084 59.376 0.227 59.4 ;
     RECT  0.06 59.4 0.227 59.52 ;
     RECT  0.084 59.52 0.227 59.544 ;
     RECT  0.06 59.544 0.227 59.664 ;
     RECT  0.084 59.664 0.227 59.688 ;
     RECT  0.06 59.688 0.227 59.856 ;
     RECT  0.084 59.856 0.227 59.88 ;
     RECT  0.06 59.88 0.227 60 ;
     RECT  0.084 60 0.227 60.024 ;
     RECT  0.06 60.024 0.227 60.144 ;
     RECT  0.084 60.144 0.227 60.168 ;
     RECT  0.06 60.168 0.227 60.336 ;
     RECT  0.084 60.336 0.227 60.36 ;
     RECT  0.06 60.36 0.227 60.48 ;
     RECT  0.084 60.48 0.227 60.504 ;
     RECT  0.06 60.504 0.227 60.624 ;
     RECT  0.084 60.624 0.227 60.648 ;
     RECT  0.06 60.648 0.227 60.816 ;
     RECT  0.084 60.816 0.227 60.84 ;
     RECT  0.06 60.84 0.227 60.96 ;
     RECT  0.084 60.96 0.227 60.984 ;
     RECT  0.06 60.984 0.227 61.104 ;
     RECT  0.084 61.104 0.227 61.128 ;
     RECT  0.06 61.128 0.227 61.296 ;
     RECT  0.084 61.296 0.227 61.32 ;
     RECT  0.06 61.32 0.227 61.44 ;
     RECT  0.084 61.44 0.227 61.464 ;
     RECT  0.06 61.464 0.227 61.584 ;
     RECT  0.084 61.584 0.227 61.608 ;
     RECT  0.06 61.608 0.227 61.776 ;
     RECT  0.084 61.776 0.227 61.8 ;
     RECT  0.06 61.8 0.227 61.92 ;
     RECT  0.084 61.92 0.227 61.944 ;
     RECT  0.06 61.944 0.227 62.064 ;
     RECT  0.084 62.064 0.227 62.088 ;
     RECT  0.06 62.088 0.227 62.256 ;
     RECT  0.084 62.256 0.227 62.28 ;
     RECT  0.06 62.28 0.227 62.4 ;
     RECT  0.084 62.4 0.227 62.424 ;
     RECT  0.06 62.424 0.227 62.544 ;
     RECT  0.084 62.544 0.227 62.568 ;
     RECT  0.06 62.568 0.227 62.736 ;
     RECT  0.084 62.736 0.227 62.76 ;
     RECT  0.06 62.76 0.227 62.88 ;
     RECT  0.084 62.88 0.227 62.904 ;
     RECT  0.06 62.904 0.227 63.072 ;
     RECT  0.084 63.072 0.227 63.096 ;
     RECT  0.06 63.096 0.227 63.216 ;
     RECT  0.084 63.216 0.227 63.24 ;
     RECT  0.06 63.24 0.227 63.36 ;
     RECT  0.084 63.36 0.227 63.384 ;
     RECT  0.06 63.384 0.227 63.552 ;
     RECT  0.084 63.552 0.227 63.576 ;
     RECT  0.06 63.576 0.227 63.696 ;
     RECT  0.084 63.696 0.227 63.72 ;
     RECT  0.06 63.72 0.227 63.84 ;
     RECT  0.084 63.84 0.227 63.864 ;
     RECT  0.06 63.864 0.227 64.032 ;
     RECT  0.084 64.032 0.227 64.056 ;
     RECT  0.06 64.056 0.227 64.176 ;
     RECT  0.084 64.176 0.227 64.2 ;
     RECT  0.06 64.2 0.227 64.32 ;
     RECT  0.084 64.32 0.227 64.344 ;
     RECT  0.06 64.344 0.227 64.512 ;
     RECT  0.084 64.512 0.227 64.536 ;
     RECT  0.06 64.536 0.227 64.656 ;
     RECT  0.084 64.656 0.227 64.68 ;
     RECT  0.06 64.68 0.227 64.8 ;
     RECT  0.084 64.8 0.227 64.824 ;
     RECT  0.06 64.824 0.227 64.992 ;
     RECT  0.084 64.992 0.227 65.016 ;
     RECT  0.06 65.016 0.227 65.136 ;
     RECT  0.084 65.136 0.227 65.16 ;
     RECT  0.06 65.16 0.227 65.28 ;
     RECT  0.084 65.28 0.227 65.304 ;
     RECT  0.06 65.304 0.227 65.472 ;
     RECT  0.084 65.472 0.227 65.496 ;
     RECT  0.06 65.496 0.227 65.616 ;
     RECT  0.084 65.616 0.227 65.64 ;
     RECT  0.06 65.64 0.227 65.76 ;
     RECT  0.084 65.76 0.227 65.784 ;
     RECT  0.06 65.784 0.227 65.952 ;
     RECT  0.084 65.952 0.227 65.976 ;
     RECT  0.06 65.976 0.227 66.096 ;
     RECT  0.084 66.096 0.227 66.12 ;
     RECT  0.06 66.12 0.227 66.24 ;
     RECT  0.084 66.24 0.227 66.264 ;
     RECT  0.06 66.264 0.227 66.432 ;
     RECT  0.084 66.432 0.227 66.456 ;
     RECT  0.06 66.456 0.227 66.576 ;
     RECT  0.084 66.576 0.227 66.6 ;
     RECT  0.06 66.6 0.227 66.72 ;
     RECT  0.084 66.72 0.227 66.744 ;
     RECT  0.06 66.744 0.227 66.912 ;
     RECT  0.084 66.912 0.227 66.936 ;
     RECT  0.06 66.936 0.227 67.056 ;
     RECT  0.084 67.056 0.227 67.08 ;
     RECT  0.06 67.08 0.227 67.2 ;
     RECT  0.084 67.2 0.227 67.224 ;
     RECT  0.06 67.224 0.227 67.392 ;
     RECT  0.084 67.392 0.227 67.416 ;
     RECT  0.06 67.416 0.227 67.536 ;
     RECT  0.084 67.536 0.227 67.56 ;
     RECT  0.06 67.56 0.227 67.728 ;
     RECT  0.084 67.728 0.227 67.752 ;
     RECT  0.06 67.752 0.227 67.872 ;
     RECT  0.084 67.872 0.227 67.896 ;
     RECT  0.06 67.896 0.227 68.016 ;
     RECT  0.084 68.016 0.227 68.04 ;
     RECT  0.06 68.04 0.227 68.208 ;
     RECT  0.084 68.208 0.227 68.232 ;
     RECT  0.06 68.232 0.227 68.352 ;
     RECT  0.084 68.352 0.227 68.376 ;
     RECT  0.06 68.376 0.227 68.496 ;
     RECT  0.084 68.496 0.227 68.52 ;
     RECT  0.06 68.52 0.227 68.688 ;
     RECT  0.084 68.688 0.227 68.712 ;
     RECT  0.06 68.712 0.227 68.832 ;
     RECT  0.084 68.832 0.227 68.856 ;
     RECT  0.06 68.856 0.227 68.976 ;
     RECT  0.084 68.976 0.227 69 ;
     RECT  0.06 69 0.227 69.168 ;
     RECT  0.084 69.168 0.227 69.192 ;
     RECT  0.06 69.192 0.227 69.312 ;
     RECT  0.084 69.312 0.227 69.336 ;
     RECT  0.06 69.336 0.227 69.456 ;
     RECT  0.084 69.456 0.227 69.48 ;
     RECT  0.06 69.48 0.227 69.648 ;
     RECT  0.084 69.648 0.227 69.672 ;
     RECT  0.06 69.672 0.227 69.792 ;
     RECT  0.084 69.792 0.227 69.816 ;
     RECT  0.06 69.816 0.227 69.936 ;
     RECT  0.084 69.936 0.227 69.96 ;
     RECT  0.06 69.96 0.227 70.128 ;
     RECT  0.084 70.128 0.227 70.152 ;
     RECT  0.06 70.152 0.227 70.272 ;
     RECT  0.084 70.272 0.227 70.296 ;
     RECT  0.06 70.296 0.227 70.416 ;
     RECT  0.084 70.416 0.227 70.44 ;
     RECT  0.06 70.44 0.227 70.608 ;
     RECT  0.084 70.608 0.227 70.632 ;
     RECT  0.06 70.632 0.227 70.752 ;
     RECT  0.084 70.752 0.227 70.776 ;
     RECT  0.06 70.776 0.227 70.896 ;
     RECT  0.084 70.896 0.227 70.92 ;
     RECT  0.06 70.92 0.227 71.088 ;
     RECT  0.084 71.088 0.227 71.112 ;
     RECT  0.06 71.112 0.227 71.232 ;
     RECT  0.084 71.232 0.227 71.256 ;
     RECT  0.06 71.256 0.227 71.376 ;
     RECT  0.084 71.376 0.227 71.4 ;
     RECT  0.06 71.4 0.227 71.568 ;
     RECT  0.084 71.568 0.227 71.592 ;
     RECT  0.06 71.592 0.227 71.712 ;
     RECT  0.084 71.712 0.227 71.736 ;
     RECT  0.06 71.736 0.227 71.856 ;
     RECT  0.084 71.856 0.227 71.88 ;
     RECT  0.06 71.88 0.227 72.048 ;
     RECT  0.084 72.048 0.227 72.072 ;
     RECT  0.06 72.072 0.227 72.192 ;
     RECT  0.084 72.192 0.227 72.216 ;
     RECT  0.06 72.216 0.227 72.384 ;
     RECT  0.084 72.384 0.227 72.408 ;
     RECT  0.06 72.408 0.227 72.528 ;
     RECT  0.084 72.528 0.227 72.552 ;
     RECT  0.06 72.552 0.227 72.672 ;
     RECT  0.084 72.672 0.227 72.696 ;
     RECT  0.06 72.696 0.227 72.864 ;
     RECT  0.084 72.864 0.227 72.888 ;
     RECT  0.06 72.888 0.227 73.008 ;
     RECT  0.084 73.008 0.227 73.032 ;
     RECT  0.06 73.032 0.227 73.152 ;
     RECT  0.084 73.152 0.227 73.176 ;
     RECT  0.06 73.176 0.227 73.344 ;
     RECT  0.084 73.344 0.227 73.368 ;
     RECT  0.06 73.368 0.227 73.488 ;
     RECT  0.084 73.488 0.227 73.512 ;
     RECT  0.06 73.512 0.227 73.632 ;
     RECT  0.084 73.632 0.227 73.656 ;
     RECT  0.06 73.656 0.227 73.824 ;
     RECT  0.084 73.824 0.227 73.848 ;
     RECT  0.06 73.848 0.227 73.968 ;
     RECT  0.084 73.968 0.227 73.992 ;
     RECT  0.06 73.992 0.227 74.112 ;
     RECT  0.084 74.112 0.227 74.136 ;
     RECT  0.06 74.136 0.227 74.304 ;
     RECT  0.084 74.304 0.227 74.328 ;
     RECT  0.06 74.328 0.227 74.448 ;
     RECT  0.084 74.448 0.227 74.472 ;
     RECT  0.06 74.472 0.227 74.592 ;
     RECT  0.084 74.592 0.227 74.616 ;
     RECT  0.06 74.616 0.227 74.784 ;
     RECT  0.084 74.784 0.227 74.808 ;
     RECT  0.06 74.808 0.227 74.928 ;
     RECT  0.084 74.928 0.227 74.952 ;
     RECT  0.06 74.952 0.227 75.072 ;
     RECT  0.084 75.072 0.227 75.096 ;
     RECT  0.06 75.096 0.227 75.264 ;
     RECT  0.084 75.264 0.227 75.288 ;
     RECT  0.06 75.288 0.227 75.408 ;
     RECT  0.084 75.408 0.227 75.432 ;
     RECT  0.06 75.432 0.227 75.552 ;
     RECT  0.084 75.552 0.227 75.576 ;
     RECT  0.06 75.576 0.227 75.744 ;
     RECT  0.084 75.744 0.227 75.768 ;
     RECT  0.06 75.768 0.227 75.888 ;
     RECT  0.084 75.888 0.227 75.912 ;
     RECT  0.06 75.912 0.227 76.032 ;
     RECT  0.084 76.032 0.227 76.056 ;
     RECT  0.06 76.056 0.227 76.224 ;
     RECT  0.084 76.224 0.227 76.248 ;
     RECT  0.06 76.248 0.227 76.368 ;
     RECT  0.084 76.368 0.227 76.392 ;
     RECT  0.06 76.392 0.227 76.56 ;
     RECT  0.084 76.56 0.227 76.584 ;
     RECT  0.06 76.584 0.227 76.704 ;
     RECT  0.084 76.704 0.227 76.728 ;
     RECT  0.06 76.728 0.227 76.848 ;
     RECT  0.084 76.848 0.227 76.872 ;
     RECT  0.06 76.872 0.227 77.04 ;
     RECT  0.084 77.04 0.227 77.064 ;
     RECT  0.06 77.064 0.227 77.184 ;
     RECT  0.084 77.184 0.227 77.208 ;
     RECT  0.06 77.208 0.227 77.328 ;
     RECT  0.084 77.328 0.227 77.352 ;
     RECT  0.06 77.352 0.227 77.52 ;
     RECT  0.084 77.52 0.227 77.544 ;
     RECT  0.06 77.544 0.227 77.664 ;
     RECT  0.084 77.664 0.227 77.688 ;
     RECT  0.06 77.688 0.227 77.808 ;
     RECT  0.084 77.808 0.227 77.832 ;
     RECT  0.06 77.832 0.227 78 ;
     RECT  0.084 78 0.227 78.024 ;
     RECT  0.06 78.024 0.227 78.144 ;
     RECT  0.084 78.144 0.227 78.168 ;
     RECT  0.06 78.168 0.227 78.288 ;
     RECT  0.084 78.288 0.227 78.312 ;
     RECT  0.06 78.312 0.227 78.48 ;
     RECT  0.084 78.48 0.227 78.504 ;
     RECT  0.06 78.504 0.227 78.624 ;
     RECT  0.084 78.624 0.227 78.648 ;
     RECT  0.06 78.648 0.227 78.768 ;
     RECT  0.084 78.768 0.227 78.792 ;
     RECT  0.06 78.792 0.227 78.96 ;
     RECT  0.084 78.96 0.227 78.984 ;
     RECT  0.06 78.984 0.227 79.104 ;
     RECT  0.084 79.104 0.227 79.128 ;
     RECT  0.06 79.128 0.227 79.248 ;
     RECT  0.084 79.248 0.227 79.272 ;
     RECT  0.06 79.272 0.227 79.44 ;
     RECT  0.084 79.44 0.227 79.464 ;
     RECT  0.06 79.464 0.227 79.584 ;
     RECT  0.084 79.584 0.227 79.608 ;
     RECT  0.06 79.608 0.227 79.728 ;
     RECT  0.084 79.728 0.227 79.752 ;
     RECT  0.06 79.752 0.227 79.92 ;
     RECT  0.084 79.92 0.227 79.944 ;
     RECT  0.06 79.944 0.227 80.064 ;
     RECT  0.084 80.064 0.227 80.088 ;
     RECT  0.06 80.088 0.227 80.208 ;
     RECT  0.084 80.208 0.227 80.232 ;
     RECT  0.06 80.232 0.227 80.4 ;
     RECT  0.084 80.4 0.227 80.424 ;
     RECT  0.06 80.424 0.227 80.544 ;
     RECT  0.084 80.544 0.227 80.568 ;
     RECT  0.06 80.568 0.227 80.688 ;
     RECT  0.084 80.688 0.227 80.712 ;
     RECT  0.06 80.712 0.227 80.88 ;
     RECT  0.084 80.88 0.227 80.904 ;
     RECT  0.06 80.904 0.227 81.024 ;
     RECT  0.084 81.024 0.227 81.048 ;
     RECT  0.06 81.048 0.227 81.216 ;
     RECT  0.084 81.216 0.227 81.24 ;
     RECT  0.06 81.24 0.227 81.36 ;
     RECT  0.084 81.36 0.227 81.384 ;
     RECT  0.06 81.384 0.227 81.504 ;
     RECT  0.084 81.504 0.227 81.528 ;
     RECT  0.06 81.528 0.227 81.696 ;
     RECT  0.084 81.696 0.227 81.72 ;
     RECT  0.06 81.72 0.227 81.84 ;
     RECT  0.084 81.84 0.227 81.864 ;
     RECT  0.06 81.864 0.227 81.984 ;
     RECT  0.084 81.984 0.227 82.008 ;
     RECT  0.06 82.008 0.227 82.176 ;
     RECT  0.084 82.176 0.227 82.2 ;
     RECT  0.06 82.2 0.227 82.32 ;
     RECT  0.084 82.32 0.227 82.344 ;
     RECT  0.06 82.344 0.227 82.464 ;
     RECT  0.084 82.464 0.227 82.488 ;
     RECT  0.06 82.488 0.227 82.656 ;
     RECT  0.084 82.656 0.227 82.68 ;
     RECT  0.06 82.68 0.227 82.8 ;
     RECT  0.084 82.8 0.227 82.824 ;
     RECT  0.06 82.824 0.227 82.944 ;
     RECT  0.084 82.944 0.227 82.968 ;
     RECT  0.06 82.968 0.227 83.136 ;
     RECT  0.084 83.136 0.227 83.16 ;
     RECT  0.06 83.16 0.227 83.28 ;
     RECT  0.084 83.28 0.227 83.304 ;
     RECT  0.06 83.304 0.227 83.424 ;
     RECT  0.084 83.424 0.227 83.448 ;
     RECT  0.06 83.448 0.227 83.616 ;
     RECT  0.084 83.616 0.227 83.64 ;
     RECT  0.06 83.64 0.227 83.76 ;
     RECT  0.084 83.76 0.227 83.784 ;
     RECT  0.06 83.784 0.227 83.904 ;
     RECT  0.084 83.904 0.227 83.928 ;
     RECT  0.06 83.928 0.227 84.096 ;
     RECT  0.084 84.096 0.227 84.12 ;
     RECT  0.06 84.12 0.227 84.24 ;
     RECT  0.084 84.24 0.227 84.264 ;
     RECT  0.06 84.264 0.227 84.384 ;
     RECT  0.084 84.384 0.227 84.408 ;
     RECT  0.06 84.408 0.227 84.576 ;
     RECT  0.084 84.576 0.227 84.6 ;
     RECT  0.06 84.6 0.227 84.72 ;
     RECT  0.084 84.72 0.227 84.744 ;
     RECT  0.06 84.744 0.227 84.864 ;
     RECT  0.084 84.864 0.227 84.888 ;
     RECT  0.06 84.888 0.227 85.056 ;
     RECT  0.084 85.056 0.227 85.08 ;
     RECT  0.06 85.08 0.227 85.2 ;
     RECT  0.084 85.2 0.227 85.224 ;
     RECT  0.06 85.224 0.227 85.344 ;
     RECT  0.084 85.344 0.227 85.368 ;
     RECT  0.06 85.368 0.227 85.536 ;
     RECT  0.084 85.536 0.227 85.56 ;
     RECT  0.06 85.56 0.227 85.68 ;
     RECT  0.084 85.68 0.227 85.704 ;
     RECT  0.06 85.704 0.227 85.872 ;
     RECT  0.084 85.872 0.227 85.896 ;
     RECT  0.06 85.896 0.227 86.016 ;
     RECT  0.084 86.016 0.227 86.04 ;
     RECT  0.06 86.04 0.227 86.16 ;
     RECT  0.084 86.16 0.227 86.184 ;
     RECT  0.06 86.184 0.227 86.352 ;
     RECT  0.084 86.352 0.227 86.376 ;
     RECT  0.06 86.376 0.227 86.496 ;
     RECT  0.084 86.496 0.227 86.52 ;
     RECT  0.06 86.52 0.227 86.64 ;
     RECT  0.084 86.64 0.227 86.664 ;
     RECT  0.06 86.664 0.227 86.832 ;
     RECT  0.084 86.832 0.227 86.856 ;
     RECT  0.06 86.856 0.227 86.976 ;
     RECT  0.084 86.976 0.227 87 ;
     RECT  0.06 87 0.227 87.12 ;
     RECT  0.084 87.12 0.227 87.144 ;
     RECT  0.06 87.144 0.227 87.312 ;
     RECT  0.084 87.312 0.227 87.336 ;
     RECT  0.06 87.336 0.227 87.456 ;
     RECT  0.084 87.456 0.227 87.48 ;
     RECT  0.06 87.48 0.227 87.6 ;
     RECT  0.084 87.6 0.227 87.624 ;
     RECT  0.06 87.624 0.227 87.792 ;
     RECT  0.084 87.792 0.227 87.816 ;
     RECT  0.06 87.816 0.227 87.936 ;
     RECT  0.084 87.936 0.227 87.96 ;
     RECT  0.06 87.96 0.227 88.08 ;
     RECT  0.084 88.08 0.227 88.104 ;
     RECT  0.06 88.104 0.227 88.272 ;
     RECT  0.084 88.272 0.227 88.296 ;
     RECT  0.06 88.296 0.227 88.416 ;
     RECT  0.084 88.416 0.227 88.44 ;
     RECT  0.06 88.44 0.227 88.56 ;
     RECT  0.084 88.56 0.227 88.584 ;
     RECT  0.06 88.584 0.227 88.752 ;
     RECT  0.084 88.752 0.227 88.776 ;
     RECT  0.06 88.776 0.227 88.896 ;
     RECT  0.084 88.896 0.227 88.92 ;
     RECT  0.06 88.92 0.227 89.04 ;
     RECT  0.084 89.04 0.227 89.064 ;
     RECT  0.06 89.064 0.227 89.232 ;
     RECT  0.084 89.232 0.227 89.256 ;
     RECT  0.06 89.256 0.227 89.376 ;
     RECT  0.084 89.376 0.227 89.4 ;
     RECT  0.06 89.4 0.227 89.52 ;
     RECT  0.084 89.52 0.227 89.544 ;
     RECT  0.06 89.544 0.227 89.712 ;
     RECT  0.084 89.712 0.227 89.736 ;
     RECT  0.06 89.736 0.227 89.856 ;
     RECT  0.084 89.856 0.227 89.88 ;
     RECT  0.06 89.88 0.227 90.048 ;
     RECT  0.084 90.048 0.227 90.072 ;
     RECT  0.06 90.072 0.227 90.192 ;
     RECT  0.084 90.192 0.227 90.216 ;
     RECT  0.06 90.216 0.227 90.336 ;
     RECT  0.084 90.336 0.227 90.36 ;
     RECT  0.06 90.36 0.227 90.528 ;
     RECT  0.084 90.528 0.227 90.552 ;
     RECT  0.06 90.552 0.227 90.672 ;
     RECT  0.084 90.672 0.227 90.696 ;
     RECT  0.06 90.696 0.227 90.816 ;
     RECT  0.084 90.816 0.227 90.84 ;
     RECT  0.06 90.84 0.227 91.008 ;
     RECT  0.084 91.008 0.227 91.032 ;
     RECT  0.06 91.032 0.227 91.152 ;
     RECT  0.084 91.152 0.227 91.176 ;
     RECT  0.06 91.176 0.227 92.112 ;
     RECT  0.084 92.112 0.227 92.136 ;
     RECT  0.227 1.056 2.333 91.176 ;
     RECT  2.333 1.248 2.408 91.176 ;
     RECT  2.408 1.248 2.512 92.892 ;
     RECT  2.512 1.248 2.704 92.622 ;
     RECT  2.704 35.28 2.729 91.176 ;
     RECT  2.704 1.248 2.765 22.776 ;
     RECT  2.704 24.624 2.765 34.152 ;
     RECT  2.729 78.48 2.765 91.176 ;
     RECT  2.765 1.248 2.801 11.928 ;
     RECT  2.765 24.624 2.801 31.896 ;
     RECT  2.801 1.248 2.819 10.44 ;
     RECT  2.819 1.248 2.837 10.392 ;
     RECT  2.801 24.624 2.837 27.912 ;
     RECT  2.765 33.024 2.837 34.152 ;
     RECT  2.765 78.48 2.837 88.92 ;
     RECT  2.765 13.392 3.251 21.72 ;
     RECT  2.729 35.28 3.377 77.304 ;
     RECT  3.377 35.28 3.395 48.504 ;
     RECT  2.837 85.92 3.436 88.248 ;
     RECT  3.251 20.304 3.449 21.72 ;
     RECT  3.377 49.584 3.484 77.304 ;
     RECT  3.449 20.4 3.485 21.72 ;
     RECT  3.395 42.192 3.521 48.504 ;
     RECT  2.837 24.624 3.593 26.136 ;
     RECT  2.765 22.752 3.697 22.776 ;
     RECT  3.484 67.536 3.841 77.304 ;
     RECT  2.837 78.48 3.841 81.72 ;
     RECT  2.801 28.992 3.868 31.896 ;
     RECT  3.395 35.28 3.881 41.16 ;
     RECT  3.841 67.536 3.881 81.72 ;
     RECT  3.881 73.824 3.913 81.72 ;
     RECT  2.837 82.944 3.913 84.888 ;
     RECT  3.251 13.392 3.917 19.128 ;
     RECT  3.868 28.992 3.917 30.648 ;
     RECT  2.801 11.52 3.925 11.928 ;
     RECT  3.917 13.392 3.925 14.376 ;
     RECT  3.697 22.752 3.949 23.16 ;
     RECT  2.765 90 3.949 91.176 ;
     RECT  3.521 45.648 4.019 48.504 ;
     RECT  3.925 11.52 4.025 14.376 ;
     RECT  3.593 24.624 4.061 24.648 ;
     RECT  3.484 49.584 4.061 66.216 ;
     RECT  3.436 86.064 4.097 88.248 ;
     RECT  3.593 25.68 4.117 26.136 ;
     RECT  2.837 27.12 4.117 27.912 ;
     RECT  3.917 28.992 4.133 29.784 ;
     RECT  3.949 89.808 4.133 91.176 ;
     RECT  3.868 31.776 4.201 31.896 ;
     RECT  4.117 25.68 4.309 27.912 ;
     RECT  2.837 1.248 4.349 10.344 ;
     RECT  3.949 22.752 4.381 23.304 ;
     RECT  4.309 24.384 4.381 24.408 ;
     RECT  4.019 46.224 4.405 48.504 ;
     RECT  4.061 49.584 4.405 60.12 ;
     RECT  3.917 15.744 4.453 19.128 ;
     RECT  3.521 42.192 4.489 44.568 ;
     RECT  4.201 31.776 4.501 32.472 ;
     RECT  2.837 33.552 4.501 34.152 ;
     RECT  4.349 1.872 4.525 10.344 ;
     RECT  3.881 39.744 4.525 41.16 ;
     RECT  4.489 42.192 4.525 45.048 ;
     RECT  4.097 86.736 4.525 88.248 ;
     RECT  4.061 61.104 4.561 66.216 ;
     RECT  4.453 15.744 4.597 19.992 ;
     RECT  4.525 1.872 4.673 10.872 ;
     RECT  4.133 29.568 4.885 29.784 ;
     RECT  4.525 86.736 4.921 88.392 ;
     RECT  4.561 61.104 4.981 66.36 ;
     RECT  3.881 67.536 4.981 72.744 ;
     RECT  4.673 2.148 5.108 10.872 ;
     RECT  4.025 12.48 5.108 14.376 ;
     RECT  4.597 15.744 5.108 20.136 ;
     RECT  3.485 21.216 5.108 21.72 ;
     RECT  4.381 22.752 5.108 24.408 ;
     RECT  4.309 25.68 5.108 28.44 ;
     RECT  4.885 29.568 5.108 30.408 ;
     RECT  4.501 31.776 5.108 34.152 ;
     RECT  3.881 35.28 5.108 38.76 ;
     RECT  4.525 39.744 5.108 45.048 ;
     RECT  4.405 46.224 5.108 60.12 ;
     RECT  4.981 61.104 5.108 72.744 ;
     RECT  3.913 73.824 5.108 84.888 ;
     RECT  4.921 86.736 5.108 88.728 ;
     RECT  4.133 90 5.108 91.176 ;
     RECT  5.108 2.148 5.212 92.892 ;
     RECT  5.212 2.256 5.404 92.622 ;
     RECT  5.404 87.84 5.537 90.84 ;
     RECT  5.537 87.84 5.645 90.264 ;
     RECT  5.404 50.112 5.681 55.176 ;
     RECT  5.404 34.896 5.699 48.696 ;
     RECT  5.681 50.112 5.747 52.824 ;
     RECT  5.404 71.088 5.753 86.808 ;
     RECT  5.404 2.256 5.789 12.6 ;
     RECT  5.681 54.096 6.005 55.176 ;
     RECT  5.404 56.256 6.113 65.112 ;
     RECT  5.404 13.632 6.421 14.472 ;
     RECT  5.404 15.456 6.421 33.672 ;
     RECT  6.397 92.352 6.505 92.376 ;
     RECT  5.753 79.536 6.541 86.808 ;
     RECT  5.645 87.84 6.541 89.88 ;
     RECT  6.505 91.968 6.613 92.376 ;
     RECT  6.541 79.536 6.617 89.88 ;
     RECT  5.789 2.784 6.649 12.6 ;
     RECT  6.421 13.584 6.649 33.672 ;
     RECT  6.005 54.096 6.649 55.128 ;
     RECT  6.617 87.408 6.659 89.88 ;
     RECT  6.613 91.152 6.659 92.376 ;
     RECT  6.649 2.784 6.685 33.672 ;
     RECT  5.699 34.896 6.685 37.656 ;
     RECT  5.699 38.784 6.685 48.696 ;
     RECT  5.404 69.984 6.721 70.104 ;
     RECT  5.753 71.088 6.721 78.504 ;
     RECT  5.404 66.24 6.805 69 ;
     RECT  6.721 69.984 6.805 78.504 ;
     RECT  6.805 66.24 6.829 78.504 ;
     RECT  6.617 79.536 6.829 86.424 ;
     RECT  6.829 66.24 6.865 86.424 ;
     RECT  6.685 38.784 7.009 48.984 ;
     RECT  5.747 50.112 7.009 52.584 ;
     RECT  6.685 2.784 7.045 37.656 ;
     RECT  6.659 91.152 7.045 91.992 ;
     RECT  6.649 53.568 7.081 55.128 ;
     RECT  6.113 64.944 7.117 65.112 ;
     RECT  6.865 66.096 7.117 86.424 ;
     RECT  7.045 2.256 7.189 37.656 ;
     RECT  7.009 38.784 7.189 52.584 ;
     RECT  7.189 2.256 7.225 52.584 ;
     RECT  7.081 53.568 7.225 55.272 ;
     RECT  6.113 56.256 7.477 63.912 ;
     RECT  7.117 64.944 7.477 86.424 ;
     RECT  7.225 2.256 7.513 55.272 ;
     RECT  7.477 56.256 7.513 86.424 ;
     RECT  6.659 87.792 7.621 89.208 ;
     RECT  7.045 90.576 7.621 91.992 ;
     RECT  7.513 2.256 7.657 86.424 ;
     RECT  7.621 87.792 7.657 91.992 ;
     RECT  7.657 2.256 7.693 91.992 ;
     RECT  7.693 2.256 7.808 92.184 ;
     RECT  7.808 2.148 7.912 92.892 ;
     RECT  7.912 2.256 8.104 92.622 ;
     RECT  8.104 2.256 8.381 92.52 ;
     RECT  8.381 2.352 9.173 92.52 ;
     RECT  9.173 2.352 10.285 92.424 ;
     RECT  10.285 1.728 10.508 92.424 ;
     RECT  10.508 1.728 10.612 92.892 ;
     RECT  10.612 1.728 10.804 92.856 ;
     RECT  10.804 92.688 11.477 92.856 ;
     RECT  10.804 1.728 12.769 91.656 ;
     RECT  11.477 92.688 12.769 92.712 ;
     RECT  12.769 1.728 13.208 92.712 ;
     RECT  13.208 1.728 13.312 92.892 ;
     RECT  13.312 1.728 14.069 92.76 ;
     RECT  14.069 1.728 14.675 92.616 ;
     RECT  14.675 92.352 14.819 92.616 ;
     RECT  14.819 92.448 14.825 92.616 ;
     RECT  14.675 1.728 15.757 91.128 ;
     RECT  15.757 1.728 15.908 91.176 ;
     RECT  14.825 92.448 15.908 92.568 ;
     RECT  15.908 1.728 16.012 92.892 ;
     RECT  16.012 1.728 16.204 92.622 ;
     RECT  16.204 92.256 16.355 92.472 ;
     RECT  16.355 92.448 16.589 92.472 ;
     RECT  16.204 1.728 18.277 91.176 ;
     RECT  18.277 1.728 18.608 91.704 ;
     RECT  18.608 1.728 18.712 92.892 ;
     RECT  18.712 1.728 18.904 92.622 ;
     RECT  18.904 1.728 19.397 92.28 ;
     RECT  19.397 1.728 20.797 91.128 ;
     RECT  20.797 1.728 20.828 91.176 ;
     RECT  19.397 92.256 20.828 92.28 ;
     RECT  20.828 1.728 21.308 92.28 ;
     RECT  21.308 1.728 21.412 92.892 ;
     RECT  21.412 1.728 21.604 92.622 ;
     RECT  21.604 1.728 22.067 92.568 ;
     RECT  22.067 46.56 23.033 92.568 ;
     RECT  22.067 1.728 23.317 45.576 ;
     RECT  23.033 46.56 23.317 92.376 ;
     RECT  23.317 1.728 24.008 92.376 ;
     RECT  24.008 1.728 24.112 92.892 ;
     RECT  24.112 1.728 24.304 92.622 ;
     RECT  24.304 1.728 24.649 92.328 ;
     RECT  24.649 1.248 26.708 92.328 ;
     RECT  26.708 1.248 26.812 92.892 ;
     RECT  26.812 1.248 27.004 92.622 ;
     RECT  27.004 1.248 27.929 92.232 ;
     RECT  27.929 1.248 28.289 91.176 ;
     RECT  28.289 66 28.897 91.176 ;
     RECT  27.929 92.208 28.897 92.232 ;
     RECT  28.897 66 29.401 92.232 ;
     RECT  28.289 1.248 29.408 64.968 ;
     RECT  29.401 66 29.408 92.424 ;
     RECT  29.408 1.248 29.512 92.892 ;
     RECT  29.512 1.248 29.704 92.622 ;
     RECT  29.704 1.248 30.481 92.424 ;
     RECT  30.481 1.056 32.108 92.424 ;
     RECT  32.108 1.056 32.212 92.892 ;
     RECT  32.212 1.056 32.404 92.622 ;
     RECT  32.404 1.056 33.577 92.376 ;
     RECT  33.577 1.056 34.808 92.616 ;
     RECT  34.808 1.056 34.912 92.892 ;
     RECT  34.912 1.056 35.104 92.622 ;
     RECT  35.104 1.056 35.129 92.232 ;
     RECT  35.129 26.304 35.237 92.232 ;
     RECT  35.237 37.632 35.267 92.232 ;
     RECT  35.237 26.304 35.345 36.648 ;
     RECT  35.267 37.632 35.345 91.176 ;
     RECT  35.129 1.056 35.417 25.32 ;
     RECT  35.345 65.712 35.489 91.176 ;
     RECT  35.489 65.808 35.561 91.176 ;
     RECT  35.561 65.904 35.633 91.176 ;
     RECT  35.345 37.632 35.669 64.68 ;
     RECT  35.633 76.224 35.741 91.176 ;
     RECT  35.417 1.056 35.813 11.784 ;
     RECT  35.633 65.904 35.849 75.24 ;
     RECT  35.849 65.904 35.885 72.792 ;
     RECT  35.741 85.776 35.885 91.176 ;
     RECT  35.813 10.128 35.957 11.784 ;
     RECT  35.813 1.056 35.993 9 ;
     RECT  35.669 37.68 36.173 64.68 ;
     RECT  35.849 73.824 36.961 75.24 ;
     RECT  35.741 76.224 36.961 84.6 ;
     RECT  35.993 1.056 36.997 7.176 ;
     RECT  35.993 8.496 36.997 9 ;
     RECT  35.957 10.128 36.997 11.736 ;
     RECT  35.417 12.816 36.997 25.32 ;
     RECT  35.345 26.64 36.997 36.648 ;
     RECT  36.173 37.68 37.537 45.576 ;
     RECT  36.173 46.56 37.537 64.68 ;
     RECT  36.961 73.824 37.537 84.6 ;
     RECT  35.885 85.776 37.537 91.128 ;
     RECT  36.997 26.448 37.573 36.648 ;
     RECT  37.537 37.68 37.573 64.68 ;
     RECT  35.885 66 37.573 72.792 ;
     RECT  36.997 1.056 38.077 25.32 ;
     RECT  37.573 26.448 38.077 72.792 ;
     RECT  38.077 1.056 38.185 72.792 ;
     RECT  37.537 73.824 38.185 91.128 ;
     RECT  38.185 1.056 38.617 91.128 ;
     RECT  38.617 1.056 38.761 91.176 ;
     RECT  35.267 92.208 38.761 92.232 ;
     RECT  38.761 1.056 38.796 1.08 ;
     RECT  38.761 1.08 38.801 1.248 ;
     RECT  38.761 1.248 38.796 1.272 ;
     RECT  38.761 1.272 38.801 1.392 ;
     RECT  38.761 1.392 38.796 1.416 ;
     RECT  38.761 1.416 38.801 1.536 ;
     RECT  38.761 1.536 38.796 1.56 ;
     RECT  38.761 1.56 38.801 1.728 ;
     RECT  38.761 1.728 38.796 1.752 ;
     RECT  38.761 1.752 38.801 1.872 ;
     RECT  38.761 1.872 38.796 1.896 ;
     RECT  38.761 1.896 38.801 2.016 ;
     RECT  38.761 2.016 38.796 2.04 ;
     RECT  38.761 2.04 38.801 2.208 ;
     RECT  38.761 2.208 38.796 2.232 ;
     RECT  38.761 2.232 38.801 2.352 ;
     RECT  38.761 2.352 38.796 2.376 ;
     RECT  38.761 2.376 38.801 2.496 ;
     RECT  38.761 2.496 38.796 2.52 ;
     RECT  38.761 2.52 38.801 2.688 ;
     RECT  38.761 2.688 38.796 2.712 ;
     RECT  38.761 2.712 38.801 2.832 ;
     RECT  38.761 2.832 38.796 2.856 ;
     RECT  38.761 2.856 38.801 2.976 ;
     RECT  38.761 2.976 38.796 3 ;
     RECT  38.761 3 38.801 3.168 ;
     RECT  38.761 3.168 38.796 3.192 ;
     RECT  38.761 3.192 38.801 3.312 ;
     RECT  38.761 3.312 38.796 3.336 ;
     RECT  38.761 3.336 38.801 3.456 ;
     RECT  38.761 3.456 38.796 3.48 ;
     RECT  38.761 3.48 38.801 3.648 ;
     RECT  38.761 3.648 38.796 3.672 ;
     RECT  38.761 3.672 38.801 3.792 ;
     RECT  38.761 3.792 38.796 3.816 ;
     RECT  38.761 3.816 38.801 3.936 ;
     RECT  38.761 3.936 38.796 3.96 ;
     RECT  38.761 3.96 38.801 4.128 ;
     RECT  38.761 4.128 38.796 4.152 ;
     RECT  38.761 4.152 38.801 4.272 ;
     RECT  38.761 4.272 38.796 4.296 ;
     RECT  38.761 4.296 38.801 4.464 ;
     RECT  38.761 4.464 38.796 4.488 ;
     RECT  38.761 4.488 38.801 4.608 ;
     RECT  38.761 4.608 38.796 4.632 ;
     RECT  38.761 4.632 38.801 4.752 ;
     RECT  38.761 4.752 38.796 4.776 ;
     RECT  38.761 4.776 38.801 4.944 ;
     RECT  38.761 4.944 38.796 4.968 ;
     RECT  38.761 4.968 38.801 5.088 ;
     RECT  38.761 5.088 38.796 5.112 ;
     RECT  38.761 5.112 38.801 5.232 ;
     RECT  38.761 5.232 38.796 5.256 ;
     RECT  38.761 5.256 38.801 5.424 ;
     RECT  38.761 5.424 38.796 5.448 ;
     RECT  38.761 5.448 38.801 5.568 ;
     RECT  38.761 5.568 38.796 5.592 ;
     RECT  38.761 5.592 38.801 5.712 ;
     RECT  38.761 5.712 38.796 5.736 ;
     RECT  38.761 5.736 38.801 5.904 ;
     RECT  38.761 5.904 38.796 5.928 ;
     RECT  38.761 5.928 38.801 6.048 ;
     RECT  38.761 6.048 38.796 6.072 ;
     RECT  38.761 6.072 38.801 6.192 ;
     RECT  38.761 6.192 38.796 6.216 ;
     RECT  38.761 6.216 38.801 6.384 ;
     RECT  38.761 6.384 38.796 6.408 ;
     RECT  38.761 6.408 38.801 6.528 ;
     RECT  38.761 6.528 38.796 6.552 ;
     RECT  38.761 6.552 38.801 6.672 ;
     RECT  38.761 6.672 38.796 6.696 ;
     RECT  38.761 6.696 38.801 6.864 ;
     RECT  38.761 6.864 38.796 6.888 ;
     RECT  38.761 6.888 38.801 7.008 ;
     RECT  38.761 7.008 38.796 7.032 ;
     RECT  38.761 7.032 38.801 7.152 ;
     RECT  38.761 7.152 38.796 7.176 ;
     RECT  38.761 7.176 38.801 7.344 ;
     RECT  38.761 7.344 38.796 7.368 ;
     RECT  38.761 7.368 38.801 7.488 ;
     RECT  38.761 7.488 38.796 7.512 ;
     RECT  38.761 7.512 38.801 7.632 ;
     RECT  38.761 7.632 38.796 7.656 ;
     RECT  38.761 7.656 38.801 7.824 ;
     RECT  38.761 7.824 38.796 7.848 ;
     RECT  38.761 7.848 38.801 7.968 ;
     RECT  38.761 7.968 38.796 7.992 ;
     RECT  38.761 7.992 38.801 8.112 ;
     RECT  38.761 8.112 38.796 8.136 ;
     RECT  38.761 8.136 38.801 8.304 ;
     RECT  38.761 8.304 38.796 8.328 ;
     RECT  38.761 8.328 38.801 8.448 ;
     RECT  38.761 8.448 38.796 8.472 ;
     RECT  38.761 8.472 38.801 8.592 ;
     RECT  38.761 8.592 38.796 8.616 ;
     RECT  38.761 8.616 38.801 8.784 ;
     RECT  38.761 8.784 38.796 8.808 ;
     RECT  38.761 8.808 38.801 8.928 ;
     RECT  38.761 8.928 38.796 8.952 ;
     RECT  38.761 8.952 38.801 9.12 ;
     RECT  38.761 9.12 38.796 9.144 ;
     RECT  38.761 9.144 38.801 9.264 ;
     RECT  38.761 9.264 38.796 9.288 ;
     RECT  38.761 9.288 38.801 9.408 ;
     RECT  38.761 9.408 38.796 9.432 ;
     RECT  38.761 9.432 38.801 9.6 ;
     RECT  38.761 9.6 38.796 9.624 ;
     RECT  38.761 9.624 38.801 9.744 ;
     RECT  38.761 9.744 38.796 9.768 ;
     RECT  38.761 9.768 38.801 9.888 ;
     RECT  38.761 9.888 38.796 9.912 ;
     RECT  38.761 9.912 38.801 10.08 ;
     RECT  38.761 10.08 38.796 10.104 ;
     RECT  38.761 10.104 38.801 10.224 ;
     RECT  38.761 10.224 38.796 10.248 ;
     RECT  38.761 10.248 38.801 10.368 ;
     RECT  38.761 10.368 38.796 10.392 ;
     RECT  38.761 10.392 38.801 10.56 ;
     RECT  38.761 10.56 38.796 10.584 ;
     RECT  38.761 10.584 38.801 10.704 ;
     RECT  38.761 10.704 38.796 10.728 ;
     RECT  38.761 10.728 38.801 10.848 ;
     RECT  38.761 10.848 38.796 10.872 ;
     RECT  38.761 10.872 38.801 11.04 ;
     RECT  38.761 11.04 38.796 11.064 ;
     RECT  38.761 11.064 38.801 11.184 ;
     RECT  38.761 11.184 38.796 11.208 ;
     RECT  38.761 11.208 38.801 11.328 ;
     RECT  38.761 11.328 38.796 11.352 ;
     RECT  38.761 11.352 38.801 11.52 ;
     RECT  38.761 11.52 38.796 11.544 ;
     RECT  38.761 11.544 38.801 11.664 ;
     RECT  38.761 11.664 38.796 11.688 ;
     RECT  38.761 11.688 38.801 11.808 ;
     RECT  38.761 11.808 38.796 11.832 ;
     RECT  38.761 11.832 38.801 12 ;
     RECT  38.761 12 38.796 12.024 ;
     RECT  38.761 12.024 38.801 12.144 ;
     RECT  38.761 12.144 38.796 12.168 ;
     RECT  38.761 12.168 38.801 12.288 ;
     RECT  38.761 12.288 38.796 12.312 ;
     RECT  38.761 12.312 38.801 12.48 ;
     RECT  38.761 12.48 38.796 12.504 ;
     RECT  38.761 12.504 38.801 12.624 ;
     RECT  38.761 12.624 38.796 12.648 ;
     RECT  38.761 12.648 38.801 12.768 ;
     RECT  38.761 12.768 38.796 12.792 ;
     RECT  38.761 12.792 38.801 12.96 ;
     RECT  38.761 12.96 38.796 12.984 ;
     RECT  38.761 12.984 38.801 13.104 ;
     RECT  38.761 13.104 38.796 13.128 ;
     RECT  38.761 13.128 38.801 13.296 ;
     RECT  38.761 13.296 38.796 13.32 ;
     RECT  38.761 13.32 38.801 13.44 ;
     RECT  38.761 13.44 38.796 13.464 ;
     RECT  38.761 13.464 38.801 13.584 ;
     RECT  38.761 13.584 38.796 13.608 ;
     RECT  38.761 13.608 38.801 13.776 ;
     RECT  38.761 13.776 38.796 13.8 ;
     RECT  38.761 13.8 38.801 13.92 ;
     RECT  38.761 13.92 38.796 13.944 ;
     RECT  38.761 13.944 38.801 14.064 ;
     RECT  38.761 14.064 38.796 14.088 ;
     RECT  38.761 14.088 38.801 14.256 ;
     RECT  38.761 14.256 38.796 14.28 ;
     RECT  38.761 14.28 38.801 14.4 ;
     RECT  38.761 14.4 38.796 14.424 ;
     RECT  38.761 14.424 38.801 14.544 ;
     RECT  38.761 14.544 38.796 14.568 ;
     RECT  38.761 14.568 38.801 14.736 ;
     RECT  38.761 14.736 38.796 14.76 ;
     RECT  38.761 14.76 38.801 14.88 ;
     RECT  38.761 14.88 38.796 14.904 ;
     RECT  38.761 14.904 38.801 15.024 ;
     RECT  38.761 15.024 38.796 15.048 ;
     RECT  38.761 15.048 38.801 15.216 ;
     RECT  38.761 15.216 38.796 15.24 ;
     RECT  38.761 15.24 38.801 15.36 ;
     RECT  38.761 15.36 38.796 15.384 ;
     RECT  38.761 15.384 38.801 15.504 ;
     RECT  38.761 15.504 38.796 15.528 ;
     RECT  38.761 15.528 38.801 15.696 ;
     RECT  38.761 15.696 38.796 15.72 ;
     RECT  38.761 15.72 38.801 15.84 ;
     RECT  38.761 15.84 38.796 15.864 ;
     RECT  38.761 15.864 38.801 15.984 ;
     RECT  38.761 15.984 38.796 16.008 ;
     RECT  38.761 16.008 38.801 16.176 ;
     RECT  38.761 16.176 38.796 16.2 ;
     RECT  38.761 16.2 38.801 16.32 ;
     RECT  38.761 16.32 38.796 16.344 ;
     RECT  38.761 16.344 38.801 16.464 ;
     RECT  38.761 16.464 38.796 16.488 ;
     RECT  38.761 16.488 38.801 16.656 ;
     RECT  38.761 16.656 38.796 16.68 ;
     RECT  38.761 16.68 38.801 16.8 ;
     RECT  38.761 16.8 38.796 16.824 ;
     RECT  38.761 16.824 38.801 16.944 ;
     RECT  38.761 16.944 38.796 16.968 ;
     RECT  38.761 16.968 38.801 17.136 ;
     RECT  38.761 17.136 38.796 17.16 ;
     RECT  38.761 17.16 38.801 17.28 ;
     RECT  38.761 17.28 38.796 17.304 ;
     RECT  38.761 17.304 38.801 17.424 ;
     RECT  38.761 17.424 38.796 17.448 ;
     RECT  38.761 17.448 38.801 17.616 ;
     RECT  38.761 17.616 38.796 17.64 ;
     RECT  38.761 17.64 38.801 17.76 ;
     RECT  38.761 17.76 38.796 17.784 ;
     RECT  38.761 17.784 38.801 17.952 ;
     RECT  38.761 17.952 38.796 17.976 ;
     RECT  38.761 17.976 38.801 18.096 ;
     RECT  38.761 18.096 38.796 18.12 ;
     RECT  38.761 18.12 38.801 18.24 ;
     RECT  38.761 18.24 38.796 18.264 ;
     RECT  38.761 18.264 38.801 18.432 ;
     RECT  38.761 18.432 38.796 18.456 ;
     RECT  38.761 18.456 38.801 18.576 ;
     RECT  38.761 18.576 38.796 18.6 ;
     RECT  38.761 18.6 38.801 18.72 ;
     RECT  38.761 18.72 38.796 18.744 ;
     RECT  38.761 18.744 38.801 18.912 ;
     RECT  38.761 18.912 38.796 18.936 ;
     RECT  38.761 18.936 38.801 19.056 ;
     RECT  38.761 19.056 38.796 19.08 ;
     RECT  38.761 19.08 38.801 19.2 ;
     RECT  38.761 19.2 38.796 19.224 ;
     RECT  38.761 19.224 38.801 19.392 ;
     RECT  38.761 19.392 38.796 19.416 ;
     RECT  38.761 19.416 38.801 19.536 ;
     RECT  38.761 19.536 38.796 19.56 ;
     RECT  38.761 19.56 38.801 19.68 ;
     RECT  38.761 19.68 38.796 19.704 ;
     RECT  38.761 19.704 38.801 19.872 ;
     RECT  38.761 19.872 38.796 19.896 ;
     RECT  38.761 19.896 38.801 20.016 ;
     RECT  38.761 20.016 38.796 20.04 ;
     RECT  38.761 20.04 38.801 20.16 ;
     RECT  38.761 20.16 38.796 20.184 ;
     RECT  38.761 20.184 38.801 20.352 ;
     RECT  38.761 20.352 38.796 20.376 ;
     RECT  38.761 20.376 38.801 20.496 ;
     RECT  38.761 20.496 38.796 20.52 ;
     RECT  38.761 20.52 38.801 20.64 ;
     RECT  38.761 20.64 38.796 20.664 ;
     RECT  38.761 20.664 38.801 20.832 ;
     RECT  38.761 20.832 38.796 20.856 ;
     RECT  38.761 20.856 38.801 20.976 ;
     RECT  38.761 20.976 38.796 21 ;
     RECT  38.761 21 38.801 21.12 ;
     RECT  38.761 21.12 38.796 21.144 ;
     RECT  38.761 21.144 38.801 21.312 ;
     RECT  38.761 21.312 38.796 21.336 ;
     RECT  38.761 21.336 38.801 21.456 ;
     RECT  38.761 21.456 38.796 21.48 ;
     RECT  38.761 21.48 38.801 21.6 ;
     RECT  38.761 21.6 38.796 21.624 ;
     RECT  38.761 21.624 38.801 21.792 ;
     RECT  38.761 21.792 38.796 21.816 ;
     RECT  38.761 21.816 38.801 21.936 ;
     RECT  38.761 21.936 38.796 21.96 ;
     RECT  38.761 21.96 38.801 22.08 ;
     RECT  38.761 22.08 38.796 22.104 ;
     RECT  38.761 22.104 38.801 22.272 ;
     RECT  38.761 22.272 38.796 22.296 ;
     RECT  38.761 22.296 38.801 22.416 ;
     RECT  38.761 22.416 38.796 22.44 ;
     RECT  38.761 22.44 38.801 22.608 ;
     RECT  38.761 22.608 38.796 22.632 ;
     RECT  38.761 22.632 38.801 22.752 ;
     RECT  38.761 22.752 38.796 22.776 ;
     RECT  38.761 22.776 38.801 22.896 ;
     RECT  38.761 22.896 38.796 22.92 ;
     RECT  38.761 22.92 38.801 23.088 ;
     RECT  38.761 23.088 38.796 23.112 ;
     RECT  38.761 23.112 38.801 23.232 ;
     RECT  38.761 23.232 38.796 23.256 ;
     RECT  38.761 23.256 38.801 23.376 ;
     RECT  38.761 23.376 38.796 23.4 ;
     RECT  38.761 23.4 38.801 23.568 ;
     RECT  38.761 23.568 38.796 23.592 ;
     RECT  38.761 23.592 38.801 23.712 ;
     RECT  38.761 23.712 38.796 23.736 ;
     RECT  38.761 23.736 38.801 23.856 ;
     RECT  38.761 23.856 38.796 23.88 ;
     RECT  38.761 23.88 38.801 24.048 ;
     RECT  38.761 24.048 38.796 24.072 ;
     RECT  38.761 24.072 38.801 24.192 ;
     RECT  38.761 24.192 38.796 24.216 ;
     RECT  38.761 24.216 38.801 24.336 ;
     RECT  38.761 24.336 38.796 24.36 ;
     RECT  38.761 24.36 38.801 24.528 ;
     RECT  38.761 24.528 38.796 24.552 ;
     RECT  38.761 24.552 38.801 24.672 ;
     RECT  38.761 24.672 38.796 24.696 ;
     RECT  38.761 24.696 38.801 24.816 ;
     RECT  38.761 24.816 38.796 24.84 ;
     RECT  38.761 24.84 38.801 25.008 ;
     RECT  38.761 25.008 38.796 25.032 ;
     RECT  38.761 25.032 38.801 25.152 ;
     RECT  38.761 25.152 38.796 25.176 ;
     RECT  38.761 25.176 38.801 25.296 ;
     RECT  38.761 25.296 38.796 25.32 ;
     RECT  38.761 25.32 38.801 25.488 ;
     RECT  38.761 25.488 38.796 25.512 ;
     RECT  38.761 25.512 38.801 25.632 ;
     RECT  38.761 25.632 38.796 25.656 ;
     RECT  38.761 25.656 38.801 25.776 ;
     RECT  38.761 25.776 38.796 25.8 ;
     RECT  38.761 25.8 38.801 25.968 ;
     RECT  38.761 25.968 38.796 25.992 ;
     RECT  38.761 25.992 38.801 26.112 ;
     RECT  38.761 26.112 38.796 26.136 ;
     RECT  38.761 26.136 38.801 26.256 ;
     RECT  38.761 26.256 38.796 26.28 ;
     RECT  38.761 26.28 38.801 26.448 ;
     RECT  38.761 26.448 38.796 26.472 ;
     RECT  38.761 26.472 38.801 26.592 ;
     RECT  38.761 26.592 38.796 26.616 ;
     RECT  38.761 26.616 38.801 26.736 ;
     RECT  38.761 26.736 38.796 26.76 ;
     RECT  38.761 26.76 38.801 26.928 ;
     RECT  38.761 26.928 38.796 26.952 ;
     RECT  38.761 26.952 38.801 27.072 ;
     RECT  38.761 27.072 38.796 27.096 ;
     RECT  38.761 27.096 38.801 27.264 ;
     RECT  38.761 27.264 38.796 27.288 ;
     RECT  38.761 27.288 38.801 27.408 ;
     RECT  38.761 27.408 38.796 27.432 ;
     RECT  38.761 27.432 38.801 27.552 ;
     RECT  38.761 27.552 38.796 27.576 ;
     RECT  38.761 27.576 38.801 27.744 ;
     RECT  38.761 27.744 38.796 27.768 ;
     RECT  38.761 27.768 38.801 27.888 ;
     RECT  38.761 27.888 38.796 27.912 ;
     RECT  38.761 27.912 38.801 28.032 ;
     RECT  38.761 28.032 38.796 28.056 ;
     RECT  38.761 28.056 38.801 28.224 ;
     RECT  38.761 28.224 38.796 28.248 ;
     RECT  38.761 28.248 38.801 28.368 ;
     RECT  38.761 28.368 38.796 28.392 ;
     RECT  38.761 28.392 38.801 28.512 ;
     RECT  38.761 28.512 38.796 28.536 ;
     RECT  38.761 28.536 38.801 28.704 ;
     RECT  38.761 28.704 38.796 28.728 ;
     RECT  38.761 28.728 38.801 28.848 ;
     RECT  38.761 28.848 38.796 28.872 ;
     RECT  38.761 28.872 38.801 28.992 ;
     RECT  38.761 28.992 38.796 29.016 ;
     RECT  38.761 29.016 38.801 29.184 ;
     RECT  38.761 29.184 38.796 29.208 ;
     RECT  38.761 29.208 38.801 29.328 ;
     RECT  38.761 29.328 38.796 29.352 ;
     RECT  38.761 29.352 38.801 29.472 ;
     RECT  38.761 29.472 38.796 29.496 ;
     RECT  38.761 29.496 38.801 29.664 ;
     RECT  38.761 29.664 38.796 29.688 ;
     RECT  38.761 29.688 38.801 29.808 ;
     RECT  38.761 29.808 38.796 29.832 ;
     RECT  38.761 29.832 38.801 29.952 ;
     RECT  38.761 29.952 38.796 29.976 ;
     RECT  38.761 29.976 38.801 30.144 ;
     RECT  38.761 30.144 38.796 30.168 ;
     RECT  38.761 30.168 38.801 30.288 ;
     RECT  38.761 30.288 38.796 30.312 ;
     RECT  38.761 30.312 38.801 30.432 ;
     RECT  38.761 30.432 38.796 30.456 ;
     RECT  38.761 30.456 38.801 30.624 ;
     RECT  38.761 30.624 38.796 30.648 ;
     RECT  38.761 30.648 38.801 30.768 ;
     RECT  38.761 30.768 38.796 30.792 ;
     RECT  38.761 30.792 38.801 30.912 ;
     RECT  38.761 30.912 38.796 30.936 ;
     RECT  38.761 30.936 38.801 31.104 ;
     RECT  38.761 31.104 38.796 31.128 ;
     RECT  38.761 31.128 38.801 31.248 ;
     RECT  38.761 31.248 38.796 31.272 ;
     RECT  38.761 31.272 38.801 31.44 ;
     RECT  38.761 31.44 38.796 31.464 ;
     RECT  38.761 31.464 38.801 31.584 ;
     RECT  38.761 31.584 38.796 31.608 ;
     RECT  38.761 31.608 38.801 31.728 ;
     RECT  38.761 31.728 38.796 31.752 ;
     RECT  38.761 31.752 38.801 31.92 ;
     RECT  38.761 31.92 38.796 31.944 ;
     RECT  38.761 31.944 38.801 32.064 ;
     RECT  38.761 32.064 38.796 32.088 ;
     RECT  38.761 32.088 38.801 32.208 ;
     RECT  38.761 32.208 38.796 32.232 ;
     RECT  38.761 32.232 38.801 32.4 ;
     RECT  38.761 32.4 38.796 32.424 ;
     RECT  38.761 32.424 38.801 32.544 ;
     RECT  38.761 32.544 38.796 32.568 ;
     RECT  38.761 32.568 38.801 32.688 ;
     RECT  38.761 32.688 38.796 32.712 ;
     RECT  38.761 32.712 38.801 32.88 ;
     RECT  38.761 32.88 38.796 32.904 ;
     RECT  38.761 32.904 38.801 33.024 ;
     RECT  38.761 33.024 38.796 33.048 ;
     RECT  38.761 33.048 38.801 33.168 ;
     RECT  38.761 33.168 38.796 33.192 ;
     RECT  38.761 33.192 38.801 33.36 ;
     RECT  38.761 33.36 38.796 33.384 ;
     RECT  38.761 33.384 38.801 33.504 ;
     RECT  38.761 33.504 38.796 33.528 ;
     RECT  38.761 33.528 38.801 33.648 ;
     RECT  38.761 33.648 38.796 33.672 ;
     RECT  38.761 33.672 38.801 33.84 ;
     RECT  38.761 33.84 38.796 33.864 ;
     RECT  38.761 33.864 38.801 33.984 ;
     RECT  38.761 33.984 38.796 34.008 ;
     RECT  38.761 34.008 38.801 34.128 ;
     RECT  38.761 34.128 38.796 34.152 ;
     RECT  38.761 34.152 38.801 34.32 ;
     RECT  38.761 34.32 38.796 34.344 ;
     RECT  38.761 34.344 38.801 34.464 ;
     RECT  38.761 34.464 38.796 34.488 ;
     RECT  38.761 34.488 38.801 34.608 ;
     RECT  38.761 34.608 38.796 34.632 ;
     RECT  38.761 34.632 38.801 34.8 ;
     RECT  38.761 34.8 38.796 34.824 ;
     RECT  38.761 34.824 38.801 34.944 ;
     RECT  38.761 34.944 38.796 34.968 ;
     RECT  38.761 34.968 38.801 35.088 ;
     RECT  38.761 35.088 38.796 35.112 ;
     RECT  38.761 35.112 38.801 35.28 ;
     RECT  38.761 35.28 38.796 35.304 ;
     RECT  38.761 35.304 38.801 35.424 ;
     RECT  38.761 35.424 38.796 35.448 ;
     RECT  38.761 35.448 38.801 35.568 ;
     RECT  38.761 35.568 38.796 35.592 ;
     RECT  38.761 35.592 38.801 35.76 ;
     RECT  38.761 35.76 38.796 35.784 ;
     RECT  38.761 35.784 38.801 35.904 ;
     RECT  38.761 35.904 38.796 35.928 ;
     RECT  38.761 35.928 38.801 36.096 ;
     RECT  38.761 36.096 38.796 36.12 ;
     RECT  38.761 36.12 38.801 36.24 ;
     RECT  38.761 36.24 38.796 36.264 ;
     RECT  38.761 36.264 38.801 36.384 ;
     RECT  38.761 36.384 38.796 36.408 ;
     RECT  38.761 36.408 38.801 36.576 ;
     RECT  38.761 36.576 38.796 36.6 ;
     RECT  38.761 36.6 38.801 36.72 ;
     RECT  38.761 36.72 38.796 36.744 ;
     RECT  38.761 36.744 38.801 36.864 ;
     RECT  38.761 36.864 38.796 36.888 ;
     RECT  38.761 36.888 38.801 37.056 ;
     RECT  38.761 37.056 38.796 37.08 ;
     RECT  38.761 37.08 38.801 37.2 ;
     RECT  38.761 37.2 38.796 37.224 ;
     RECT  38.761 37.224 38.801 37.344 ;
     RECT  38.761 37.344 38.796 37.368 ;
     RECT  38.761 37.368 38.801 37.536 ;
     RECT  38.761 37.536 38.796 37.56 ;
     RECT  38.761 37.56 38.801 37.68 ;
     RECT  38.761 37.68 38.796 37.704 ;
     RECT  38.761 37.704 38.801 37.824 ;
     RECT  38.761 37.824 38.796 37.848 ;
     RECT  38.761 37.848 38.801 38.016 ;
     RECT  38.761 38.016 38.796 38.04 ;
     RECT  38.761 38.04 38.801 38.16 ;
     RECT  38.761 38.16 38.796 38.184 ;
     RECT  38.761 38.184 38.801 38.304 ;
     RECT  38.761 38.304 38.796 38.328 ;
     RECT  38.761 38.328 38.801 38.496 ;
     RECT  38.761 38.496 38.796 38.52 ;
     RECT  38.761 38.52 38.801 38.64 ;
     RECT  38.761 38.64 38.796 38.664 ;
     RECT  38.761 38.664 38.801 38.784 ;
     RECT  38.761 38.784 38.796 38.808 ;
     RECT  38.761 38.808 38.801 38.976 ;
     RECT  38.761 38.976 38.796 39 ;
     RECT  38.761 39 38.801 39.12 ;
     RECT  38.761 39.12 38.796 39.144 ;
     RECT  38.761 39.144 38.801 39.264 ;
     RECT  38.761 39.264 38.796 39.288 ;
     RECT  38.761 39.288 38.801 39.456 ;
     RECT  38.761 39.456 38.796 39.48 ;
     RECT  38.761 39.48 38.801 39.6 ;
     RECT  38.761 39.6 38.796 39.624 ;
     RECT  38.761 39.624 38.801 39.744 ;
     RECT  38.761 39.744 38.796 39.768 ;
     RECT  38.761 39.768 38.801 39.936 ;
     RECT  38.761 39.936 38.796 39.96 ;
     RECT  38.761 39.96 38.801 40.08 ;
     RECT  38.761 40.08 38.796 40.104 ;
     RECT  38.761 40.104 38.801 40.224 ;
     RECT  38.761 40.224 38.796 40.248 ;
     RECT  38.761 40.248 38.801 40.416 ;
     RECT  38.761 40.416 38.796 40.44 ;
     RECT  38.761 40.44 38.801 40.56 ;
     RECT  38.761 40.56 38.796 40.584 ;
     RECT  38.761 40.584 38.801 40.752 ;
     RECT  38.761 40.752 38.796 40.776 ;
     RECT  38.761 40.776 38.801 40.896 ;
     RECT  38.761 40.896 38.796 40.92 ;
     RECT  38.761 40.92 38.801 41.04 ;
     RECT  38.761 41.04 38.796 41.064 ;
     RECT  38.761 41.064 38.801 41.232 ;
     RECT  38.761 41.232 38.796 41.256 ;
     RECT  38.761 41.256 38.801 41.376 ;
     RECT  38.761 41.376 38.796 41.4 ;
     RECT  38.761 41.4 38.801 41.52 ;
     RECT  38.761 41.52 38.796 41.544 ;
     RECT  38.761 41.544 38.801 41.712 ;
     RECT  38.761 41.712 38.796 41.736 ;
     RECT  38.761 41.736 38.801 41.856 ;
     RECT  38.761 41.856 38.796 41.88 ;
     RECT  38.761 41.88 38.801 42 ;
     RECT  38.761 42 38.796 42.024 ;
     RECT  38.761 42.024 38.801 42.192 ;
     RECT  38.761 42.192 38.796 42.216 ;
     RECT  38.761 42.216 38.801 42.336 ;
     RECT  38.761 42.336 38.796 42.36 ;
     RECT  38.761 42.36 38.801 42.48 ;
     RECT  38.761 42.48 38.796 42.504 ;
     RECT  38.761 42.504 38.801 42.672 ;
     RECT  38.761 42.672 38.796 42.696 ;
     RECT  38.761 42.696 38.801 42.816 ;
     RECT  38.761 42.816 38.796 42.84 ;
     RECT  38.761 42.84 38.801 42.96 ;
     RECT  38.761 42.96 38.796 42.984 ;
     RECT  38.761 42.984 38.801 43.152 ;
     RECT  38.761 43.152 38.796 43.176 ;
     RECT  38.761 43.176 38.801 43.296 ;
     RECT  38.761 43.296 38.796 43.32 ;
     RECT  38.761 43.32 38.801 43.44 ;
     RECT  38.761 43.44 38.796 43.464 ;
     RECT  38.761 43.464 38.801 43.632 ;
     RECT  38.761 43.632 38.796 43.656 ;
     RECT  38.761 43.656 38.801 43.776 ;
     RECT  38.761 43.776 38.796 43.8 ;
     RECT  38.761 43.8 38.801 43.92 ;
     RECT  38.761 43.92 38.796 43.944 ;
     RECT  38.761 43.944 38.801 44.112 ;
     RECT  38.761 44.112 38.796 44.136 ;
     RECT  38.761 44.136 38.801 44.256 ;
     RECT  38.761 44.256 38.796 44.28 ;
     RECT  38.761 44.28 38.801 44.4 ;
     RECT  38.761 44.4 38.796 44.424 ;
     RECT  38.761 44.424 38.801 44.592 ;
     RECT  38.761 44.592 38.796 44.616 ;
     RECT  38.761 44.616 38.801 44.736 ;
     RECT  38.761 44.736 38.796 44.76 ;
     RECT  38.761 44.76 38.801 44.928 ;
     RECT  38.761 44.928 38.796 44.952 ;
     RECT  38.761 44.952 38.801 45.072 ;
     RECT  38.761 45.072 38.796 45.096 ;
     RECT  38.761 45.096 38.801 45.216 ;
     RECT  38.761 45.216 38.796 45.24 ;
     RECT  38.761 45.24 38.801 45.408 ;
     RECT  38.761 45.408 38.796 45.432 ;
     RECT  38.761 45.432 38.801 45.552 ;
     RECT  38.761 45.552 38.796 45.576 ;
     RECT  38.761 45.576 38.801 45.696 ;
     RECT  38.761 45.696 38.796 45.72 ;
     RECT  38.761 45.72 38.801 45.888 ;
     RECT  38.761 45.888 38.796 45.912 ;
     RECT  38.761 45.912 38.801 46.032 ;
     RECT  38.761 46.032 38.796 46.056 ;
     RECT  38.761 46.056 38.801 46.176 ;
     RECT  38.761 46.176 38.796 46.2 ;
     RECT  38.761 46.2 38.801 46.368 ;
     RECT  38.761 46.368 38.796 46.392 ;
     RECT  38.761 46.392 38.801 46.512 ;
     RECT  38.761 46.512 38.796 46.536 ;
     RECT  38.761 46.536 38.801 46.656 ;
     RECT  38.761 46.656 38.796 46.68 ;
     RECT  38.761 46.68 38.801 46.848 ;
     RECT  38.761 46.848 38.796 46.872 ;
     RECT  38.761 46.872 38.801 46.992 ;
     RECT  38.761 46.992 38.796 47.016 ;
     RECT  38.761 47.016 38.801 47.136 ;
     RECT  38.761 47.136 38.796 47.16 ;
     RECT  38.761 47.16 38.801 47.328 ;
     RECT  38.761 47.328 38.796 47.352 ;
     RECT  38.761 47.352 38.801 47.472 ;
     RECT  38.761 47.472 38.796 47.496 ;
     RECT  38.761 47.496 38.801 47.616 ;
     RECT  38.761 47.616 38.796 47.64 ;
     RECT  38.761 47.64 38.801 47.808 ;
     RECT  38.761 47.808 38.796 47.832 ;
     RECT  38.761 47.832 38.801 47.952 ;
     RECT  38.761 47.952 38.796 47.976 ;
     RECT  38.761 47.976 38.801 48.096 ;
     RECT  38.761 48.096 38.796 48.12 ;
     RECT  38.761 48.12 38.801 48.288 ;
     RECT  38.761 48.288 38.796 48.312 ;
     RECT  38.761 48.312 38.801 48.432 ;
     RECT  38.761 48.432 38.796 48.456 ;
     RECT  38.761 48.456 38.801 48.576 ;
     RECT  38.761 48.576 38.796 48.6 ;
     RECT  38.761 48.6 38.801 48.768 ;
     RECT  38.761 48.768 38.796 48.792 ;
     RECT  38.761 48.792 38.801 48.912 ;
     RECT  38.761 48.912 38.796 48.936 ;
     RECT  38.761 48.936 38.801 49.056 ;
     RECT  38.761 49.056 38.796 49.08 ;
     RECT  38.761 49.08 38.801 49.248 ;
     RECT  38.761 49.248 38.796 49.272 ;
     RECT  38.761 49.272 38.801 49.392 ;
     RECT  38.761 49.392 38.796 49.416 ;
     RECT  38.761 49.416 38.801 49.584 ;
     RECT  38.761 49.584 38.796 49.608 ;
     RECT  38.761 49.608 38.801 49.728 ;
     RECT  38.761 49.728 38.796 49.752 ;
     RECT  38.761 49.752 38.801 49.872 ;
     RECT  38.761 49.872 38.796 49.896 ;
     RECT  38.761 49.896 38.801 50.064 ;
     RECT  38.761 50.064 38.796 50.088 ;
     RECT  38.761 50.088 38.801 50.208 ;
     RECT  38.761 50.208 38.796 50.232 ;
     RECT  38.761 50.232 38.801 50.352 ;
     RECT  38.761 50.352 38.796 50.376 ;
     RECT  38.761 50.376 38.801 50.544 ;
     RECT  38.761 50.544 38.796 50.568 ;
     RECT  38.761 50.568 38.801 50.688 ;
     RECT  38.761 50.688 38.796 50.712 ;
     RECT  38.761 50.712 38.801 50.832 ;
     RECT  38.761 50.832 38.796 50.856 ;
     RECT  38.761 50.856 38.801 51.024 ;
     RECT  38.761 51.024 38.796 51.048 ;
     RECT  38.761 51.048 38.801 51.168 ;
     RECT  38.761 51.168 38.796 51.192 ;
     RECT  38.761 51.192 38.801 51.312 ;
     RECT  38.761 51.312 38.796 51.336 ;
     RECT  38.761 51.336 38.801 51.504 ;
     RECT  38.761 51.504 38.796 51.528 ;
     RECT  38.761 51.528 38.801 51.648 ;
     RECT  38.761 51.648 38.796 51.672 ;
     RECT  38.761 51.672 38.801 51.792 ;
     RECT  38.761 51.792 38.796 51.816 ;
     RECT  38.761 51.816 38.801 51.984 ;
     RECT  38.761 51.984 38.796 52.008 ;
     RECT  38.761 52.008 38.801 52.128 ;
     RECT  38.761 52.128 38.796 52.152 ;
     RECT  38.761 52.152 38.801 52.272 ;
     RECT  38.761 52.272 38.796 52.296 ;
     RECT  38.761 52.296 38.801 52.464 ;
     RECT  38.761 52.464 38.796 52.488 ;
     RECT  38.761 52.488 38.801 52.608 ;
     RECT  38.761 52.608 38.796 52.632 ;
     RECT  38.761 52.632 38.801 52.752 ;
     RECT  38.761 52.752 38.796 52.776 ;
     RECT  38.761 52.776 38.801 52.944 ;
     RECT  38.761 52.944 38.796 52.968 ;
     RECT  38.761 52.968 38.801 53.088 ;
     RECT  38.761 53.088 38.796 53.112 ;
     RECT  38.761 53.112 38.801 53.232 ;
     RECT  38.761 53.232 38.796 53.256 ;
     RECT  38.761 53.256 38.801 53.424 ;
     RECT  38.761 53.424 38.796 53.448 ;
     RECT  38.761 53.448 38.801 53.568 ;
     RECT  38.761 53.568 38.796 53.592 ;
     RECT  38.761 53.592 38.801 53.712 ;
     RECT  38.761 53.712 38.796 53.736 ;
     RECT  38.761 53.736 38.801 53.904 ;
     RECT  38.761 53.904 38.796 53.928 ;
     RECT  38.761 53.928 38.801 54.048 ;
     RECT  38.761 54.048 38.796 54.072 ;
     RECT  38.761 54.072 38.801 54.24 ;
     RECT  38.761 54.24 38.796 54.264 ;
     RECT  38.761 54.264 38.801 54.384 ;
     RECT  38.761 54.384 38.796 54.408 ;
     RECT  38.761 54.408 38.801 54.528 ;
     RECT  38.761 54.528 38.796 54.552 ;
     RECT  38.761 54.552 38.801 54.72 ;
     RECT  38.761 54.72 38.796 54.744 ;
     RECT  38.761 54.744 38.801 54.864 ;
     RECT  38.761 54.864 38.796 54.888 ;
     RECT  38.761 54.888 38.801 55.008 ;
     RECT  38.761 55.008 38.796 55.032 ;
     RECT  38.761 55.032 38.801 55.2 ;
     RECT  38.761 55.2 38.796 55.224 ;
     RECT  38.761 55.224 38.801 55.344 ;
     RECT  38.761 55.344 38.796 55.368 ;
     RECT  38.761 55.368 38.801 55.488 ;
     RECT  38.761 55.488 38.796 55.512 ;
     RECT  38.761 55.512 38.801 55.68 ;
     RECT  38.761 55.68 38.796 55.704 ;
     RECT  38.761 55.704 38.801 55.824 ;
     RECT  38.761 55.824 38.796 55.848 ;
     RECT  38.761 55.848 38.801 55.968 ;
     RECT  38.761 55.968 38.796 55.992 ;
     RECT  38.761 55.992 38.801 56.16 ;
     RECT  38.761 56.16 38.796 56.184 ;
     RECT  38.761 56.184 38.801 56.304 ;
     RECT  38.761 56.304 38.796 56.328 ;
     RECT  38.761 56.328 38.801 56.448 ;
     RECT  38.761 56.448 38.796 56.472 ;
     RECT  38.761 56.472 38.801 56.64 ;
     RECT  38.761 56.64 38.796 56.664 ;
     RECT  38.761 56.664 38.801 56.784 ;
     RECT  38.761 56.784 38.796 56.808 ;
     RECT  38.761 56.808 38.801 56.928 ;
     RECT  38.761 56.928 38.796 56.952 ;
     RECT  38.761 56.952 38.801 57.12 ;
     RECT  38.761 57.12 38.796 57.144 ;
     RECT  38.761 57.144 38.801 57.264 ;
     RECT  38.761 57.264 38.796 57.288 ;
     RECT  38.761 57.288 38.801 57.408 ;
     RECT  38.761 57.408 38.796 57.432 ;
     RECT  38.761 57.432 38.801 57.6 ;
     RECT  38.761 57.6 38.796 57.624 ;
     RECT  38.761 57.624 38.801 57.744 ;
     RECT  38.761 57.744 38.796 57.768 ;
     RECT  38.761 57.768 38.801 57.888 ;
     RECT  38.761 57.888 38.796 57.912 ;
     RECT  38.761 57.912 38.801 58.08 ;
     RECT  38.761 58.08 38.796 58.104 ;
     RECT  38.761 58.104 38.801 58.224 ;
     RECT  38.761 58.224 38.796 58.248 ;
     RECT  38.761 58.248 38.801 58.416 ;
     RECT  38.761 58.416 38.796 58.44 ;
     RECT  38.761 58.44 38.801 58.56 ;
     RECT  38.761 58.56 38.796 58.584 ;
     RECT  38.761 58.584 38.801 58.704 ;
     RECT  38.761 58.704 38.796 58.728 ;
     RECT  38.761 58.728 38.801 58.896 ;
     RECT  38.761 58.896 38.796 58.92 ;
     RECT  38.761 58.92 38.801 59.04 ;
     RECT  38.761 59.04 38.796 59.064 ;
     RECT  38.761 59.064 38.801 59.184 ;
     RECT  38.761 59.184 38.796 59.208 ;
     RECT  38.761 59.208 38.801 59.376 ;
     RECT  38.761 59.376 38.796 59.4 ;
     RECT  38.761 59.4 38.801 59.52 ;
     RECT  38.761 59.52 38.796 59.544 ;
     RECT  38.761 59.544 38.801 59.664 ;
     RECT  38.761 59.664 38.796 59.688 ;
     RECT  38.761 59.688 38.801 59.856 ;
     RECT  38.761 59.856 38.796 59.88 ;
     RECT  38.761 59.88 38.801 60 ;
     RECT  38.761 60 38.796 60.024 ;
     RECT  38.761 60.024 38.801 60.144 ;
     RECT  38.761 60.144 38.796 60.168 ;
     RECT  38.761 60.168 38.801 60.336 ;
     RECT  38.761 60.336 38.796 60.36 ;
     RECT  38.761 60.36 38.801 60.48 ;
     RECT  38.761 60.48 38.796 60.504 ;
     RECT  38.761 60.504 38.801 60.624 ;
     RECT  38.761 60.624 38.796 60.648 ;
     RECT  38.761 60.648 38.801 60.816 ;
     RECT  38.761 60.816 38.796 60.84 ;
     RECT  38.761 60.84 38.801 60.96 ;
     RECT  38.761 60.96 38.796 60.984 ;
     RECT  38.761 60.984 38.801 61.104 ;
     RECT  38.761 61.104 38.796 61.128 ;
     RECT  38.761 61.128 38.801 61.296 ;
     RECT  38.761 61.296 38.796 61.32 ;
     RECT  38.761 61.32 38.801 61.44 ;
     RECT  38.761 61.44 38.796 61.464 ;
     RECT  38.761 61.464 38.801 61.584 ;
     RECT  38.761 61.584 38.796 61.608 ;
     RECT  38.761 61.608 38.801 61.776 ;
     RECT  38.761 61.776 38.796 61.8 ;
     RECT  38.761 61.8 38.801 61.92 ;
     RECT  38.761 61.92 38.796 61.944 ;
     RECT  38.761 61.944 38.801 62.064 ;
     RECT  38.761 62.064 38.796 62.088 ;
     RECT  38.761 62.088 38.801 62.256 ;
     RECT  38.761 62.256 38.796 62.28 ;
     RECT  38.761 62.28 38.801 62.4 ;
     RECT  38.761 62.4 38.796 62.424 ;
     RECT  38.761 62.424 38.801 62.544 ;
     RECT  38.761 62.544 38.796 62.568 ;
     RECT  38.761 62.568 38.801 62.736 ;
     RECT  38.761 62.736 38.796 62.76 ;
     RECT  38.761 62.76 38.801 62.88 ;
     RECT  38.761 62.88 38.796 62.904 ;
     RECT  38.761 62.904 38.801 63.072 ;
     RECT  38.761 63.072 38.796 63.096 ;
     RECT  38.761 63.096 38.801 63.216 ;
     RECT  38.761 63.216 38.796 63.24 ;
     RECT  38.761 63.24 38.801 63.36 ;
     RECT  38.761 63.36 38.796 63.384 ;
     RECT  38.761 63.384 38.801 63.552 ;
     RECT  38.761 63.552 38.796 63.576 ;
     RECT  38.761 63.576 38.801 63.696 ;
     RECT  38.761 63.696 38.796 63.72 ;
     RECT  38.761 63.72 38.801 63.84 ;
     RECT  38.761 63.84 38.796 63.864 ;
     RECT  38.761 63.864 38.801 64.032 ;
     RECT  38.761 64.032 38.796 64.056 ;
     RECT  38.761 64.056 38.801 64.176 ;
     RECT  38.761 64.176 38.796 64.2 ;
     RECT  38.761 64.2 38.801 64.32 ;
     RECT  38.761 64.32 38.796 64.344 ;
     RECT  38.761 64.344 38.801 64.512 ;
     RECT  38.761 64.512 38.796 64.536 ;
     RECT  38.761 64.536 38.801 64.656 ;
     RECT  38.761 64.656 38.796 64.68 ;
     RECT  38.761 64.68 38.801 64.8 ;
     RECT  38.761 64.8 38.796 64.824 ;
     RECT  38.761 64.824 38.801 64.992 ;
     RECT  38.761 64.992 38.796 65.016 ;
     RECT  38.761 65.016 38.801 65.136 ;
     RECT  38.761 65.136 38.796 65.16 ;
     RECT  38.761 65.16 38.801 65.28 ;
     RECT  38.761 65.28 38.796 65.304 ;
     RECT  38.761 65.304 38.801 65.472 ;
     RECT  38.761 65.472 38.796 65.496 ;
     RECT  38.761 65.496 38.801 65.616 ;
     RECT  38.761 65.616 38.796 65.64 ;
     RECT  38.761 65.64 38.801 65.76 ;
     RECT  38.761 65.76 38.796 65.784 ;
     RECT  38.761 65.784 38.801 65.952 ;
     RECT  38.761 65.952 38.796 65.976 ;
     RECT  38.761 65.976 38.801 66.096 ;
     RECT  38.761 66.096 38.796 66.12 ;
     RECT  38.761 66.12 38.801 66.24 ;
     RECT  38.761 66.24 38.796 66.264 ;
     RECT  38.761 66.264 38.801 66.432 ;
     RECT  38.761 66.432 38.796 66.456 ;
     RECT  38.761 66.456 38.801 66.576 ;
     RECT  38.761 66.576 38.796 66.6 ;
     RECT  38.761 66.6 38.801 66.72 ;
     RECT  38.761 66.72 38.796 66.744 ;
     RECT  38.761 66.744 38.801 66.912 ;
     RECT  38.761 66.912 38.796 66.936 ;
     RECT  38.761 66.936 38.801 67.056 ;
     RECT  38.761 67.056 38.796 67.08 ;
     RECT  38.761 67.08 38.801 67.2 ;
     RECT  38.761 67.2 38.796 67.224 ;
     RECT  38.761 67.224 38.801 67.392 ;
     RECT  38.761 67.392 38.796 67.416 ;
     RECT  38.761 67.416 38.801 67.536 ;
     RECT  38.761 67.536 38.796 67.56 ;
     RECT  38.761 67.56 38.801 67.728 ;
     RECT  38.761 67.728 38.796 67.752 ;
     RECT  38.761 67.752 38.801 67.872 ;
     RECT  38.761 67.872 38.796 67.896 ;
     RECT  38.761 67.896 38.801 68.016 ;
     RECT  38.761 68.016 38.796 68.04 ;
     RECT  38.761 68.04 38.801 68.208 ;
     RECT  38.761 68.208 38.796 68.232 ;
     RECT  38.761 68.232 38.801 68.352 ;
     RECT  38.761 68.352 38.796 68.376 ;
     RECT  38.761 68.376 38.801 68.496 ;
     RECT  38.761 68.496 38.796 68.52 ;
     RECT  38.761 68.52 38.801 68.688 ;
     RECT  38.761 68.688 38.796 68.712 ;
     RECT  38.761 68.712 38.801 68.832 ;
     RECT  38.761 68.832 38.796 68.856 ;
     RECT  38.761 68.856 38.801 68.976 ;
     RECT  38.761 68.976 38.796 69 ;
     RECT  38.761 69 38.801 69.168 ;
     RECT  38.761 69.168 38.796 69.192 ;
     RECT  38.761 69.192 38.801 69.312 ;
     RECT  38.761 69.312 38.796 69.336 ;
     RECT  38.761 69.336 38.801 69.456 ;
     RECT  38.761 69.456 38.796 69.48 ;
     RECT  38.761 69.48 38.801 69.648 ;
     RECT  38.761 69.648 38.796 69.672 ;
     RECT  38.761 69.672 38.801 69.792 ;
     RECT  38.761 69.792 38.796 69.816 ;
     RECT  38.761 69.816 38.801 69.936 ;
     RECT  38.761 69.936 38.796 69.96 ;
     RECT  38.761 69.96 38.801 70.128 ;
     RECT  38.761 70.128 38.796 70.152 ;
     RECT  38.761 70.152 38.801 70.272 ;
     RECT  38.761 70.272 38.796 70.296 ;
     RECT  38.761 70.296 38.801 70.416 ;
     RECT  38.761 70.416 38.796 70.44 ;
     RECT  38.761 70.44 38.801 70.608 ;
     RECT  38.761 70.608 38.796 70.632 ;
     RECT  38.761 70.632 38.801 70.752 ;
     RECT  38.761 70.752 38.796 70.776 ;
     RECT  38.761 70.776 38.801 70.896 ;
     RECT  38.761 70.896 38.796 70.92 ;
     RECT  38.761 70.92 38.801 71.088 ;
     RECT  38.761 71.088 38.796 71.112 ;
     RECT  38.761 71.112 38.801 71.232 ;
     RECT  38.761 71.232 38.796 71.256 ;
     RECT  38.761 71.256 38.801 71.376 ;
     RECT  38.761 71.376 38.796 71.4 ;
     RECT  38.761 71.4 38.801 71.568 ;
     RECT  38.761 71.568 38.796 71.592 ;
     RECT  38.761 71.592 38.801 71.712 ;
     RECT  38.761 71.712 38.796 71.736 ;
     RECT  38.761 71.736 38.801 71.856 ;
     RECT  38.761 71.856 38.796 71.88 ;
     RECT  38.761 71.88 38.801 72.048 ;
     RECT  38.761 72.048 38.796 72.072 ;
     RECT  38.761 72.072 38.801 72.192 ;
     RECT  38.761 72.192 38.796 72.216 ;
     RECT  38.761 72.216 38.801 72.384 ;
     RECT  38.761 72.384 38.796 72.408 ;
     RECT  38.761 72.408 38.801 72.528 ;
     RECT  38.761 72.528 38.796 72.552 ;
     RECT  38.761 72.552 38.801 72.672 ;
     RECT  38.761 72.672 38.796 72.696 ;
     RECT  38.761 72.696 38.801 72.864 ;
     RECT  38.761 72.864 38.796 72.888 ;
     RECT  38.761 72.888 38.801 73.008 ;
     RECT  38.761 73.008 38.796 73.032 ;
     RECT  38.761 73.032 38.801 73.152 ;
     RECT  38.761 73.152 38.796 73.176 ;
     RECT  38.761 73.176 38.801 73.344 ;
     RECT  38.761 73.344 38.796 73.368 ;
     RECT  38.761 73.368 38.801 73.488 ;
     RECT  38.761 73.488 38.796 73.512 ;
     RECT  38.761 73.512 38.801 73.632 ;
     RECT  38.761 73.632 38.796 73.656 ;
     RECT  38.761 73.656 38.801 73.824 ;
     RECT  38.761 73.824 38.796 73.848 ;
     RECT  38.761 73.848 38.801 73.968 ;
     RECT  38.761 73.968 38.796 73.992 ;
     RECT  38.761 73.992 38.801 74.112 ;
     RECT  38.761 74.112 38.796 74.136 ;
     RECT  38.761 74.136 38.801 74.304 ;
     RECT  38.761 74.304 38.796 74.328 ;
     RECT  38.761 74.328 38.801 74.448 ;
     RECT  38.761 74.448 38.796 74.472 ;
     RECT  38.761 74.472 38.801 74.592 ;
     RECT  38.761 74.592 38.796 74.616 ;
     RECT  38.761 74.616 38.801 74.784 ;
     RECT  38.761 74.784 38.796 74.808 ;
     RECT  38.761 74.808 38.801 74.928 ;
     RECT  38.761 74.928 38.796 74.952 ;
     RECT  38.761 74.952 38.801 75.072 ;
     RECT  38.761 75.072 38.796 75.096 ;
     RECT  38.761 75.096 38.801 75.264 ;
     RECT  38.761 75.264 38.796 75.288 ;
     RECT  38.761 75.288 38.801 75.408 ;
     RECT  38.761 75.408 38.796 75.432 ;
     RECT  38.761 75.432 38.801 75.552 ;
     RECT  38.761 75.552 38.796 75.576 ;
     RECT  38.761 75.576 38.801 75.744 ;
     RECT  38.761 75.744 38.796 75.768 ;
     RECT  38.761 75.768 38.801 75.888 ;
     RECT  38.761 75.888 38.796 75.912 ;
     RECT  38.761 75.912 38.801 76.032 ;
     RECT  38.761 76.032 38.796 76.056 ;
     RECT  38.761 76.056 38.801 76.224 ;
     RECT  38.761 76.224 38.796 76.248 ;
     RECT  38.761 76.248 38.801 76.368 ;
     RECT  38.761 76.368 38.796 76.392 ;
     RECT  38.761 76.392 38.801 76.56 ;
     RECT  38.761 76.56 38.796 76.584 ;
     RECT  38.761 76.584 38.801 76.704 ;
     RECT  38.761 76.704 38.796 76.728 ;
     RECT  38.761 76.728 38.801 76.848 ;
     RECT  38.761 76.848 38.796 76.872 ;
     RECT  38.761 76.872 38.801 77.04 ;
     RECT  38.761 77.04 38.796 77.064 ;
     RECT  38.761 77.064 38.801 77.184 ;
     RECT  38.761 77.184 38.796 77.208 ;
     RECT  38.761 77.208 38.801 77.328 ;
     RECT  38.761 77.328 38.796 77.352 ;
     RECT  38.761 77.352 38.801 77.52 ;
     RECT  38.761 77.52 38.796 77.544 ;
     RECT  38.761 77.544 38.801 77.664 ;
     RECT  38.761 77.664 38.796 77.688 ;
     RECT  38.761 77.688 38.801 77.808 ;
     RECT  38.761 77.808 38.796 77.832 ;
     RECT  38.761 77.832 38.801 78 ;
     RECT  38.761 78 38.796 78.024 ;
     RECT  38.761 78.024 38.801 78.144 ;
     RECT  38.761 78.144 38.796 78.168 ;
     RECT  38.761 78.168 38.801 78.288 ;
     RECT  38.761 78.288 38.796 78.312 ;
     RECT  38.761 78.312 38.801 78.48 ;
     RECT  38.761 78.48 38.796 78.504 ;
     RECT  38.761 78.504 38.801 78.624 ;
     RECT  38.761 78.624 38.796 78.648 ;
     RECT  38.761 78.648 38.801 78.768 ;
     RECT  38.761 78.768 38.796 78.792 ;
     RECT  38.761 78.792 38.801 78.96 ;
     RECT  38.761 78.96 38.796 78.984 ;
     RECT  38.761 78.984 38.801 79.104 ;
     RECT  38.761 79.104 38.796 79.128 ;
     RECT  38.761 79.128 38.801 79.248 ;
     RECT  38.761 79.248 38.796 79.272 ;
     RECT  38.761 79.272 38.801 79.44 ;
     RECT  38.761 79.44 38.796 79.464 ;
     RECT  38.761 79.464 38.801 79.584 ;
     RECT  38.761 79.584 38.796 79.608 ;
     RECT  38.761 79.608 38.801 79.728 ;
     RECT  38.761 79.728 38.796 79.752 ;
     RECT  38.761 79.752 38.801 79.92 ;
     RECT  38.761 79.92 38.796 79.944 ;
     RECT  38.761 79.944 38.801 80.064 ;
     RECT  38.761 80.064 38.796 80.088 ;
     RECT  38.761 80.088 38.801 80.208 ;
     RECT  38.761 80.208 38.796 80.232 ;
     RECT  38.761 80.232 38.801 80.4 ;
     RECT  38.761 80.4 38.796 80.424 ;
     RECT  38.761 80.424 38.801 80.544 ;
     RECT  38.761 80.544 38.796 80.568 ;
     RECT  38.761 80.568 38.801 80.688 ;
     RECT  38.761 80.688 38.796 80.712 ;
     RECT  38.761 80.712 38.801 80.88 ;
     RECT  38.761 80.88 38.796 80.904 ;
     RECT  38.761 80.904 38.801 81.024 ;
     RECT  38.761 81.024 38.796 81.048 ;
     RECT  38.761 81.048 38.801 81.216 ;
     RECT  38.761 81.216 38.796 81.24 ;
     RECT  38.761 81.24 38.801 81.36 ;
     RECT  38.761 81.36 38.796 81.384 ;
     RECT  38.761 81.384 38.801 81.504 ;
     RECT  38.761 81.504 38.796 81.528 ;
     RECT  38.761 81.528 38.801 81.696 ;
     RECT  38.761 81.696 38.796 81.72 ;
     RECT  38.761 81.72 38.801 81.84 ;
     RECT  38.761 81.84 38.796 81.864 ;
     RECT  38.761 81.864 38.801 81.984 ;
     RECT  38.761 81.984 38.796 82.008 ;
     RECT  38.761 82.008 38.801 82.176 ;
     RECT  38.761 82.176 38.796 82.2 ;
     RECT  38.761 82.2 38.801 82.32 ;
     RECT  38.761 82.32 38.796 82.344 ;
     RECT  38.761 82.344 38.801 82.464 ;
     RECT  38.761 82.464 38.796 82.488 ;
     RECT  38.761 82.488 38.801 82.656 ;
     RECT  38.761 82.656 38.796 82.68 ;
     RECT  38.761 82.68 38.801 82.8 ;
     RECT  38.761 82.8 38.796 82.824 ;
     RECT  38.761 82.824 38.801 82.944 ;
     RECT  38.761 82.944 38.796 82.968 ;
     RECT  38.761 82.968 38.801 83.136 ;
     RECT  38.761 83.136 38.796 83.16 ;
     RECT  38.761 83.16 38.801 83.28 ;
     RECT  38.761 83.28 38.796 83.304 ;
     RECT  38.761 83.304 38.801 83.424 ;
     RECT  38.761 83.424 38.796 83.448 ;
     RECT  38.761 83.448 38.801 83.616 ;
     RECT  38.761 83.616 38.796 83.64 ;
     RECT  38.761 83.64 38.801 83.76 ;
     RECT  38.761 83.76 38.796 83.784 ;
     RECT  38.761 83.784 38.801 83.904 ;
     RECT  38.761 83.904 38.796 83.928 ;
     RECT  38.761 83.928 38.801 84.096 ;
     RECT  38.761 84.096 38.796 84.12 ;
     RECT  38.761 84.12 38.801 84.24 ;
     RECT  38.761 84.24 38.796 84.264 ;
     RECT  38.761 84.264 38.801 84.384 ;
     RECT  38.761 84.384 38.796 84.408 ;
     RECT  38.761 84.408 38.801 84.576 ;
     RECT  38.761 84.576 38.796 84.6 ;
     RECT  38.761 84.6 38.801 84.72 ;
     RECT  38.761 84.72 38.796 84.744 ;
     RECT  38.761 84.744 38.801 84.864 ;
     RECT  38.761 84.864 38.796 84.888 ;
     RECT  38.761 84.888 38.801 85.056 ;
     RECT  38.761 85.056 38.796 85.08 ;
     RECT  38.761 85.08 38.801 85.2 ;
     RECT  38.761 85.2 38.796 85.224 ;
     RECT  38.761 85.224 38.801 85.344 ;
     RECT  38.761 85.344 38.796 85.368 ;
     RECT  38.761 85.368 38.801 85.536 ;
     RECT  38.761 85.536 38.796 85.56 ;
     RECT  38.761 85.56 38.801 85.68 ;
     RECT  38.761 85.68 38.796 85.704 ;
     RECT  38.761 85.704 38.801 85.872 ;
     RECT  38.761 85.872 38.796 85.896 ;
     RECT  38.761 85.896 38.801 86.016 ;
     RECT  38.761 86.016 38.796 86.04 ;
     RECT  38.761 86.04 38.801 86.16 ;
     RECT  38.761 86.16 38.796 86.184 ;
     RECT  38.761 86.184 38.801 86.352 ;
     RECT  38.761 86.352 38.796 86.376 ;
     RECT  38.761 86.376 38.801 86.496 ;
     RECT  38.761 86.496 38.796 86.52 ;
     RECT  38.761 86.52 38.801 86.64 ;
     RECT  38.761 86.64 38.796 86.664 ;
     RECT  38.761 86.664 38.801 86.832 ;
     RECT  38.761 86.832 38.796 86.856 ;
     RECT  38.761 86.856 38.801 86.976 ;
     RECT  38.761 86.976 38.796 87 ;
     RECT  38.761 87 38.801 87.12 ;
     RECT  38.761 87.12 38.796 87.144 ;
     RECT  38.761 87.144 38.801 87.312 ;
     RECT  38.761 87.312 38.796 87.336 ;
     RECT  38.761 87.336 38.801 87.456 ;
     RECT  38.761 87.456 38.796 87.48 ;
     RECT  38.761 87.48 38.801 87.6 ;
     RECT  38.761 87.6 38.796 87.624 ;
     RECT  38.761 87.624 38.801 87.792 ;
     RECT  38.761 87.792 38.796 87.816 ;
     RECT  38.761 87.816 38.801 87.936 ;
     RECT  38.761 87.936 38.796 87.96 ;
     RECT  38.761 87.96 38.801 88.08 ;
     RECT  38.761 88.08 38.796 88.104 ;
     RECT  38.761 88.104 38.801 88.272 ;
     RECT  38.761 88.272 38.796 88.296 ;
     RECT  38.761 88.296 38.801 88.416 ;
     RECT  38.761 88.416 38.796 88.44 ;
     RECT  38.761 88.44 38.801 88.56 ;
     RECT  38.761 88.56 38.796 88.584 ;
     RECT  38.761 88.584 38.801 88.752 ;
     RECT  38.761 88.752 38.796 88.776 ;
     RECT  38.761 88.776 38.801 88.896 ;
     RECT  38.761 88.896 38.796 88.92 ;
     RECT  38.761 88.92 38.801 89.04 ;
     RECT  38.761 89.04 38.796 89.064 ;
     RECT  38.761 89.064 38.801 89.232 ;
     RECT  38.761 89.232 38.796 89.256 ;
     RECT  38.761 89.256 38.801 89.376 ;
     RECT  38.761 89.376 38.796 89.4 ;
     RECT  38.761 89.4 38.801 89.52 ;
     RECT  38.761 89.52 38.796 89.544 ;
     RECT  38.761 89.544 38.801 89.712 ;
     RECT  38.761 89.712 38.796 89.736 ;
     RECT  38.761 89.736 38.801 89.856 ;
     RECT  38.761 89.856 38.796 89.88 ;
     RECT  38.761 89.88 38.801 90.048 ;
     RECT  38.761 90.048 38.796 90.072 ;
     RECT  38.761 90.072 38.801 90.192 ;
     RECT  38.761 90.192 38.796 90.216 ;
     RECT  38.761 90.216 38.801 90.336 ;
     RECT  38.761 90.336 38.796 90.36 ;
     RECT  38.761 90.36 38.801 90.528 ;
     RECT  38.761 90.528 38.796 90.552 ;
     RECT  38.761 90.552 38.801 90.672 ;
     RECT  38.761 90.672 38.796 90.696 ;
     RECT  38.761 90.696 38.801 90.816 ;
     RECT  38.761 90.816 38.796 90.84 ;
     RECT  38.761 90.84 38.801 91.008 ;
     RECT  38.761 91.008 38.796 91.032 ;
     RECT  38.761 91.032 38.801 91.152 ;
     RECT  38.761 91.152 38.796 91.176 ;
     RECT  38.761 91.176 38.801 92.112 ;
     RECT  38.761 92.112 38.796 92.136 ;
     RECT  38.761 92.136 38.801 92.232 ;
     RECT  38.801 1.08 38.844 1.248 ;
     RECT  38.801 1.272 38.844 1.392 ;
     RECT  38.801 1.416 38.844 1.536 ;
     RECT  38.801 1.56 38.844 1.728 ;
     RECT  38.801 1.752 38.844 1.872 ;
     RECT  38.801 1.896 38.844 2.016 ;
     RECT  38.801 2.04 38.844 2.208 ;
     RECT  38.801 2.232 38.844 2.352 ;
     RECT  38.801 2.376 38.844 2.496 ;
     RECT  38.801 2.52 38.844 2.688 ;
     RECT  38.801 2.712 38.844 2.832 ;
     RECT  38.801 2.856 38.844 2.976 ;
     RECT  38.801 3 38.844 3.168 ;
     RECT  38.801 3.192 38.844 3.312 ;
     RECT  38.801 3.336 38.844 3.456 ;
     RECT  38.801 3.48 38.844 3.648 ;
     RECT  38.801 3.672 38.844 3.792 ;
     RECT  38.801 3.816 38.844 3.936 ;
     RECT  38.801 3.96 38.844 4.128 ;
     RECT  38.801 4.152 38.844 4.272 ;
     RECT  38.801 4.296 38.844 4.464 ;
     RECT  38.801 4.488 38.844 4.608 ;
     RECT  38.801 4.632 38.844 4.752 ;
     RECT  38.801 4.776 38.844 4.944 ;
     RECT  38.801 4.968 38.844 5.088 ;
     RECT  38.801 5.112 38.844 5.232 ;
     RECT  38.801 5.256 38.844 5.424 ;
     RECT  38.801 5.448 38.844 5.568 ;
     RECT  38.801 5.592 38.844 5.712 ;
     RECT  38.801 5.736 38.844 5.904 ;
     RECT  38.801 5.928 38.844 6.048 ;
     RECT  38.801 6.072 38.844 6.192 ;
     RECT  38.801 6.216 38.844 6.384 ;
     RECT  38.801 6.408 38.844 6.528 ;
     RECT  38.801 6.552 38.844 6.672 ;
     RECT  38.801 6.696 38.844 6.864 ;
     RECT  38.801 6.888 38.844 7.008 ;
     RECT  38.801 7.032 38.844 7.152 ;
     RECT  38.801 7.176 38.844 7.344 ;
     RECT  38.801 7.368 38.844 7.488 ;
     RECT  38.801 7.512 38.844 7.632 ;
     RECT  38.801 7.656 38.844 7.824 ;
     RECT  38.801 7.848 38.844 7.968 ;
     RECT  38.801 7.992 38.844 8.112 ;
     RECT  38.801 8.136 38.844 8.304 ;
     RECT  38.801 8.328 38.844 8.448 ;
     RECT  38.801 8.472 38.844 8.592 ;
     RECT  38.801 8.616 38.844 8.784 ;
     RECT  38.801 8.808 38.844 8.928 ;
     RECT  38.801 8.952 38.844 9.12 ;
     RECT  38.801 9.144 38.844 9.264 ;
     RECT  38.801 9.288 38.844 9.408 ;
     RECT  38.801 9.432 38.844 9.6 ;
     RECT  38.801 9.624 38.844 9.744 ;
     RECT  38.801 9.768 38.844 9.888 ;
     RECT  38.801 9.912 38.844 10.08 ;
     RECT  38.801 10.104 38.844 10.224 ;
     RECT  38.801 10.248 38.844 10.368 ;
     RECT  38.801 10.392 38.844 10.56 ;
     RECT  38.801 10.584 38.844 10.704 ;
     RECT  38.801 10.728 38.844 10.848 ;
     RECT  38.801 10.872 38.844 11.04 ;
     RECT  38.801 11.064 38.844 11.184 ;
     RECT  38.801 11.208 38.844 11.328 ;
     RECT  38.801 11.352 38.844 11.52 ;
     RECT  38.801 11.544 38.844 11.664 ;
     RECT  38.801 11.688 38.844 11.808 ;
     RECT  38.801 11.832 38.844 12 ;
     RECT  38.801 12.024 38.844 12.144 ;
     RECT  38.801 12.168 38.844 12.288 ;
     RECT  38.801 12.312 38.844 12.48 ;
     RECT  38.801 12.504 38.844 12.624 ;
     RECT  38.801 12.648 38.844 12.768 ;
     RECT  38.801 12.792 38.844 12.96 ;
     RECT  38.801 12.984 38.844 13.104 ;
     RECT  38.801 13.128 38.844 13.296 ;
     RECT  38.801 13.32 38.844 13.44 ;
     RECT  38.801 13.464 38.844 13.584 ;
     RECT  38.801 13.608 38.844 13.776 ;
     RECT  38.801 13.8 38.844 13.92 ;
     RECT  38.801 13.944 38.844 14.064 ;
     RECT  38.801 14.088 38.844 14.256 ;
     RECT  38.801 14.28 38.844 14.4 ;
     RECT  38.801 14.424 38.844 14.544 ;
     RECT  38.801 14.568 38.844 14.736 ;
     RECT  38.801 14.76 38.844 14.88 ;
     RECT  38.801 14.904 38.844 15.024 ;
     RECT  38.801 15.048 38.844 15.216 ;
     RECT  38.801 15.24 38.844 15.36 ;
     RECT  38.801 15.384 38.844 15.504 ;
     RECT  38.801 15.528 38.844 15.696 ;
     RECT  38.801 15.72 38.844 15.84 ;
     RECT  38.801 15.864 38.844 15.984 ;
     RECT  38.801 16.008 38.844 16.176 ;
     RECT  38.801 16.2 38.844 16.32 ;
     RECT  38.801 16.344 38.844 16.464 ;
     RECT  38.801 16.488 38.844 16.656 ;
     RECT  38.801 16.68 38.844 16.8 ;
     RECT  38.801 16.824 38.844 16.944 ;
     RECT  38.801 16.968 38.844 17.136 ;
     RECT  38.801 17.16 38.844 17.28 ;
     RECT  38.801 17.304 38.844 17.424 ;
     RECT  38.801 17.448 38.844 17.616 ;
     RECT  38.801 17.64 38.844 17.76 ;
     RECT  38.801 17.784 38.844 17.952 ;
     RECT  38.801 17.976 38.844 18.096 ;
     RECT  38.801 18.12 38.844 18.24 ;
     RECT  38.801 18.264 38.844 18.432 ;
     RECT  38.801 18.456 38.844 18.576 ;
     RECT  38.801 18.6 38.844 18.72 ;
     RECT  38.801 18.744 38.844 18.912 ;
     RECT  38.801 18.936 38.844 19.056 ;
     RECT  38.801 19.08 38.844 19.2 ;
     RECT  38.801 19.224 38.844 19.392 ;
     RECT  38.801 19.416 38.844 19.536 ;
     RECT  38.801 19.56 38.844 19.68 ;
     RECT  38.801 19.704 38.844 19.872 ;
     RECT  38.801 19.896 38.844 20.016 ;
     RECT  38.801 20.04 38.844 20.16 ;
     RECT  38.801 20.184 38.844 20.352 ;
     RECT  38.801 20.376 38.844 20.496 ;
     RECT  38.801 20.52 38.844 20.64 ;
     RECT  38.801 20.664 38.844 20.832 ;
     RECT  38.801 20.856 38.844 20.976 ;
     RECT  38.801 21 38.844 21.12 ;
     RECT  38.801 21.144 38.844 21.312 ;
     RECT  38.801 21.336 38.844 21.456 ;
     RECT  38.801 21.48 38.844 21.6 ;
     RECT  38.801 21.624 38.844 21.792 ;
     RECT  38.801 21.816 38.844 21.936 ;
     RECT  38.801 21.96 38.844 22.08 ;
     RECT  38.801 22.104 38.844 22.272 ;
     RECT  38.801 22.296 38.844 22.416 ;
     RECT  38.801 22.44 38.844 22.608 ;
     RECT  38.801 22.632 38.844 22.752 ;
     RECT  38.801 22.776 38.844 22.896 ;
     RECT  38.801 22.92 38.844 23.088 ;
     RECT  38.801 23.112 38.844 23.232 ;
     RECT  38.801 23.256 38.844 23.376 ;
     RECT  38.801 23.4 38.844 23.568 ;
     RECT  38.801 23.592 38.844 23.712 ;
     RECT  38.801 23.736 38.844 23.856 ;
     RECT  38.801 23.88 38.844 24.048 ;
     RECT  38.801 24.072 38.844 24.192 ;
     RECT  38.801 24.216 38.844 24.336 ;
     RECT  38.801 24.36 38.844 24.528 ;
     RECT  38.801 24.552 38.844 24.672 ;
     RECT  38.801 24.696 38.844 24.816 ;
     RECT  38.801 24.84 38.844 25.008 ;
     RECT  38.801 25.032 38.844 25.152 ;
     RECT  38.801 25.176 38.844 25.296 ;
     RECT  38.801 25.32 38.844 25.488 ;
     RECT  38.801 25.512 38.844 25.632 ;
     RECT  38.801 25.656 38.844 25.776 ;
     RECT  38.801 25.8 38.844 25.968 ;
     RECT  38.801 25.992 38.844 26.112 ;
     RECT  38.801 26.136 38.844 26.256 ;
     RECT  38.801 26.28 38.844 26.448 ;
     RECT  38.801 26.472 38.844 26.592 ;
     RECT  38.801 26.616 38.844 26.736 ;
     RECT  38.801 26.76 38.844 26.928 ;
     RECT  38.801 26.952 38.844 27.072 ;
     RECT  38.801 27.096 38.844 27.264 ;
     RECT  38.801 27.288 38.844 27.408 ;
     RECT  38.801 27.432 38.844 27.552 ;
     RECT  38.801 27.576 38.844 27.744 ;
     RECT  38.801 27.768 38.844 27.888 ;
     RECT  38.801 27.912 38.844 28.032 ;
     RECT  38.801 28.056 38.844 28.224 ;
     RECT  38.801 28.248 38.844 28.368 ;
     RECT  38.801 28.392 38.844 28.512 ;
     RECT  38.801 28.536 38.844 28.704 ;
     RECT  38.801 28.728 38.844 28.848 ;
     RECT  38.801 28.872 38.844 28.992 ;
     RECT  38.801 29.016 38.844 29.184 ;
     RECT  38.801 29.208 38.844 29.328 ;
     RECT  38.801 29.352 38.844 29.472 ;
     RECT  38.801 29.496 38.844 29.664 ;
     RECT  38.801 29.688 38.844 29.808 ;
     RECT  38.801 29.832 38.844 29.952 ;
     RECT  38.801 29.976 38.844 30.144 ;
     RECT  38.801 30.168 38.844 30.288 ;
     RECT  38.801 30.312 38.844 30.432 ;
     RECT  38.801 30.456 38.844 30.624 ;
     RECT  38.801 30.648 38.844 30.768 ;
     RECT  38.801 30.792 38.844 30.912 ;
     RECT  38.801 30.936 38.844 31.104 ;
     RECT  38.801 31.128 38.844 31.248 ;
     RECT  38.801 31.272 38.844 31.44 ;
     RECT  38.801 31.464 38.844 31.584 ;
     RECT  38.801 31.608 38.844 31.728 ;
     RECT  38.801 31.752 38.844 31.92 ;
     RECT  38.801 31.944 38.844 32.064 ;
     RECT  38.801 32.088 38.844 32.208 ;
     RECT  38.801 32.232 38.844 32.4 ;
     RECT  38.801 32.424 38.844 32.544 ;
     RECT  38.801 32.568 38.844 32.688 ;
     RECT  38.801 32.712 38.844 32.88 ;
     RECT  38.801 32.904 38.844 33.024 ;
     RECT  38.801 33.048 38.844 33.168 ;
     RECT  38.801 33.192 38.844 33.36 ;
     RECT  38.801 33.384 38.844 33.504 ;
     RECT  38.801 33.528 38.844 33.648 ;
     RECT  38.801 33.672 38.844 33.84 ;
     RECT  38.801 33.864 38.844 33.984 ;
     RECT  38.801 34.008 38.844 34.128 ;
     RECT  38.801 34.152 38.844 34.32 ;
     RECT  38.801 34.344 38.844 34.464 ;
     RECT  38.801 34.488 38.844 34.608 ;
     RECT  38.801 34.632 38.844 34.8 ;
     RECT  38.801 34.824 38.844 34.944 ;
     RECT  38.801 34.968 38.844 35.088 ;
     RECT  38.801 35.112 38.844 35.28 ;
     RECT  38.801 35.304 38.844 35.424 ;
     RECT  38.801 35.448 38.844 35.568 ;
     RECT  38.801 35.592 38.844 35.76 ;
     RECT  38.801 35.784 38.844 35.904 ;
     RECT  38.801 35.928 38.844 36.096 ;
     RECT  38.801 36.12 38.844 36.24 ;
     RECT  38.801 36.264 38.844 36.384 ;
     RECT  38.801 36.408 38.844 36.576 ;
     RECT  38.801 36.6 38.844 36.72 ;
     RECT  38.801 36.744 38.844 36.864 ;
     RECT  38.801 36.888 38.844 37.056 ;
     RECT  38.801 37.08 38.844 37.2 ;
     RECT  38.801 37.224 38.844 37.344 ;
     RECT  38.801 37.368 38.844 37.536 ;
     RECT  38.801 37.56 38.844 37.68 ;
     RECT  38.801 37.704 38.844 37.824 ;
     RECT  38.801 37.848 38.844 38.016 ;
     RECT  38.801 38.04 38.844 38.16 ;
     RECT  38.801 38.184 38.844 38.304 ;
     RECT  38.801 38.328 38.844 38.496 ;
     RECT  38.801 38.52 38.844 38.64 ;
     RECT  38.801 38.664 38.844 38.784 ;
     RECT  38.801 38.808 38.844 38.976 ;
     RECT  38.801 39 38.844 39.12 ;
     RECT  38.801 39.144 38.844 39.264 ;
     RECT  38.801 39.288 38.844 39.456 ;
     RECT  38.801 39.48 38.844 39.6 ;
     RECT  38.801 39.624 38.844 39.744 ;
     RECT  38.801 39.768 38.844 39.936 ;
     RECT  38.801 39.96 38.844 40.08 ;
     RECT  38.801 40.104 38.844 40.224 ;
     RECT  38.801 40.248 38.844 40.416 ;
     RECT  38.801 40.44 38.844 40.56 ;
     RECT  38.801 40.584 38.844 40.752 ;
     RECT  38.801 40.776 38.844 40.896 ;
     RECT  38.801 40.92 38.844 41.04 ;
     RECT  38.801 41.064 38.844 41.232 ;
     RECT  38.801 41.256 38.844 41.376 ;
     RECT  38.801 41.4 38.844 41.52 ;
     RECT  38.801 41.544 38.844 41.712 ;
     RECT  38.801 41.736 38.844 41.856 ;
     RECT  38.801 41.88 38.844 42 ;
     RECT  38.801 42.024 38.844 42.192 ;
     RECT  38.801 42.216 38.844 42.336 ;
     RECT  38.801 42.36 38.844 42.48 ;
     RECT  38.801 42.504 38.844 42.672 ;
     RECT  38.801 42.696 38.844 42.816 ;
     RECT  38.801 42.84 38.844 42.96 ;
     RECT  38.801 42.984 38.844 43.152 ;
     RECT  38.801 43.176 38.844 43.296 ;
     RECT  38.801 43.32 38.844 43.44 ;
     RECT  38.801 43.464 38.844 43.632 ;
     RECT  38.801 43.656 38.844 43.776 ;
     RECT  38.801 43.8 38.844 43.92 ;
     RECT  38.801 43.944 38.844 44.112 ;
     RECT  38.801 44.136 38.844 44.256 ;
     RECT  38.801 44.28 38.844 44.4 ;
     RECT  38.801 44.424 38.844 44.592 ;
     RECT  38.801 44.616 38.844 44.736 ;
     RECT  38.801 44.76 38.844 44.928 ;
     RECT  38.801 44.952 38.844 45.072 ;
     RECT  38.801 45.096 38.844 45.216 ;
     RECT  38.801 45.24 38.844 45.408 ;
     RECT  38.801 45.432 38.844 45.552 ;
     RECT  38.801 45.576 38.844 45.696 ;
     RECT  38.801 45.72 38.844 45.888 ;
     RECT  38.801 45.912 38.844 46.032 ;
     RECT  38.801 46.056 38.844 46.176 ;
     RECT  38.801 46.2 38.844 46.368 ;
     RECT  38.801 46.392 38.844 46.512 ;
     RECT  38.801 46.536 38.844 46.656 ;
     RECT  38.801 46.68 38.844 46.848 ;
     RECT  38.801 46.872 38.844 46.992 ;
     RECT  38.801 47.016 38.844 47.136 ;
     RECT  38.801 47.16 38.844 47.328 ;
     RECT  38.801 47.352 38.844 47.472 ;
     RECT  38.801 47.496 38.844 47.616 ;
     RECT  38.801 47.64 38.844 47.808 ;
     RECT  38.801 47.832 38.844 47.952 ;
     RECT  38.801 47.976 38.844 48.096 ;
     RECT  38.801 48.12 38.844 48.288 ;
     RECT  38.801 48.312 38.844 48.432 ;
     RECT  38.801 48.456 38.844 48.576 ;
     RECT  38.801 48.6 38.844 48.768 ;
     RECT  38.801 48.792 38.844 48.912 ;
     RECT  38.801 48.936 38.844 49.056 ;
     RECT  38.801 49.08 38.844 49.248 ;
     RECT  38.801 49.272 38.844 49.392 ;
     RECT  38.801 49.416 38.844 49.584 ;
     RECT  38.801 49.608 38.844 49.728 ;
     RECT  38.801 49.752 38.844 49.872 ;
     RECT  38.801 49.896 38.844 50.064 ;
     RECT  38.801 50.088 38.844 50.208 ;
     RECT  38.801 50.232 38.844 50.352 ;
     RECT  38.801 50.376 38.844 50.544 ;
     RECT  38.801 50.568 38.844 50.688 ;
     RECT  38.801 50.712 38.844 50.832 ;
     RECT  38.801 50.856 38.844 51.024 ;
     RECT  38.801 51.048 38.844 51.168 ;
     RECT  38.801 51.192 38.844 51.312 ;
     RECT  38.801 51.336 38.844 51.504 ;
     RECT  38.801 51.528 38.844 51.648 ;
     RECT  38.801 51.672 38.844 51.792 ;
     RECT  38.801 51.816 38.844 51.984 ;
     RECT  38.801 52.008 38.844 52.128 ;
     RECT  38.801 52.152 38.844 52.272 ;
     RECT  38.801 52.296 38.844 52.464 ;
     RECT  38.801 52.488 38.844 52.608 ;
     RECT  38.801 52.632 38.844 52.752 ;
     RECT  38.801 52.776 38.844 52.944 ;
     RECT  38.801 52.968 38.844 53.088 ;
     RECT  38.801 53.112 38.844 53.232 ;
     RECT  38.801 53.256 38.844 53.424 ;
     RECT  38.801 53.448 38.844 53.568 ;
     RECT  38.801 53.592 38.844 53.712 ;
     RECT  38.801 53.736 38.844 53.904 ;
     RECT  38.801 53.928 38.844 54.048 ;
     RECT  38.801 54.072 38.844 54.24 ;
     RECT  38.801 54.264 38.844 54.384 ;
     RECT  38.801 54.408 38.844 54.528 ;
     RECT  38.801 54.552 38.844 54.72 ;
     RECT  38.801 54.744 38.844 54.864 ;
     RECT  38.801 54.888 38.844 55.008 ;
     RECT  38.801 55.032 38.844 55.2 ;
     RECT  38.801 55.224 38.844 55.344 ;
     RECT  38.801 55.368 38.844 55.488 ;
     RECT  38.801 55.512 38.844 55.68 ;
     RECT  38.801 55.704 38.844 55.824 ;
     RECT  38.801 55.848 38.844 55.968 ;
     RECT  38.801 55.992 38.844 56.16 ;
     RECT  38.801 56.184 38.844 56.304 ;
     RECT  38.801 56.328 38.844 56.448 ;
     RECT  38.801 56.472 38.844 56.64 ;
     RECT  38.801 56.664 38.844 56.784 ;
     RECT  38.801 56.808 38.844 56.928 ;
     RECT  38.801 56.952 38.844 57.12 ;
     RECT  38.801 57.144 38.844 57.264 ;
     RECT  38.801 57.288 38.844 57.408 ;
     RECT  38.801 57.432 38.844 57.6 ;
     RECT  38.801 57.624 38.844 57.744 ;
     RECT  38.801 57.768 38.844 57.888 ;
     RECT  38.801 57.912 38.844 58.08 ;
     RECT  38.801 58.104 38.844 58.224 ;
     RECT  38.801 58.248 38.844 58.416 ;
     RECT  38.801 58.44 38.844 58.56 ;
     RECT  38.801 58.584 38.844 58.704 ;
     RECT  38.801 58.728 38.844 58.896 ;
     RECT  38.801 58.92 38.844 59.04 ;
     RECT  38.801 59.064 38.844 59.184 ;
     RECT  38.801 59.208 38.844 59.376 ;
     RECT  38.801 59.4 38.844 59.52 ;
     RECT  38.801 59.544 38.844 59.664 ;
     RECT  38.801 59.688 38.844 59.856 ;
     RECT  38.801 59.88 38.844 60 ;
     RECT  38.801 60.024 38.844 60.144 ;
     RECT  38.801 60.168 38.844 60.336 ;
     RECT  38.801 60.36 38.844 60.48 ;
     RECT  38.801 60.504 38.844 60.624 ;
     RECT  38.801 60.648 38.844 60.816 ;
     RECT  38.801 60.84 38.844 60.96 ;
     RECT  38.801 60.984 38.844 61.104 ;
     RECT  38.801 61.128 38.844 61.296 ;
     RECT  38.801 61.32 38.844 61.44 ;
     RECT  38.801 61.464 38.844 61.584 ;
     RECT  38.801 61.608 38.844 61.776 ;
     RECT  38.801 61.8 38.844 61.92 ;
     RECT  38.801 61.944 38.844 62.064 ;
     RECT  38.801 62.088 38.844 62.256 ;
     RECT  38.801 62.28 38.844 62.4 ;
     RECT  38.801 62.424 38.844 62.544 ;
     RECT  38.801 62.568 38.844 62.736 ;
     RECT  38.801 62.76 38.844 62.88 ;
     RECT  38.801 62.904 38.844 63.072 ;
     RECT  38.801 63.096 38.844 63.216 ;
     RECT  38.801 63.24 38.844 63.36 ;
     RECT  38.801 63.384 38.844 63.552 ;
     RECT  38.801 63.576 38.844 63.696 ;
     RECT  38.801 63.72 38.844 63.84 ;
     RECT  38.801 63.864 38.844 64.032 ;
     RECT  38.801 64.056 38.844 64.176 ;
     RECT  38.801 64.2 38.844 64.32 ;
     RECT  38.801 64.344 38.844 64.512 ;
     RECT  38.801 64.536 38.844 64.656 ;
     RECT  38.801 64.68 38.844 64.8 ;
     RECT  38.801 64.824 38.844 64.992 ;
     RECT  38.801 65.016 38.844 65.136 ;
     RECT  38.801 65.16 38.844 65.28 ;
     RECT  38.801 65.304 38.844 65.472 ;
     RECT  38.801 65.496 38.844 65.616 ;
     RECT  38.801 65.64 38.844 65.76 ;
     RECT  38.801 65.784 38.844 65.952 ;
     RECT  38.801 65.976 38.844 66.096 ;
     RECT  38.801 66.12 38.844 66.24 ;
     RECT  38.801 66.264 38.844 66.432 ;
     RECT  38.801 66.456 38.844 66.576 ;
     RECT  38.801 66.6 38.844 66.72 ;
     RECT  38.801 66.744 38.844 66.912 ;
     RECT  38.801 66.936 38.844 67.056 ;
     RECT  38.801 67.08 38.844 67.2 ;
     RECT  38.801 67.224 38.844 67.392 ;
     RECT  38.801 67.416 38.844 67.536 ;
     RECT  38.801 67.56 38.844 67.728 ;
     RECT  38.801 67.752 38.844 67.872 ;
     RECT  38.801 67.896 38.844 68.016 ;
     RECT  38.801 68.04 38.844 68.208 ;
     RECT  38.801 68.232 38.844 68.352 ;
     RECT  38.801 68.376 38.844 68.496 ;
     RECT  38.801 68.52 38.844 68.688 ;
     RECT  38.801 68.712 38.844 68.832 ;
     RECT  38.801 68.856 38.844 68.976 ;
     RECT  38.801 69 38.844 69.168 ;
     RECT  38.801 69.192 38.844 69.312 ;
     RECT  38.801 69.336 38.844 69.456 ;
     RECT  38.801 69.48 38.844 69.648 ;
     RECT  38.801 69.672 38.844 69.792 ;
     RECT  38.801 69.816 38.844 69.936 ;
     RECT  38.801 69.96 38.844 70.128 ;
     RECT  38.801 70.152 38.844 70.272 ;
     RECT  38.801 70.296 38.844 70.416 ;
     RECT  38.801 70.44 38.844 70.608 ;
     RECT  38.801 70.632 38.844 70.752 ;
     RECT  38.801 70.776 38.844 70.896 ;
     RECT  38.801 70.92 38.844 71.088 ;
     RECT  38.801 71.112 38.844 71.232 ;
     RECT  38.801 71.256 38.844 71.376 ;
     RECT  38.801 71.4 38.844 71.568 ;
     RECT  38.801 71.592 38.844 71.712 ;
     RECT  38.801 71.736 38.844 71.856 ;
     RECT  38.801 71.88 38.844 72.048 ;
     RECT  38.801 72.072 38.844 72.192 ;
     RECT  38.801 72.216 38.844 72.384 ;
     RECT  38.801 72.408 38.844 72.528 ;
     RECT  38.801 72.552 38.844 72.672 ;
     RECT  38.801 72.696 38.844 72.864 ;
     RECT  38.801 72.888 38.844 73.008 ;
     RECT  38.801 73.032 38.844 73.152 ;
     RECT  38.801 73.176 38.844 73.344 ;
     RECT  38.801 73.368 38.844 73.488 ;
     RECT  38.801 73.512 38.844 73.632 ;
     RECT  38.801 73.656 38.844 73.824 ;
     RECT  38.801 73.848 38.844 73.968 ;
     RECT  38.801 73.992 38.844 74.112 ;
     RECT  38.801 74.136 38.844 74.304 ;
     RECT  38.801 74.328 38.844 74.448 ;
     RECT  38.801 74.472 38.844 74.592 ;
     RECT  38.801 74.616 38.844 74.784 ;
     RECT  38.801 74.808 38.844 74.928 ;
     RECT  38.801 74.952 38.844 75.072 ;
     RECT  38.801 75.096 38.844 75.264 ;
     RECT  38.801 75.288 38.844 75.408 ;
     RECT  38.801 75.432 38.844 75.552 ;
     RECT  38.801 75.576 38.844 75.744 ;
     RECT  38.801 75.768 38.844 75.888 ;
     RECT  38.801 75.912 38.844 76.032 ;
     RECT  38.801 76.056 38.844 76.224 ;
     RECT  38.801 76.248 38.844 76.368 ;
     RECT  38.801 76.392 38.844 76.56 ;
     RECT  38.801 76.584 38.844 76.704 ;
     RECT  38.801 76.728 38.844 76.848 ;
     RECT  38.801 76.872 38.844 77.04 ;
     RECT  38.801 77.064 38.844 77.184 ;
     RECT  38.801 77.208 38.844 77.328 ;
     RECT  38.801 77.352 38.844 77.52 ;
     RECT  38.801 77.544 38.844 77.664 ;
     RECT  38.801 77.688 38.844 77.808 ;
     RECT  38.801 77.832 38.844 78 ;
     RECT  38.801 78.024 38.844 78.144 ;
     RECT  38.801 78.168 38.844 78.288 ;
     RECT  38.801 78.312 38.844 78.48 ;
     RECT  38.801 78.504 38.844 78.624 ;
     RECT  38.801 78.648 38.844 78.768 ;
     RECT  38.801 78.792 38.844 78.96 ;
     RECT  38.801 78.984 38.844 79.104 ;
     RECT  38.801 79.128 38.844 79.248 ;
     RECT  38.801 79.272 38.844 79.44 ;
     RECT  38.801 79.464 38.844 79.584 ;
     RECT  38.801 79.608 38.844 79.728 ;
     RECT  38.801 79.752 38.844 79.92 ;
     RECT  38.801 79.944 38.844 80.064 ;
     RECT  38.801 80.088 38.844 80.208 ;
     RECT  38.801 80.232 38.844 80.4 ;
     RECT  38.801 80.424 38.844 80.544 ;
     RECT  38.801 80.568 38.844 80.688 ;
     RECT  38.801 80.712 38.844 80.88 ;
     RECT  38.801 80.904 38.844 81.024 ;
     RECT  38.801 81.048 38.844 81.216 ;
     RECT  38.801 81.24 38.844 81.36 ;
     RECT  38.801 81.384 38.844 81.504 ;
     RECT  38.801 81.528 38.844 81.696 ;
     RECT  38.801 81.72 38.844 81.84 ;
     RECT  38.801 81.864 38.844 81.984 ;
     RECT  38.801 82.008 38.844 82.176 ;
     RECT  38.801 82.2 38.844 82.32 ;
     RECT  38.801 82.344 38.844 82.464 ;
     RECT  38.801 82.488 38.844 82.656 ;
     RECT  38.801 82.68 38.844 82.8 ;
     RECT  38.801 82.824 38.844 82.944 ;
     RECT  38.801 82.968 38.844 83.136 ;
     RECT  38.801 83.16 38.844 83.28 ;
     RECT  38.801 83.304 38.844 83.424 ;
     RECT  38.801 83.448 38.844 83.616 ;
     RECT  38.801 83.64 38.844 83.76 ;
     RECT  38.801 83.784 38.844 83.904 ;
     RECT  38.801 83.928 38.844 84.096 ;
     RECT  38.801 84.12 38.844 84.24 ;
     RECT  38.801 84.264 38.844 84.384 ;
     RECT  38.801 84.408 38.844 84.576 ;
     RECT  38.801 84.6 38.844 84.72 ;
     RECT  38.801 84.744 38.844 84.864 ;
     RECT  38.801 84.888 38.844 85.056 ;
     RECT  38.801 85.08 38.844 85.2 ;
     RECT  38.801 85.224 38.844 85.344 ;
     RECT  38.801 85.368 38.844 85.536 ;
     RECT  38.801 85.56 38.844 85.68 ;
     RECT  38.801 85.704 38.844 85.872 ;
     RECT  38.801 85.896 38.844 86.016 ;
     RECT  38.801 86.04 38.844 86.16 ;
     RECT  38.801 86.184 38.844 86.352 ;
     RECT  38.801 86.376 38.844 86.496 ;
     RECT  38.801 86.52 38.844 86.64 ;
     RECT  38.801 86.664 38.844 86.832 ;
     RECT  38.801 86.856 38.844 86.976 ;
     RECT  38.801 87 38.844 87.12 ;
     RECT  38.801 87.144 38.844 87.312 ;
     RECT  38.801 87.336 38.844 87.456 ;
     RECT  38.801 87.48 38.844 87.6 ;
     RECT  38.801 87.624 38.844 87.792 ;
     RECT  38.801 87.816 38.844 87.936 ;
     RECT  38.801 87.96 38.844 88.08 ;
     RECT  38.801 88.104 38.844 88.272 ;
     RECT  38.801 88.296 38.844 88.416 ;
     RECT  38.801 88.44 38.844 88.56 ;
     RECT  38.801 88.584 38.844 88.752 ;
     RECT  38.801 88.776 38.844 88.896 ;
     RECT  38.801 88.92 38.844 89.04 ;
     RECT  38.801 89.064 38.844 89.232 ;
     RECT  38.801 89.256 38.844 89.376 ;
     RECT  38.801 89.4 38.844 89.52 ;
     RECT  38.801 89.544 38.844 89.712 ;
     RECT  38.801 89.736 38.844 89.856 ;
     RECT  38.801 89.88 38.844 90.048 ;
     RECT  38.801 90.072 38.844 90.192 ;
     RECT  38.801 90.216 38.844 90.336 ;
     RECT  38.801 90.36 38.844 90.528 ;
     RECT  38.801 90.552 38.844 90.672 ;
     RECT  38.801 90.696 38.844 90.816 ;
     RECT  38.801 90.84 38.844 91.008 ;
     RECT  38.801 91.032 38.844 91.152 ;
     RECT  38.801 91.176 38.844 92.112 ;
    LAYER M5 ;
     RECT  2.4 2.137 2.52 2.151 ;
     RECT  5.1 2.137 5.22 2.151 ;
     RECT  7.8 2.137 7.92 2.151 ;
     RECT  10.5 2.137 10.62 2.151 ;
     RECT  13.2 2.137 13.32 2.151 ;
     RECT  15.9 2.137 16.02 2.151 ;
     RECT  18.6 2.137 18.72 2.151 ;
     RECT  21.3 2.137 21.42 2.151 ;
     RECT  24 2.137 24.12 2.151 ;
     RECT  26.7 2.137 26.82 2.151 ;
     RECT  29.4 2.137 29.52 2.151 ;
     RECT  32.1 2.137 32.22 2.151 ;
     RECT  34.8 2.137 34.92 2.151 ;
     RECT  15.9 2.151 16.212 2.197 ;
     RECT  7.8 2.151 8.112 2.245 ;
     RECT  10.5 2.151 10.812 2.245 ;
     RECT  21.3 2.151 21.612 2.245 ;
     RECT  29.4 2.151 29.712 2.245 ;
     RECT  32.1 2.151 32.412 2.293 ;
     RECT  9.12 2.389 9.144 2.531 ;
     RECT  32.1 2.293 32.76 2.581 ;
     RECT  31.344 2.581 32.76 2.627 ;
     RECT  24 2.151 24.312 2.725 ;
     RECT  7.056 2.245 8.112 2.773 ;
     RECT  5.1 2.151 5.412 2.821 ;
     RECT  21.3 2.245 22.104 2.821 ;
     RECT  31.344 2.627 32.412 2.821 ;
     RECT  30.768 2.821 32.412 2.867 ;
     RECT  15.9 2.197 16.536 2.869 ;
     RECT  20.544 2.821 22.104 3.011 ;
     RECT  10.5 2.245 11.208 3.013 ;
     RECT  20.544 3.011 21.612 3.059 ;
     RECT  15.9 2.869 16.92 3.109 ;
     RECT  26.7 2.151 27.012 3.157 ;
     RECT  0.144 3.301 0.168 3.443 ;
     RECT  10.32 3.013 11.208 3.443 ;
     RECT  7.056 2.773 8.52 3.781 ;
     RECT  10.5 3.443 11.208 3.827 ;
     RECT  24 2.725 24.408 3.829 ;
     RECT  4.512 2.821 5.412 3.875 ;
     RECT  21.168 3.059 21.612 3.875 ;
     RECT  29.136 2.245 29.712 3.877 ;
     RECT  30.768 2.867 30.792 3.877 ;
     RECT  13.2 2.151 13.512 3.925 ;
     RECT  24 3.829 24.888 3.971 ;
     RECT  15.9 3.109 16.968 3.973 ;
     RECT  18.6 2.151 18.912 3.973 ;
     RECT  7.056 3.781 9.144 4.019 ;
     RECT  29.136 3.877 30.792 4.019 ;
     RECT  29.4 4.019 30.792 4.117 ;
     RECT  31.92 2.867 32.412 4.117 ;
     RECT  19.92 3.877 19.944 4.451 ;
     RECT  26.7 3.157 27.576 4.643 ;
     RECT  13.2 3.925 13.656 4.883 ;
     RECT  15.9 3.973 18.912 5.077 ;
     RECT  24 3.971 24.6 5.123 ;
     RECT  15.9 5.077 19.416 5.171 ;
     RECT  21.3 3.875 21.612 5.221 ;
     RECT  20.928 5.221 21.612 5.557 ;
     RECT  15.9 5.171 17.112 5.651 ;
     RECT  7.056 4.019 8.52 5.653 ;
     RECT  29.4 4.117 32.412 5.749 ;
     RECT  33.648 5.605 33.672 5.749 ;
     RECT  29.4 5.749 33.672 5.891 ;
     RECT  31.872 5.891 33.672 6.179 ;
     RECT  7.056 5.653 9.096 6.227 ;
     RECT  5.1 3.875 5.412 6.229 ;
     RECT  10.5 3.827 10.92 6.229 ;
     RECT  24 5.123 24.408 6.325 ;
     RECT  7.056 6.227 8.952 6.421 ;
     RECT  33.648 6.179 33.672 6.805 ;
     RECT  34.8 2.151 35.112 6.805 ;
     RECT  31.872 6.179 32.412 6.851 ;
     RECT  13.2 4.883 13.512 7.285 ;
     RECT  23.04 6.325 24.408 7.333 ;
     RECT  25.44 5.605 25.464 7.333 ;
     RECT  29.4 5.891 30.6 7.379 ;
     RECT  3.696 6.805 3.72 7.381 ;
     RECT  4.8 6.229 5.412 7.381 ;
     RECT  12.24 7.285 13.512 7.427 ;
     RECT  29.4 7.379 30.504 7.477 ;
     RECT  26.7 4.643 27.012 7.621 ;
     RECT  6.96 6.421 8.952 7.811 ;
     RECT  26.7 7.621 27.336 7.861 ;
     RECT  20.832 5.557 21.612 7.909 ;
     RECT  3.696 7.381 5.412 8.003 ;
     RECT  26.7 7.861 27.912 8.003 ;
     RECT  33.648 6.805 35.112 8.147 ;
     RECT  13.104 7.427 13.512 8.195 ;
     RECT  18.6 5.171 19.416 8.195 ;
     RECT  20.832 7.909 21.72 8.195 ;
     RECT  10.5 6.229 11.256 8.197 ;
     RECT  2.4 2.151 2.712 8.245 ;
     RECT  7.68 7.811 8.952 8.293 ;
     RECT  15.9 5.651 16.44 8.341 ;
     RECT  10.5 8.197 11.64 8.483 ;
     RECT  26.7 8.003 27.336 8.675 ;
     RECT  2.4 8.245 2.808 8.965 ;
     RECT  34.8 8.147 35.112 9.061 ;
     RECT  2.304 8.965 2.808 9.107 ;
     RECT  7.68 8.293 9.24 9.395 ;
     RECT  20.832 8.195 21.612 9.637 ;
     RECT  13.2 8.195 13.512 9.877 ;
     RECT  10.5 8.483 11.256 9.925 ;
     RECT  18.6 8.195 18.912 9.925 ;
     RECT  7.68 9.395 9.096 10.115 ;
     RECT  13.104 9.877 13.512 10.211 ;
     RECT  26.7 8.675 27.288 10.211 ;
     RECT  32.1 6.851 32.412 10.213 ;
     RECT  29.28 7.477 30.504 10.259 ;
     RECT  6.672 9.349 6.696 10.307 ;
     RECT  29.4 10.259 30.504 10.307 ;
     RECT  20.544 9.637 21.612 10.309 ;
     RECT  23.04 7.333 25.464 10.309 ;
     RECT  7.68 10.115 8.952 10.355 ;
     RECT  20.544 10.309 25.464 10.403 ;
     RECT  15.9 8.341 17.16 10.499 ;
     RECT  10.5 9.925 11.832 10.597 ;
     RECT  34.8 9.061 35.352 10.693 ;
     RECT  4.656 8.003 5.412 10.883 ;
     RECT  34.8 10.693 35.688 10.883 ;
     RECT  20.544 10.403 22.152 10.931 ;
     RECT  14.592 10.597 14.616 10.933 ;
     RECT  7.8 10.355 8.952 11.173 ;
     RECT  18.24 9.925 18.912 11.317 ;
     RECT  26.7 10.211 27.012 11.317 ;
     RECT  20.88 10.931 22.152 11.363 ;
     RECT  7.8 11.173 9.144 11.365 ;
     RECT  10.272 10.597 11.832 11.459 ;
     RECT  26.7 11.317 27.96 11.461 ;
     RECT  17.808 11.317 18.912 11.603 ;
     RECT  15.9 10.499 16.728 11.653 ;
     RECT  26.7 11.461 28.056 11.699 ;
     RECT  4.8 10.883 5.412 11.701 ;
     RECT  4.8 11.701 6.072 11.749 ;
     RECT  7.344 11.365 9.144 11.749 ;
     RECT  14.592 10.933 14.808 11.797 ;
     RECT  15.792 11.653 16.728 11.797 ;
     RECT  23.472 10.403 25.464 11.797 ;
     RECT  26.7 11.699 27.96 11.797 ;
     RECT  31.92 10.213 32.412 11.797 ;
     RECT  4.8 11.749 9.144 11.893 ;
     RECT  2.4 9.107 2.808 11.939 ;
     RECT  23.472 11.797 27.96 12.035 ;
     RECT  14.592 11.797 16.728 12.037 ;
     RECT  29.4 10.307 29.712 12.517 ;
     RECT  3.936 11.893 9.144 12.563 ;
     RECT  10.5 11.459 11.832 12.563 ;
     RECT  33.648 8.147 33.672 12.563 ;
     RECT  6.768 12.563 9.144 12.661 ;
     RECT  14.592 12.037 17.208 12.755 ;
     RECT  14.832 12.755 17.208 12.947 ;
     RECT  23.808 12.035 27.96 12.995 ;
     RECT  6.768 12.661 9.24 13.091 ;
     RECT  6.768 13.091 9.144 13.187 ;
     RECT  34.8 10.883 35.112 13.333 ;
     RECT  14.832 12.947 17.064 13.379 ;
     RECT  24 12.995 27.96 13.475 ;
     RECT  34.8 13.333 35.928 13.475 ;
     RECT  7.8 13.187 9.144 13.523 ;
     RECT  6.768 13.187 6.792 13.573 ;
     RECT  3.936 12.563 5.412 13.619 ;
     RECT  20.88 11.363 21.612 13.621 ;
     RECT  11.808 12.563 11.832 13.763 ;
     RECT  6.432 13.573 6.792 13.955 ;
     RECT  10.5 12.563 10.812 14.149 ;
     RECT  31.008 11.797 32.412 14.197 ;
     RECT  14.832 13.379 14.856 14.243 ;
     RECT  34.8 13.475 35.112 14.485 ;
     RECT  10.272 14.149 10.812 14.629 ;
     RECT  34.8 14.485 35.4 14.675 ;
     RECT  10.272 14.629 11.592 14.771 ;
     RECT  2.4 11.939 2.712 14.773 ;
     RECT  7.8 13.523 8.376 14.773 ;
     RECT  24 13.475 25.128 14.773 ;
     RECT  10.272 14.771 11.16 14.867 ;
     RECT  26.4 13.475 27.96 14.869 ;
     RECT  20.16 13.621 21.612 14.915 ;
     RECT  23.088 14.773 25.128 14.915 ;
     RECT  29.088 12.517 29.712 15.347 ;
     RECT  37.536 15.301 37.56 15.491 ;
     RECT  20.88 14.915 21.612 15.733 ;
     RECT  10.5 14.867 11.16 15.829 ;
     RECT  10.368 15.829 11.256 15.877 ;
     RECT  7.8 14.773 8.808 15.973 ;
     RECT  10.272 15.877 11.256 15.973 ;
     RECT  7.8 15.973 11.256 16.019 ;
     RECT  23.088 14.915 24.504 16.115 ;
     RECT  23.136 16.115 24.504 16.165 ;
     RECT  7.8 16.019 11.16 16.307 ;
     RECT  4.848 13.619 5.412 16.405 ;
     RECT  6.432 13.955 6.648 16.405 ;
     RECT  14.832 15.589 14.856 16.453 ;
     RECT  15.9 13.379 17.064 16.453 ;
     RECT  4.848 16.405 6.648 16.501 ;
     RECT  7.8 16.307 10.92 16.501 ;
     RECT  13.2 10.211 13.512 16.501 ;
     RECT  26.208 14.869 27.96 16.597 ;
     RECT  30.816 14.197 32.412 16.739 ;
     RECT  18.6 11.603 18.912 16.885 ;
     RECT  31.344 16.739 32.412 16.885 ;
     RECT  14.832 16.453 17.064 16.981 ;
     RECT  29.4 15.347 29.712 16.981 ;
     RECT  2.4 14.773 3.336 17.075 ;
     RECT  23.136 16.165 24.552 17.077 ;
     RECT  31.344 16.885 33 17.077 ;
     RECT  13.056 16.501 13.512 17.123 ;
     RECT  14.832 16.981 17.208 17.123 ;
     RECT  4.848 16.501 10.92 17.171 ;
     RECT  31.344 17.077 33.096 17.219 ;
     RECT  37.008 17.077 37.032 17.219 ;
     RECT  23.136 17.077 24.984 17.221 ;
     RECT  20.88 15.733 21.816 17.267 ;
     RECT  31.344 17.219 32.616 17.267 ;
     RECT  4.848 17.171 10.812 17.411 ;
     RECT  23.136 17.221 25.08 17.411 ;
     RECT  31.344 17.267 32.52 17.459 ;
     RECT  18.6 16.885 19.896 17.555 ;
     RECT  24 17.411 25.08 17.555 ;
     RECT  14.832 17.123 16.68 17.603 ;
     RECT  4.848 17.411 8.856 17.605 ;
     RECT  26.16 16.597 27.96 17.605 ;
     RECT  29.04 16.981 29.712 17.605 ;
     RECT  34.8 14.675 35.112 17.605 ;
     RECT  4.416 17.605 8.856 17.651 ;
     RECT  12.048 17.845 12.072 17.987 ;
     RECT  13.2 17.123 13.512 18.133 ;
     RECT  13.104 18.133 13.512 18.181 ;
     RECT  31.344 17.459 32.412 18.419 ;
     RECT  31.584 18.419 32.412 18.661 ;
     RECT  4.416 17.651 5.412 18.707 ;
     RECT  14.832 17.603 16.632 18.707 ;
     RECT  18.6 17.555 19.512 18.757 ;
     RECT  6.816 17.651 8.856 18.851 ;
     RECT  34.56 17.605 35.112 18.851 ;
     RECT  14.928 18.707 16.632 18.853 ;
     RECT  17.808 18.757 19.512 18.853 ;
     RECT  22.848 18.757 22.872 19.093 ;
     RECT  6.96 18.851 8.856 19.237 ;
     RECT  20.88 17.267 21.612 19.237 ;
     RECT  24 17.555 24.504 19.333 ;
     RECT  13.008 18.181 13.512 19.477 ;
     RECT  24 19.333 24.936 19.477 ;
     RECT  31.584 18.661 32.52 19.523 ;
     RECT  31.68 19.523 32.52 19.573 ;
     RECT  34.8 18.851 35.112 19.573 ;
     RECT  4.752 18.707 5.412 19.619 ;
     RECT  20.832 19.237 21.612 19.621 ;
     RECT  22.848 19.093 22.968 19.621 ;
     RECT  13.008 19.477 13.944 19.717 ;
     RECT  14.928 18.853 19.512 19.717 ;
     RECT  20.832 19.621 22.968 19.765 ;
     RECT  13.008 19.717 19.512 19.811 ;
     RECT  24 19.477 25.032 19.859 ;
     RECT  20.544 19.765 22.968 19.907 ;
     RECT  31.68 19.573 33.144 19.907 ;
     RECT  34.8 19.573 35.352 19.907 ;
     RECT  2.4 17.075 2.712 19.909 ;
     RECT  6.96 19.237 9.096 19.909 ;
     RECT  20.832 19.907 22.968 20.195 ;
     RECT  26.16 17.605 29.712 20.339 ;
     RECT  21.12 20.195 22.968 20.485 ;
     RECT  24 19.859 24.936 20.485 ;
     RECT  13.008 19.811 18.912 20.579 ;
     RECT  31.68 19.907 32.412 20.677 ;
     RECT  14.592 20.579 18.912 20.819 ;
     RECT  26.16 20.339 27.012 20.869 ;
     RECT  2.4 19.909 3.24 21.155 ;
     RECT  14.64 20.819 18.912 21.155 ;
     RECT  21.12 20.485 24.936 21.155 ;
     RECT  28.032 20.339 29.712 21.155 ;
     RECT  37.008 20.917 37.032 21.155 ;
     RECT  4.848 19.619 5.412 21.445 ;
     RECT  6.864 19.909 9.096 21.445 ;
     RECT  4.848 21.445 9.096 21.587 ;
     RECT  4.848 21.587 5.928 21.635 ;
     RECT  26.064 20.869 27.012 21.637 ;
     RECT  28.032 21.155 28.056 21.637 ;
     RECT  26.064 21.637 28.056 21.683 ;
     RECT  21.12 21.155 22.872 21.733 ;
     RECT  24 21.155 24.936 21.781 ;
     RECT  13.008 20.579 13.512 21.827 ;
     RECT  20.544 21.733 22.872 21.875 ;
     RECT  29.088 21.155 29.712 22.067 ;
     RECT  31.296 20.677 32.412 22.165 ;
     RECT  21.12 21.875 22.872 22.211 ;
     RECT  10.5 17.411 10.812 22.405 ;
     RECT  22.848 22.211 22.872 22.597 ;
     RECT  24 21.781 25.176 22.597 ;
     RECT  31.296 22.165 32.904 22.739 ;
     RECT  18.144 21.155 18.912 22.741 ;
     RECT  26.208 21.683 28.056 22.741 ;
     RECT  13.104 21.827 13.512 22.787 ;
     RECT  10.272 22.405 10.812 23.123 ;
     RECT  13.2 22.787 13.512 23.125 ;
     RECT  14.64 21.155 17.064 23.125 ;
     RECT  31.68 22.739 32.904 23.219 ;
     RECT  13.2 23.125 17.064 23.269 ;
     RECT  18.144 22.741 19.368 23.269 ;
     RECT  13.2 23.269 19.368 23.603 ;
     RECT  22.848 22.597 25.176 23.749 ;
     RECT  26.208 22.741 28.104 23.749 ;
     RECT  10.32 23.123 10.812 23.845 ;
     RECT  29.4 22.067 29.712 23.845 ;
     RECT  21.12 22.211 21.612 23.893 ;
     RECT  22.848 23.749 28.104 23.893 ;
     RECT  10.32 23.845 10.92 24.371 ;
     RECT  10.32 24.371 10.812 24.611 ;
     RECT  34.8 19.907 35.112 24.613 ;
     RECT  29.088 23.845 29.712 24.659 ;
     RECT  10.368 24.611 10.812 24.707 ;
     RECT  31.68 23.219 32.412 24.757 ;
     RECT  33.456 23.749 33.48 24.757 ;
     RECT  29.4 24.659 29.712 24.901 ;
     RECT  21.12 23.893 28.104 24.947 ;
     RECT  7.344 21.587 9.096 25.043 ;
     RECT  31.68 24.757 33.48 25.139 ;
     RECT  34.704 24.613 35.112 25.187 ;
     RECT  5.1 21.635 5.928 25.333 ;
     RECT  31.68 25.139 32.52 25.427 ;
     RECT  5.1 25.333 6.072 25.669 ;
     RECT  7.8 25.043 9.096 25.715 ;
     RECT  4.128 25.669 6.072 25.765 ;
     RECT  13.2 23.603 18.912 25.813 ;
     RECT  19.968 24.853 19.992 25.813 ;
     RECT  29.4 24.901 29.832 26.197 ;
     RECT  13.2 25.813 19.992 26.243 ;
     RECT  4.128 25.765 6.168 26.291 ;
     RECT  13.2 26.243 14.52 26.293 ;
     RECT  7.8 25.715 9.048 26.341 ;
     RECT  31.68 25.427 32.412 26.437 ;
     RECT  28.08 24.947 28.104 26.627 ;
     RECT  13.104 26.293 14.52 26.629 ;
     RECT  15.648 26.243 19.032 26.723 ;
     RECT  12.672 26.629 14.52 26.725 ;
     RECT  15.9 26.723 19.032 26.771 ;
     RECT  26.7 24.947 27.012 26.773 ;
     RECT  7.68 26.341 9.048 26.869 ;
     RECT  21.12 24.947 25.368 27.157 ;
     RECT  7.68 26.869 9.192 27.253 ;
     RECT  12.288 26.725 14.52 27.301 ;
     RECT  10.5 24.707 10.812 27.349 ;
     RECT  12.288 27.301 14.856 27.349 ;
     RECT  7.392 27.253 9.192 27.395 ;
     RECT  7.68 27.395 9.192 27.443 ;
     RECT  10.5 27.349 14.856 27.539 ;
     RECT  7.68 27.443 9.144 27.635 ;
     RECT  10.5 27.539 10.92 27.925 ;
     RECT  29.4 26.197 30.024 28.069 ;
     RECT  31.68 26.437 33.384 28.307 ;
     RECT  5.1 26.291 6.168 28.309 ;
     RECT  26.7 26.773 27.96 28.405 ;
     RECT  5.1 28.309 6.648 28.453 ;
     RECT  7.68 27.635 8.808 28.453 ;
     RECT  10.224 27.925 10.92 28.453 ;
     RECT  12.288 27.539 14.856 28.453 ;
     RECT  15.9 26.771 18.912 28.453 ;
     RECT  34.8 25.187 35.112 28.837 ;
     RECT  9.888 28.453 10.92 28.933 ;
     RECT  31.68 28.307 33.096 28.979 ;
     RECT  19.92 27.925 19.944 29.123 ;
     RECT  31.68 28.979 32.952 29.123 ;
     RECT  34.128 28.837 35.112 29.173 ;
     RECT  26.592 28.405 27.96 29.221 ;
     RECT  21.12 27.157 25.512 29.315 ;
     RECT  34.128 29.173 35.256 29.363 ;
     RECT  12.288 28.453 18.912 29.507 ;
     RECT  26.592 29.221 28.056 29.651 ;
     RECT  31.92 29.123 32.952 30.229 ;
     RECT  13.104 29.507 18.912 30.563 ;
     RECT  21.12 29.315 25.368 30.803 ;
     RECT  26.592 29.651 27.96 30.803 ;
     RECT  31.92 30.229 33 30.853 ;
     RECT  29.4 28.069 30.456 30.901 ;
     RECT  9.888 28.933 11.112 30.947 ;
     RECT  5.1 28.453 8.808 30.949 ;
     RECT  9.888 30.947 10.92 30.949 ;
     RECT  13.2 30.563 18.912 31.091 ;
     RECT  15.456 31.091 18.912 31.379 ;
     RECT  31.92 30.853 33.096 31.379 ;
     RECT  31.92 31.379 32.952 31.427 ;
     RECT  21.12 30.803 24.312 31.765 ;
     RECT  25.344 30.803 25.368 31.765 ;
     RECT  3.792 31.237 3.816 31.859 ;
     RECT  5.1 30.949 10.92 31.955 ;
     RECT  5.1 31.955 10.812 32.003 ;
     RECT  21.12 31.765 25.368 32.005 ;
     RECT  29.28 30.901 30.456 32.147 ;
     RECT  31.968 31.427 32.952 32.243 ;
     RECT  11.904 32.197 11.928 32.339 ;
     RECT  5.1 32.003 8.808 32.437 ;
     RECT  13.2 31.091 14.472 33.013 ;
     RECT  21.024 32.005 25.368 33.013 ;
     RECT  4.512 32.437 8.808 33.107 ;
     RECT  34.128 29.363 35.112 33.107 ;
     RECT  31.968 32.243 32.616 33.445 ;
     RECT  31.968 33.445 32.664 33.541 ;
     RECT  12.192 33.445 12.216 33.635 ;
     RECT  29.28 32.147 29.712 34.069 ;
     RECT  15.9 31.379 18.912 34.163 ;
     RECT  9.888 32.003 10.812 34.501 ;
     RECT  29.184 34.069 29.712 34.501 ;
     RECT  19.92 34.357 19.944 34.645 ;
     RECT  20.976 33.013 25.368 34.645 ;
     RECT  19.92 34.645 25.368 34.741 ;
     RECT  26.7 30.803 27.96 34.741 ;
     RECT  34.8 33.107 35.112 34.741 ;
     RECT  19.92 34.741 27.96 34.787 ;
     RECT  18.6 34.163 18.912 34.981 ;
     RECT  19.92 34.787 24.552 34.981 ;
     RECT  13.2 33.013 14.568 35.029 ;
     RECT  13.2 35.029 14.616 35.075 ;
     RECT  4.512 33.107 8.664 35.123 ;
     RECT  2.4 21.155 2.712 35.317 ;
     RECT  4.512 35.123 6.264 35.363 ;
     RECT  31.968 33.541 33.048 35.509 ;
     RECT  34.272 34.741 35.112 35.509 ;
     RECT  18.6 34.981 24.552 35.699 ;
     RECT  13.2 35.075 13.608 35.843 ;
     RECT  31.968 35.509 35.112 35.987 ;
     RECT  15.9 34.163 17.4 35.989 ;
     RECT  18.6 35.699 22.68 35.989 ;
     RECT  24 35.699 24.552 35.989 ;
     RECT  13.2 35.843 13.512 36.037 ;
     RECT  7.68 35.123 8.664 36.275 ;
     RECT  9.648 34.501 10.812 36.515 ;
     RECT  26.16 34.787 27.96 36.515 ;
     RECT  9.888 36.515 10.812 36.565 ;
     RECT  12.24 36.037 13.512 36.565 ;
     RECT  34.656 35.987 35.112 37.091 ;
     RECT  29.184 34.501 29.832 37.381 ;
     RECT  30.816 35.317 30.84 37.381 ;
     RECT  24 35.989 24.6 37.427 ;
     RECT  5.1 35.363 6.264 37.429 ;
     RECT  9.888 36.565 13.512 37.523 ;
     RECT  2.4 35.317 3.192 37.573 ;
     RECT  4.512 37.429 6.264 37.573 ;
     RECT  14.592 35.075 14.616 37.573 ;
     RECT  2.4 37.573 6.264 37.619 ;
     RECT  29.184 37.381 30.84 37.619 ;
     RECT  9.888 37.523 10.812 37.667 ;
     RECT  14.592 37.573 14.664 37.717 ;
     RECT  14.592 37.717 14.904 37.765 ;
     RECT  15.9 35.989 22.68 37.765 ;
     RECT  31.968 35.987 33.336 37.813 ;
     RECT  14.592 37.765 22.68 37.861 ;
     RECT  12.24 37.523 13.512 38.101 ;
     RECT  14.544 37.861 22.68 38.101 ;
     RECT  7.8 36.275 8.664 38.149 ;
     RECT  26.592 36.515 27.96 38.339 ;
     RECT  10.128 37.667 10.812 38.725 ;
     RECT  12.24 38.101 22.68 38.725 ;
     RECT  2.4 37.619 6.168 38.819 ;
     RECT  10.128 38.725 22.68 39.059 ;
     RECT  26.7 38.339 27.96 39.109 ;
     RECT  15.9 39.059 22.68 39.155 ;
     RECT  10.128 39.059 14.904 39.395 ;
     RECT  29.184 37.619 29.928 39.733 ;
     RECT  31.92 37.813 33.336 39.877 ;
     RECT  29.184 39.733 30.408 39.973 ;
     RECT  31.872 39.877 33.336 39.973 ;
     RECT  10.32 39.395 14.904 40.019 ;
     RECT  20.688 39.155 22.68 40.115 ;
     RECT  4.08 38.819 6.168 40.309 ;
     RECT  7.584 38.149 8.664 40.309 ;
     RECT  20.688 40.115 21.612 40.405 ;
     RECT  26.7 39.109 28.008 40.405 ;
     RECT  29.184 39.973 33.336 40.405 ;
     RECT  26.7 40.405 33.336 40.453 ;
     RECT  34.8 37.091 35.112 40.453 ;
     RECT  12.144 40.019 13.656 40.595 ;
     RECT  4.08 40.309 8.664 40.645 ;
     RECT  2.4 38.819 2.712 40.789 ;
     RECT  4.08 40.645 9.144 40.789 ;
     RECT  2.4 40.789 9.144 40.835 ;
     RECT  10.32 40.019 10.812 40.835 ;
     RECT  5.1 40.835 9.144 40.883 ;
     RECT  15.9 39.155 19.128 40.933 ;
     RECT  20.592 40.405 21.612 40.933 ;
     RECT  26.7 40.453 35.112 40.981 ;
     RECT  24 37.427 24.552 41.027 ;
     RECT  2.4 40.835 4.104 41.075 ;
     RECT  14.64 40.019 14.904 41.077 ;
     RECT  15.9 40.933 21.612 41.077 ;
     RECT  14.64 41.077 21.612 41.219 ;
     RECT  14.64 41.219 14.904 41.363 ;
     RECT  26.496 40.981 35.112 41.461 ;
     RECT  2.4 41.075 3.384 41.651 ;
     RECT  14.688 41.363 14.904 41.651 ;
     RECT  26.496 41.461 35.208 41.749 ;
     RECT  26.352 41.749 35.208 41.987 ;
     RECT  14.88 41.651 14.904 42.035 ;
     RECT  5.1 40.883 9.096 42.227 ;
     RECT  12.24 40.595 13.656 42.227 ;
     RECT  5.1 42.227 8.712 42.467 ;
     RECT  15.9 41.219 21.612 42.565 ;
     RECT  22.656 40.115 22.68 42.565 ;
     RECT  15.9 42.565 22.68 42.611 ;
     RECT  10.368 40.835 10.812 42.661 ;
     RECT  12.24 42.227 13.512 42.661 ;
     RECT  10.368 42.661 13.512 42.755 ;
     RECT  7.44 42.467 8.712 43.285 ;
     RECT  26.496 41.987 35.208 43.285 ;
     RECT  15.9 42.611 19.368 43.379 ;
     RECT  25.536 43.285 35.208 43.381 ;
     RECT  25.536 43.381 35.928 43.571 ;
     RECT  25.536 43.571 35.208 43.619 ;
     RECT  13.2 42.755 13.512 43.621 ;
     RECT  15.9 43.379 19.128 43.667 ;
     RECT  2.4 41.651 2.712 43.765 ;
     RECT  5.1 42.467 6.168 43.765 ;
     RECT  7.44 43.285 9.336 43.765 ;
     RECT  25.536 43.619 35.112 43.859 ;
     RECT  13.2 43.621 14.424 44.051 ;
     RECT  25.536 43.859 33.096 44.099 ;
     RECT  10.368 42.755 12.216 44.195 ;
     RECT  12.192 44.195 12.216 44.389 ;
     RECT  13.2 44.051 13.512 44.389 ;
     RECT  24 41.027 24.456 44.437 ;
     RECT  20.592 42.611 22.68 44.483 ;
     RECT  20.592 44.483 21.612 44.485 ;
     RECT  2.4 43.765 3.432 44.533 ;
     RECT  10.368 44.195 10.812 45.013 ;
     RECT  2.4 44.533 4.008 45.059 ;
     RECT  5.1 43.765 9.336 45.155 ;
     RECT  15.9 43.667 16.536 45.253 ;
     RECT  12.192 44.389 13.512 45.301 ;
     RECT  14.832 44.917 14.856 45.301 ;
     RECT  26.496 44.099 27.576 45.443 ;
     RECT  15.9 45.253 17.16 45.491 ;
     RECT  20.544 44.485 21.612 45.541 ;
     RECT  22.656 44.483 22.68 45.541 ;
     RECT  20.544 45.541 22.68 45.587 ;
     RECT  7.296 45.155 9.336 45.685 ;
     RECT  10.32 45.013 10.812 45.685 ;
     RECT  5.1 45.155 5.976 45.731 ;
     RECT  15.9 45.491 17.112 45.827 ;
     RECT  28.752 44.099 33.096 45.923 ;
     RECT  18.144 43.667 19.128 46.069 ;
     RECT  12.192 45.301 14.856 46.115 ;
     RECT  34.704 43.859 35.112 46.117 ;
     RECT  5.1 45.731 5.736 46.211 ;
     RECT  3.984 45.059 4.008 46.499 ;
     RECT  7.296 45.685 10.812 46.739 ;
     RECT  24 44.437 24.552 46.787 ;
     RECT  34.56 46.117 35.112 46.787 ;
     RECT  15.9 45.827 16.536 46.885 ;
     RECT  7.44 46.739 10.812 46.931 ;
     RECT  15.9 46.885 16.824 47.123 ;
     RECT  5.1 46.211 5.412 47.221 ;
     RECT  29.4 45.923 33.096 47.315 ;
     RECT  34.8 46.787 35.112 47.365 ;
     RECT  7.8 46.931 10.812 47.461 ;
     RECT  12.192 46.115 14.424 47.461 ;
     RECT  26.496 45.443 27.384 47.461 ;
     RECT  34.8 47.365 35.976 47.507 ;
     RECT  20.688 45.587 22.68 47.557 ;
     RECT  5.1 47.221 5.928 47.797 ;
     RECT  7.8 47.461 14.424 47.891 ;
     RECT  26.496 47.461 27.96 47.891 ;
     RECT  18.144 46.069 19.176 47.893 ;
     RECT  20.16 47.557 22.68 47.893 ;
     RECT  24 46.787 24.456 47.893 ;
     RECT  5.1 47.797 6.216 48.277 ;
     RECT  4.416 48.277 6.216 48.373 ;
     RECT  15.9 47.123 16.488 48.421 ;
     RECT  18.144 47.893 22.68 48.421 ;
     RECT  29.4 47.315 30.984 48.421 ;
     RECT  32.1 47.315 33.096 48.421 ;
     RECT  34.8 47.507 35.112 48.421 ;
     RECT  3.888 48.373 6.216 48.469 ;
     RECT  7.8 47.891 13.512 48.469 ;
     RECT  3.888 48.469 13.512 48.515 ;
     RECT  3.888 48.515 9.144 48.707 ;
     RECT  2.4 45.059 2.712 48.949 ;
     RECT  3.888 48.707 3.912 48.949 ;
     RECT  10.368 48.515 13.512 48.997 ;
     RECT  10.368 48.997 14.424 49.235 ;
     RECT  10.368 49.235 14.184 49.525 ;
     RECT  2.4 48.949 3.912 49.619 ;
     RECT  29.4 48.421 35.112 49.619 ;
     RECT  15.9 48.421 22.68 49.763 ;
     RECT  10.272 49.525 14.184 49.811 ;
     RECT  24 47.893 24.552 49.907 ;
     RECT  5.1 48.707 9.144 50.195 ;
     RECT  26.496 47.891 27.72 50.291 ;
     RECT  29.4 49.619 30.984 50.341 ;
     RECT  0.288 46.549 0.312 50.437 ;
     RECT  0.192 50.437 0.312 50.483 ;
     RECT  5.1 50.195 6.216 50.677 ;
     RECT  26.496 50.291 27.012 50.821 ;
     RECT  2.4 49.619 3.48 50.867 ;
     RECT  7.8 50.195 9.144 51.011 ;
     RECT  4.512 50.677 6.216 51.155 ;
     RECT  25.584 50.821 27.012 51.253 ;
     RECT  18.144 49.763 22.68 51.299 ;
     RECT  29.232 50.341 30.984 51.539 ;
     RECT  15.9 49.763 16.584 51.637 ;
     RECT  24 49.907 24.504 51.733 ;
     RECT  32.1 49.619 35.112 51.923 ;
     RECT  10.368 49.811 14.184 51.973 ;
     RECT  24 51.733 24.552 52.117 ;
     RECT  33.984 51.923 35.112 52.165 ;
     RECT  7.8 51.011 8.712 52.261 ;
     RECT  32.1 51.923 32.412 52.261 ;
     RECT  18.144 51.299 19.224 52.453 ;
     RECT  20.448 51.299 22.68 52.453 ;
     RECT  33.984 52.165 35.208 52.739 ;
     RECT  23.904 52.117 24.552 52.741 ;
     RECT  25.584 51.253 27.336 52.741 ;
     RECT  10.368 51.973 14.28 52.835 ;
     RECT  29.4 51.539 30.984 52.981 ;
     RECT  31.968 52.261 32.412 52.981 ;
     RECT  34.176 52.739 35.208 52.981 ;
     RECT  23.904 52.741 27.336 53.027 ;
     RECT  15.9 51.637 16.92 53.029 ;
     RECT  25.968 53.027 27.336 53.029 ;
     RECT  10.368 52.835 10.968 53.171 ;
     RECT  15.9 53.029 16.968 53.269 ;
     RECT  18.144 52.453 22.68 53.269 ;
     RECT  34.176 52.981 35.304 53.459 ;
     RECT  23.904 53.027 24.792 53.461 ;
     RECT  25.968 53.029 27.624 53.509 ;
     RECT  12.192 52.835 14.28 53.555 ;
     RECT  5.1 51.155 6.216 53.557 ;
     RECT  7.8 52.261 9.048 53.557 ;
     RECT  15.9 53.269 22.68 53.557 ;
     RECT  34.176 53.459 35.208 53.843 ;
     RECT  15.408 53.557 22.68 53.891 ;
     RECT  5.1 53.557 9.048 54.037 ;
     RECT  29.4 52.981 32.412 54.133 ;
     RECT  10.368 53.171 10.812 54.371 ;
     RECT  12.192 53.555 14.184 54.469 ;
     RECT  25.968 53.509 27.672 54.563 ;
     RECT  34.176 53.843 35.112 54.613 ;
     RECT  15.408 53.891 18.912 54.659 ;
     RECT  15.9 54.659 18.912 54.755 ;
     RECT  5.1 54.037 9.096 54.949 ;
     RECT  5.1 54.949 9.144 55.091 ;
     RECT  5.1 55.091 9.048 55.139 ;
     RECT  2.4 50.867 3.288 55.141 ;
     RECT  33.888 54.613 35.112 55.237 ;
     RECT  23.664 53.461 24.792 55.475 ;
     RECT  29.4 54.133 32.808 55.475 ;
     RECT  26.208 54.563 27.672 55.715 ;
     RECT  12.048 54.469 14.184 55.907 ;
     RECT  26.208 55.715 27.012 55.907 ;
     RECT  29.4 55.475 32.52 55.907 ;
     RECT  18.144 54.755 18.912 55.957 ;
     RECT  19.968 53.891 22.68 55.957 ;
     RECT  23.76 55.475 24.792 56.101 ;
     RECT  31.344 55.907 32.52 56.387 ;
     RECT  15.9 54.755 16.968 56.389 ;
     RECT  18.144 55.957 22.68 56.389 ;
     RECT  12.432 55.907 14.184 56.435 ;
     RECT  5.1 55.139 6.216 56.437 ;
     RECT  7.8 55.139 9.048 56.437 ;
     RECT  15.9 56.389 22.68 56.485 ;
     RECT  10.5 54.371 10.812 56.581 ;
     RECT  29.4 55.907 30.312 56.771 ;
     RECT  15.9 56.485 22.776 56.965 ;
     RECT  26.352 55.907 27.012 57.013 ;
     RECT  31.344 56.387 32.412 57.107 ;
     RECT  23.76 56.101 25.128 57.443 ;
     RECT  5.1 56.437 9.048 57.493 ;
     RECT  33.888 55.237 35.352 57.589 ;
     RECT  26.352 57.013 27.336 57.731 ;
     RECT  33.888 57.589 35.496 57.779 ;
     RECT  10.272 56.581 10.812 57.827 ;
     RECT  10.5 57.827 10.812 57.925 ;
     RECT  12.432 56.435 13.704 57.925 ;
     RECT  5.1 57.493 9.096 58.021 ;
     RECT  32.1 57.107 32.412 58.117 ;
     RECT  33.888 57.779 35.112 58.117 ;
     RECT  2.4 55.141 3.432 58.259 ;
     RECT  10.5 57.925 13.704 58.405 ;
     RECT  15.36 56.965 22.776 58.501 ;
     RECT  15.36 58.501 22.968 58.547 ;
     RECT  4.848 58.021 9.096 58.549 ;
     RECT  3.84 58.549 9.096 58.787 ;
     RECT  29.4 56.771 30.264 59.125 ;
     RECT  10.5 58.405 13.944 59.267 ;
     RECT  3.84 58.787 3.96 59.315 ;
     RECT  15.408 58.547 22.968 59.317 ;
     RECT  24 57.443 25.128 59.317 ;
     RECT  5.1 58.787 9.096 59.461 ;
     RECT  10.5 59.267 10.812 59.461 ;
     RECT  26.352 57.731 27.012 59.749 ;
     RECT  3.84 59.315 3.864 59.795 ;
     RECT  26.352 59.749 27.336 59.797 ;
     RECT  28.32 59.125 28.344 59.797 ;
     RECT  26.352 59.797 28.344 59.843 ;
     RECT  15.408 59.317 25.128 59.845 ;
     RECT  5.1 59.461 10.812 59.891 ;
     RECT  15.408 59.845 25.32 60.035 ;
     RECT  2.4 58.259 2.712 60.373 ;
     RECT  26.448 59.843 28.344 60.563 ;
     RECT  29.4 59.125 30.312 60.757 ;
     RECT  29.4 60.757 30.6 61.043 ;
     RECT  15.9 60.035 25.32 61.091 ;
     RECT  28.176 60.563 28.344 61.189 ;
     RECT  29.4 61.043 30.264 61.189 ;
     RECT  7.8 59.891 10.812 61.429 ;
     RECT  28.176 61.189 30.264 61.525 ;
     RECT  15.9 61.091 19.896 61.619 ;
     RECT  7.68 61.429 10.812 61.667 ;
     RECT  12.432 59.267 13.944 62.101 ;
     RECT  2.4 60.373 3.432 62.195 ;
     RECT  12.384 62.101 13.944 62.291 ;
     RECT  7.68 61.667 9.192 62.531 ;
     RECT  28.128 61.525 30.264 62.533 ;
     RECT  15.9 61.619 19.416 62.677 ;
     RECT  21.024 61.091 25.32 62.869 ;
     RECT  20.976 62.869 25.32 63.059 ;
     RECT  26.448 60.563 27.144 63.157 ;
     RECT  28.128 62.533 30.36 63.157 ;
     RECT  32.1 58.117 35.112 63.205 ;
     RECT  26.448 63.157 30.36 63.251 ;
     RECT  21.024 63.059 25.32 63.443 ;
     RECT  15.9 62.677 19.56 63.493 ;
     RECT  15.264 63.493 19.56 63.539 ;
     RECT  7.8 62.531 9.192 63.731 ;
     RECT  12.384 62.291 13.656 63.733 ;
     RECT  26.448 63.251 27.24 63.829 ;
     RECT  15.264 63.539 19.416 63.875 ;
     RECT  26.208 63.829 27.24 63.875 ;
     RECT  32.1 63.205 35.208 64.021 ;
     RECT  15.264 63.875 19.368 64.307 ;
     RECT  12.384 63.733 14.232 64.643 ;
     RECT  31.968 64.021 35.208 64.643 ;
     RECT  28.464 63.251 30.36 64.645 ;
     RECT  10.5 61.667 10.812 64.789 ;
     RECT  28.464 64.645 30.648 64.933 ;
     RECT  31.968 64.643 32.412 64.933 ;
     RECT  5.1 59.891 6.216 65.123 ;
     RECT  12.384 64.643 13.608 65.123 ;
     RECT  21.024 63.443 25.224 65.173 ;
     RECT  26.208 63.875 27.012 65.173 ;
     RECT  21.024 65.173 27.012 65.363 ;
     RECT  7.8 63.731 9.096 65.507 ;
     RECT  28.464 64.933 32.412 65.603 ;
     RECT  12.432 65.123 13.608 65.941 ;
     RECT  7.8 65.507 9.048 65.989 ;
     RECT  5.1 65.123 6.12 66.325 ;
     RECT  21.024 65.363 25.224 66.467 ;
     RECT  28.464 65.603 30.696 66.901 ;
     RECT  26.448 65.363 27.012 66.949 ;
     RECT  28.464 66.901 30.744 66.949 ;
     RECT  2.4 62.195 3.288 67.141 ;
     RECT  4.992 66.325 6.12 67.141 ;
     RECT  14.832 66.661 14.856 67.141 ;
     RECT  15.9 64.307 19.368 67.141 ;
     RECT  21.024 66.467 24.504 67.141 ;
     RECT  26.448 66.949 30.744 67.283 ;
     RECT  14.832 67.141 19.368 67.379 ;
     RECT  4.992 67.141 6.312 67.525 ;
     RECT  12.432 65.941 13.656 67.621 ;
     RECT  14.832 67.379 14.856 67.621 ;
     RECT  2.4 67.141 3.432 67.859 ;
     RECT  20.496 67.141 24.504 67.859 ;
     RECT  33.888 64.643 35.112 67.957 ;
     RECT  26.448 67.283 27.96 68.149 ;
     RECT  29.28 67.283 30.744 68.341 ;
     RECT  32.1 65.603 32.412 68.341 ;
     RECT  15.9 67.379 19.368 68.389 ;
     RECT  26.064 68.149 27.96 68.675 ;
     RECT  7.68 65.989 9.048 68.869 ;
     RECT  10.176 64.789 10.812 68.869 ;
     RECT  4.56 67.525 6.312 68.917 ;
     RECT  7.68 68.869 10.812 68.917 ;
     RECT  29.28 68.341 32.412 69.059 ;
     RECT  29.4 69.059 32.412 69.203 ;
     RECT  20.88 67.859 24.504 69.205 ;
     RECT  4.56 68.917 11.304 69.491 ;
     RECT  10.224 69.491 11.304 69.587 ;
     RECT  15.9 68.389 19.56 69.587 ;
     RECT  12.432 67.621 14.856 69.635 ;
     RECT  20.64 69.205 24.504 69.683 ;
     RECT  4.56 69.491 9.048 69.731 ;
     RECT  15.9 69.587 19.416 70.019 ;
     RECT  10.224 69.587 10.812 70.163 ;
     RECT  15.9 70.019 19.368 70.261 ;
     RECT  38.688 70.357 38.712 70.643 ;
     RECT  20.832 69.683 24.504 70.739 ;
     RECT  15.792 70.261 19.368 70.787 ;
     RECT  10.5 70.163 10.812 70.789 ;
     RECT  26.4 68.675 27.96 70.837 ;
     RECT  20.976 70.739 24.504 71.075 ;
     RECT  21.024 71.075 24.504 71.077 ;
     RECT  15.792 70.787 16.68 71.123 ;
     RECT  31.92 69.203 32.412 71.171 ;
     RECT  4.992 69.731 9.048 71.315 ;
     RECT  10.5 70.789 11.4 71.461 ;
     RECT  29.4 69.203 30.552 71.461 ;
     RECT  12.432 69.635 14.328 71.509 ;
     RECT  18.144 70.787 19.368 71.701 ;
     RECT  29.28 71.461 30.552 71.749 ;
     RECT  15.792 71.123 16.488 71.843 ;
     RECT  15.792 71.843 16.212 71.891 ;
     RECT  21.024 71.077 25.08 71.891 ;
     RECT  10.272 71.461 11.4 71.941 ;
     RECT  12.432 71.509 14.472 71.941 ;
     RECT  33.888 67.957 35.208 71.941 ;
     RECT  18.144 71.701 19.944 71.987 ;
     RECT  5.1 71.315 9.048 72.035 ;
     RECT  26.4 70.837 28.056 72.037 ;
     RECT  29.28 71.749 30.888 72.037 ;
     RECT  33.6 71.941 35.208 72.083 ;
     RECT  26.4 72.037 30.888 72.227 ;
     RECT  10.272 71.941 14.472 72.323 ;
     RECT  21.024 71.891 24.504 72.373 ;
     RECT  20.736 72.373 24.504 72.419 ;
     RECT  26.7 72.227 30.888 72.419 ;
     RECT  24 72.419 24.504 72.611 ;
     RECT  12.336 72.323 14.472 72.757 ;
     RECT  28.464 72.419 30.888 72.901 ;
     RECT  32.1 71.171 32.412 72.901 ;
     RECT  33.888 72.083 35.208 72.947 ;
     RECT  12.336 72.757 14.52 72.949 ;
     RECT  15.9 71.891 16.212 72.949 ;
     RECT  34.704 72.947 35.208 72.995 ;
     RECT  34.704 72.995 35.112 73.043 ;
     RECT  12.336 72.949 16.212 73.091 ;
     RECT  15.792 73.091 16.212 73.237 ;
     RECT  20.736 72.419 22.92 73.331 ;
     RECT  10.272 72.323 11.112 73.523 ;
     RECT  2.4 67.859 2.712 73.717 ;
     RECT  3.696 71.221 3.72 73.717 ;
     RECT  2.4 73.717 3.72 73.763 ;
     RECT  12.336 73.091 14.52 73.813 ;
     RECT  34.8 73.043 35.112 74.389 ;
     RECT  10.272 73.523 10.812 74.435 ;
     RECT  24 72.611 24.408 74.485 ;
     RECT  2.4 73.763 3.432 74.579 ;
     RECT  26.7 72.419 27.24 74.629 ;
     RECT  28.464 72.901 32.412 74.629 ;
     RECT  34.8 74.389 35.448 74.675 ;
     RECT  5.1 72.035 8.808 74.965 ;
     RECT  12.144 73.813 14.52 74.965 ;
     RECT  26.7 74.629 32.412 75.155 ;
     RECT  15.792 73.237 17.016 75.157 ;
     RECT  18.144 71.987 18.912 75.157 ;
     RECT  24 74.485 24.504 75.205 ;
     RECT  20.736 73.331 22.104 75.253 ;
     RECT  26.7 75.155 27.768 75.347 ;
     RECT  34.8 74.675 35.208 75.445 ;
     RECT  24 75.205 25.224 75.539 ;
     RECT  5.1 74.965 9.144 75.781 ;
     RECT  34.608 75.445 35.208 75.781 ;
     RECT  15.792 75.157 18.912 75.875 ;
     RECT  33.936 75.781 35.208 75.875 ;
     RECT  5.1 75.781 9.192 75.923 ;
     RECT  5.1 75.923 9.144 76.019 ;
     RECT  33.936 75.875 35.112 76.259 ;
     RECT  12.144 74.965 14.808 76.309 ;
     RECT  11.952 76.309 14.808 76.355 ;
     RECT  24 75.539 25.08 76.499 ;
     RECT  15.9 75.875 16.968 76.643 ;
     RECT  19.968 75.253 22.104 76.643 ;
     RECT  15.9 76.643 16.488 76.885 ;
     RECT  24 76.499 24.552 76.979 ;
     RECT  24 76.979 24.456 77.075 ;
     RECT  34.608 76.259 35.112 77.075 ;
     RECT  9.12 76.019 9.144 77.125 ;
     RECT  5.1 76.019 8.112 77.173 ;
     RECT  9.12 77.125 9.288 77.173 ;
     RECT  26.7 75.347 27.72 77.317 ;
     RECT  15.36 76.885 16.488 77.701 ;
     RECT  19.968 76.643 20.088 77.893 ;
     RECT  21.3 76.643 22.104 77.893 ;
     RECT  18.144 75.875 18.912 78.229 ;
     RECT  19.968 77.893 22.104 78.229 ;
     RECT  11.952 76.355 13.656 78.277 ;
     RECT  18.144 78.229 22.104 78.565 ;
     RECT  18.144 78.565 22.584 78.613 ;
     RECT  26.7 77.317 27.912 78.707 ;
     RECT  2.4 74.579 2.712 79.045 ;
     RECT  15.36 77.701 16.584 79.283 ;
     RECT  29.4 75.155 32.412 79.283 ;
     RECT  26.7 78.707 27.012 79.573 ;
     RECT  26.16 79.573 27.012 79.669 ;
     RECT  5.1 77.173 9.288 79.717 ;
     RECT  10.5 74.435 10.812 79.717 ;
     RECT  5.1 79.717 10.812 79.765 ;
     RECT  11.952 78.277 13.704 79.765 ;
     RECT  2.4 79.045 3.48 79.811 ;
     RECT  5.1 79.765 13.704 79.811 ;
     RECT  26.16 79.669 27.336 80.051 ;
     RECT  18.144 78.613 22.776 80.341 ;
     RECT  24 77.075 24.312 80.341 ;
     RECT  29.4 79.283 31.032 80.533 ;
     RECT  32.1 79.283 32.412 80.533 ;
     RECT  34.8 77.075 35.112 80.629 ;
     RECT  5.1 79.811 13.656 80.675 ;
     RECT  7.8 80.675 13.656 80.773 ;
     RECT  7.8 80.773 13.704 80.867 ;
     RECT  12.912 80.867 13.704 80.869 ;
     RECT  14.832 80.245 14.856 80.869 ;
     RECT  18.144 80.341 24.312 80.915 ;
     RECT  18.336 80.915 24.312 81.011 ;
     RECT  23.376 81.011 24.312 81.059 ;
     RECT  5.1 80.675 6.552 81.107 ;
     RECT  12.912 80.869 14.856 81.155 ;
     RECT  7.8 80.867 11.448 81.203 ;
     RECT  14.64 81.155 14.856 81.205 ;
     RECT  15.9 79.283 16.584 81.205 ;
     RECT  12.912 81.155 13.656 81.299 ;
     RECT  29.4 80.533 32.412 81.301 ;
     RECT  12.912 81.299 13.512 81.395 ;
     RECT  20.496 81.011 22.104 81.491 ;
     RECT  29.4 81.301 33.144 81.491 ;
     RECT  14.64 81.205 16.584 81.539 ;
     RECT  34.656 80.629 35.112 81.637 ;
     RECT  13.104 81.395 13.512 81.875 ;
     RECT  26.7 80.051 27.336 81.971 ;
     RECT  5.1 81.107 5.412 82.021 ;
     RECT  7.8 81.203 9.144 82.163 ;
     RECT  4.512 82.021 5.412 82.549 ;
     RECT  18.336 81.011 19.416 82.693 ;
     RECT  18.24 82.693 19.416 82.739 ;
     RECT  33.984 81.637 35.112 82.739 ;
     RECT  10.5 81.203 11.448 82.741 ;
     RECT  4.176 82.549 5.412 82.789 ;
     RECT  10.5 82.741 12.072 82.931 ;
     RECT  34.8 82.739 35.112 83.077 ;
     RECT  26.7 81.971 27.012 83.173 ;
     RECT  6.528 81.107 6.552 83.219 ;
     RECT  28.08 83.125 28.104 83.363 ;
     RECT  6.576 83.365 6.6 83.605 ;
     RECT  7.8 82.163 8.112 83.605 ;
     RECT  31.92 81.491 32.412 83.605 ;
     RECT  10.5 82.931 11.448 83.749 ;
     RECT  18.24 82.739 19.368 83.749 ;
     RECT  34.8 83.077 35.352 83.845 ;
     RECT  31.92 83.605 33.144 84.035 ;
     RECT  34.8 83.845 35.928 84.035 ;
     RECT  26.208 83.173 27.012 84.085 ;
     RECT  31.968 84.035 33.144 84.131 ;
     RECT  14.64 81.539 16.392 84.179 ;
     RECT  4.176 82.789 5.544 84.181 ;
     RECT  6.576 83.605 8.112 84.181 ;
     RECT  2.4 79.811 2.712 84.277 ;
     RECT  4.176 84.181 8.112 84.277 ;
     RECT  2.4 84.277 8.112 84.323 ;
     RECT  18.24 83.749 19.704 84.371 ;
     RECT  21.3 81.491 22.104 84.565 ;
     RECT  9.12 82.163 9.144 84.709 ;
     RECT  9.12 84.709 9.336 84.755 ;
     RECT  21.168 84.565 22.104 84.805 ;
     RECT  29.4 81.491 30.744 84.949 ;
     RECT  5.1 84.323 8.112 84.995 ;
     RECT  29.04 84.949 30.744 85.139 ;
     RECT  25.968 84.085 27.012 85.237 ;
     RECT  13.2 81.875 13.512 85.429 ;
     RECT  12.96 85.429 13.512 85.477 ;
     RECT  31.968 84.131 32.52 85.477 ;
     RECT  10.368 83.749 11.448 85.523 ;
     RECT  14.64 84.179 16.344 85.669 ;
     RECT  10.5 85.523 11.448 85.717 ;
     RECT  12.528 85.477 13.512 85.717 ;
     RECT  21.168 84.805 22.152 85.907 ;
     RECT  2.4 84.323 3.384 85.955 ;
     RECT  21.168 85.907 22.104 86.003 ;
     RECT  24 81.059 24.312 86.005 ;
     RECT  31.776 85.477 32.52 86.053 ;
     RECT  29.04 85.139 30.456 86.243 ;
     RECT  14.64 85.669 16.488 86.339 ;
     RECT  31.776 86.053 32.568 86.339 ;
     RECT  6.576 84.995 8.112 86.435 ;
     RECT  34.8 84.035 35.352 86.485 ;
     RECT  25.968 85.237 27.768 86.531 ;
     RECT  18.24 84.371 19.416 86.627 ;
     RECT  34.32 86.485 35.352 86.675 ;
     RECT  6.576 86.435 6.6 86.771 ;
     RECT  29.4 86.243 30.456 86.771 ;
     RECT  31.776 86.339 32.52 86.819 ;
     RECT  31.776 86.819 32.412 87.011 ;
     RECT  24 86.005 24.552 87.205 ;
     RECT  18.384 86.627 19.416 87.251 ;
     RECT  10.5 85.717 13.512 87.299 ;
     RECT  21.3 86.003 22.104 87.301 ;
     RECT  12 87.299 13.512 87.539 ;
     RECT  18.384 87.251 19.032 87.875 ;
     RECT  25.968 86.531 27.012 87.923 ;
     RECT  10.5 87.299 10.812 87.925 ;
     RECT  9.312 84.755 9.336 88.069 ;
     RECT  23.904 87.205 24.552 88.069 ;
     RECT  34.8 86.675 35.352 88.069 ;
     RECT  23.904 88.069 25.08 88.115 ;
     RECT  31.92 87.011 32.412 88.211 ;
     RECT  34.8 88.069 35.4 88.211 ;
     RECT  34.8 88.211 35.352 88.357 ;
     RECT  34.464 88.357 35.352 88.549 ;
     RECT  7.8 86.435 8.112 88.597 ;
     RECT  9.264 88.069 9.336 88.597 ;
     RECT  7.8 88.597 9.336 88.643 ;
     RECT  26.7 87.923 27.012 88.741 ;
     RECT  14.64 86.339 14.808 88.789 ;
     RECT  15.9 86.339 16.488 88.789 ;
     RECT  5.1 84.995 5.412 88.885 ;
     RECT  34.224 88.549 35.352 88.931 ;
     RECT  26.7 88.741 27.144 88.933 ;
     RECT  24 88.115 25.08 88.979 ;
     RECT  29.4 86.771 30.216 89.123 ;
     RECT  26.592 88.933 27.144 89.315 ;
     RECT  34.224 88.931 35.112 89.315 ;
     RECT  14.64 88.789 16.488 89.461 ;
     RECT  26.592 89.315 27.012 89.461 ;
     RECT  14.64 89.461 16.536 89.555 ;
     RECT  12.96 87.539 13.512 89.699 ;
     RECT  32.1 88.211 32.412 89.893 ;
     RECT  5.1 88.885 5.544 89.989 ;
     RECT  20.928 87.301 22.104 89.989 ;
     RECT  4.992 89.989 5.544 90.035 ;
     RECT  18.384 87.875 18.912 90.035 ;
     RECT  20.736 89.989 22.2 90.323 ;
     RECT  34.464 89.315 35.112 90.515 ;
     RECT  7.8 88.643 8.52 90.563 ;
     RECT  20.88 90.323 22.2 90.563 ;
     RECT  10.368 87.925 10.812 90.659 ;
     RECT  25.68 89.461 27.012 90.659 ;
     RECT  29.4 89.123 29.928 90.659 ;
     RECT  24 88.979 24.312 90.757 ;
     RECT  15.9 89.555 16.536 90.803 ;
     RECT  23.28 90.757 24.312 90.899 ;
     RECT  34.8 90.515 35.112 90.901 ;
     RECT  4.992 90.035 5.412 91.139 ;
     RECT  20.88 90.563 21.912 91.331 ;
     RECT  14.64 89.555 14.664 91.427 ;
     RECT  32.1 89.893 33.096 91.475 ;
     RECT  34.8 90.901 35.256 91.475 ;
     RECT  13.056 89.699 13.512 91.477 ;
     RECT  10.5 90.659 10.812 91.765 ;
     RECT  25.68 90.659 25.704 91.811 ;
     RECT  7.8 90.563 8.232 92.003 ;
     RECT  0.192 50.483 0.216 92.147 ;
     RECT  21.3 91.331 21.912 92.243 ;
     RECT  15.9 90.803 16.344 92.291 ;
     RECT  6.624 87.397 6.648 92.387 ;
     RECT  9.84 91.765 10.812 92.435 ;
     RECT  14.784 92.341 14.808 92.483 ;
     RECT  15.9 92.291 16.212 92.533 ;
     RECT  12.288 91.477 13.512 92.723 ;
     RECT  2.4 85.955 2.712 92.889 ;
     RECT  5.1 91.139 5.412 92.889 ;
     RECT  7.8 92.003 8.112 92.889 ;
     RECT  10.5 92.435 10.812 92.889 ;
     RECT  13.2 92.723 13.512 92.889 ;
     RECT  15.6 92.533 16.212 92.889 ;
     RECT  18.6 90.035 18.912 92.889 ;
     RECT  21.3 92.243 21.612 92.889 ;
     RECT  24 90.899 24.312 92.889 ;
     RECT  26.7 90.659 27.012 92.889 ;
     RECT  29.4 90.659 29.712 92.889 ;
     RECT  32.1 91.475 32.412 92.889 ;
     RECT  34.8 91.475 35.112 92.889 ;
     RECT  2.4 92.889 2.52 92.903 ;
     RECT  5.1 92.889 5.22 92.903 ;
     RECT  7.8 92.889 7.92 92.903 ;
     RECT  10.5 92.889 10.62 92.903 ;
     RECT  13.2 92.889 13.32 92.903 ;
     RECT  15.6 92.889 16.02 92.903 ;
     RECT  18.6 92.889 18.72 92.903 ;
     RECT  21.3 92.889 21.42 92.903 ;
     RECT  24 92.889 24.12 92.903 ;
     RECT  26.7 92.889 26.82 92.903 ;
     RECT  29.4 92.889 29.52 92.903 ;
     RECT  32.1 92.889 32.22 92.903 ;
     RECT  34.8 92.889 34.92 92.903 ;
     RECT  8.112 2.389 9.12 2.531 ;
     RECT  9.144 2.389 10.5 2.531 ;
     RECT  8.112 2.531 10.5 2.773 ;
     RECT  8.52 2.773 10.5 3.013 ;
     RECT  29.712 2.821 30.768 3.877 ;
     RECT  30.792 2.867 31.92 4.117 ;
     RECT  8.52 3.013 10.32 3.443 ;
     RECT  20.544 3.059 21.168 3.875 ;
     RECT  8.52 3.443 10.5 3.781 ;
     RECT  9.144 3.781 10.5 4.019 ;
     RECT  20.544 3.875 21.3 3.877 ;
     RECT  18.912 3.877 19.92 4.451 ;
     RECT  19.944 3.877 21.3 4.451 ;
     RECT  18.912 4.451 21.3 5.077 ;
     RECT  19.416 5.077 21.3 5.221 ;
     RECT  24.408 5.123 24.6 5.605 ;
     RECT  17.112 5.171 18.6 5.651 ;
     RECT  19.416 5.221 20.928 5.557 ;
     RECT  19.416 5.557 20.832 8.195 ;
     RECT  24.408 5.605 25.44 7.333 ;
     RECT  25.464 5.605 26.7 11.797 ;
     RECT  32.412 5.605 33.648 5.749 ;
     RECT  33.672 5.605 34.8 6.805 ;
     RECT  9.096 5.653 10.5 6.227 ;
     RECT  30.6 5.891 31.872 6.851 ;
     RECT  32.412 6.179 33.648 12.563 ;
     RECT  21.612 6.325 23.04 7.909 ;
     RECT  2.712 6.805 3.696 8.003 ;
     RECT  3.72 6.805 4.8 7.381 ;
     RECT  30.6 6.851 32.1 7.379 ;
     RECT  11.256 7.285 12.24 7.427 ;
     RECT  11.256 7.427 13.104 8.195 ;
     RECT  27.912 7.861 29.28 8.003 ;
     RECT  21.72 7.909 23.04 8.195 ;
     RECT  2.712 8.003 2.808 8.245 ;
     RECT  33.672 8.147 34.8 12.563 ;
     RECT  11.256 8.195 11.64 8.197 ;
     RECT  20.544 8.195 20.832 9.637 ;
     RECT  21.612 8.195 23.04 10.309 ;
     RECT  9.24 8.293 10.5 9.395 ;
     RECT  17.16 8.341 18.6 9.925 ;
     RECT  11.256 8.483 11.64 9.877 ;
     RECT  5.412 9.349 6.672 10.307 ;
     RECT  6.696 9.349 7.68 10.307 ;
     RECT  9.096 9.395 10.5 10.115 ;
     RECT  11.256 9.877 13.104 9.925 ;
     RECT  11.832 9.925 13.104 10.211 ;
     RECT  17.16 9.925 18.24 10.499 ;
     RECT  8.952 10.115 10.5 10.597 ;
     RECT  11.832 10.211 13.2 13.763 ;
     RECT  27.012 10.211 27.288 11.317 ;
     RECT  30.504 10.213 31.92 10.307 ;
     RECT  29.28 10.259 29.4 11.317 ;
     RECT  5.412 10.307 7.68 10.355 ;
     RECT  29.712 10.307 31.92 11.797 ;
     RECT  5.412 10.355 7.8 11.365 ;
     RECT  22.152 10.403 23.472 11.363 ;
     RECT  16.728 10.499 18.24 11.317 ;
     RECT  8.952 10.597 10.272 11.173 ;
     RECT  13.512 10.597 14.592 12.755 ;
     RECT  14.616 10.597 15.9 10.933 ;
     RECT  4.656 10.883 4.8 11.893 ;
     RECT  14.808 10.933 15.9 11.653 ;
     RECT  9.144 11.173 10.272 11.459 ;
     RECT  16.728 11.317 17.808 11.603 ;
     RECT  27.96 11.317 29.4 11.461 ;
     RECT  5.412 11.365 7.344 11.701 ;
     RECT  9.144 11.459 10.5 12.661 ;
     RECT  28.056 11.461 29.4 11.699 ;
     RECT  16.728 11.603 18.6 12.037 ;
     RECT  14.808 11.653 15.792 11.797 ;
     RECT  27.96 11.699 29.4 12.517 ;
     RECT  6.072 11.701 7.344 11.749 ;
     RECT  29.712 11.797 31.008 14.197 ;
     RECT  2.808 11.893 3.936 11.939 ;
     RECT  2.712 11.939 3.936 13.619 ;
     RECT  17.208 12.037 18.6 12.947 ;
     RECT  27.96 12.517 29.088 15.347 ;
     RECT  5.412 12.563 6.768 13.573 ;
     RECT  10.812 12.563 11.808 13.763 ;
     RECT  9.24 12.661 10.5 13.091 ;
     RECT  13.512 12.755 14.832 14.243 ;
     RECT  9.144 13.091 10.5 13.523 ;
     RECT  6.792 13.187 7.8 13.955 ;
     RECT  14.856 13.379 15.9 14.243 ;
     RECT  25.128 13.475 26.4 14.869 ;
     RECT  35.112 13.475 35.4 14.485 ;
     RECT  8.376 13.523 10.5 14.149 ;
     RECT  5.412 13.573 6.432 16.405 ;
     RECT  2.712 13.619 4.848 14.773 ;
     RECT  18.912 13.621 20.16 14.915 ;
     RECT  10.812 13.763 11.592 14.629 ;
     RECT  6.648 13.955 7.8 16.501 ;
     RECT  8.376 14.149 10.272 14.773 ;
     RECT  29.712 14.197 30.816 16.739 ;
     RECT  13.512 14.243 15.9 15.589 ;
     RECT  11.16 14.771 11.256 15.829 ;
     RECT  3.336 14.773 4.848 17.075 ;
     RECT  8.808 14.773 10.272 14.867 ;
     RECT  21.612 14.773 23.088 15.733 ;
     RECT  8.808 14.867 10.5 15.829 ;
     RECT  25.128 14.869 26.208 14.915 ;
     RECT  24.504 14.915 24.552 16.165 ;
     RECT  27.96 15.347 29.4 16.981 ;
     RECT  13.512 15.589 14.832 18.707 ;
     RECT  14.856 15.589 15.9 16.453 ;
     RECT  21.816 15.733 23.088 16.115 ;
     RECT  8.808 15.829 10.368 15.877 ;
     RECT  8.808 15.877 10.272 15.973 ;
     RECT  21.816 16.115 23.136 17.267 ;
     RECT  19.896 16.885 20.88 17.555 ;
     RECT  17.208 16.981 18.6 17.123 ;
     RECT  27.96 16.981 29.04 17.605 ;
     RECT  4.416 17.075 4.848 17.605 ;
     RECT  24.984 17.077 26.16 17.221 ;
     RECT  13.056 17.123 13.2 17.845 ;
     RECT  10.812 17.171 10.92 17.845 ;
     RECT  25.08 17.221 26.16 17.555 ;
     RECT  21.612 17.267 23.136 17.411 ;
     RECT  21.612 17.411 24 18.757 ;
     RECT  32.412 17.459 32.52 18.661 ;
     RECT  19.512 17.555 20.88 19.237 ;
     RECT  16.632 17.603 16.68 18.757 ;
     RECT  5.412 17.651 6.816 18.851 ;
     RECT  10.812 17.845 12.048 17.987 ;
     RECT  12.072 17.845 13.2 17.987 ;
     RECT  13.008 17.987 13.2 18.133 ;
     RECT  13.008 18.133 13.104 18.181 ;
     RECT  13.512 18.707 14.928 19.477 ;
     RECT  16.632 18.757 17.808 18.853 ;
     RECT  21.612 18.757 22.848 19.621 ;
     RECT  22.872 18.757 24 19.093 ;
     RECT  5.412 18.851 6.96 19.909 ;
     RECT  22.968 19.093 24 20.485 ;
     RECT  9.096 19.237 10.5 22.405 ;
     RECT  19.512 19.237 20.832 19.765 ;
     RECT  24.936 19.333 26.16 19.477 ;
     RECT  13.944 19.477 14.928 19.717 ;
     RECT  25.032 19.477 26.16 19.859 ;
     RECT  31.584 19.523 31.68 20.677 ;
     RECT  19.512 19.765 20.544 19.811 ;
     RECT  24.936 19.859 26.16 20.869 ;
     RECT  5.412 19.909 6.864 21.445 ;
     RECT  27.012 20.339 28.032 21.637 ;
     RECT  13.512 20.579 14.592 20.819 ;
     RECT  13.512 20.819 14.64 23.125 ;
     RECT  24.936 20.869 26.064 21.683 ;
     RECT  17.064 21.155 18.144 23.269 ;
     RECT  22.872 21.155 24 22.597 ;
     RECT  28.056 21.155 29.088 22.067 ;
     RECT  5.928 21.587 7.344 25.043 ;
     RECT  24.936 21.683 26.208 21.781 ;
     RECT  25.176 21.781 26.208 23.749 ;
     RECT  28.056 22.067 29.4 22.741 ;
     RECT  21.612 22.211 22.848 23.893 ;
     RECT  9.096 22.405 10.272 23.123 ;
     RECT  28.104 22.741 29.4 23.845 ;
     RECT  9.096 23.123 10.32 24.611 ;
     RECT  32.412 23.219 32.904 23.749 ;
     RECT  18.912 23.603 19.368 24.853 ;
     RECT  32.412 23.749 33.456 24.757 ;
     RECT  33.48 23.749 34.8 24.613 ;
     RECT  28.104 23.845 29.088 24.659 ;
     RECT  9.096 24.611 10.368 24.707 ;
     RECT  33.48 24.613 34.704 25.139 ;
     RECT  28.104 24.659 29.4 26.627 ;
     RECT  9.096 24.707 10.5 25.715 ;
     RECT  18.912 24.853 19.968 25.813 ;
     RECT  19.992 24.853 21.12 26.243 ;
     RECT  25.368 24.947 26.7 27.157 ;
     RECT  27.012 24.947 28.08 26.627 ;
     RECT  5.928 25.043 7.8 25.333 ;
     RECT  32.52 25.139 34.704 25.187 ;
     RECT  32.52 25.187 34.8 25.427 ;
     RECT  6.072 25.333 7.8 25.765 ;
     RECT  32.412 25.427 34.8 26.437 ;
     RECT  2.712 25.669 4.128 26.291 ;
     RECT  9.048 25.715 10.5 26.869 ;
     RECT  6.168 25.765 7.8 26.341 ;
     RECT  14.52 26.243 15.648 26.723 ;
     RECT  6.168 26.341 7.68 27.253 ;
     RECT  33.384 26.437 34.8 28.307 ;
     RECT  27.012 26.627 29.4 26.773 ;
     RECT  14.52 26.723 15.9 27.301 ;
     RECT  10.812 26.725 12.288 27.349 ;
     RECT  18.912 26.771 19.032 27.925 ;
     RECT  27.96 26.773 29.4 29.221 ;
     RECT  9.192 26.869 10.5 27.443 ;
     RECT  25.512 27.157 26.7 28.405 ;
     RECT  6.168 27.253 7.392 27.395 ;
     RECT  14.856 27.301 15.9 28.453 ;
     RECT  6.168 27.395 7.68 28.309 ;
     RECT  9.144 27.443 10.5 27.635 ;
     RECT  10.92 27.539 12.288 28.933 ;
     RECT  8.808 27.635 10.5 27.925 ;
     RECT  8.808 27.925 10.224 28.453 ;
     RECT  18.912 27.925 19.92 29.123 ;
     RECT  19.944 27.925 21.12 29.123 ;
     RECT  30.456 28.069 31.68 29.123 ;
     RECT  33.096 28.307 34.8 28.837 ;
     RECT  6.648 28.309 7.68 28.453 ;
     RECT  25.512 28.405 26.592 29.315 ;
     RECT  8.808 28.453 9.888 30.949 ;
     RECT  33.096 28.837 34.128 28.979 ;
     RECT  11.112 28.933 12.288 29.507 ;
     RECT  32.952 28.979 34.128 30.229 ;
     RECT  30.456 29.123 31.92 31.427 ;
     RECT  28.056 29.221 29.4 29.651 ;
     RECT  25.368 29.315 26.592 30.803 ;
     RECT  27.96 29.651 29.4 30.901 ;
     RECT  33 30.229 34.128 30.853 ;
     RECT  24.312 30.803 25.344 31.765 ;
     RECT  25.368 30.803 26.7 34.741 ;
     RECT  33.096 30.853 34.128 31.379 ;
     RECT  27.96 30.901 29.28 34.069 ;
     RECT  10.92 30.947 11.112 31.955 ;
     RECT  14.472 31.091 15.456 31.379 ;
     RECT  2.712 31.237 3.792 31.859 ;
     RECT  3.816 31.237 5.1 31.859 ;
     RECT  14.472 31.379 15.9 33.013 ;
     RECT  32.952 31.379 34.128 32.243 ;
     RECT  30.456 31.427 31.968 32.147 ;
     RECT  4.512 31.859 5.1 32.437 ;
     RECT  10.812 31.955 11.112 32.197 ;
     RECT  8.808 32.003 9.888 33.107 ;
     RECT  10.812 32.197 11.904 32.339 ;
     RECT  11.928 32.197 13.2 32.339 ;
     RECT  32.616 32.243 34.128 33.107 ;
     RECT  10.812 32.339 13.2 33.445 ;
     RECT  14.568 33.013 15.9 35.029 ;
     RECT  8.664 33.107 9.888 34.501 ;
     RECT  32.616 33.107 33.048 33.445 ;
     RECT  10.812 33.445 12.192 33.635 ;
     RECT  12.216 33.445 13.2 33.635 ;
     RECT  32.664 33.445 33.048 33.541 ;
     RECT  27.96 34.069 29.184 39.109 ;
     RECT  17.4 34.163 18.6 35.989 ;
     RECT  18.912 34.357 19.92 34.981 ;
     RECT  19.944 34.357 20.976 34.645 ;
     RECT  8.664 34.501 9.648 36.515 ;
     RECT  33.048 34.741 34.272 35.509 ;
     RECT  24.552 34.787 24.6 35.989 ;
     RECT  14.616 35.029 15.9 37.573 ;
     RECT  13.608 35.075 14.592 35.843 ;
     RECT  6.264 35.123 7.68 36.275 ;
     RECT  3.192 35.317 4.512 35.363 ;
     RECT  29.832 35.317 30.816 37.381 ;
     RECT  30.84 35.317 31.968 37.619 ;
     RECT  22.68 35.699 24 52.117 ;
     RECT  13.512 35.843 14.592 37.861 ;
     RECT  33.336 35.987 34.656 37.091 ;
     RECT  10.812 36.037 12.24 36.565 ;
     RECT  8.664 36.515 9.888 37.667 ;
     RECT  33.336 37.091 34.8 40.453 ;
     RECT  3.192 37.429 4.512 37.573 ;
     RECT  10.812 37.523 12.24 38.725 ;
     RECT  14.664 37.573 15.9 37.717 ;
     RECT  6.168 37.619 6.264 38.149 ;
     RECT  31.92 37.619 31.968 37.813 ;
     RECT  8.664 37.667 10.128 39.395 ;
     RECT  14.904 37.717 15.9 37.765 ;
     RECT  13.512 37.861 14.544 38.101 ;
     RECT  6.168 38.149 7.584 40.309 ;
     RECT  2.712 38.819 4.08 40.789 ;
     RECT  14.904 39.059 15.9 41.077 ;
     RECT  28.008 39.109 29.184 40.405 ;
     RECT  19.128 39.155 20.688 40.405 ;
     RECT  8.664 39.395 10.32 40.645 ;
     RECT  30.408 39.733 31.92 39.877 ;
     RECT  30.408 39.877 31.872 39.973 ;
     RECT  10.812 40.019 12.144 40.595 ;
     RECT  13.656 40.019 14.64 41.363 ;
     RECT  21.612 40.115 22.656 42.565 ;
     RECT  19.128 40.405 20.592 40.933 ;
     RECT  10.812 40.595 12.24 42.661 ;
     RECT  9.144 40.645 10.32 40.835 ;
     RECT  4.104 40.835 5.1 41.075 ;
     RECT  9.144 40.835 10.368 40.883 ;
     RECT  9.096 40.883 10.368 42.227 ;
     RECT  14.904 41.219 15.9 42.035 ;
     RECT  13.656 41.363 14.688 41.651 ;
     RECT  13.656 41.651 14.88 42.035 ;
     RECT  26.352 41.987 26.496 43.285 ;
     RECT  8.712 42.227 10.368 43.285 ;
     RECT  13.512 42.227 13.656 43.621 ;
     RECT  6.168 42.467 7.44 43.765 ;
     RECT  19.368 42.611 20.592 43.379 ;
     RECT  12.216 42.755 13.2 44.389 ;
     RECT  9.336 43.285 10.368 45.013 ;
     RECT  24.456 43.285 25.536 44.099 ;
     RECT  19.128 43.379 20.592 44.485 ;
     RECT  14.424 43.621 15.9 44.051 ;
     RECT  13.512 44.051 15.9 44.917 ;
     RECT  24.456 44.099 24.552 44.437 ;
     RECT  27.576 44.099 28.752 45.443 ;
     RECT  10.812 44.195 12.192 47.461 ;
     RECT  21.612 44.483 22.656 45.541 ;
     RECT  19.128 44.485 20.544 45.587 ;
     RECT  4.008 44.533 5.1 46.499 ;
     RECT  13.512 44.917 14.832 45.301 ;
     RECT  14.856 44.917 15.9 46.115 ;
     RECT  9.336 45.013 10.32 45.685 ;
     RECT  2.712 45.059 3.984 46.499 ;
     RECT  5.976 45.155 7.296 45.731 ;
     RECT  17.16 45.253 18.144 45.491 ;
     RECT  27.384 45.443 28.752 45.923 ;
     RECT  17.112 45.491 18.144 45.827 ;
     RECT  19.128 45.587 20.688 46.069 ;
     RECT  5.736 45.731 7.296 46.211 ;
     RECT  16.536 45.827 18.144 46.885 ;
     RECT  19.176 46.069 20.688 47.557 ;
     RECT  14.424 46.115 15.9 47.891 ;
     RECT  33.096 46.117 34.56 46.787 ;
     RECT  5.412 46.211 7.296 46.739 ;
     RECT  5.412 46.739 7.44 46.931 ;
     RECT  24.456 46.787 24.552 47.893 ;
     RECT  16.824 46.885 18.144 47.123 ;
     RECT  5.412 46.931 6.216 47.221 ;
     RECT  16.488 47.123 18.144 48.421 ;
     RECT  5.928 47.221 6.216 47.797 ;
     RECT  30.984 47.315 32.1 48.421 ;
     RECT  27.96 47.461 29.4 47.891 ;
     RECT  19.176 47.557 20.16 47.893 ;
     RECT  13.512 47.891 15.9 48.997 ;
     RECT  2.712 48.373 3.888 48.949 ;
     RECT  9.144 48.515 10.368 49.525 ;
     RECT  3.912 48.707 5.1 49.619 ;
     RECT  14.424 48.997 15.9 49.235 ;
     RECT  9.144 49.525 10.272 49.811 ;
     RECT  3.48 49.619 5.1 50.677 ;
     RECT  30.984 49.619 32.1 52.261 ;
     RECT  9.144 49.811 10.368 51.011 ;
     RECT  24.504 49.907 24.552 50.821 ;
     RECT  27.012 50.291 27.336 51.253 ;
     RECT  3.48 50.677 4.512 50.867 ;
     RECT  24.504 50.821 25.584 51.733 ;
     RECT  3.288 50.867 4.512 51.155 ;
     RECT  8.712 51.011 10.368 52.261 ;
     RECT  19.224 51.299 20.448 52.453 ;
     RECT  16.92 51.637 18.144 53.029 ;
     RECT  24.552 51.733 25.584 52.741 ;
     RECT  22.68 52.117 23.904 53.461 ;
     RECT  9.048 52.261 10.368 54.037 ;
     RECT  30.984 52.261 31.968 52.981 ;
     RECT  33.984 52.739 34.176 54.133 ;
     RECT  10.968 52.835 12.192 53.171 ;
     RECT  24.792 53.027 25.968 54.563 ;
     RECT  16.968 53.029 18.144 53.269 ;
     RECT  10.812 53.171 12.192 54.469 ;
     RECT  22.68 53.461 23.664 55.475 ;
     RECT  14.184 53.555 14.28 53.557 ;
     RECT  14.184 53.557 15.408 54.659 ;
     RECT  35.112 53.843 35.208 55.237 ;
     RECT  18.912 53.891 19.968 55.957 ;
     RECT  9.096 54.037 10.368 54.371 ;
     RECT  32.808 54.133 34.176 54.613 ;
     RECT  9.096 54.371 10.5 54.949 ;
     RECT  10.812 54.469 12.048 55.907 ;
     RECT  24.792 54.563 26.208 55.907 ;
     RECT  32.808 54.613 33.888 55.475 ;
     RECT  16.968 54.755 18.144 56.389 ;
     RECT  9.144 54.949 10.5 55.091 ;
     RECT  9.048 55.091 10.5 56.581 ;
     RECT  6.216 55.139 7.8 56.437 ;
     RECT  22.68 55.475 23.76 56.485 ;
     RECT  32.52 55.475 33.888 56.387 ;
     RECT  27.012 55.715 27.336 57.013 ;
     RECT  24.792 55.907 26.352 56.101 ;
     RECT  30.312 55.907 31.344 56.771 ;
     RECT  25.128 56.101 26.352 59.843 ;
     RECT  32.412 56.387 33.888 58.117 ;
     RECT  22.776 56.485 23.76 57.443 ;
     RECT  9.048 56.581 10.272 57.493 ;
     RECT  30.264 56.771 31.344 57.107 ;
     RECT  22.776 57.443 24 58.501 ;
     RECT  9.096 57.493 10.272 57.827 ;
     RECT  27.012 57.731 27.336 59.125 ;
     RECT  9.096 57.827 10.5 59.461 ;
     RECT  3.432 58.021 4.848 58.259 ;
     RECT  2.712 58.259 4.848 58.549 ;
     RECT  13.944 58.405 15.36 58.547 ;
     RECT  22.968 58.501 24 59.317 ;
     RECT  13.944 58.547 15.408 60.035 ;
     RECT  2.712 58.549 3.84 59.795 ;
     RECT  3.96 58.787 5.1 59.315 ;
     RECT  27.012 59.125 28.32 59.749 ;
     RECT  28.344 59.125 29.4 61.189 ;
     RECT  3.864 59.315 5.1 59.795 ;
     RECT  27.336 59.749 28.32 59.797 ;
     RECT  2.712 59.795 3.432 60.373 ;
     RECT  25.128 59.843 26.448 59.845 ;
     RECT  25.32 59.845 26.448 63.443 ;
     RECT  27.144 60.563 28.176 61.525 ;
     RECT  30.6 60.757 32.1 61.043 ;
     RECT  30.264 61.043 30.36 62.533 ;
     RECT  19.896 61.091 21.024 61.619 ;
     RECT  6.216 61.429 7.68 62.531 ;
     RECT  27.144 61.525 28.128 63.157 ;
     RECT  19.416 61.619 21.024 62.677 ;
     RECT  9.192 61.667 10.5 63.731 ;
     RECT  13.656 62.291 13.944 63.493 ;
     RECT  19.56 62.677 21.024 62.869 ;
     RECT  19.56 62.869 20.976 63.059 ;
     RECT  19.56 63.059 21.024 63.539 ;
     RECT  27.24 63.251 28.464 63.875 ;
     RECT  25.224 63.443 26.448 63.829 ;
     RECT  13.656 63.493 15.264 63.733 ;
     RECT  9.096 63.731 10.5 64.789 ;
     RECT  14.232 63.733 15.264 64.307 ;
     RECT  25.224 63.829 26.208 65.173 ;
     RECT  27.012 63.875 28.464 66.949 ;
     RECT  13.608 64.643 13.656 65.941 ;
     RECT  32.412 64.643 33.888 71.941 ;
     RECT  30.648 64.645 31.968 64.933 ;
     RECT  9.096 64.789 10.176 65.507 ;
     RECT  25.224 65.363 26.448 66.467 ;
     RECT  9.048 65.507 10.176 68.869 ;
     RECT  30.696 65.603 32.1 66.901 ;
     RECT  13.656 66.661 14.832 67.621 ;
     RECT  14.856 66.661 15.9 67.141 ;
     RECT  30.744 66.901 32.1 68.341 ;
     RECT  6.312 67.141 7.68 68.917 ;
     RECT  19.368 67.141 20.496 67.859 ;
     RECT  27.96 67.283 29.28 69.059 ;
     RECT  14.856 67.379 15.9 69.635 ;
     RECT  3.432 67.525 4.56 67.859 ;
     RECT  19.368 67.859 20.88 68.389 ;
     RECT  19.56 68.389 20.88 69.205 ;
     RECT  11.304 68.917 12.432 69.587 ;
     RECT  27.96 69.059 29.4 70.837 ;
     RECT  30.552 69.203 31.92 71.171 ;
     RECT  19.56 69.205 20.64 69.587 ;
     RECT  9.048 69.491 10.224 70.163 ;
     RECT  10.812 69.587 12.432 70.789 ;
     RECT  19.416 69.587 20.64 69.683 ;
     RECT  14.328 69.635 15.9 70.261 ;
     RECT  19.416 69.683 20.832 70.019 ;
     RECT  4.56 69.731 4.992 71.221 ;
     RECT  19.368 70.019 20.832 70.739 ;
     RECT  9.048 70.163 10.5 71.461 ;
     RECT  14.328 70.261 15.792 71.509 ;
     RECT  19.368 70.739 20.976 71.075 ;
     RECT  16.68 70.787 18.144 71.123 ;
     RECT  11.4 70.789 12.432 71.941 ;
     RECT  28.056 70.837 29.4 71.461 ;
     RECT  19.368 71.075 21.024 71.701 ;
     RECT  25.08 71.077 26.4 71.891 ;
     RECT  30.552 71.171 32.1 71.749 ;
     RECT  2.712 71.221 3.696 73.717 ;
     RECT  3.72 71.221 4.992 71.315 ;
     RECT  3.72 71.315 5.1 73.763 ;
     RECT  9.048 71.461 10.272 72.035 ;
     RECT  28.056 71.461 29.28 72.037 ;
     RECT  14.472 71.509 15.792 71.891 ;
     RECT  19.944 71.701 21.024 71.987 ;
     RECT  30.888 71.749 32.1 72.901 ;
     RECT  16.212 71.843 16.488 73.237 ;
     RECT  14.472 71.891 15.9 72.757 ;
     RECT  32.412 71.941 33.6 72.083 ;
     RECT  20.736 71.987 21.024 72.373 ;
     RECT  8.808 72.035 10.272 74.435 ;
     RECT  32.412 72.083 33.888 72.947 ;
     RECT  11.112 72.323 12.336 73.523 ;
     RECT  22.92 72.419 24 73.331 ;
     RECT  27.24 72.419 28.464 74.629 ;
     RECT  14.52 72.757 15.9 72.949 ;
     RECT  35.112 72.995 35.208 74.389 ;
     RECT  14.52 73.091 15.792 74.965 ;
     RECT  17.016 73.237 18.144 75.157 ;
     RECT  10.812 73.523 12.336 73.813 ;
     RECT  10.812 73.813 12.144 76.309 ;
     RECT  8.808 74.435 10.5 74.965 ;
     RECT  9.144 74.965 10.5 75.781 ;
     RECT  14.808 74.965 15.792 75.875 ;
     RECT  25.224 75.205 26.7 75.539 ;
     RECT  18.912 75.253 19.968 78.229 ;
     RECT  9.192 75.781 10.5 75.923 ;
     RECT  32.412 75.781 33.936 76.259 ;
     RECT  14.808 75.875 15.9 76.355 ;
     RECT  16.968 75.875 18.144 76.643 ;
     RECT  9.144 75.923 10.5 77.125 ;
     RECT  8.112 76.019 9.12 77.173 ;
     RECT  10.812 76.309 11.952 79.765 ;
     RECT  15.36 76.355 15.9 76.885 ;
     RECT  16.488 76.643 16.584 77.701 ;
     RECT  20.088 76.643 21.3 77.893 ;
     RECT  9.288 77.125 10.5 79.717 ;
     RECT  27.912 77.317 29.4 78.707 ;
     RECT  22.584 78.565 24 78.613 ;
     RECT  22.776 78.613 24 80.341 ;
     RECT  27.012 78.707 27.336 79.669 ;
     RECT  15.36 79.283 15.9 80.245 ;
     RECT  31.032 79.283 32.1 80.533 ;
     RECT  13.656 79.811 13.704 80.245 ;
     RECT  13.656 80.245 14.832 80.773 ;
     RECT  14.856 80.245 15.9 81.205 ;
     RECT  6.552 80.675 7.8 83.219 ;
     RECT  13.704 80.773 14.832 80.869 ;
     RECT  11.448 80.867 12.912 81.395 ;
     RECT  19.416 81.011 20.496 81.491 ;
     RECT  22.104 81.011 23.376 81.059 ;
     RECT  5.412 81.107 6.528 82.789 ;
     RECT  13.656 81.155 14.64 81.299 ;
     RECT  9.144 81.203 10.5 83.749 ;
     RECT  13.512 81.299 14.64 91.427 ;
     RECT  33.144 81.301 34.656 81.491 ;
     RECT  11.448 81.395 13.104 81.875 ;
     RECT  30.744 81.491 31.92 84.035 ;
     RECT  33.984 81.491 34.656 81.637 ;
     RECT  11.448 81.875 13.2 82.741 ;
     RECT  27.012 81.971 27.336 83.125 ;
     RECT  8.112 82.163 9.12 84.755 ;
     RECT  2.712 82.549 4.176 84.277 ;
     RECT  19.368 82.739 19.416 83.749 ;
     RECT  12.072 82.741 13.2 82.931 ;
     RECT  5.544 82.789 6.528 83.219 ;
     RECT  27.012 83.125 28.08 83.363 ;
     RECT  28.104 83.125 29.4 83.363 ;
     RECT  5.544 83.219 7.8 83.365 ;
     RECT  5.544 83.365 6.576 84.181 ;
     RECT  6.6 83.365 7.8 83.605 ;
     RECT  9.144 83.749 10.368 84.709 ;
     RECT  30.744 84.035 31.968 85.139 ;
     RECT  16.344 84.179 16.392 85.669 ;
     RECT  9.336 84.709 10.368 85.523 ;
     RECT  8.112 84.755 9.312 88.069 ;
     RECT  5.412 84.995 6.576 86.771 ;
     RECT  30.456 85.139 31.968 85.477 ;
     RECT  27.768 85.237 29.04 86.243 ;
     RECT  11.448 85.429 12.96 85.477 ;
     RECT  11.448 85.477 12.528 85.717 ;
     RECT  30.456 85.477 31.776 86.771 ;
     RECT  9.336 85.523 10.5 87.925 ;
     RECT  21.168 86.003 21.3 87.301 ;
     RECT  24.552 86.005 25.968 87.923 ;
     RECT  14.808 86.339 15.9 88.789 ;
     RECT  6.6 86.435 7.8 86.771 ;
     RECT  5.412 86.771 7.8 87.397 ;
     RECT  10.812 87.299 12 87.539 ;
     RECT  5.412 87.397 6.624 88.885 ;
     RECT  6.648 87.397 7.8 92.387 ;
     RECT  24.552 87.923 26.7 88.069 ;
     RECT  9.336 87.925 10.368 88.643 ;
     RECT  8.112 88.069 9.264 88.597 ;
     RECT  25.08 88.069 26.7 88.933 ;
     RECT  5.544 88.885 6.624 90.035 ;
     RECT  25.08 88.933 26.592 88.979 ;
     RECT  24.312 88.979 26.592 89.461 ;
     RECT  34.224 89.315 34.464 89.893 ;
     RECT  24.312 89.461 25.68 91.811 ;
     RECT  14.664 89.555 15.9 91.427 ;
     RECT  33.096 89.893 34.464 90.515 ;
     RECT  5.412 90.035 6.624 92.387 ;
     RECT  21.912 90.563 22.2 90.757 ;
     RECT  10.368 90.659 10.5 91.765 ;
     RECT  25.704 90.659 26.7 91.811 ;
     RECT  21.912 90.757 23.28 90.899 ;
     RECT  13.512 91.427 15.9 92.341 ;
     RECT  10.812 91.477 12.288 92.723 ;
     RECT  13.512 92.341 14.784 92.483 ;
     RECT  14.808 92.341 15.9 92.483 ;
     RECT  15.6 92.483 15.9 92.533 ;
  END
END dsfd_dvland_562
END LIBRARY
